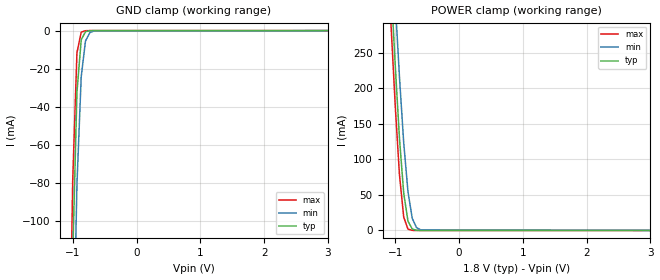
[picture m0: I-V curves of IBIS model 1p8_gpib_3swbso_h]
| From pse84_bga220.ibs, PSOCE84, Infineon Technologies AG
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[Model] 1p8_gpib_3swbso_h
Model_type Input
Vinl  =  0.54
Vinh  =  1.26
| Capacitance   typ   min   max
C_comp   6.99194e-13 6.84140e-13 7.17227e-13
| Variables   typ   min   max
[GND Clamp Reference]   0   0   0
[POWER Clamp Reference] 1.8   1.66   1.89
[Pulldown Reference]   0   0   0
[Pullup Reference]   1.8   1.66   1.89
[Temperature Range]   25   125   -40
[Voltage Range]   1.8   1.66   1.89
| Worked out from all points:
|   GND clamp passes 1 mA (typ) near -0.81 V on its own axis
|   POWER clamp passes 1 mA (typ) near -0.70 V on its own axis
[GND Clamp]
| Voltage   I(typ)   I(min)   I(max)
-1.271V   -777.1mA   -829.3mA   -749.6mA
-1.07V    -257.1mA   -325.7mA   -215.4mA
-1.003V   -118.8mA   -185.7mA   -78.49mA
-936.6mV  -32.29mA   -80.6mA    -11.59mA
-869.7mV  -4.869mA   -24.21mA   -835.1uA
-802.8mV  -582uA     -5.497mA   -52.94uA
-735.9mV  -66.76uA   -1.124mA   -3.324uA
-669mV    -7.618uA   -222.9uA   -208.7nA
3.6V      0A         0A         0A
[POWER Clamp]
| Voltage   I(typ)   I(min)   I(max)
-1.338V   832.1mA    908.1mA    786.4mA
-1.07V    347.5mA    436.2mA    291.6mA
-1.003V   233mA      322.8mA    176.2mA
-936.6mV  130.1mA    216.4mA    78.6mA
-869.7mV  52.48mA    123.5mA    18.89mA
-802.8mV  13.16mA    54.42mA    1.861mA
-735.9mV  2.014mA    17.13mA    126.6uA
-669mV    240.8uA    4.031mA    8.263uA
-602.1mV  27.35uA    812uA      536.8nA
3.6V      0A         0A         0A
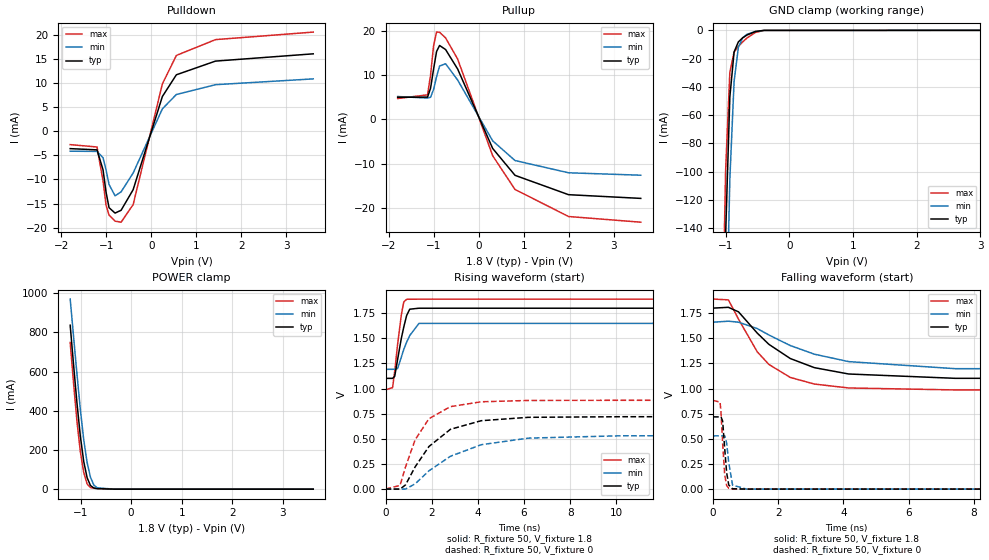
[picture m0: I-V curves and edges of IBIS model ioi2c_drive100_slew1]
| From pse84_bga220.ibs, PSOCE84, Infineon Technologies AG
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[Model] ioi2c_drive100_slew1
Model_type I/O
Enable   Active-High
Vinl  =  0.54
Vinh  =  1.26
Vmeas =  0.9
Cref  =  15e-12
| Capacitance   typ   min   max
C_comp   8.55364e-13 8.30808e-13 8.84570e-13
| Variables   typ   min   max
[GND Clamp Reference]   0   0   0
[POWER Clamp Reference]   1.8   1.66   1.89
[Pulldown Reference]   0   0   0
[Pullup Reference]   1.8   1.66   1.89
[Temperature Range]   25   125   -40
[Voltage Range]   1.8   1.66   1.89
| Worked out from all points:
|   slope of the pulldown table from 0 to 0.27 V, typ, clamps not added: 35.3 ohm
|   slope of the pullup table from 0 to 0.27 V, typ, clamps not added: 46.3 ohm
|   GND clamp passes 1 mA (typ) near -0.55 V on its own axis
|   POWER clamp passes 1 mA (typ) near -0.55 V on its own axis
|   falling waveform, R_fixture 50, V_fixture 1.8: 20-80 % time 1.72ns typ, 2.32ns min, 1.27ns max; typ from 1.8 V to 1.1 V
|   falling waveform, R_fixture 50, V_fixture 0: 20-80 % time 102ps typ, 118ps min, 94.2ps max; typ from 0.719 V to 0 V
|   rising waveform, R_fixture 50, V_fixture 1.8: 20-80 % time 348ps typ, 487ps min, 274ps max; typ from 1.1 V to 1.8 V
|   rising waveform, R_fixture 50, V_fixture 0: 20-80 % time 1.56ns typ, 2.35ns min, 1.1ns max; typ from 0 V to 0.719 V
[GND Clamp]
| Voltage   I(typ)   I(min)   I(max)
-1.204V   -750.5mA   -844.3mA   -692.2mA
-1.07V    -311.8mA   -416.8mA   -250.3mA
-1.003V   -144.6mA   -236.7mA   -99.35mA
-936.6mV  -47.15mA   -105.3mA   -29.57mA
-869.7mV  -15.32mA   -36.11mA   -15.4mA
-802.8mV  -8.178mA   -12.13mA   -11.32mA
-735.9mV  -5.345mA   -5.294mA   -8.218mA
-669mV    -3.361mA   -2.852mA   -5.471mA
-535.2mV  -838.5uA   -772.4uA   -1.486mA
-401.4mV  -47.36uA   -84.85uA   -76.78uA
3.6V      0A         0A         0A
[POWER Clamp]
| Voltage   I(typ)   I(min)   I(max)
-1.204V   837.3mA    970.7mA    749.2mA
-1.137V   634.9mA    778.2mA    540.5mA
-1.07V    440.1mA    587.4mA    346.5mA
-1.003V   270mA      407mA      190.9mA
-936.6mV  141.8mA    252.7mA    85.92mA
-869.7mV  58.74mA    136.5mA    26.66mA
-802.8mV  18.35mA    60.36mA    8.197mA
-735.9mV  5.885mA    21mA       4.755mA
-669mV    2.866mA    6.628mA    3.138mA
-334.5mV  12.31uA    45.7uA     5.857uA
3.6V      0A         0A         0A
[Pulldown]
| Voltage   I(typ)   I(min)   I(max)
-1.8V     -3.608mA   -4.143mA   -2.775mA
-1.204V   -3.867mA   -4.18mA    -3.269mA
-1.07V    -8mA       -5.505mA   -10.32mA
-1.003V   -12.65mA   -8.02mA    -15.35mA
-936.6mV  -15.86mA   -11.04mA   -17.4mA
-802.8mV  -16.98mA   -13.4mA    -18.65mA
-669mV    -16.4mA    -12.58mA   -18.87mA
-401.4mV  -12.13mA   -8.671mA   -15.23mA
248.3mV   7.209mA    4.643mA    9.816mA
558.6mV   11.71mA    7.622mA    15.72mA
1.428V    14.55mA    9.657mA    19.01mA
3.6V      16.06mA    10.86mA    20.57mA
[Pullup]
| Voltage   I(typ)   I(min)   I(max)
-1.8V     5.02mA     5.203mA    4.747mA
-1.137V   5.069mA    4.844mA    5.585mA
-1.07V    7.067mA    5.033mA    10.06mA
-1.003V   11.43mA    6.798mA    16.72mA
-936.6mV  15.41mA    9.704mA    19.82mA
-869.7mV  16.78mA    12.12mA    19.79mA
-735.9mV  15.86mA    12.64mA    18.49mA
-468.3mV  11.44mA    8.947mA    13.7mA
310.3mV   -6.586mA   -4.859mA   -8.233mA
806.9mV   -12.68mA   -9.32mA    -15.89mA
1.996V    -17.07mA   -12.1mA    -22.02mA
3.6V      -17.91mA   -12.65mA   -23.31mA
[Ramp]
dV/dt_r   0.431323/1.56487n  0.318021/2.34952n  0.529265/1.09605n
dV/dt_f   0.41961/1.72396n  0.28143/2.32368n  0.541744/1.26921n
R_load = 50
[Falling Waveform]
R_fixture = 50
V_fixture = 1.8
V_fixture_min = 1.66
V_fixture_max = 1.89
| Time   V(typ)   V(min)   V(max)
0s        1.8V       1.66V      1.89V
470.7ps   1.808V     1.67V      1.882V
781.4ps   1.763V     1.66V      1.69V
1.355ns   1.552V     1.597V     1.366V
1.713ns   1.44V      1.533V     1.24V
2.369ns   1.299V     1.428V     1.111V
3.11ns    1.208V     1.342V     1.045V
4.164ns   1.145V     1.268V     1.006V
7.432ns   1.102V     1.198V     986.6mV
800ns     1.101V     1.191V     987.1mV
[Falling Waveform]
R_fixture = 50
V_fixture = 0
V_fixture_min = 0
V_fixture_max = 0
| Time   V(typ)   V(min)   V(max)
0s        718.9mV    530mV      882.1mV
215.6ps   718.6mV    530mV      865.3mV
242.6ps   719mV      530mV      766.8mV
294.4ps   676.9mV    529.9mV    453.4mV
358.3ps   399.6mV    530.6mV    138.3mV
417.5ps   162.5mV    456.8mV    36.18mV
481.2ps   41.68mV    264.5mV    9.263mV
598.4ps   4.024mV    40.29mV    1.708mV
1.026ns   845.9uV    753.4uV    624.7uV
800ns     8.443nV    562.7nV    3.204nV
[Rising Waveform]
R_fixture = 50
V_fixture = 1.8
V_fixture_min = 1.66
V_fixture_max = 1.89
| Time   V(typ)   V(min)   V(max)
0s        1.101V     1.191V     987.1mV
305.5ps   1.101V     1.191V     1.009V
397.1ps   1.122V     1.191V     1.171V
521.6ps   1.288V     1.199V     1.438V
684.6ps   1.5V       1.313V     1.734V
789.3ps   1.611V     1.389V     1.862V
915.4ps   1.728V     1.462V     1.888V
1.048ns   1.789V     1.527V     1.888V
1.448ns   1.799V     1.648V     1.889V
800ns     1.8V       1.66V      1.89V
[Rising Waveform]
R_fixture = 50
V_fixture = 0
V_fixture_min = 0
V_fixture_max = 0
| Time   V(typ)   V(min)   V(max)
0s        8.444nV    562.4nV    3.204nV
628.8ps   -895.6uV   -1.322mV   35.62mV
865.3ps   41.36mV    -35.9uV    219.7mV
1.282ns   220.5mV    51.63mV    490.5mV
1.881ns   423.3mV    181.2mV    699.7mV
2.809ns   594.1mV    325.9mV    819.8mV
4.145ns   679.8mV    440.9mV    868.1mV
6.181ns   713.4mV    506.5mV    881.2mV
10.21ns   719.5mV    529.9mV    882.9mV
50ns      718.9mV    530mV      882.1mV
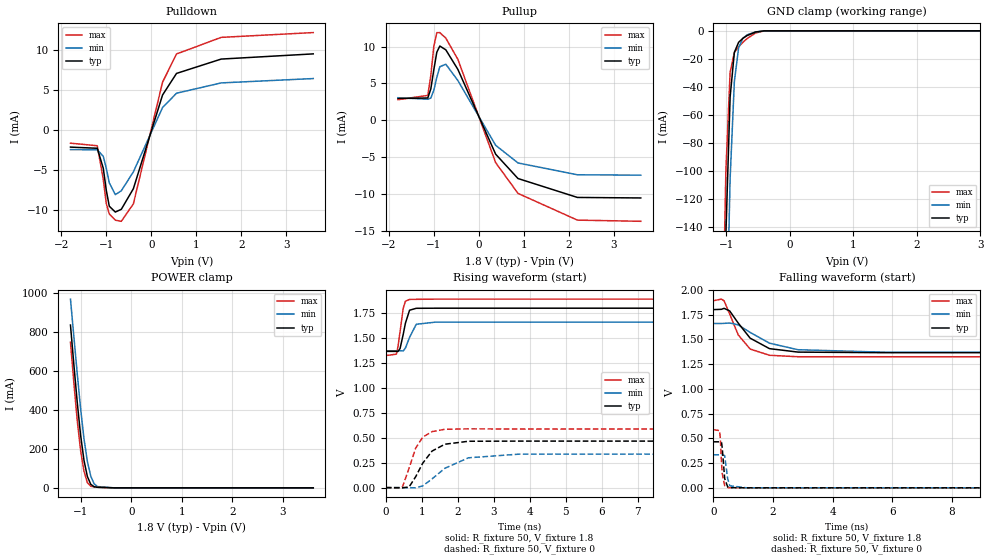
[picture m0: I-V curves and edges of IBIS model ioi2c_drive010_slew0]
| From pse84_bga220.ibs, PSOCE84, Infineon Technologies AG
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[Model] ioi2c_drive010_slew0
Model_type I/O
Enable   Active-High
Vinl  =  0.54
Vinh  =  1.26
Vmeas =  0.9
Cref  =  15e-12
| Capacitance   typ   min   max
C_comp   8.55364e-13 8.30808e-13 8.84570e-13
| Variables   typ   min   max
[GND Clamp Reference]   0   0   0
[POWER Clamp Reference]   1.8   1.66   1.89
[Pulldown Reference]   0   0   0
[Pullup Reference]   1.8   1.66   1.89
[Temperature Range]   25   125   -40
[Voltage Range]   1.8   1.66   1.89
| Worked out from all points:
|   slope of the pulldown table from 0 to 0.27 V, typ, clamps not added: 58.4 ohm
|   slope of the pullup table from 0 to 0.27 V, typ, clamps not added: 76.8 ohm
|   GND clamp passes 1 mA (typ) near -0.55 V on its own axis
|   POWER clamp passes 1 mA (typ) near -0.55 V on its own axis
|   falling waveform, R_fixture 50, V_fixture 1.8: 20-80 % time 778ps typ, 1.12ns min, 569ps max; typ from 1.8 V to 1.37 V
|   falling waveform, R_fixture 50, V_fixture 0: 20-80 % time 73.3ps typ, 82.5ps min, 68.5ps max; typ from 0.465 V to 0 V
|   rising waveform, R_fixture 50, V_fixture 1.8: 20-80 % time 150ps typ, 196ps min, 125ps max; typ from 1.37 V to 1.8 V
|   rising waveform, R_fixture 50, V_fixture 0: 20-80 % time 501ps typ, 796ps min, 356ps max; typ from 0 V to 0.465 V
[GND Clamp]
| Voltage   I(typ)   I(min)   I(max)
-1.204V   -750.5mA   -844.3mA   -692.2mA
-1.07V    -311.8mA   -416.8mA   -250.3mA
-1.003V   -144.6mA   -236.7mA   -99.35mA
-936.6mV  -47.15mA   -105.3mA   -29.57mA
-869.7mV  -15.32mA   -36.11mA   -15.4mA
-802.8mV  -8.178mA   -12.13mA   -11.32mA
-735.9mV  -5.345mA   -5.294mA   -8.218mA
-669mV    -3.361mA   -2.852mA   -5.471mA
-535.2mV  -838.5uA   -772.4uA   -1.486mA
-401.4mV  -47.36uA   -84.85uA   -76.78uA
3.6V      0A         0A         0A
[POWER Clamp]
| Voltage   I(typ)   I(min)   I(max)
-1.204V   837.3mA    970.7mA    749.2mA
-1.137V   634.9mA    778.2mA    540.5mA
-1.07V    440.1mA    587.4mA    346.5mA
-1.003V   270mA      407mA      190.9mA
-936.6mV  141.8mA    252.7mA    85.92mA
-869.7mV  58.74mA    136.5mA    26.66mA
-802.8mV  18.35mA    60.36mA    8.197mA
-735.9mV  5.885mA    21mA       4.755mA
-669mV    2.866mA    6.628mA    3.138mA
-334.5mV  12.31uA    45.7uA     5.857uA
3.6V      0A         0A         0A
[Pulldown]
| Voltage   I(typ)   I(min)   I(max)
-1.8V     -2.132mA   -2.444mA   -1.643mA
-1.204V   -2.279mA   -2.463mA   -1.96mA
-1.07V    -4.767mA   -3.283mA   -6.143mA
-1.003V   -7.525mA   -4.772mA   -9.15mA
-936.6mV  -9.492mA   -6.579mA   -10.45mA
-802.8mV  -10.22mA   -8.048mA   -11.23mA
-669mV    -9.874mA   -7.568mA   -11.37mA
-401.4mV  -7.319mA   -5.22mA    -9.208mA
248.3mV   4.356mA    2.795mA    5.95mA
558.6mV   7.043mA    4.577mA    9.465mA
1.552V    8.83mA     5.862mA    11.53mA
3.6V      9.476mA    6.404mA    12.13mA
[Pullup]
| Voltage   I(typ)   I(min)   I(max)
-1.8V     2.946mA    3.054mA    2.787mA
-1.137V   3.017mA    2.847mA    3.365mA
-1.07V    4.244mA    3.002mA    6.052mA
-1.003V   6.848mA    4.069mA    10.02mA
-936.6mV  9.232mA    5.804mA    11.89mA
-869.7mV  10.07mA    7.26mA     11.9mA
-735.9mV  9.553mA    7.601mA    11.14mA
-468.3mV  6.898mA    5.392mA    8.266mA
372.4mV   -4.617mA   -3.408mA   -5.769mA
869mV     -7.921mA   -5.806mA   -9.94mA
2.191V    -10.49mA   -7.414mA   -13.57mA
3.6V      -10.56mA   -7.462mA   -13.73mA
[Ramp]
dV/dt_r   0.279116/0.500541n  0.200595/0.796195n  0.352378/0.356306n
dV/dt_f   0.260514/0.777934n  0.172747/1.12479n  0.339364/0.569284n
R_load = 50
[Falling Waveform]
R_fixture = 50
V_fixture = 1.8
V_fixture_min = 1.66
V_fixture_max = 1.89
| Time   V(typ)   V(min)   V(max)
0s        1.8V       1.66V      1.89V
267.3ps   1.803V     1.66V      1.906V
359.2ps   1.813V     1.661V     1.889V
546ps     1.787V     1.665V     1.756V
833.4ps   1.664V     1.646V     1.545V
1.232ns   1.512V     1.57V      1.402V
1.881ns   1.406V     1.461V     1.339V
2.84ns    1.371V     1.395V     1.324V
5.742ns   1.365V     1.37V      1.324V
800ns     1.366V     1.372V     1.324V
[Falling Waveform]
R_fixture = 50
V_fixture = 0
V_fixture_min = 0
V_fixture_max = 0
| Time   V(typ)   V(min)   V(max)
0s        465.2mV    334.3mV    587.3mV
208.4ps   465.1mV    334.3mV    578.4mV
232.5ps   465mV      334.3mV    500.9mV
272.7ps   459mV      334.3mV    257mV
297.6ps   404mV      334.1mV    145.2mV
379.1ps   93.52mV    325.4mV    21.53mV
479.7ps   10.05mV    91.96mV    2.381mV
550.2ps   2.539mV    20.98mV    1.314mV
1.119ns   534.5uV    706.6uV    369.3uV
800ns     11.23nV    709.4nV    4.431nV
[Rising Waveform]
R_fixture = 50
V_fixture = 1.8
V_fixture_min = 1.66
V_fixture_max = 1.89
| Time   V(typ)   V(min)   V(max)
0s        1.366V     1.372V     1.324V
291.5ps   1.366V     1.372V     1.338V
337ps     1.365V     1.372V     1.413V
394.7ps   1.394V     1.372V     1.563V
482.5ps   1.537V     1.371V     1.798V
544ps     1.649V     1.4V       1.869V
659.2ps   1.779V     1.507V     1.887V
844.9ps   1.798V     1.638V     1.888V
1.372ns   1.799V     1.659V     1.89V
800ns     1.8V       1.66V      1.89V
[Rising Waveform]
R_fixture = 50
V_fixture = 0
V_fixture_min = 0
V_fixture_max = 0
| Time   V(typ)   V(min)   V(max)
0s        11.24nV    709.2nV    4.431nV
454.1ps   -2.613mV   220.8uV    -70.75uV
644.6ps   5.899mV    -2.007mV   194.2mV
828.9ps   109.3mV    -1.994mV   395.6mV
1.025ns   245.3mV    17.4mV     506.8mV
1.284ns   366.3mV    87.33mV    561.1mV
1.64ns    435.1mV    193.9mV    584.9mV
2.296ns   464.7mV    298.8mV    589.2mV
3.709ns   466.2mV    335.7mV    587.2mV
50ns      465.2mV    334.3mV    587.3mV
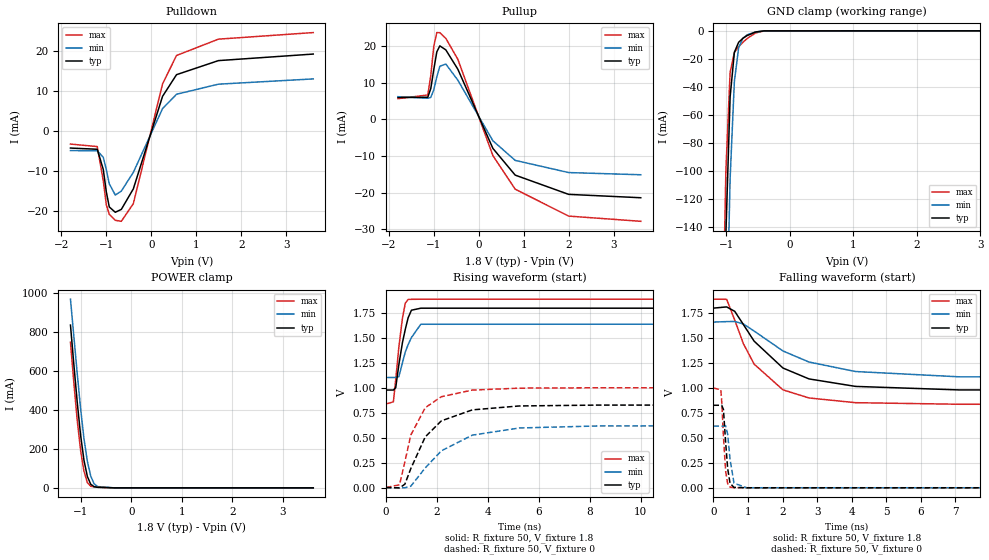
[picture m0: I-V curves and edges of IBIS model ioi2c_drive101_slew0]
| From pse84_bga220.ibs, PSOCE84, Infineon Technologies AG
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[Model] ioi2c_drive101_slew0
Model_type I/O
Enable   Active-High
Vinl  =  0.54
Vinh  =  1.26
Vmeas =  0.9
Cref  =  15e-12
| Capacitance   typ   min   max
C_comp   8.55364e-13 8.30808e-13 8.84570e-13
| Variables   typ   min   max
[GND Clamp Reference]   0   0   0
[POWER Clamp Reference]   1.8   1.66   1.89
[Pulldown Reference]   0   0   0
[Pullup Reference]   1.8   1.66   1.89
[Temperature Range]   25   125   -40
[Voltage Range]   1.8   1.66   1.89
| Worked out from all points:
|   slope of the pulldown table from 0 to 0.27 V, typ, clamps not added: 29.4 ohm
|   slope of the pullup table from 0 to 0.27 V, typ, clamps not added: 38.6 ohm
|   GND clamp passes 1 mA (typ) near -0.55 V on its own axis
|   POWER clamp passes 1 mA (typ) near -0.55 V on its own axis
|   falling waveform, R_fixture 50, V_fixture 1.8: 20-80 % time 1.48ns typ, 1.99ns min, 1.08ns max; typ from 1.8 V to 0.978 V
|   falling waveform, R_fixture 50, V_fixture 0: 20-80 % time 104ps typ, 119ps min, 95.7ps max; typ from 0.827 V to 0 V
|   rising waveform, R_fixture 50, V_fixture 1.8: 20-80 % time 340ps typ, 475ps min, 266ps max; typ from 0.978 V to 1.8 V
|   rising waveform, R_fixture 50, V_fixture 0: 20-80 % time 1.19ns typ, 1.69ns min, 833ps max; typ from 0 V to 0.827 V
[GND Clamp]
| Voltage   I(typ)   I(min)   I(max)
-1.204V   -750.5mA   -844.3mA   -692.2mA
-1.07V    -311.8mA   -416.8mA   -250.3mA
-1.003V   -144.6mA   -236.7mA   -99.35mA
-936.6mV  -47.15mA   -105.3mA   -29.57mA
-869.7mV  -15.32mA   -36.11mA   -15.4mA
-802.8mV  -8.178mA   -12.13mA   -11.32mA
-735.9mV  -5.345mA   -5.294mA   -8.218mA
-669mV    -3.361mA   -2.852mA   -5.471mA
-535.2mV  -838.5uA   -772.4uA   -1.486mA
-401.4mV  -47.36uA   -84.85uA   -76.78uA
3.6V      0A         0A         0A
[POWER Clamp]
| Voltage   I(typ)   I(min)   I(max)
-1.204V   837.3mA    970.7mA    749.2mA
-1.137V   634.9mA    778.2mA    540.5mA
-1.07V    440.1mA    587.4mA    346.5mA
-1.003V   270mA      407mA      190.9mA
-936.6mV  141.8mA    252.7mA    85.92mA
-869.7mV  58.74mA    136.5mA    26.66mA
-802.8mV  18.35mA    60.36mA    8.197mA
-735.9mV  5.885mA    21mA       4.755mA
-669mV    2.866mA    6.628mA    3.138mA
-334.5mV  12.31uA    45.7uA     5.857uA
3.6V      0A         0A         0A
[Pulldown]
| Voltage   I(typ)   I(min)   I(max)
-1.8V     -4.313mA   -4.952mA   -3.319mA
-1.204V   -4.62mA    -4.994mA   -3.945mA
-1.07V    -9.684mA   -6.635mA   -12.52mA
-1.003V   -15.27mA   -9.668mA   -18.47mA
-936.6mV  -19.06mA   -13.28mA   -20.91mA
-802.8mV  -20.39mA   -16.08mA   -22.4mA
-669mV    -19.67mA   -15.09mA   -22.65mA
-401.4mV  -14.52mA   -10.39mA   -18.23mA
248.3mV   8.629mA    5.565mA    11.75mA
558.6mV   14.05mA    9.146mA    18.85mA
1.49V     17.57mA    11.67mA    22.94mA
3.6V      19.21mA    12.99mA    24.59mA
[Pullup]
| Voltage   I(typ)   I(min)   I(max)
-1.8V     6.006mA    6.225mA    5.68mA
-1.137V   6.075mA    5.796mA    6.701mA
-1.07V    8.479mA    6.033mA    12.08mA
-1.003V   13.71mA    8.152mA    20.05mA
-936.6mV  18.47mA    11.64mA    23.75mA
-869.7mV  20.11mA    14.53mA    23.72mA
-735.9mV  19.02mA    15.15mA    22.17mA
-468.3mV  13.72mA    10.73mA    16.43mA
310.3mV   -7.896mA   -5.827mA   -9.87mA
806.9mV   -15.21mA   -11.18mA   -19.05mA
1.996V    -20.47mA   -14.51mA   -26.41mA
3.6V      -21.39mA   -15.11mA   -27.83mA
[Ramp]
dV/dt_r   0.496329/1.18642n  0.371382/1.69196n  0.599967/0.83335n
dV/dt_f   0.493097/1.48078n  0.333342/1.98689n  0.631402/1.07999n
R_load = 50
[Falling Waveform]
R_fixture = 50
V_fixture = 1.8
V_fixture_min = 1.66
V_fixture_max = 1.89
| Time   V(typ)   V(min)   V(max)
0s        1.8V       1.66V      1.89V
383.8ps   1.812V     1.665V     1.888V
617.5ps   1.768V     1.666V     1.681V
869.2ps   1.635V     1.641V     1.443V
1.179ns   1.469V     1.57V      1.239V
2.012ns   1.2V       1.371V     981.6mV
2.765ns   1.091V     1.26V      900.2mV
4.111ns   1.016V     1.165V     853mV
7.11ns    980.7mV    1.112V     837.2mV
800ns     978.2mV    1.104V     837.7mV
[Falling Waveform]
R_fixture = 50
V_fixture = 0
V_fixture_min = 0
V_fixture_max = 0
| Time   V(typ)   V(min)   V(max)
0s        827.2mV    619mV      999.9mV
215ps     827mV      619mV      982.6mV
240.1ps   827.3mV    619mV      874.8mV
291.2ps   786mV      618.9mV    514.9mV
355ps     455.1mV    620.3mV    166.3mV
413.3ps   194.8mV    537.9mV    42.4mV
482.1ps   46.06mV    286.9mV    8.046mV
596.6ps   4.798mV    46.85mV    1.729mV
965.3ps   1.013mV    1.148mV    678.8uV
800ns     7.509nV    510nV      2.81nV
[Rising Waveform]
R_fixture = 50
V_fixture = 1.8
V_fixture_min = 1.66
V_fixture_max = 1.89
| Time   V(typ)   V(min)   V(max)
0s        978.2mV    1.104V     837.7mV
297.1ps   978.4mV    1.104V     860.1mV
387.6ps   1.002V     1.105V     1.084V
510.2ps   1.232V     1.112V     1.407V
652.4ps   1.455V     1.253V     1.7V
764.3ps   1.588V     1.361V     1.85V
875ps     1.703V     1.434V     1.887V
1.005ns   1.779V     1.505V     1.888V
1.373ns   1.799V     1.638V     1.889V
800ns     1.8V       1.66V      1.89V
[Rising Waveform]
R_fixture = 50
V_fixture = 0
V_fixture_min = 0
V_fixture_max = 0
| Time   V(typ)   V(min)   V(max)
0s        7.51nV     509.8nV    2.812nV
538.1ps   -2.813mV   -1.349mV   28.66mV
746.5ps   33.87mV    -2.094mV   257.5mV
981.5ps   191.1mV    13.99mV    527.8mV
1.547ns   508.5mV    197.3mV    801.1mV
2.179ns   669.3mV    368.6mV    911.5mV
3.393ns   779.2mV    525.9mV    977.7mV
5.242ns   818.6mV    597.7mV    997.3mV
8.334ns   827.3mV    618mV      1.001V
50ns      827.2mV    619mV      999.9mV
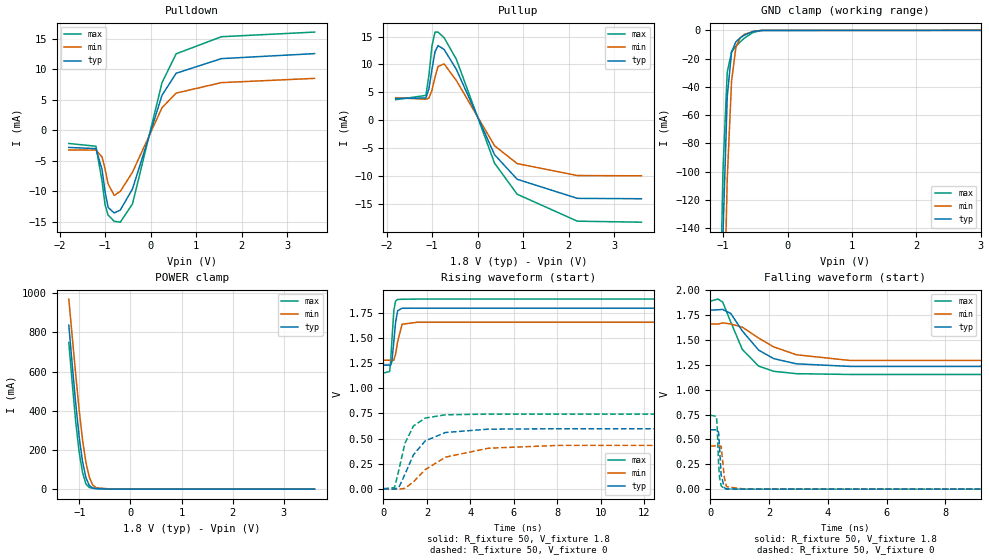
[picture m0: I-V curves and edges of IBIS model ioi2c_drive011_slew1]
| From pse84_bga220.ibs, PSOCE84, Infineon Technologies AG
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[Model] ioi2c_drive011_slew1
Model_type I/O
Enable   Active-High
Vinl  =  0.54
Vinh  =  1.26
Vmeas =  0.9
Cref  =  15e-12
| Capacitance   typ   min   max
C_comp   8.55364e-13 8.30808e-13 8.84570e-13
| Variables   typ   min   max
[GND Clamp Reference]   0   0   0
[POWER Clamp Reference]   1.8   1.66   1.89
[Pulldown Reference]   0   0   0
[Pullup Reference]   1.8   1.66   1.89
[Temperature Range]   25   125   -40
[Voltage Range]   1.8   1.66   1.89
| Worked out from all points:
|   slope of the pulldown table from 0 to 0.27 V, typ, clamps not added: 44.3 ohm
|   slope of the pullup table from 0 to 0.27 V, typ, clamps not added: 57.9 ohm
|   GND clamp passes 1 mA (typ) near -0.55 V on its own axis
|   POWER clamp passes 1 mA (typ) near -0.55 V on its own axis
|   falling waveform, R_fixture 50, V_fixture 1.8: 20-80 % time 1.03ns typ, 1.52ns min, 736ps max; typ from 1.8 V to 1.23 V
|   falling waveform, R_fixture 50, V_fixture 0: 20-80 % time 72.6ps typ, 81.5ps min, 67.9ps max; typ from 0.597 V to 0 V
|   rising waveform, R_fixture 50, V_fixture 1.8: 20-80 % time 146ps typ, 190ps min, 125ps max; typ from 1.23 V to 1.8 V
|   rising waveform, R_fixture 50, V_fixture 0: 20-80 % time 980ps typ, 1.85ns min, 600ps max; typ from 0 V to 0.597 V
[GND Clamp]
| Voltage   I(typ)   I(min)   I(max)
-1.204V   -750.5mA   -844.3mA   -692.2mA
-1.07V    -311.8mA   -416.8mA   -250.3mA
-1.003V   -144.6mA   -236.7mA   -99.35mA
-936.6mV  -47.15mA   -105.3mA   -29.57mA
-869.7mV  -15.32mA   -36.11mA   -15.4mA
-802.8mV  -8.178mA   -12.13mA   -11.32mA
-735.9mV  -5.345mA   -5.294mA   -8.218mA
-669mV    -3.361mA   -2.852mA   -5.471mA
-535.2mV  -838.5uA   -772.4uA   -1.486mA
-401.4mV  -47.36uA   -84.85uA   -76.78uA
3.6V      0A         0A         0A
[POWER Clamp]
| Voltage   I(typ)   I(min)   I(max)
-1.204V   837.3mA    970.7mA    749.2mA
-1.137V   634.9mA    778.2mA    540.5mA
-1.07V    440.1mA    587.4mA    346.5mA
-1.003V   270mA      407mA      190.9mA
-936.6mV  141.8mA    252.7mA    85.92mA
-869.7mV  58.74mA    136.5mA    26.66mA
-802.8mV  18.35mA    60.36mA    8.197mA
-735.9mV  5.885mA    21mA       4.755mA
-669mV    2.866mA    6.628mA    3.138mA
-334.5mV  12.31uA    45.7uA     5.857uA
3.6V      0A         0A         0A
[Pulldown]
| Voltage   I(typ)   I(min)   I(max)
-1.8V     -2.834mA   -3.249mA   -2.184mA
-1.204V   -3.027mA   -3.272mA   -2.632mA
-1.07V    -6.438mA   -4.404mA   -8.33mA
-1.003V   -10.12mA   -6.406mA   -12.25mA
-936.6mV  -12.66mA   -8.803mA   -13.93mA
-802.8mV  -13.58mA   -10.7mA    -14.94mA
-669mV    -13.1mA    -10.04mA   -15.09mA
-401.4mV  -9.649mA   -6.904mA   -12.11mA
248.3mV   5.731mA    3.696mA    7.795mA
558.6mV   9.329mA    6.074mA    12.52mA
1.552V    11.73mA    7.791mA    15.32mA
3.6V      12.55mA    8.493mA    16.08mA
[Pullup]
| Voltage   I(typ)   I(min)   I(max)
-1.8V     3.924mA    4.071mA    3.712mA
-1.137V   4.014mA    3.792mA    4.472mA
-1.07V    5.645mA    3.994mA    8.049mA
-1.003V   9.11mA     5.415mA    13.32mA
-936.6mV  12.27mA    7.722mA    15.78mA
-869.7mV  13.38mA    9.652mA    15.79mA
-735.9mV  12.68mA    10.1mA     14.78mA
-468.3mV  9.148mA    7.158mA    10.95mA
372.4mV   -6.121mA   -4.523mA   -7.639mA
869mV     -10.51mA   -7.709mA   -13.18mA
2.191V    -13.92mA   -9.84mA    -18mA
3.6V      -13.99mA   -9.896mA   -18.18mA
[Ramp]
dV/dt_r   0.35829/0.980001n  0.260722/1.85153n  0.446045/0.6003n
dV/dt_f   0.340724/1.02582n  0.227119/1.52121n  0.442328/0.735539n
R_load = 50
[Falling Waveform]
R_fixture = 50
V_fixture = 1.8
V_fixture_min = 1.66
V_fixture_max = 1.89
| Time   V(typ)   V(min)   V(max)
0s        1.8V       1.66V      1.89V
264ps     1.803V     1.66V      1.911V
421.8ps   1.807V     1.672V     1.881V
697.6ps   1.766V     1.66V      1.68V
1.089ns   1.591V     1.629V     1.405V
1.645ns   1.398V     1.519V     1.237V
2.158ns   1.312V     1.43V      1.185V
2.932ns   1.26V      1.351V     1.161V
4.749ns   1.234V     1.294V     1.153V
800ns     1.232V     1.281V     1.153V
[Falling Waveform]
R_fixture = 50
V_fixture = 0
V_fixture_min = 0
V_fixture_max = 0
| Time   V(typ)   V(min)   V(max)
0s        597.2mV    434.5mV    743.4mV
209.6ps   597mV      434.5mV    731.7mV
231.4ps   596.9mV    434.5mV    642.3mV
283.6ps   569.1mV    434.5mV    251.3mV
317.8ps   406.9mV    434.3mV    113.7mV
370.2ps   143.3mV    431.2mV    33.6mV
481.5ps   12.69mV    111.1mV    3.122mV
551.2ps   2.875mV    25.53mV    1.813mV
1.15ns    733.9uV    853.8uV    516.7uV
800ns     9.706nV    629.8nV    3.759nV
[Rising Waveform]
R_fixture = 50
V_fixture = 1.8
V_fixture_min = 1.66
V_fixture_max = 1.89
| Time   V(typ)   V(min)   V(max)
0s        1.232V     1.281V     1.153V
287.7ps   1.232V     1.281V     1.168V
332.9ps   1.231V     1.281V     1.27V
391.5ps   1.269V     1.282V     1.482V
479.6ps   1.469V     1.281V     1.773V
561.1ps   1.659V     1.343V     1.871V
655.6ps   1.774V     1.468V     1.886V
856.3ps   1.798V     1.639V     1.888V
1.554ns   1.799V     1.659V     1.89V
800ns     1.8V       1.66V      1.89V
[Rising Waveform]
R_fixture = 50
V_fixture = 0
V_fixture_min = 0
V_fixture_max = 0
| Time   V(typ)   V(min)   V(max)
0s        9.708nV    629.6nV    3.759nV
514.9ps   -3.974mV   -1.482mV   12.66mV
716.3ps   15.28mV    -2.904mV   193.4mV
990ps     144.4mV    4.38mV     452.1mV
1.384ns   338.8mV    70.12mV    626.6mV
1.925ns   477.7mV    191mV      704.7mV
2.859ns   560.8mV    315.1mV    737.1mV
4.814ns   593.7mV    403.7mV    743.7mV
8.021ns   597.9mV    431.9mV    743.6mV
50ns      597.2mV    434.5mV    743.4mV
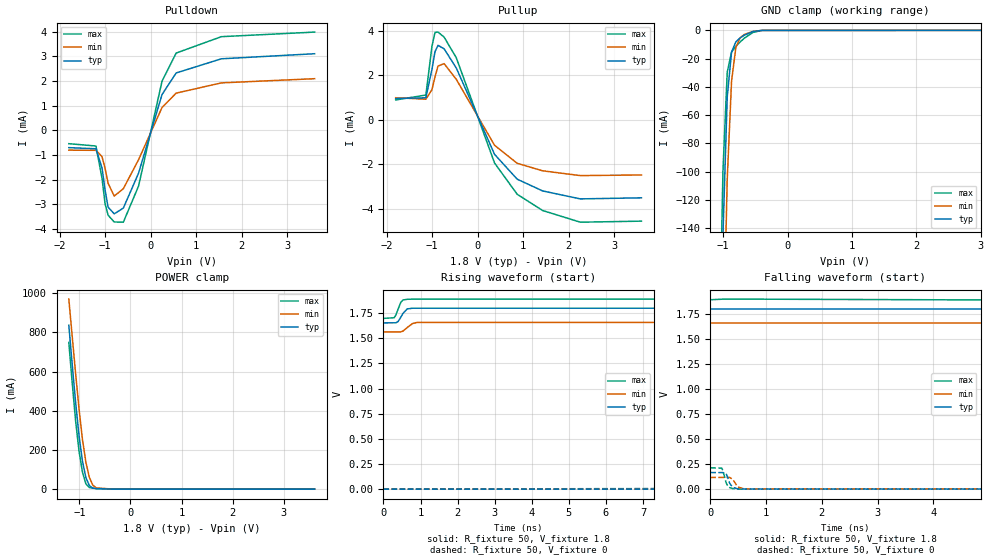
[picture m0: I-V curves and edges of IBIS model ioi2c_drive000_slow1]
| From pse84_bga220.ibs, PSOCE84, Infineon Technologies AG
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[Model] ioi2c_drive000_slow1
Model_type I/O
Enable   Active-High
Vinl  =  0.54
Vinh  =  1.26
Vmeas =  0.9
Cref  =  15e-12
| Capacitance   typ   min   max
C_comp   8.55364e-13 8.30808e-13 8.84570e-13
| Variables   typ   min   max
[GND Clamp Reference]   0   0   0
[POWER Clamp Reference]   1.8   1.66   1.89
[Pulldown Reference]   0   0   0
[Pullup Reference]   1.8   1.66   1.89
[Temperature Range]   25   125   -40
[Voltage Range]   1.8   1.66   1.89
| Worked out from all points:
|   slope of the pulldown table from 0 to 0.27 V, typ, clamps not added: 175 ohm
|   slope of the pullup table from 0 to 0.27 V, typ, clamps not added: 227 ohm
|   GND clamp passes 1 mA (typ) near -0.55 V on its own axis
|   POWER clamp passes 1 mA (typ) near -0.55 V on its own axis
|   falling waveform, R_fixture 50, V_fixture 1.8: 20-80 % time 55ns typ, 86.5ns min, 30.9ns max; typ from 1.8 V to 1.65 V
|   falling waveform, R_fixture 50, V_fixture 0: 20-80 % time 71.3ps typ, 79.5ps min, 67ps max; typ from 0.166 V to 0 V
|   rising waveform, R_fixture 50, V_fixture 1.8: 20-80 % time 142ps typ, 188ps min, 121ps max; typ from 1.65 V to 1.8 V
|   rising waveform, R_fixture 50, V_fixture 0: 20-80 % time 58.9ns typ, 89.7ns min, 35.5ns max; typ from 0 V to 0.166 V
[GND Clamp]
| Voltage   I(typ)   I(min)   I(max)
-1.204V   -750.5mA   -844.3mA   -692.2mA
-1.07V    -311.8mA   -416.8mA   -250.3mA
-1.003V   -144.6mA   -236.7mA   -99.35mA
-936.6mV  -47.15mA   -105.3mA   -29.57mA
-869.7mV  -15.32mA   -36.11mA   -15.4mA
-802.8mV  -8.178mA   -12.13mA   -11.32mA
-735.9mV  -5.345mA   -5.294mA   -8.218mA
-669mV    -3.361mA   -2.852mA   -5.471mA
-535.2mV  -838.5uA   -772.4uA   -1.486mA
-401.4mV  -47.36uA   -84.85uA   -76.78uA
3.6V      0A         0A         0A
[POWER Clamp]
| Voltage   I(typ)   I(min)   I(max)
-1.204V   837.3mA    970.7mA    749.2mA
-1.137V   634.9mA    778.2mA    540.5mA
-1.07V    440.1mA    587.4mA    346.5mA
-1.003V   270mA      407mA      190.9mA
-936.6mV  141.8mA    252.7mA    85.92mA
-869.7mV  58.74mA    136.5mA    26.66mA
-802.8mV  18.35mA    60.36mA    8.197mA
-735.9mV  5.885mA    21mA       4.755mA
-669mV    2.866mA    6.628mA    3.138mA
-334.5mV  12.31uA    45.7uA     5.857uA
3.6V      0A         0A         0A
[Pulldown]
| Voltage   I(typ)   I(min)   I(max)
-1.8V     -704uA     -806.1uA   -543.3uA
-1.204V   -749.6uA   -812.1uA   -637.7uA
-1.07V    -1.531mA   -1.07mA    -1.954mA
-1.003V   -2.433mA   -1.55mA    -2.984mA
-936.6mV  -3.123mA   -2.151mA   -3.449mA
-802.8mV  -3.392mA   -2.671mA   -3.723mA
-602.1mV  -3.16mA    -2.372mA   -3.732mA
-267.6mV  -1.741mA   -1.195mA   -2.265mA
248.3mV   1.454mA    928.1uA    1.997mA
558.6mV   2.33mA     1.51mA     3.138mA
1.552V    2.905mA    1.927mA    3.804mA
3.6V      3.111mA    2.097mA    3.99mA
[Pullup]
| Voltage   I(typ)   I(min)   I(max)
-1.8V     949.2uA    986.3uA    886.7uA
-1.137V   983.4uA    919.3uA    1.107mA
-1.003V   2.262mA    1.348mA    3.293mA
-936.6mV  3.054mA    1.921mA    3.916mA
-869.7mV  3.338mA    2.409mA    3.933mA
-735.9mV  3.183mA    2.516mA    3.707mA
-468.3mV  2.319mA    1.811mA    2.778mA
372.4mV   -1.557mA   -1.149mA   -1.944mA
869mV     -2.67mA    -1.957mA   -3.348mA
1.428V    -3.198mA   -2.295mA   -4.077mA
2.256V    -3.556mA   -2.51mA    -4.602mA
3.6V      -3.508mA   -2.482mA   -4.555mA
[Ramp]
dV/dt_r   99.4325m/58.9014n  70.0902m/89.7403n  0.128322/35.4739n
dV/dt_f   87.9619m/54.9725n  57.847m/86.4879n  0.115303/30.9007n
R_load = 50
[Falling Waveform]
R_fixture = 50
V_fixture = 1.8
V_fixture_min = 1.66
V_fixture_max = 1.89
| Time   V(typ)   V(min)   V(max)
0s        1.8V       1.66V      1.89V
264ps     1.8V       1.66V      1.897V
8.802ns   1.8V       1.66V      1.881V
26.26ns   1.77V      1.656V     1.787V
39.61ns   1.739V     1.645V     1.746V
56.42ns   1.709V     1.628V     1.721V
89.85ns   1.677V     1.601V     1.703V
150.2ns   1.658V     1.577V     1.698V
233.7ns   1.654V     1.567V     1.698V
800ns     1.653V     1.564V     1.698V
[Falling Waveform]
R_fixture = 50
V_fixture = 0
V_fixture_min = 0
V_fixture_max = 0
| Time   V(typ)   V(min)   V(max)
0s        165.7mV    116.8mV    213.9mV
206.8ps   165.6mV    116.8mV    209.4mV
229.2ps   165.4mV    116.8mV    182.2mV
282ps     156.5mV    116.8mV    66.58mV
310.9ps   119.3mV    116.6mV    34.88mV
347.7ps   58.65mV    116.7mV    15.87mV
402.6ps   17.98mV    98.52mV    5.52mV
490.5ps   3.536mV    22.21mV    1.559mV
605.7ps   989.4uV    2.593mV    730uV
800ns     17.02nV    964.2nV    7.332nV
[Rising Waveform]
R_fixture = 50
V_fixture = 1.8
V_fixture_min = 1.66
V_fixture_max = 1.89
| Time   V(typ)   V(min)   V(max)
0s        1.653V     1.564V     1.698V
288.1ps   1.654V     1.564V     1.704V
331.1ps   1.654V     1.564V     1.728V
389.5ps   1.664V     1.564V     1.783V
469.4ps   1.709V     1.564V     1.858V
524.9ps   1.746V     1.571V     1.88V
642.1ps   1.792V     1.607V     1.888V
787.6ps   1.799V     1.647V     1.889V
910.9ps   1.799V     1.658V     1.889V
800ns     1.8V       1.66V      1.89V
[Rising Waveform]
R_fixture = 50
V_fixture = 0
V_fixture_min = 0
V_fixture_max = 0
| Time   V(typ)   V(min)   V(max)
0s        17.02nV    963.9nV    7.332nV
8.887ns   -161.3uV   -290.7uV   6.892mV
15.02ns   5.021mV    296.4uV    40.19mV
28.5ns    37.63mV    8.853mV    109.4mV
42.82ns   72.35mV    24.68mV    155mV
62.31ns   106.9mV    46.7mV     187mV
95.74ns   139.8mV    75.14mV    206.9mV
156.1ns   159.8mV    101.2mV    213.3mV
248.1ns   165.1mV    113.4mV    213.9mV
800ns     165.7mV    116.8mV    213.9mV
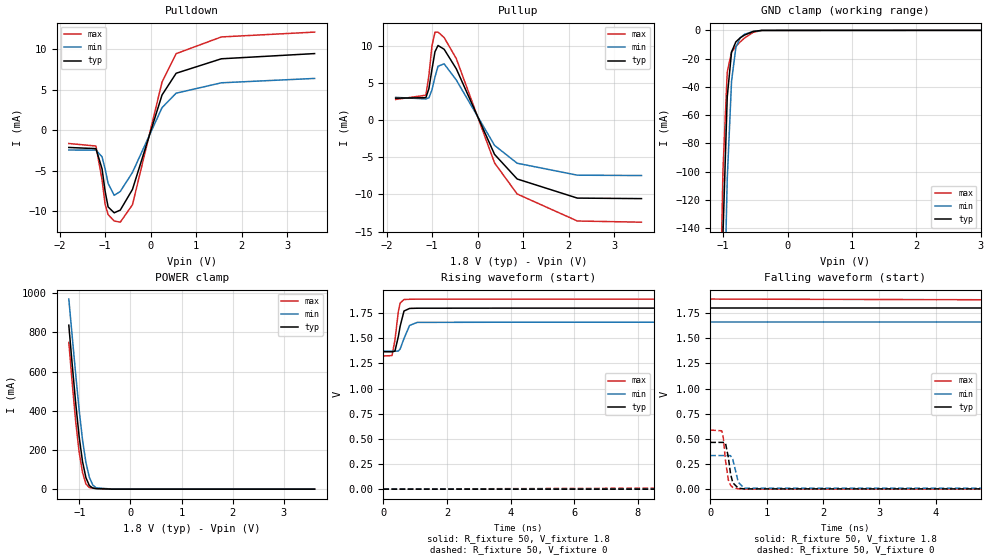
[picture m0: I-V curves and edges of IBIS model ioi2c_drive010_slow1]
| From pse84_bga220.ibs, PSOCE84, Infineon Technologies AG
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[Model] ioi2c_drive010_slow1
Model_type I/O
Enable   Active-High
Vinl  =  0.54
Vinh  =  1.26
Vmeas =  0.9
Cref  =  15e-12
| Capacitance   typ   min   max
C_comp   8.55364e-13 8.30808e-13 8.84570e-13
| Variables   typ   min   max
[GND Clamp Reference]   0   0   0
[POWER Clamp Reference]   1.8   1.66   1.89
[Pulldown Reference]   0   0   0
[Pullup Reference]   1.8   1.66   1.89
[Temperature Range]   25   125   -40
[Voltage Range]   1.8   1.66   1.89
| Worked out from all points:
|   slope of the pulldown table from 0 to 0.27 V, typ, clamps not added: 58.4 ohm
|   slope of the pullup table from 0 to 0.27 V, typ, clamps not added: 76.8 ohm
|   GND clamp passes 1 mA (typ) near -0.55 V on its own axis
|   POWER clamp passes 1 mA (typ) near -0.55 V on its own axis
|   falling waveform, R_fixture 50, V_fixture 1.8: 20-80 % time 71.7ns typ, 108ns min, 41.9ns max; typ from 1.8 V to 1.37 V
|   falling waveform, R_fixture 50, V_fixture 0: 20-80 % time 75.4ps typ, 85.3ps min, 70.3ps max; typ from 0.465 V to 0 V
|   rising waveform, R_fixture 50, V_fixture 1.8: 20-80 % time 155ps typ, 203ps min, 131ps max; typ from 1.37 V to 1.8 V
|   rising waveform, R_fixture 50, V_fixture 0: 20-80 % time 78.2ns typ, 116ns min, 48.2ns max; typ from 0 V to 0.465 V
[GND Clamp]
| Voltage   I(typ)   I(min)   I(max)
-1.204V   -750.5mA   -844.3mA   -692.2mA
-1.07V    -311.8mA   -416.8mA   -250.3mA
-1.003V   -144.6mA   -236.7mA   -99.35mA
-936.6mV  -47.15mA   -105.3mA   -29.57mA
-869.7mV  -15.32mA   -36.11mA   -15.4mA
-802.8mV  -8.178mA   -12.13mA   -11.32mA
-735.9mV  -5.345mA   -5.294mA   -8.218mA
-669mV    -3.361mA   -2.852mA   -5.471mA
-535.2mV  -838.5uA   -772.4uA   -1.486mA
-401.4mV  -47.36uA   -84.85uA   -76.78uA
3.6V      0A         0A         0A
[POWER Clamp]
| Voltage   I(typ)   I(min)   I(max)
-1.204V   837.3mA    970.7mA    749.2mA
-1.137V   634.9mA    778.2mA    540.5mA
-1.07V    440.1mA    587.4mA    346.5mA
-1.003V   270mA      407mA      190.9mA
-936.6mV  141.8mA    252.7mA    85.92mA
-869.7mV  58.74mA    136.5mA    26.66mA
-802.8mV  18.35mA    60.36mA    8.197mA
-735.9mV  5.885mA    21mA       4.755mA
-669mV    2.866mA    6.628mA    3.138mA
-334.5mV  12.31uA    45.7uA     5.857uA
3.6V      0A         0A         0A
[Pulldown]
| Voltage   I(typ)   I(min)   I(max)
-1.8V     -2.132mA   -2.446mA   -1.643mA
-1.204V   -2.278mA   -2.465mA   -1.955mA
-1.07V    -4.765mA   -3.284mA   -6.132mA
-1.003V   -7.521mA   -4.773mA   -9.136mA
-936.6mV  -9.486mA   -6.58mA    -10.43mA
-802.8mV  -10.21mA   -8.047mA   -11.22mA
-669mV    -9.873mA   -7.567mA   -11.37mA
-401.4mV  -7.319mA   -5.22mA    -9.208mA
248.3mV   4.356mA    2.795mA    5.95mA
558.6mV   7.043mA    4.577mA    9.465mA
1.552V    8.83mA     5.862mA    11.53mA
3.6V      9.473mA    6.401mA    12.13mA
[Pullup]
| Voltage   I(typ)   I(min)   I(max)
-1.8V     2.944mA    3.052mA    2.776mA
-1.137V   3.008mA    2.844mA    3.342mA
-1.07V    4.227mA    2.998mA    6.015mA
-1.003V   6.824mA    4.061mA    9.967mA
-936.6mV  9.198mA    5.79mA     11.82mA
-869.7mV  10.03mA    7.241mA    11.83mA
-735.9mV  9.523mA    7.561mA    11.1mA
-468.3mV  6.894mA    5.386mA    8.26mA
372.4mV   -4.616mA   -3.405mA   -5.764mA
869mV     -7.921mA   -5.802mA   -9.94mA
2.191V    -10.49mA   -7.408mA   -13.57mA
3.6V      -10.56mA   -7.456mA   -13.73mA
[Ramp]
dV/dt_r   0.279111/78.1782n  0.200422/0.115631u  0.352376/48.1605n
dV/dt_f   0.260511/71.6982n  0.172717/0.108059u  0.339362/41.8673n
R_load = 50
[Falling Waveform]
R_fixture = 50
V_fixture = 1.8
V_fixture_min = 1.66
V_fixture_max = 1.89
| Time   V(typ)   V(min)   V(max)
0s        1.8V       1.66V      1.89V
8.487ns   1.8V       1.66V      1.878V
16.66ns   1.787V     1.66V      1.777V
32.9ns    1.699V     1.64V      1.593V
51.36ns   1.603V     1.597V     1.468V
76.43ns   1.511V     1.539V     1.386V
109.9ns   1.44V      1.48V      1.345V
171.4ns   1.388V     1.42V      1.327V
280.1ns   1.369V     1.383V     1.324V
800ns     1.366V     1.372V     1.324V
[Falling Waveform]
R_fixture = 50
V_fixture = 0
V_fixture_min = 0
V_fixture_max = 0
| Time   V(typ)   V(min)   V(max)
0s        465.2mV    334.1mV    587.3mV
205.2ps   465.1mV    334.1mV    580.3mV
231.4ps   464.9mV    334.1mV    508.1mV
268.9ps   460.4mV    334.1mV    289.6mV
319.6ps   319.1mV    333.9mV    93.57mV
360.2ps   150.6mV    332.9mV    39.03mV
399.5ps   64.18mV    296mV      17.59mV
496.6ps   9.913mV    69.33mV    3.368mV
599.5ps   2.718mV    9.317mV    1.404mV
800ns     11.32nV    710nV      4.496nV
[Rising Waveform]
R_fixture = 50
V_fixture = 1.8
V_fixture_min = 1.66
V_fixture_max = 1.89
| Time   V(typ)   V(min)   V(max)
0s        1.366V     1.372V     1.324V
270.9ps   1.366V     1.372V     1.328V
362.5ps   1.372V     1.372V     1.481V
469.4ps   1.517V     1.373V     1.764V
526ps     1.619V     1.393V     1.85V
647.9ps   1.771V     1.498V     1.885V
824.6ps   1.797V     1.628V     1.888V
1.063ns   1.799V     1.658V     1.889V
4.144ns   1.8V       1.66V      1.889V
800ns     1.8V       1.66V      1.89V
[Rising Waveform]
R_fixture = 50
V_fixture = 0
V_fixture_min = 0
V_fixture_max = 0
| Time   V(typ)   V(min)   V(max)
0s        11.31nV    709.3nV    4.491nV
9.751ns   -156.1uV   -229.2uV   11.49mV
18.49ns   17.95mV    1.711mV    107.7mV
33.38ns   98.39mV    25.05mV    269.3mV
57.12ns   219.4mV    87.75mV    429.2mV
80.47ns   304.3mV    145.2mV    507.6mV
122.3ns   390mV      220.4mV    563.3mV
192.1ns   443.7mV    286.4mV    583.9mV
292.4ns   461.5mV    320.3mV    587.1mV
800ns     465.2mV    334mV      587.3mV
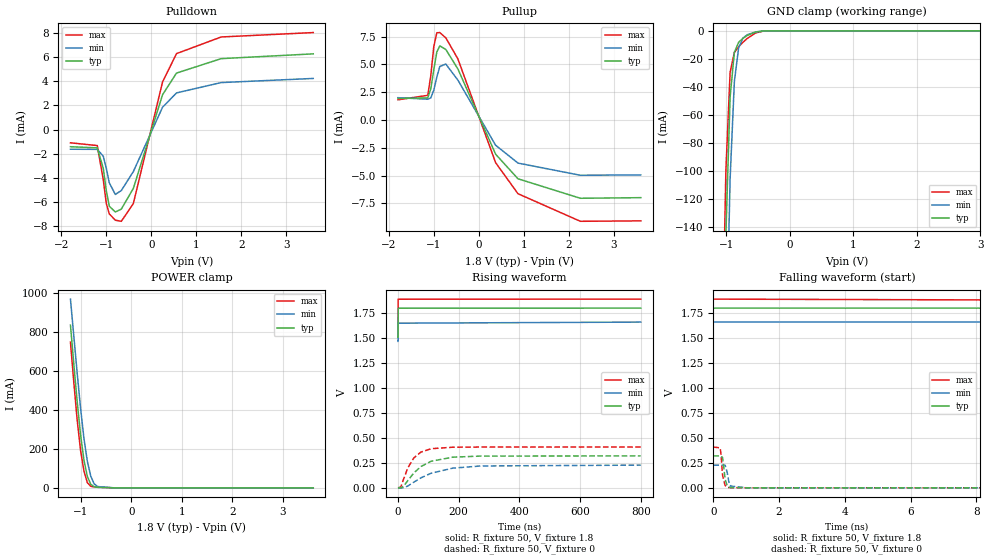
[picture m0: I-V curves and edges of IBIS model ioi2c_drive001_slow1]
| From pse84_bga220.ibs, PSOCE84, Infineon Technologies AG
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[Model] ioi2c_drive001_slow1
Model_type I/O
Enable   Active-High
Vinl  =  0.54
Vinh  =  1.26
Vmeas =  0.9
Cref  =  15e-12
| Capacitance   typ   min   max
C_comp   8.55364e-13 8.30808e-13 8.84570e-13
| Variables   typ   min   max
[GND Clamp Reference]   0   0   0
[POWER Clamp Reference]   1.8   1.66   1.89
[Pulldown Reference]   0   0   0
[Pullup Reference]   1.8   1.66   1.89
[Temperature Range]   25   125   -40
[Voltage Range]   1.8   1.66   1.89
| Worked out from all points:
|   slope of the pulldown table from 0 to 0.27 V, typ, clamps not added: 88 ohm
|   slope of the pullup table from 0 to 0.27 V, typ, clamps not added: 115 ohm
|   GND clamp passes 1 mA (typ) near -0.55 V on its own axis
|   POWER clamp passes 1 mA (typ) near -0.55 V on its own axis
|   falling waveform, R_fixture 50, V_fixture 1.8: 20-80 % time 64.9ns typ, 99.2ns min, 37.5ns max; typ from 1.8 V to 1.51 V
|   falling waveform, R_fixture 50, V_fixture 0: 20-80 % time 69.9ps typ, 77.6ps min, 65.9ps max; typ from 0.32 V to 0 V
|   rising waveform, R_fixture 50, V_fixture 1.8: 20-80 % time 131ps typ, 171ps min, 111ps max; typ from 1.51 V to 1.8 V
|   rising waveform, R_fixture 50, V_fixture 0: 20-80 % time 70.3ns typ, 105ns min, 43.2ns max; typ from 0 V to 0.32 V
[GND Clamp]
| Voltage   I(typ)   I(min)   I(max)
-1.204V   -750.5mA   -844.3mA   -692.2mA
-1.07V    -311.8mA   -416.8mA   -250.3mA
-1.003V   -144.6mA   -236.7mA   -99.35mA
-936.6mV  -47.15mA   -105.3mA   -29.57mA
-869.7mV  -15.32mA   -36.11mA   -15.4mA
-802.8mV  -8.178mA   -12.13mA   -11.32mA
-735.9mV  -5.345mA   -5.294mA   -8.218mA
-669mV    -3.361mA   -2.852mA   -5.471mA
-535.2mV  -838.5uA   -772.4uA   -1.486mA
-401.4mV  -47.36uA   -84.85uA   -76.78uA
3.6V      0A         0A         0A
[POWER Clamp]
| Voltage   I(typ)   I(min)   I(max)
-1.204V   837.3mA    970.7mA    749.2mA
-1.137V   634.9mA    778.2mA    540.5mA
-1.07V    440.1mA    587.4mA    346.5mA
-1.003V   270mA      407mA      190.9mA
-936.6mV  141.8mA    252.7mA    85.92mA
-869.7mV  58.74mA    136.5mA    26.66mA
-802.8mV  18.35mA    60.36mA    8.197mA
-735.9mV  5.885mA    21mA       4.755mA
-669mV    2.866mA    6.628mA    3.138mA
-334.5mV  12.31uA    45.7uA     5.857uA
3.6V      0A         0A         0A
[Pulldown]
| Voltage   I(typ)   I(min)   I(max)
-1.8V     -1.41mA    -1.616mA   -1.087mA
-1.204V   -1.504mA   -1.627mA   -1.313mA
-1.07V    -3.207mA   -2.198mA   -4.138mA
-1.003V   -5.036mA   -3.193mA   -6.097mA
-936.6mV  -6.321mA   -4.39mA    -6.957mA
-802.8mV  -6.8mA     -5.353mA   -7.481mA
-669mV    -6.566mA   -5.029mA   -7.572mA
-401.4mV  -4.854mA   -3.463mA   -6.107mA
248.3mV   2.887mA    1.855mA    3.943mA
558.6mV   4.677mA    3.038mA    6.285mA
1.552V    5.869mA    3.892mA    7.66mA
3.6V      6.265mA    4.233mA    8.024mA
[Pullup]
| Voltage   I(typ)   I(min)   I(max)
-1.8V     1.936mA    2.009mA    1.82mA
-1.137V   1.99mA     1.872mA    2.222mA
-1.07V    2.81mA     1.99mA     3.997mA
-1.003V   4.534mA    2.701mA    6.617mA
-936.6mV  6.113mA    3.849mA    7.85mA
-869.7mV  6.673mA    4.817mA    7.869mA
-735.9mV  6.345mA    5.034mA    7.391mA
-468.3mV  4.6mA      3.595mA    5.508mA
372.4mV   -3.082mA   -2.275mA   -3.846mA
869mV     -5.289mA   -3.876mA   -6.633mA
2.256V    -7.043mA   -4.972mA   -9.115mA
3.6V      -6.988mA   -4.941mA   -9.076mA
[Ramp]
dV/dt_r   0.191945/70.2717n  0.136483/0.104745u  0.245174/43.2262n
dV/dt_f   0.175407/64.9207n  0.115839/99.2178n  0.229171/37.5426n
R_load = 50
[Falling Waveform]
R_fixture = 50
V_fixture = 1.8
V_fixture_min = 1.66
V_fixture_max = 1.89
| Time   V(typ)   V(min)   V(max)
0s        1.8V       1.66V      1.89V
8.315ns   1.8V       1.66V      1.882V
17.24ns   1.788V     1.66V      1.799V
31.31ns   1.732V     1.648V     1.683V
49.76ns   1.661V     1.617V     1.595V
70.53ns   1.606V     1.582V     1.548V
104ns     1.555V     1.539V     1.52V
167.3ns   1.52V      1.495V     1.509V
259.3ns   1.509V     1.474V     1.508V
800ns     1.508V     1.467V     1.508V
[Falling Waveform]
R_fixture = 50
V_fixture = 0
V_fixture_min = 0
V_fixture_max = 0
| Time   V(typ)   V(min)   V(max)
0s        319.9mV    227.5mV    408.6mV
206.8ps   319.8mV    227.5mV    400.6mV
228.1ps   319.6mV    227.5mV    348.8mV
281.2ps   302.8mV    227.5mV    123.5mV
358.2ps   85.01mV    226.9mV    23.08mV
420.3ps   22.6mV     155mV      7.577mV
471.9ps   8.552mV    59.11mV    3.546mV
532.4ps   3.46mV     17.09mV    1.812mV
1.016ns   848.9uV    745.2uV    899.6uV
800ns     13.66nV    819.2nV    5.614nV
[Rising Waveform]
R_fixture = 50
V_fixture = 1.8
V_fixture_min = 1.66
V_fixture_max = 1.89
| Time   V(typ)   V(min)   V(max)
0s        1.508V     1.467V     1.508V
284.4ps   1.508V     1.467V     1.518V
325.7ps   1.508V     1.467V     1.569V
384.1ps   1.527V     1.467V     1.689V
450.3ps   1.606V     1.467V     1.821V
511.6ps   1.694V     1.477V     1.871V
616.1ps   1.783V     1.546V     1.887V
728.3ps   1.797V     1.619V     1.889V
821.9ps   1.799V     1.649V     1.889V
800ns     1.8V       1.66V      1.89V
[Rising Waveform]
R_fixture = 50
V_fixture = 0
V_fixture_min = 0
V_fixture_max = 0
| Time   V(typ)   V(min)   V(max)
0s        13.64nV    818.6nV    5.608nV
9.34ns    -184.7uV   -246.5uV   8.616mV
18.47ns   15.27mV    1.457mV    86.7mV
32.87ns   74.73mV    19.06mV    203.2mV
52.56ns   150.4mV    57.61mV    301mV
75.79ns   213.8mV    100.3mV    358.4mV
109.2ns   266.2mV    146.3mV    391.7mV
180.2ns   307.1mV    197.1mV    406.9mV
272.2ns   317.9mV    219mV      408.5mV
800ns     319.9mV    227.5mV    408.6mV
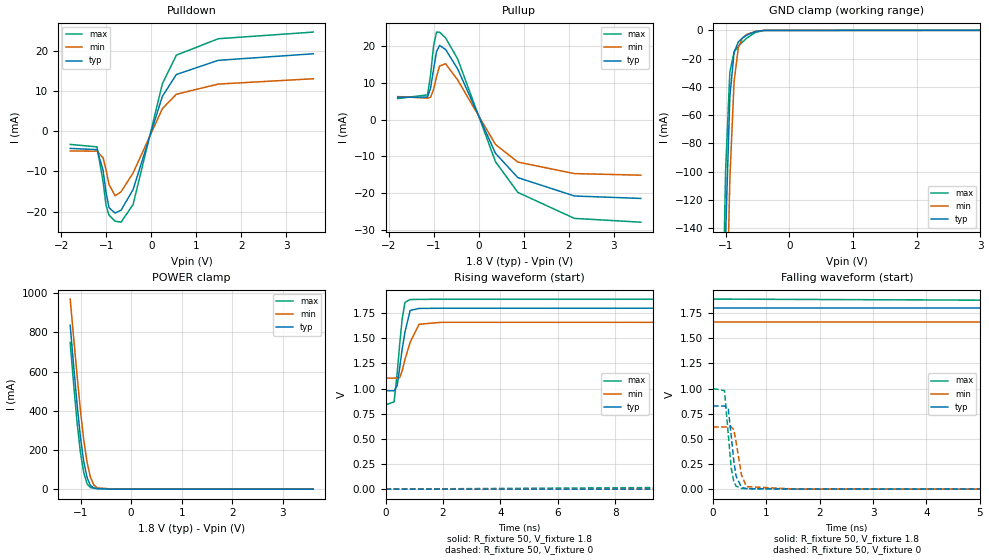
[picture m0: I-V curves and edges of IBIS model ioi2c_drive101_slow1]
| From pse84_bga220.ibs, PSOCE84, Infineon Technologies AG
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[Model] ioi2c_drive101_slow1
Model_type I/O
Enable   Active-High
Vinl  =  0.54
Vinh  =  1.26
Vmeas =  0.9
Cref  =  15e-12
| Capacitance   typ   min   max
C_comp   8.55364e-13 8.30808e-13 8.84570e-13
| Variables   typ   min   max
[GND Clamp Reference]   0   0   0
[POWER Clamp Reference]   1.8   1.66   1.89
[Pulldown Reference]   0   0   0
[Pullup Reference]   1.8   1.66   1.89
[Temperature Range]   25   125   -40
[Voltage Range]   1.8   1.66   1.89
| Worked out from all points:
|   slope of the pulldown table from 0 to 0.27 V, typ, clamps not added: 29.4 ohm
|   slope of the pullup table from 0 to 0.27 V, typ, clamps not added: 38.6 ohm
|   GND clamp passes 1 mA (typ) near -0.55 V on its own axis
|   POWER clamp passes 1 mA (typ) near -0.55 V on its own axis
|   falling waveform, R_fixture 50, V_fixture 1.8: 20-80 % time 90.7ns typ, 135ns min, 53.3ns max; typ from 1.8 V to 0.978 V
|   falling waveform, R_fixture 50, V_fixture 0: 20-80 % time 101ps typ, 118ps min, 92.7ps max; typ from 0.827 V to 0 V
|   rising waveform, R_fixture 50, V_fixture 1.8: 20-80 % time 259ps typ, 370ps min, 201ps max; typ from 0.978 V to 1.8 V
|   rising waveform, R_fixture 50, V_fixture 0: 20-80 % time 97.3ns typ, 145ns min, 58.5ns max; typ from 0 V to 0.827 V
[GND Clamp]
| Voltage   I(typ)   I(min)   I(max)
-1.204V   -750.5mA   -844.3mA   -692.2mA
-1.07V    -311.8mA   -416.8mA   -250.3mA
-1.003V   -144.6mA   -236.7mA   -99.35mA
-936.6mV  -47.15mA   -105.3mA   -29.57mA
-869.7mV  -15.32mA   -36.11mA   -15.4mA
-802.8mV  -8.178mA   -12.13mA   -11.32mA
-735.9mV  -5.345mA   -5.294mA   -8.218mA
-669mV    -3.361mA   -2.852mA   -5.471mA
-535.2mV  -838.5uA   -772.4uA   -1.486mA
-401.4mV  -47.36uA   -84.85uA   -76.78uA
3.6V      0A         0A         0A
[POWER Clamp]
| Voltage   I(typ)   I(min)   I(max)
-1.204V   837.3mA    970.7mA    749.2mA
-1.137V   634.9mA    778.2mA    540.5mA
-1.07V    440.1mA    587.4mA    346.5mA
-1.003V   270mA      407mA      190.9mA
-936.6mV  141.8mA    252.7mA    85.92mA
-869.7mV  58.74mA    136.5mA    26.66mA
-802.8mV  18.35mA    60.36mA    8.197mA
-735.9mV  5.885mA    21mA       4.755mA
-669mV    2.866mA    6.628mA    3.138mA
-334.5mV  12.31uA    45.7uA     5.857uA
3.6V      0A         0A         0A
[Pulldown]
| Voltage   I(typ)   I(min)   I(max)
-1.8V     -4.313mA   -4.953mA   -3.318mA
-1.204V   -4.619mA   -4.996mA   -3.94mA
-1.07V    -9.681mA   -6.636mA   -12.51mA
-1.003V   -15.26mA   -9.669mA   -18.45mA
-936.6mV  -19.06mA   -13.29mA   -20.9mA
-802.8mV  -20.38mA   -16.08mA   -22.4mA
-669mV    -19.67mA   -15.09mA   -22.65mA
-401.4mV  -14.52mA   -10.39mA   -18.23mA
248.3mV   8.629mA    5.565mA    11.75mA
558.6mV   14.05mA    9.146mA    18.85mA
1.49V     17.57mA    11.67mA    22.94mA
3.6V      19.2mA     12.99mA    24.59mA
[Pullup]
| Voltage   I(typ)   I(min)   I(max)
-1.8V     6.004mA    6.221mA    5.677mA
-1.137V   6.067mA    5.791mA    6.679mA
-1.07V    8.463mA    6.025mA    12.04mA
-1.003V   13.69mA    8.141mA    20mA
-936.6mV  18.44mA    11.62mA    23.69mA
-869.7mV  20.07mA    14.51mA    23.66mA
-735.9mV  18.99mA    15.11mA    22.13mA
-468.3mV  13.71mA    10.72mA    16.42mA
372.4mV   -9.175mA   -6.772mA   -11.45mA
869mV     -15.75mA   -11.54mA   -19.76mA
2.126V    -20.73mA   -14.66mA   -26.8mA
3.6V      -21.39mA   -15.09mA   -27.83mA
[Ramp]
dV/dt_r   0.496309/97.2678n  0.370803/0.145416u  0.599964/58.4998n
dV/dt_f   0.493089/90.6633n  0.333199/0.134538u  0.631398/53.2609n
R_load = 50
[Falling Waveform]
R_fixture = 50
V_fixture = 1.8
V_fixture_min = 1.66
V_fixture_max = 1.89
| Time   V(typ)   V(min)   V(max)
0s        1.8V       1.66V      1.89V
9.592ns   1.8V       1.66V      1.869V
19.26ns   1.771V     1.659V     1.693V
35.55ns   1.634V     1.625V     1.411V
58.15ns   1.453V     1.541V     1.153V
89.29ns   1.271V     1.427V     973.6mV
122.7ns   1.151V     1.333V     893.4mV
196.5ns   1.033V     1.209V     846.1mV
307.6ns   988.1mV    1.137V     838.2mV
800ns     978.2mV    1.105V     837.7mV
[Falling Waveform]
R_fixture = 50
V_fixture = 0
V_fixture_min = 0
V_fixture_max = 0
| Time   V(typ)   V(min)   V(max)
0s        827.2mV    618.4mV    999.9mV
214.6ps   827mV      618.4mV    979.7mV
285.4ps   797.7mV    618.4mV    541.9mV
340.7ps   529.2mV    618.8mV    209.6mV
389.2ps   281.7mV    592.2mV    73.52mV
431.5ps   129.2mV    468.2mV    30.61mV
534.3ps   16.91mV    139.9mV    6.997mV
626.9ps   5.432mV    25.26mV    4.662mV
1.541ns   1.42mV     1.233mV    1.505mV
800ns     7.591nV    511.5nV    2.856nV
[Rising Waveform]
R_fixture = 50
V_fixture = 1.8
V_fixture_min = 1.66
V_fixture_max = 1.89
| Time   V(typ)   V(min)   V(max)
0s        978.2mV    1.104V     837.7mV
298.4ps   978.3mV    1.104V     868mV
403ps     1.03V      1.105V     1.148V
497.1ps   1.219V     1.111V     1.457V
581.3ps   1.396V     1.181V     1.701V
675.9ps   1.562V     1.29V      1.857V
856.4ps   1.777V     1.46V      1.885V
1.163ns   1.797V     1.639V     1.887V
1.934ns   1.799V     1.659V     1.888V
800ns     1.8V       1.66V      1.89V
[Rising Waveform]
R_fixture = 50
V_fixture = 0
V_fixture_min = 0
V_fixture_max = 0
| Time   V(typ)   V(min)   V(max)
0s        7.56nV     509.9nV    2.85nV
11.74ns   63.02uV    -145.9uV   20.29mV
22.78ns   38.63mV    5.001mV    187.3mV
43.4ns    200.9mV    62.51mV    487.7mV
65.35ns   361.4mV    150.3mV    698.9mV
98.78ns   539.9mV    272.3mV    866.3mV
140.6ns   671.8mV    386.8mV    949mV
209.7ns   769.8mV    501mV      988.7mV
328.9ns   816.2mV    581.6mV    999mV
800ns     827.2mV    618mV      999.9mV
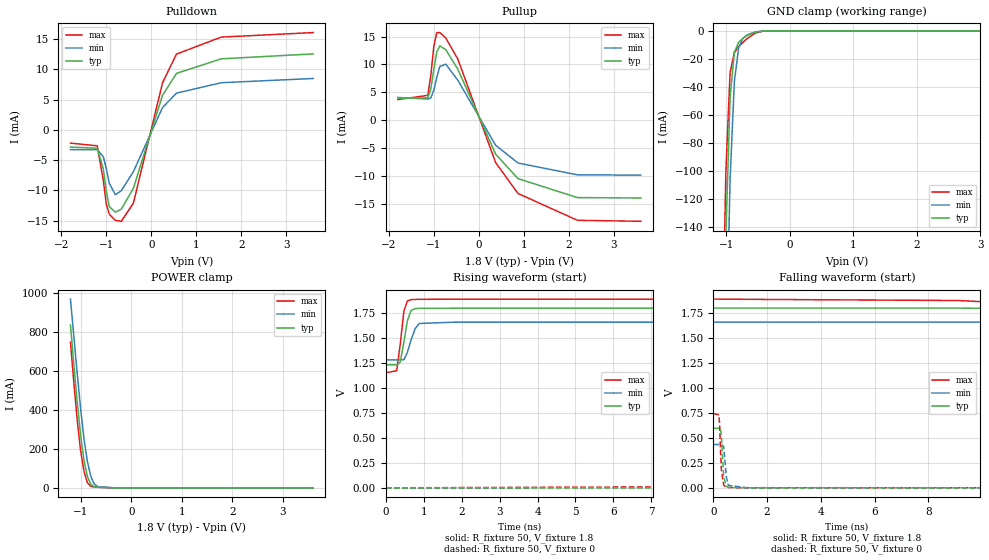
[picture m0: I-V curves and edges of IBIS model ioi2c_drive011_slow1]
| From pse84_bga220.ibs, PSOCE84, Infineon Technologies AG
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[Model] ioi2c_drive011_slow1
Model_type I/O
Enable   Active-High
Vinl  =  0.54
Vinh  =  1.26
Vmeas =  0.9
Cref  =  15e-12
| Capacitance   typ   min   max
C_comp   8.55364e-13 8.30808e-13 8.84570e-13
| Variables   typ   min   max
[GND Clamp Reference]   0   0   0
[POWER Clamp Reference]   1.8   1.66   1.89
[Pulldown Reference]   0   0   0
[Pullup Reference]   1.8   1.66   1.89
[Temperature Range]   25   125   -40
[Voltage Range]   1.8   1.66   1.89
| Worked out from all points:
|   slope of the pulldown table from 0 to 0.27 V, typ, clamps not added: 44.3 ohm
|   slope of the pullup table from 0 to 0.27 V, typ, clamps not added: 57.9 ohm
|   GND clamp passes 1 mA (typ) near -0.55 V on its own axis
|   POWER clamp passes 1 mA (typ) near -0.55 V on its own axis
|   falling waveform, R_fixture 50, V_fixture 1.8: 20-80 % time 80.8ns typ, 120ns min, 47.7ns max; typ from 1.8 V to 1.23 V
|   falling waveform, R_fixture 50, V_fixture 0: 20-80 % time 74.3ps typ, 83.7ps min, 69.4ps max; typ from 0.597 V to 0 V
|   rising waveform, R_fixture 50, V_fixture 1.8: 20-80 % time 148ps typ, 193ps min, 125ps max; typ from 1.23 V to 1.8 V
|   rising waveform, R_fixture 50, V_fixture 0: 20-80 % time 87.3ns typ, 129ns min, 53.7ns max; typ from 0 V to 0.597 V
[GND Clamp]
| Voltage   I(typ)   I(min)   I(max)
-1.204V   -750.5mA   -844.3mA   -692.2mA
-1.07V    -311.8mA   -416.8mA   -250.3mA
-1.003V   -144.6mA   -236.7mA   -99.35mA
-936.6mV  -47.15mA   -105.3mA   -29.57mA
-869.7mV  -15.32mA   -36.11mA   -15.4mA
-802.8mV  -8.178mA   -12.13mA   -11.32mA
-735.9mV  -5.345mA   -5.294mA   -8.218mA
-669mV    -3.361mA   -2.852mA   -5.471mA
-535.2mV  -838.5uA   -772.4uA   -1.486mA
-401.4mV  -47.36uA   -84.85uA   -76.78uA
3.6V      0A         0A         0A
[POWER Clamp]
| Voltage   I(typ)   I(min)   I(max)
-1.204V   837.3mA    970.7mA    749.2mA
-1.137V   634.9mA    778.2mA    540.5mA
-1.07V    440.1mA    587.4mA    346.5mA
-1.003V   270mA      407mA      190.9mA
-936.6mV  141.8mA    252.7mA    85.92mA
-869.7mV  58.74mA    136.5mA    26.66mA
-802.8mV  18.35mA    60.36mA    8.197mA
-735.9mV  5.885mA    21mA       4.755mA
-669mV    2.866mA    6.628mA    3.138mA
-334.5mV  12.31uA    45.7uA     5.857uA
3.6V      0A         0A         0A
[Pulldown]
| Voltage   I(typ)   I(min)   I(max)
-1.8V     -2.834mA   -3.25mA    -2.184mA
-1.204V   -3.026mA   -3.274mA   -2.627mA
-1.07V    -6.436mA   -4.405mA   -8.319mA
-1.003V   -10.11mA   -6.407mA   -12.23mA
-936.6mV  -12.66mA   -8.805mA   -13.91mA
-802.8mV  -13.58mA   -10.7mA    -14.93mA
-669mV    -13.09mA   -10.04mA   -15.09mA
-401.4mV  -9.649mA   -6.903mA   -12.11mA
248.3mV   5.729mA    3.696mA    7.795mA
558.6mV   9.329mA    6.073mA    12.52mA
1.552V    11.73mA    7.79mA     15.32mA
3.6V      12.55mA    8.49mA     16.07mA
[Pullup]
| Voltage   I(typ)   I(min)   I(max)
-1.8V     3.922mA    4.067mA    3.7mA
-1.137V   4.005mA    3.789mA    4.449mA
-1.07V    5.628mA    3.99mA     8.011mA
-1.003V   9.087mA    5.406mA    13.27mA
-936.6mV  12.24mA    7.707mA    15.71mA
-869.7mV  13.34mA    9.631mA    15.73mA
-735.9mV  12.65mA    10.05mA    14.74mA
-468.3mV  9.143mA    7.15mA     10.95mA
372.4mV   -6.121mA   -4.519mA   -7.634mA
869mV     -10.51mA   -7.701mA   -13.18mA
2.191V    -13.92mA   -9.829mA   -18mA
3.6V      -13.99mA   -9.886mA   -18.18mA
[Ramp]
dV/dt_r   0.358281/87.333n  0.260402/0.12879u  0.446042/53.7018n
dV/dt_f   0.34072/80.8174n  0.22707/0.120127u  0.442325/47.7068n
R_load = 50
[Falling Waveform]
R_fixture = 50
V_fixture = 1.8
V_fixture_min = 1.66
V_fixture_max = 1.89
| Time   V(typ)   V(min)   V(max)
0s        1.8V       1.66V      1.89V
9.144ns   1.8V       1.66V      1.876V
19.21ns   1.777V     1.659V     1.732V
33.76ns   1.683V     1.637V     1.539V
57.95ns   1.536V     1.57V      1.342V
83.03ns   1.428V     1.501V     1.242V
116.5ns   1.341V     1.43V      1.187V
178.6ns   1.269V     1.353V     1.159V
291ns     1.238V     1.3V       1.153V
800ns     1.232V     1.282V     1.153V
[Falling Waveform]
R_fixture = 50
V_fixture = 0
V_fixture_min = 0
V_fixture_max = 0
| Time   V(typ)   V(min)   V(max)
0s        597.1mV    434.1mV    743.4mV
208.1ps   597.1mV    434.1mV    730.7mV
232.1ps   596.9mV    434.1mV    634.6mV
268.3ps   591.9mV    434.1mV    357.8mV
299.4ps   508.1mV    434mV      178.8mV
384.2ps   108.6mV    412.8mV    28.43mV
482.6ps   15.27mV    111.7mV    4.705mV
554.2ps   5.184mV    26.02mV    3.309mV
1.243ns   1.144mV    1.092mV    1.143mV
800ns     9.803nV    630.9nV    3.819nV
[Rising Waveform]
R_fixture = 50
V_fixture = 1.8
V_fixture_min = 1.66
V_fixture_max = 1.89
| Time   V(typ)   V(min)   V(max)
0s        1.232V     1.282V     1.153V
286.1ps   1.232V     1.282V     1.172V
378.4ps   1.257V     1.282V     1.434V
475.2ps   1.46V      1.283V     1.769V
566.9ps   1.671V     1.355V     1.871V
665.2ps   1.778V     1.481V     1.885V
777.4ps   1.795V     1.597V     1.887V
880.5ps   1.798V     1.646V     1.888V
1.787ns   1.799V     1.659V     1.889V
800ns     1.8V       1.66V      1.89V
[Rising Waveform]
R_fixture = 50
V_fixture = 0
V_fixture_min = 0
V_fixture_max = 0
| Time   V(typ)   V(min)   V(max)
0s        9.771nV    629.7nV    3.81nV
10.63ns   -133uV     -186.9uV   13.89mV
20ns      22.72mV    2.417mV    129.5mV
39.02ns   142.1mV    41.15mV    359.3mV
61.79ns   275.3mV    112.7mV    533.1mV
86.87ns   382.4mV    185.4mV    634.8mV
128.7ns   488.5mV    276.3mV    706mV
196.1ns   560.3mV    359.6mV    736.4mV
312.6ns   591.2mV    413.6mV    743mV
800ns     597.1mV    434mV      743.4mV
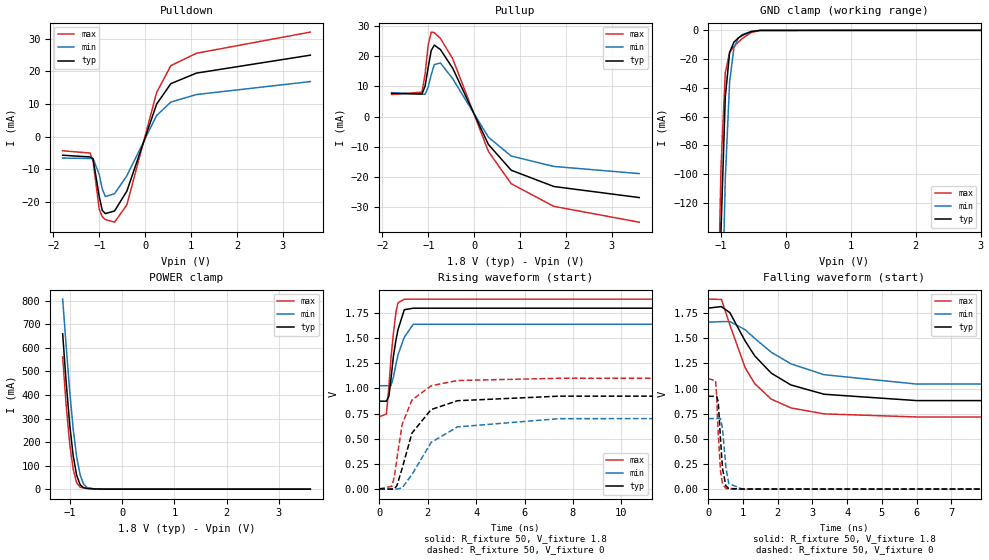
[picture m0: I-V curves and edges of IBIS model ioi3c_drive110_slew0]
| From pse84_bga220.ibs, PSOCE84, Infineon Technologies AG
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[Model] ioi3c_drive110_slew0
Model_type I/O
Enable   Active-High
Vinl  =  0.54
Vinh  =  1.26
Vmeas =  0.9
Cref  =  15e-12
| Capacitance   typ   min   max
C_comp   9.12545e-13 8.87504e-13 9.42456e-13
| Variables   typ   min   max
[GND Clamp Reference]   0   0   0
[POWER Clamp Reference]   1.8   1.66   1.89
[Pulldown Reference]   0   0   0
[Pullup Reference]   1.8   1.66   1.89
[Temperature Range]   25   125   -40
[Voltage Range]   1.8   1.66   1.89
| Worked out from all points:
|   slope of the pulldown table from 0 to 0.27 V, typ, clamps not added: 25.6 ohm
|   slope of the pullup table from 0 to 0.27 V, typ, clamps not added: 33.1 ohm
|   GND clamp passes 1 mA (typ) near -0.55 V on its own axis
|   POWER clamp passes 1 mA (typ) near -0.54 V on its own axis
|   falling waveform, R_fixture 50, V_fixture 1.8: 20-80 % time 1.41ns typ, 1.91ns min, 996ps max; typ from 1.8 V to 0.873 V
|   falling waveform, R_fixture 50, V_fixture 0: 20-80 % time 103ps typ, 117ps min, 95.1ps max; typ from 0.923 V to 0 V
|   rising waveform, R_fixture 50, V_fixture 1.8: 20-80 % time 331ps typ, 462ps min, 254ps max; typ from 0.873 V to 1.8 V
|   rising waveform, R_fixture 50, V_fixture 0: 20-80 % time 937ps typ, 1.32ns min, 651ps max; typ from 0 V to 0.923 V
[GND Clamp]
| Voltage   I(typ)   I(min)   I(max)
-1.204V   -737.9mA   -831.5mA   -678.7mA
-1.07V    -303.2mA   -410.8mA   -239.8mA
-1.003V   -139.9mA   -232.2mA   -95.74mA
-936.6mV  -46.51mA   -103.5mA   -29.5mA
-869.7mV  -15.31mA   -35.88mA   -15.36mA
-802.8mV  -8.166mA   -12.13mA   -11.29mA
-735.9mV  -5.335mA   -5.292mA   -8.195mA
-669mV    -3.356mA   -2.85mA    -5.457mA
-535.2mV  -837.9uA   -772uA     -1.483mA
-401.4mV  -47.36uA   -84.85uA   -76.77uA
3.6V      0A         0A         0A
[POWER Clamp]
| Voltage   I(typ)   I(min)   I(max)
-1.137V   660mA      807.5mA    561.8mA
-1.07V    454.5mA    608.2mA    356.2mA
-1.003V   275.7mA    418.4mA    193.6mA
-936.6mV  143.5mA    257.2mA    86.91mA
-869.7mV  59.43mA    137.9mA    27.31mA
-802.8mV  18.8mA     60.93mA    8.704mA
-735.9mV  6.231mA    21.35mA    5.155mA
-669mV    3.127mA    6.887mA    3.44mA
-535.2mV  940.9uA    1.232mA    1.058mA
-334.5mV  16.1uA     59.03uA    7.686uA
3.6V      0A         0A         0A
[Pulldown]
| Voltage   I(typ)   I(min)   I(max)
-1.8V     -5.733mA   -6.614mA   -4.376mA
-1.204V   -6.26mA    -6.73mA    -5.062mA
-1.137V   -6.869mA   -6.73mA    -7.434mA
-1.003V   -18.36mA   -11.66mA   -22.25mA
-936.6mV  -22.64mA   -16.01mA   -24.56mA
-869.7mV  -23.63mA   -18.41mA   -25.45mA
-669mV    -22.83mA   -17.54mA   -26.27mA
-401.4mV  -16.78mA   -12.04mA   -21.01mA
248.3mV   9.926mA    6.426mA    13.46mA
558.6mV   16.21mA    10.57mA    21.74mA
1.117V    19.44mA    12.87mA    25.53mA
3.6V      24.94mA    16.84mA    32.02mA
[Pullup]
| Voltage   I(typ)   I(min)   I(max)
-1.8V     7.687mA    7.955mA    7.314mA
-1.137V   7.536mA    7.383mA    8.126mA
-1.07V    10.11mA    7.436mA    14.18mA
-1.003V   16.28mA    9.774mA    23.7mA
-936.6mV  21.89mA    13.9mA     28.01mA
-869.7mV  23.68mA    17.26mA    27.82mA
-735.9mV  22.24mA    17.77mA    25.91mA
-468.3mV  16.03mA    12.55mA    19.19mA
310.3mV   -9.225mA   -6.811mA   -11.53mA
806.9mV   -17.76mA   -13.06mA   -22.23mA
1.738V    -23.16mA   -16.51mA   -29.74mA
3.6V      -26.82mA   -18.88mA   -34.98mA
[Ramp]
dV/dt_r   0.554053/0.937095n  0.421106/1.32493n  0.660024/0.651408n
dV/dt_f   0.556218/1.40774n  0.379913/1.91242n  0.704096/0.996247n
R_load = 50
[Falling Waveform]
R_fixture = 50
V_fixture = 1.8
V_fixture_min = 1.66
V_fixture_max = 1.89
| Time   V(typ)   V(min)   V(max)
0s        1.8V       1.66V      1.89V
380ps     1.815V     1.666V     1.886V
624.4ps   1.755V     1.666V     1.633V
1.066ns   1.472V     1.585V     1.206V
1.343ns   1.324V     1.498V     1.048V
1.818ns   1.153V     1.361V     894.4mV
2.383ns   1.036V     1.246V     807.7mV
3.338ns   943.6mV    1.138V     748.6mV
6.003ns   880.7mV    1.045V     717.7mV
800ns     873mV      1.027V     716.5mV
[Falling Waveform]
R_fixture = 50
V_fixture = 0
V_fixture_min = 0
V_fixture_max = 0
| Time   V(typ)   V(min)   V(max)
0s        923.4mV    701.8mV    1.1V
213.4ps   923.2mV    701.8mV    1.078V
241.3ps   923.9mV    701.8mV    943mV
290ps     870.1mV    701.7mV    555.6mV
353.2ps   502.4mV    702.6mV    185mV
413.3ps   205.4mV    599.2mV    50.87mV
510.2ps   31.36mV    217.8mV    6.292mV
592.4ps   7.025mV    56.24mV    2.201mV
980.8ps   1.118mV    1.352mV    721.3uV
800ns     9.104nV    625.7nV    3.374nV
[Rising Waveform]
R_fixture = 50
V_fixture = 1.8
V_fixture_min = 1.66
V_fixture_max = 1.89
| Time   V(typ)   V(min)   V(max)
0s        873mV      1.027V     716.5mV
297ps     873.2mV    1.027V     746.4mV
400.4ps   923.7mV    1.027V     1.022V
483.5ps   1.092V     1.027V     1.301V
585.4ps   1.322V     1.112V     1.549V
696ps     1.489V     1.248V     1.769V
774.5ps   1.585V     1.335V     1.853V
1.035ns   1.784V     1.51V      1.888V
1.406ns   1.799V     1.639V     1.889V
800ns     1.8V       1.66V      1.89V
[Rising Waveform]
R_fixture = 50
V_fixture = 0
V_fixture_min = 0
V_fixture_max = 0
| Time   V(typ)   V(min)   V(max)
0s        9.105nV    625.5nV    3.376nV
524.8ps   -3.121mV   -1.345mV   26.38mV
629.4ps   1.141mV    -2.153mV   126.7mV
730.6ps   32.84mV    -2.419mV   302.4mV
944.6ps   202.8mV    9.035mV    639.7mV
1.352ns   555.8mV    143.3mV    885mV
2.143ns   789.6mV    462.8mV    1.027V
3.232ns   877.8mV    617mV      1.079V
7.431ns   923.1mV    699.2mV    1.101V
50ns      923.4mV    701.8mV    1.1V
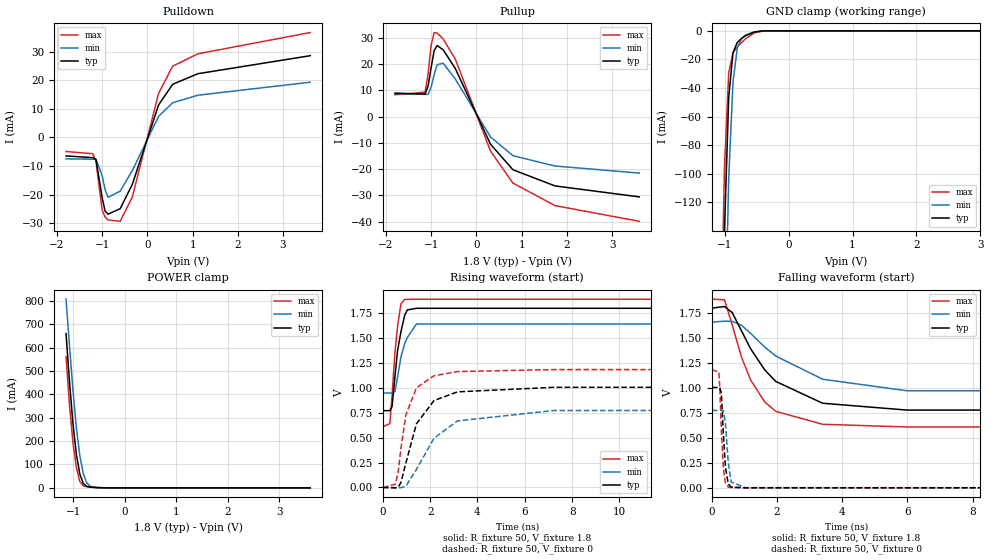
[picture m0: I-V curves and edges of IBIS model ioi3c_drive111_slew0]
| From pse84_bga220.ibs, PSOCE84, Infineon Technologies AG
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[Model] ioi3c_drive111_slew0
Model_type I/O
Enable   Active-High
Vinl  =  0.54
Vinh  =  1.26
Vmeas =  0.9
Cref  =  15e-12
| Capacitance   typ   min   max
C_comp   9.12545e-13 8.87504e-13 9.42456e-13
| Variables   typ   min   max
[GND Clamp Reference]   0   0   0
[POWER Clamp Reference]   1.8   1.66   1.89
[Pulldown Reference]   0   0   0
[Pullup Reference]   1.8   1.66   1.89
[Temperature Range]   25   125   -40
[Voltage Range]   1.8   1.66   1.89
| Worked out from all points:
|   slope of the pulldown table from 0 to 0.27 V, typ, clamps not added: 22.4 ohm
|   slope of the pullup table from 0 to 0.27 V, typ, clamps not added: 29 ohm
|   GND clamp passes 1 mA (typ) near -0.55 V on its own axis
|   POWER clamp passes 1 mA (typ) near -0.54 V on its own axis
|   falling waveform, R_fixture 50, V_fixture 1.8: 20-80 % time 1.45ns typ, 2.1ns min, 988ps max; typ from 1.8 V to 0.771 V
|   falling waveform, R_fixture 50, V_fixture 0: 20-80 % time 102ps typ, 115ps min, 94.5ps max; typ from 1 V to 0 V
|   rising waveform, R_fixture 50, V_fixture 1.8: 20-80 % time 328ps typ, 450ps min, 255ps max; typ from 0.771 V to 1.8 V
|   rising waveform, R_fixture 50, V_fixture 0: 20-80 % time 898ps typ, 1.41ns min, 590ps max; typ from 0 V to 1 V
[GND Clamp]
| Voltage   I(typ)   I(min)   I(max)
-1.204V   -737.9mA   -831.5mA   -678.7mA
-1.07V    -303.2mA   -410.8mA   -239.8mA
-1.003V   -139.9mA   -232.2mA   -95.74mA
-936.6mV  -46.51mA   -103.5mA   -29.5mA
-869.7mV  -15.31mA   -35.88mA   -15.36mA
-802.8mV  -8.166mA   -12.13mA   -11.29mA
-735.9mV  -5.335mA   -5.292mA   -8.195mA
-669mV    -3.356mA   -2.85mA    -5.457mA
-535.2mV  -837.9uA   -772uA     -1.483mA
-401.4mV  -47.36uA   -84.85uA   -76.77uA
3.6V      0A         0A         0A
[POWER Clamp]
| Voltage   I(typ)   I(min)   I(max)
-1.137V   660mA      807.5mA    561.8mA
-1.07V    454.5mA    608.2mA    356.2mA
-1.003V   275.7mA    418.4mA    193.6mA
-936.6mV  143.5mA    257.2mA    86.91mA
-869.7mV  59.43mA    137.9mA    27.31mA
-802.8mV  18.8mA     60.93mA    8.704mA
-735.9mV  6.231mA    21.35mA    5.155mA
-669mV    3.127mA    6.887mA    3.44mA
-535.2mV  940.9uA    1.232mA    1.058mA
-334.5mV  16.1uA     59.03uA    7.686uA
3.6V      0A         0A         0A
[Pulldown]
| Voltage   I(typ)   I(min)   I(max)
-1.8V     -6.515mA   -7.528mA   -4.968mA
-1.204V   -7.119mA   -7.665mA   -5.748mA
-1.137V   -7.831mA   -7.666mA   -8.475mA
-1.003V   -20.96mA   -13.32mA   -25.32mA
-936.6mV  -25.77mA   -18.28mA   -27.88mA
-869.7mV  -26.87mA   -20.98mA   -28.89mA
-602.1mV  -24.95mA   -18.82mA   -29.37mA
-334.5mV  -16.48mA   -11.64mA   -20.92mA
248.3mV   11.35mA    7.346mA    15.39mA
558.6mV   18.54mA    12.09mA    24.87mA
1.117V    22.24mA    14.72mA    29.2mA
3.6V      28.53mA    19.26mA    36.62mA
[Pullup]
| Voltage   I(typ)   I(min)   I(max)
-1.8V     8.736mA    9.043mA    8.308mA
-1.137V   8.564mA    8.393mA    9.23mA
-1.07V    11.51mA    8.453mA    16.16mA
-1.003V   18.56mA    11.13mA    27.01mA
-936.6mV  24.96mA    15.85mA    31.94mA
-869.7mV  27.01mA    19.69mA    31.73mA
-735.9mV  25.37mA    20.28mA    29.54mA
-468.3mV  18.28mA    14.31mA    21.88mA
310.3mV   -10.52mA   -7.768mA   -13.13mA
806.9mV   -20.25mA   -14.9mA    -25.34mA
1.738V    -26.41mA   -18.83mA   -33.9mA
3.6V      -30.58mA   -21.53mA   -39.87mA
[Ramp]
dV/dt_r   0.603129/0.898113n  0.465363/1.4071n  0.709188/0.589823n
dV/dt_f   0.617528/1.45239n  0.427334/2.09795n  0.768578/0.988394n
R_load = 50
[Falling Waveform]
R_fixture = 50
V_fixture = 1.8
V_fixture_min = 1.66
V_fixture_max = 1.89
| Time   V(typ)   V(min)   V(max)
0s        1.8V       1.66V      1.89V
386.4ps   1.816V     1.669V     1.883V
622.6ps   1.756V     1.667V     1.634V
911ps     1.571V     1.628V     1.307V
1.189ns   1.393V     1.547V     1.079V
1.622ns   1.181V     1.41V      860.8mV
1.96ns    1.066V     1.32V      766.3mV
3.398ns   847.4mV    1.088V     636.6mV
5.984ns   779mV      972.2mV    610mV
800ns     770.8mV    947.8mV    609mV
[Falling Waveform]
R_fixture = 50
V_fixture = 0
V_fixture_min = 0
V_fixture_max = 0
| Time   V(typ)   V(min)   V(max)
0s        1.005V     775.6mV    1.182V
213.6ps   1.005V     775.6mV    1.161V
239.9ps   1.006V     775.6mV    1.025V
289.9ps   949.8mV    775.5mV    587.4mV
351.2ps   549.1mV    776.9mV    204mV
414.9ps   210.9mV    652.9mV    52.47mV
503.8ps   37.31mV    251.2mV    8.01mV
592.5ps   7.598mV    59.24mV    2.337mV
1.03ns    1.137mV    1.452mV    735.6uV
800ns     8.274nV    576.3nV    3.037nV
[Rising Waveform]
R_fixture = 50
V_fixture = 1.8
V_fixture_min = 1.66
V_fixture_max = 1.89
| Time   V(typ)   V(min)   V(max)
0s        770.8mV    947.8mV    609mV
296.6ps   771mV      947.8mV    641.3mV
389.2ps   811.5mV    947.9mV    919.7mV
509.2ps   1.107V     961.9mV    1.351V
619ps     1.369V     1.103V     1.61V
765.4ps   1.564V     1.311V     1.843V
926ps     1.73V      1.445V     1.887V
1.038ns   1.782V     1.506V     1.888V
1.419ns   1.798V     1.64V      1.889V
800ns     1.8V       1.66V      1.89V
[Rising Waveform]
R_fixture = 50
V_fixture = 0
V_fixture_min = 0
V_fixture_max = 0
| Time   V(typ)   V(min)   V(max)
0s        8.275nV    576.2nV    3.04nV
535.9ps   -3.787mV   -1.808mV   33.35mV
658ps     6.5mV      -2.704mV   174.4mV
762.3ps   48.93mV    -2.835mV   390.3mV
975.1ps   246.1mV    13.66mV    730.6mV
1.419ns   638.3mV    180.7mV    1V
2.16ns    872mV      494.1mV    1.121V
3.156ns   959.7mV    668mV      1.163V
7.227ns   1.005V     772.5mV    1.183V
50ns      1.005V     775.6mV    1.182V
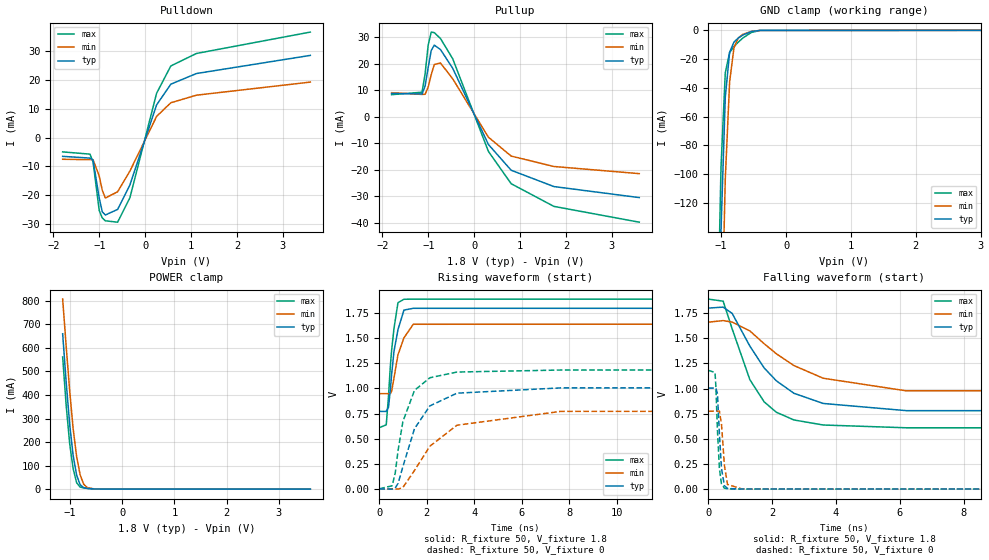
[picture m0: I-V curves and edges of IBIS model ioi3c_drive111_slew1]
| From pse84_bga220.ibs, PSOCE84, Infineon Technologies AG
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[Model] ioi3c_drive111_slew1
Model_type I/O
Enable   Active-High
Vinl  =  0.54
Vinh  =  1.26
Vmeas =  0.9
Cref  =  15e-12
| Capacitance   typ   min   max
C_comp   9.12545e-13 8.87504e-13 9.42456e-13
| Variables   typ   min   max
[GND Clamp Reference]   0   0   0
[POWER Clamp Reference]   1.8   1.66   1.89
[Pulldown Reference]   0   0   0
[Pullup Reference]   1.8   1.66   1.89
[Temperature Range]   25   125   -40
[Voltage Range]   1.8   1.66   1.89
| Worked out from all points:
|   slope of the pulldown table from 0 to 0.27 V, typ, clamps not added: 22.4 ohm
|   slope of the pullup table from 0 to 0.27 V, typ, clamps not added: 29 ohm
|   GND clamp passes 1 mA (typ) near -0.55 V on its own axis
|   POWER clamp passes 1 mA (typ) near -0.54 V on its own axis
|   falling waveform, R_fixture 50, V_fixture 1.8: 20-80 % time 1.54ns typ, 2.22ns min, 1.05ns max; typ from 1.8 V to 0.771 V
|   falling waveform, R_fixture 50, V_fixture 0: 20-80 % time 102ps typ, 115ps min, 94.6ps max; typ from 1 V to 0 V
|   rising waveform, R_fixture 50, V_fixture 1.8: 20-80 % time 333ps typ, 455ps min, 262ps max; typ from 0.771 V to 1.8 V
|   rising waveform, R_fixture 50, V_fixture 0: 20-80 % time 1.06ns typ, 1.73ns min, 678ps max; typ from 0 V to 1 V
[GND Clamp]
| Voltage   I(typ)   I(min)   I(max)
-1.204V   -737.9mA   -831.5mA   -678.7mA
-1.07V    -303.2mA   -410.8mA   -239.8mA
-1.003V   -139.9mA   -232.2mA   -95.74mA
-936.6mV  -46.51mA   -103.5mA   -29.5mA
-869.7mV  -15.31mA   -35.88mA   -15.36mA
-802.8mV  -8.166mA   -12.13mA   -11.29mA
-735.9mV  -5.335mA   -5.292mA   -8.195mA
-669mV    -3.356mA   -2.85mA    -5.457mA
-535.2mV  -837.9uA   -772uA     -1.483mA
-401.4mV  -47.36uA   -84.85uA   -76.77uA
3.6V      0A         0A         0A
[POWER Clamp]
| Voltage   I(typ)   I(min)   I(max)
-1.137V   660mA      807.5mA    561.8mA
-1.07V    454.5mA    608.2mA    356.2mA
-1.003V   275.7mA    418.4mA    193.6mA
-936.6mV  143.5mA    257.2mA    86.91mA
-869.7mV  59.43mA    137.9mA    27.31mA
-802.8mV  18.8mA     60.93mA    8.704mA
-735.9mV  6.231mA    21.35mA    5.155mA
-669mV    3.127mA    6.887mA    3.44mA
-535.2mV  940.9uA    1.232mA    1.058mA
-334.5mV  16.1uA     59.03uA    7.686uA
3.6V      0A         0A         0A
[Pulldown]
| Voltage   I(typ)   I(min)   I(max)
-1.8V     -6.515mA   -7.528mA   -4.968mA
-1.204V   -7.119mA   -7.665mA   -5.748mA
-1.137V   -7.831mA   -7.666mA   -8.475mA
-1.003V   -20.96mA   -13.32mA   -25.32mA
-936.6mV  -25.77mA   -18.28mA   -27.88mA
-869.7mV  -26.87mA   -20.98mA   -28.89mA
-602.1mV  -24.95mA   -18.82mA   -29.37mA
-334.5mV  -16.48mA   -11.64mA   -20.92mA
248.3mV   11.35mA    7.346mA    15.39mA
558.6mV   18.54mA    12.09mA    24.87mA
1.117V    22.24mA    14.72mA    29.2mA
3.6V      28.53mA    19.26mA    36.62mA
[Pullup]
| Voltage   I(typ)   I(min)   I(max)
-1.8V     8.736mA    9.043mA    8.308mA
-1.137V   8.564mA    8.393mA    9.23mA
-1.07V    11.51mA    8.453mA    16.16mA
-1.003V   18.56mA    11.13mA    27.01mA
-936.6mV  24.96mA    15.85mA    31.94mA
-869.7mV  27.01mA    19.69mA    31.73mA
-735.9mV  25.37mA    20.28mA    29.54mA
-468.3mV  18.28mA    14.31mA    21.88mA
310.3mV   -10.52mA   -7.768mA   -13.13mA
806.9mV   -20.25mA   -14.9mA    -25.34mA
1.738V    -26.41mA   -18.83mA   -33.9mA
3.6V      -30.58mA   -21.53mA   -39.87mA
[Ramp]
dV/dt_r   0.603129/1.06263n  0.465361/1.72974n  0.709188/0.678184n
dV/dt_f   0.617528/1.54398n  0.427333/2.22355n  0.768578/1.04663n
R_load = 50
[Falling Waveform]
R_fixture = 50
V_fixture = 1.8
V_fixture_min = 1.66
V_fixture_max = 1.89
| Time   V(typ)   V(min)   V(max)
0s        1.8V       1.66V      1.89V
469ps     1.81V      1.676V     1.869V
751.9ps   1.747V     1.661V     1.593V
1.306ns   1.422V     1.573V     1.088V
1.754ns   1.205V     1.446V     868mV
2.136ns   1.077V     1.346V     764.6mV
2.686ns   953.4mV    1.229V     688.2mV
3.603ns   852mV      1.103V     637.9mV
6.207ns   780.7mV    977.6mV    610.3mV
800ns     770.8mV    947.8mV    609mV
[Falling Waveform]
R_fixture = 50
V_fixture = 0
V_fixture_min = 0
V_fixture_max = 0
| Time   V(typ)   V(min)   V(max)
0s        1.005V     775.6mV    1.182V
213.8ps   1.005V     775.6mV    1.16V
239.9ps   1.006V     775.6mV    1.025V
290.7ps   946.6mV    775.5mV    581.2mV
350.6ps   552.9mV    777mV      206.3mV
415.9ps   207.1mV    648.6mV    53.56mV
508.9ps   33.88mV    234.5mV    9.591mV
605.1ps   6.47mV     46.73mV    2.965mV
1.067ns   1.237mV    1.31mV     795.1uV
800ns     8.274nV    576.3nV    3.037nV
[Rising Waveform]
R_fixture = 50
V_fixture = 1.8
V_fixture_min = 1.66
V_fixture_max = 1.89
| Time   V(typ)   V(min)   V(max)
0s        770.8mV    947.8mV    609mV
293.9ps   770.9mV    947.8mV    636.7mV
389.8ps   812.3mV    947.9mV    921.1mV
467.7ps   990.3mV    946.1mV    1.227V
520.9ps   1.139V     971.7mV    1.379V
618.2ps   1.367V     1.101V     1.594V
787.8ps   1.585V     1.335V     1.854V
1.039ns   1.78V      1.504V     1.888V
1.432ns   1.798V     1.639V     1.889V
800ns     1.8V       1.66V      1.89V
[Rising Waveform]
R_fixture = 50
V_fixture = 0
V_fixture_min = 0
V_fixture_max = 0
| Time   V(typ)   V(min)   V(max)
0s        8.275nV    576.2nV    3.04nV
544ps     -3.756mV   -1.845mV   30mV
672ps     7.566mV    -2.677mV   156.5mV
795ps     55.45mV    -2.741mV   386mV
993.7ps   219.9mV    13.01mV    668.8mV
1.482ns   598.2mV    182.3mV    980.2mV
2.127ns   825.4mV    423.7mV    1.106V
3.267ns   952.5mV    633.3mV    1.163V
7.627ns   1.005V     771.1mV    1.183V
50ns      1.005V     775.6mV    1.182V
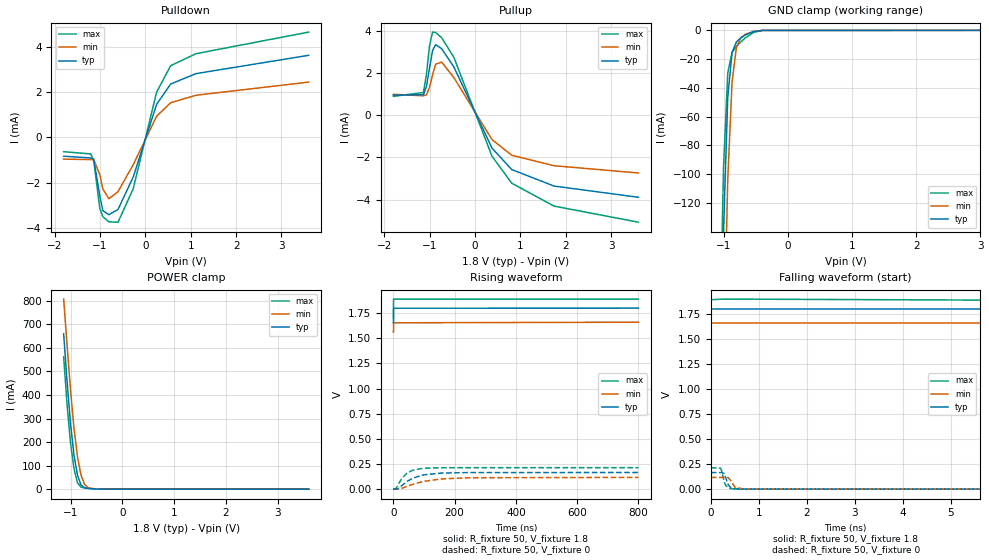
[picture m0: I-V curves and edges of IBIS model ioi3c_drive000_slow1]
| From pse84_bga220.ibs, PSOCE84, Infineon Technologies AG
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[Model] ioi3c_drive000_slow1
Model_type I/O
Enable   Active-High
Vinl  =  0.54
Vinh  =  1.26
Vmeas =  0.9
Cref  =  15e-12
| Capacitance   typ   min   max
C_comp   9.12545e-13 8.87504e-13 9.42456e-13
| Variables   typ   min   max
[GND Clamp Reference]   0   0   0
[POWER Clamp Reference]   1.8   1.66   1.89
[Pulldown Reference]   0   0   0
[Pullup Reference]   1.8   1.66   1.89
[Temperature Range]   25   125   -40
[Voltage Range]   1.8   1.66   1.89
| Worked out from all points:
|   slope of the pulldown table from 0 to 0.27 V, typ, clamps not added: 174 ohm
|   slope of the pullup table from 0 to 0.27 V, typ, clamps not added: 228 ohm
|   GND clamp passes 1 mA (typ) near -0.55 V on its own axis
|   POWER clamp passes 1 mA (typ) near -0.54 V on its own axis
|   falling waveform, R_fixture 50, V_fixture 1.8: 20-80 % time 54.6ns typ, 85.8ns min, 30.6ns max; typ from 1.8 V to 1.65 V
|   falling waveform, R_fixture 50, V_fixture 0: 20-80 % time 75.8ps typ, 84ps min, 71.4ps max; typ from 0.165 V to 0 V
|   rising waveform, R_fixture 50, V_fixture 1.8: 20-80 % time 147ps typ, 193ps min, 124ps max; typ from 1.65 V to 1.8 V
|   rising waveform, R_fixture 50, V_fixture 0: 20-80 % time 58.4ns typ, 89.1ns min, 35ns max; typ from 0 V to 0.165 V
[GND Clamp]
| Voltage   I(typ)   I(min)   I(max)
-1.204V   -737.9mA   -831.5mA   -678.7mA
-1.07V    -303.2mA   -410.8mA   -239.8mA
-1.003V   -139.9mA   -232.2mA   -95.74mA
-936.6mV  -46.51mA   -103.5mA   -29.5mA
-869.7mV  -15.31mA   -35.88mA   -15.36mA
-802.8mV  -8.166mA   -12.13mA   -11.29mA
-735.9mV  -5.335mA   -5.292mA   -8.195mA
-669mV    -3.356mA   -2.85mA    -5.457mA
-535.2mV  -837.9uA   -772uA     -1.483mA
-401.4mV  -47.36uA   -84.85uA   -76.77uA
3.6V      0A         0A         0A
[POWER Clamp]
| Voltage   I(typ)   I(min)   I(max)
-1.137V   660mA      807.5mA    561.8mA
-1.07V    454.5mA    608.2mA    356.2mA
-1.003V   275.7mA    418.4mA    193.6mA
-936.6mV  143.5mA    257.2mA    86.91mA
-869.7mV  59.43mA    137.9mA    27.31mA
-802.8mV  18.8mA     60.93mA    8.704mA
-735.9mV  6.231mA    21.35mA    5.155mA
-669mV    3.127mA    6.887mA    3.44mA
-535.2mV  940.9uA    1.232mA    1.058mA
-334.5mV  16.1uA     59.03uA    7.686uA
3.6V      0A         0A         0A
[Pulldown]
| Voltage   I(typ)   I(min)   I(max)
-1.8V     -827.2uA   -956.8uA   -629.4uA
-1.204V   -904.6uA   -975.8uA   -726.2uA
-1.137V   -964.8uA   -976uA     -1.026mA
-1.003V   -2.571mA   -1.647mA   -3.133mA
-936.6mV  -3.227mA   -2.276mA   -3.495mA
-802.8mV  -3.407mA   -2.705mA   -3.725mA
-602.1mV  -3.177mA   -2.39mA    -3.739mA
-267.6mV  -1.747mA   -1.204mA   -2.264mA
248.3mV   1.461mA    937.8uA    1.999mA
558.6mV   2.359mA    1.533mA    3.169mA
1.117V    2.817mA    1.863mA    3.696mA
3.6V      3.624mA    2.442mA    4.649mA
[Pullup]
| Voltage   I(typ)   I(min)   I(max)
-1.8V     966.4uA    1.005mA    909.8uA
-1.137V   986.4uA    935.3uA    1.092mA
-1.07V    1.395mA    989.3uA    1.982mA
-1.003V   2.274mA    1.347mA    3.331mA
-936.6mV  3.089mA    1.934mA    3.967mA
-869.7mV  3.365mA    2.435mA    3.951mA
-735.9mV  3.177mA    2.538mA    3.696mA
-468.3mV  2.312mA    1.807mA    2.768mA
372.4mV   -1.553mA   -1.147mA   -1.938mA
806.9mV   -2.573mA   -1.891mA   -3.221mA
1.738V    -3.359mA   -2.392mA   -4.312mA
3.6V      -3.894mA   -2.738mA   -5.079mA
[Ramp]
dV/dt_r   99.2892m/58.4149n  70.0053m/89.0698n  0.128112/35.0211n
dV/dt_f   89.3253m/54.5778n  58.9155m/85.8023n  0.116841/30.6408n
R_load = 50
[Falling Waveform]
R_fixture = 50
V_fixture = 1.8
V_fixture_min = 1.66
V_fixture_max = 1.89
| Time   V(typ)   V(min)   V(max)
0s        1.8V       1.66V      1.89V
260.2ps   1.8V       1.66V      1.897V
8.497ns   1.8V       1.66V      1.881V
25.16ns   1.771V     1.656V     1.789V
38.26ns   1.739V     1.645V     1.746V
62.39ns   1.699V     1.621V     1.712V
87.46ns   1.676V     1.601V     1.701V
148.2ns   1.656V     1.576V     1.696V
231.8ns   1.652V     1.565V     1.695V
800ns     1.651V     1.562V     1.695V
[Falling Waveform]
R_fixture = 50
V_fixture = 0
V_fixture_min = 0
V_fixture_max = 0
| Time   V(typ)   V(min)   V(max)
0s        165.5mV    116.7mV    213.5mV
203.2ps   165.4mV    116.7mV    209.5mV
225.8ps   165.2mV    116.7mV    182.7mV
278.8ps   155.9mV    116.7mV    70.62mV
311.3ps   112.8mV    116.4mV    36.24mV
358ps     46.34mV    115.9mV    14.58mV
415ps     15.36mV    84.12mV    5.08mV
504.4ps   3.506mV    17.61mV    1.44mV
701.9ps   707.6uV    1.052mV    545uV
800ns     22.57nV    1.283uV    9.657nV
[Rising Waveform]
R_fixture = 50
V_fixture = 1.8
V_fixture_min = 1.66
V_fixture_max = 1.89
| Time   V(typ)   V(min)   V(max)
0s        1.651V     1.562V     1.695V
283.3ps   1.651V     1.562V     1.701V
327.1ps   1.651V     1.562V     1.726V
383.9ps   1.661V     1.562V     1.779V
460.6ps   1.704V     1.562V     1.851V
523.4ps   1.745V     1.57V      1.878V
634.9ps   1.79V      1.604V     1.888V
738.1ps   1.798V     1.635V     1.889V
847.4ps   1.799V     1.654V     1.889V
800ns     1.8V       1.66V      1.89V
[Rising Waveform]
R_fixture = 50
V_fixture = 0
V_fixture_min = 0
V_fixture_max = 0
| Time   V(typ)   V(min)   V(max)
0s        22.57nV    1.283uV    9.657nV
9.081ns   82.17uV    -281.8uV   8.117mV
16.65ns   8.365mV    886.2uV    50.67mV
25.51ns   30.38mV    6.232mV    97.5mV
43.98ns   75.53mV    26.44mV    158.5mV
64.03ns   110.1mV    48.97mV    189.1mV
97.46ns   141.2mV    76.7mV     207.3mV
155.3ns   159.6mV    101.2mV    212.9mV
247.2ns   164.9mV    113.3mV    213.5mV
800ns     165.5mV    116.7mV    213.5mV
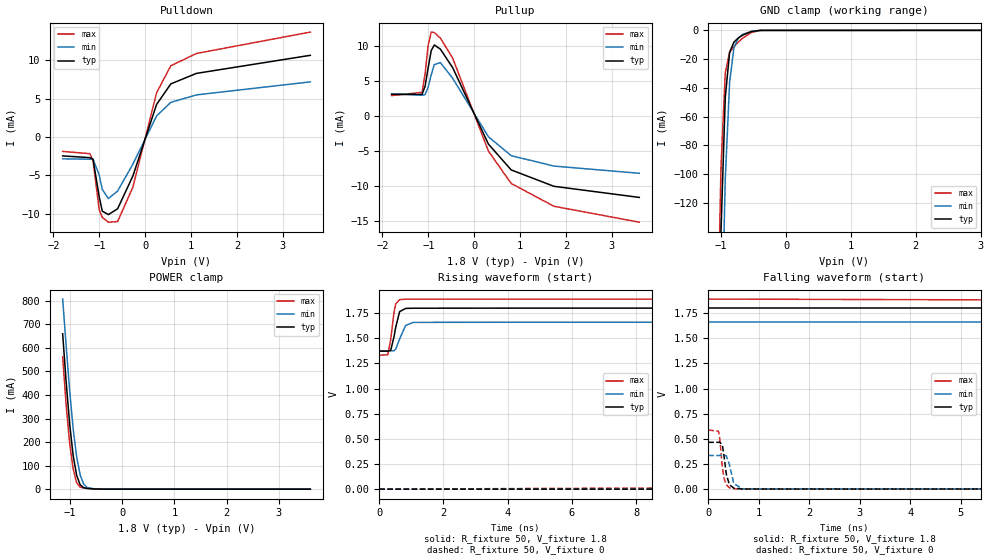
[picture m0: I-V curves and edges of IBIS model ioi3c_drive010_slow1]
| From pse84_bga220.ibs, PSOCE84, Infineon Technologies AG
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[Model] ioi3c_drive010_slow1
Model_type I/O
Enable   Active-High
Vinl  =  0.54
Vinh  =  1.26
Vmeas =  0.9
Cref  =  15e-12
| Capacitance   typ   min   max
C_comp   9.12545e-13 8.87504e-13 9.42456e-13
| Variables   typ   min   max
[GND Clamp Reference]   0   0   0
[POWER Clamp Reference]   1.8   1.66   1.89
[Pulldown Reference]   0   0   0
[Pullup Reference]   1.8   1.66   1.89
[Temperature Range]   25   125   -40
[Voltage Range]   1.8   1.66   1.89
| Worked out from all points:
|   slope of the pulldown table from 0 to 0.27 V, typ, clamps not added: 59.8 ohm
|   slope of the pullup table from 0 to 0.27 V, typ, clamps not added: 76.6 ohm
|   GND clamp passes 1 mA (typ) near -0.55 V on its own axis
|   POWER clamp passes 1 mA (typ) near -0.54 V on its own axis
|   falling waveform, R_fixture 50, V_fixture 1.8: 20-80 % time 70.9ns typ, 107ns min, 41.4ns max; typ from 1.8 V to 1.37 V
|   falling waveform, R_fixture 50, V_fixture 0: 20-80 % time 79ps typ, 88.4ps min, 74.1ps max; typ from 0.466 V to 0 V
|   rising waveform, R_fixture 50, V_fixture 1.8: 20-80 % time 156ps typ, 204ps min, 132ps max; typ from 1.37 V to 1.8 V
|   rising waveform, R_fixture 50, V_fixture 0: 20-80 % time 77.4ns typ, 115ns min, 47.6ns max; typ from 0 V to 0.466 V
[GND Clamp]
| Voltage   I(typ)   I(min)   I(max)
-1.204V   -737.9mA   -831.5mA   -678.7mA
-1.07V    -303.2mA   -410.8mA   -239.8mA
-1.003V   -139.9mA   -232.2mA   -95.74mA
-936.6mV  -46.51mA   -103.5mA   -29.5mA
-869.7mV  -15.31mA   -35.88mA   -15.36mA
-802.8mV  -8.166mA   -12.13mA   -11.29mA
-735.9mV  -5.335mA   -5.292mA   -8.195mA
-669mV    -3.356mA   -2.85mA    -5.457mA
-535.2mV  -837.9uA   -772uA     -1.483mA
-401.4mV  -47.36uA   -84.85uA   -76.77uA
3.6V      0A         0A         0A
[POWER Clamp]
| Voltage   I(typ)   I(min)   I(max)
-1.137V   660mA      807.5mA    561.8mA
-1.07V    454.5mA    608.2mA    356.2mA
-1.003V   275.7mA    418.4mA    193.6mA
-936.6mV  143.5mA    257.2mA    86.91mA
-869.7mV  59.43mA    137.9mA    27.31mA
-802.8mV  18.8mA     60.93mA    8.704mA
-735.9mV  6.231mA    21.35mA    5.155mA
-669mV    3.127mA    6.887mA    3.44mA
-535.2mV  940.9uA    1.232mA    1.058mA
-334.5mV  16.1uA     59.03uA    7.686uA
3.6V      0A         0A         0A
[Pulldown]
| Voltage   I(typ)   I(min)   I(max)
-1.8V     -2.473mA   -2.854mA   -1.887mA
-1.204V   -2.702mA   -2.905mA   -2.183mA
-1.137V   -2.922mA   -2.905mA   -3.146mA
-1.003V   -7.816mA   -4.974mA   -9.49mA
-936.6mV  -9.674mA   -6.839mA   -10.49mA
-802.8mV  -10.13mA   -8.036mA   -11.12mA
-602.1mV  -9.37mA    -7.06mA    -11.04mA
-267.6mV  -5.074mA   -3.525mA   -6.53mA
248.3mV   4.247mA    2.747mA    5.767mA
558.6mV   6.922mA    4.512mA    9.29mA
1.117V    8.293mA    5.487mA    10.89mA
3.6V      10.65mA    7.185mA    13.68mA
[Pullup]
| Voltage   I(typ)   I(min)   I(max)
-1.8V     3.096mA    3.209mA    2.933mA
-1.137V   3.099mA    2.984mA    3.392mA
-1.07V    4.265mA    3.079mA    6.029mA
-1.003V   6.909mA    4.116mA    10.1mA
-936.6mV  9.337mA    5.882mA    11.98mA
-869.7mV  10.14mA    7.354mA    11.92mA
-735.9mV  9.543mA    7.62mA     11.11mA
-468.3mV  6.903mA    5.396mA    8.267mA
310.3mV   -3.979mA   -2.934mA   -4.975mA
806.9mV   -7.659mA   -5.626mA   -9.59mA
1.738V    -9.995mA   -7.114mA   -12.84mA
3.6V      -11.58mA   -8.141mA   -15.11mA
[Ramp]
dV/dt_r   0.279476/77.3956n  0.200782/0.114611u  0.352675/47.6093n
dV/dt_f   0.256717/70.8994n  0.170413/0.106845u  0.334742/41.3698n
R_load = 50
[Falling Waveform]
R_fixture = 50
V_fixture = 1.8
V_fixture_min = 1.66
V_fixture_max = 1.89
| Time   V(typ)   V(min)   V(max)
0s        1.8V       1.66V      1.89V
8.44ns    1.8V       1.66V      1.878V
16.4ns    1.787V     1.66V      1.779V
31.9ns    1.703V     1.642V     1.603V
49.59ns   1.611V     1.601V     1.48V
72.52ns   1.524V     1.547V     1.4V
106ns     1.45V      1.486V     1.354V
169.6ns   1.394V     1.423V     1.335V
270.4ns   1.375V     1.388V     1.332V
800ns     1.372V     1.376V     1.332V
[Falling Waveform]
R_fixture = 50
V_fixture = 0
V_fixture_min = 0
V_fixture_max = 0
| Time   V(typ)   V(min)   V(max)
0s        465.8mV    334.7mV    587.8mV
205.2ps   465.7mV    334.7mV    576.3mV
229.9ps   465.6mV    334.7mV    499.2mV
280.4ps   439.8mV    334.6mV    216mV
315.5ps   319.7mV    334.5mV    104.3mV
357.8ps   150.5mV    333.1mV    44.88mV
417.3ps   46.66mV    247.3mV    14.61mV
507.7ps   9.828mV    55.13mV    3.37mV
673.7ps   1.519mV    3.884mV    755.2uV
800ns     15.26nV    953.5nV    6.067nV
[Rising Waveform]
R_fixture = 50
V_fixture = 1.8
V_fixture_min = 1.66
V_fixture_max = 1.89
| Time   V(typ)   V(min)   V(max)
0s        1.372V     1.376V     1.332V
265.5ps   1.372V     1.376V     1.336V
356.2ps   1.379V     1.376V     1.485V
459.8ps   1.514V     1.376V     1.755V
515.7ps   1.613V     1.393V     1.843V
635.1ps   1.765V     1.493V     1.884V
822.4ps   1.797V     1.628V     1.889V
1.061ns   1.799V     1.658V     1.889V
4.406ns   1.8V       1.66V      1.889V
800ns     1.8V       1.66V      1.89V
[Rising Waveform]
R_fixture = 50
V_fixture = 0
V_fixture_min = 0
V_fixture_max = 0
| Time   V(typ)   V(min)   V(max)
0s        15.25nV    952.8nV    6.062nV
9.772ns   30.07uV    -213.7uV   12.84mV
19.15ns   21.94mV    2.31mV     119.2mV
33.76ns   103.2mV    26.91mV    277.3mV
54.44ns   211mV      82.28mV    420.1mV
79.52ns   304.5mV    145.2mV    508.2mV
121.3ns   391mV      221.2mV    564.2mV
194.8ns   446.1mV    289.6mV    584.9mV
295.1ns   462.5mV    321.8mV    587.6mV
800ns     465.8mV    334.6mV    587.8mV
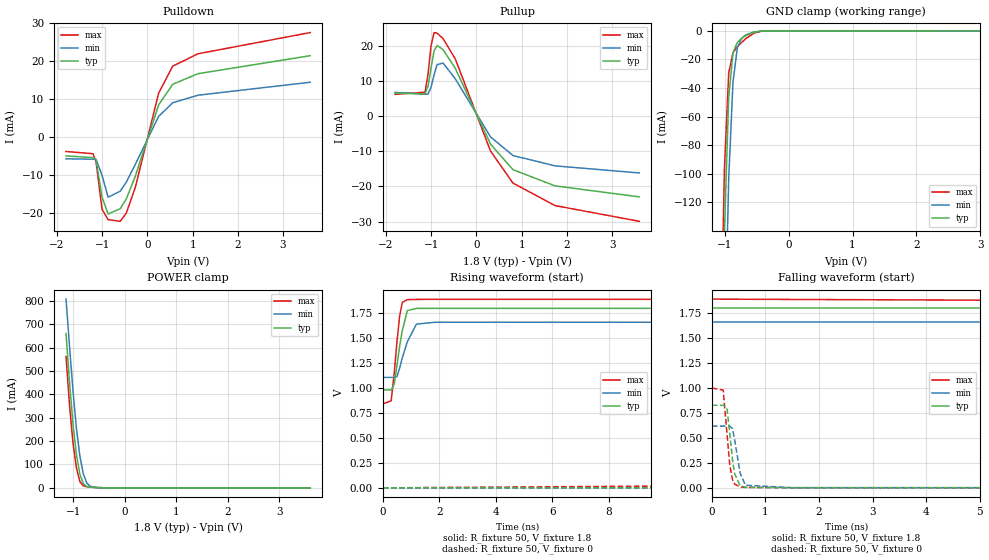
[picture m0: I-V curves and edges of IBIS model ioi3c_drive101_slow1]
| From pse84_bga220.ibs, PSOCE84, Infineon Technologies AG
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[Model] ioi3c_drive101_slow1
Model_type I/O
Enable   Active-High
Vinl  =  0.54
Vinh  =  1.26
Vmeas =  0.9
Cref  =  15e-12
| Capacitance   typ   min   max
C_comp   9.12545e-13 8.87504e-13 9.42456e-13
| Variables   typ   min   max
[GND Clamp Reference]   0   0   0
[POWER Clamp Reference]   1.8   1.66   1.89
[Pulldown Reference]   0   0   0
[Pullup Reference]   1.8   1.66   1.89
[Temperature Range]   25   125   -40
[Voltage Range]   1.8   1.66   1.89
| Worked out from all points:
|   slope of the pulldown table from 0 to 0.27 V, typ, clamps not added: 29.6 ohm
|   slope of the pullup table from 0 to 0.27 V, typ, clamps not added: 38.6 ohm
|   GND clamp passes 1 mA (typ) near -0.55 V on its own axis
|   POWER clamp passes 1 mA (typ) near -0.54 V on its own axis
|   falling waveform, R_fixture 50, V_fixture 1.8: 20-80 % time 90.9ns typ, 135ns min, 53.5ns max; typ from 1.8 V to 0.981 V
|   falling waveform, R_fixture 50, V_fixture 0: 20-80 % time 102ps typ, 118ps min, 93.6ps max; typ from 0.827 V to 0 V
|   rising waveform, R_fixture 50, V_fixture 1.8: 20-80 % time 268ps typ, 383ps min, 208ps max; typ from 0.981 V to 1.8 V
|   rising waveform, R_fixture 50, V_fixture 0: 20-80 % time 97.1ns typ, 145ns min, 58.4ns max; typ from 0 V to 0.827 V
[GND Clamp]
| Voltage   I(typ)   I(min)   I(max)
-1.204V   -737.9mA   -831.5mA   -678.7mA
-1.07V    -303.2mA   -410.8mA   -239.8mA
-1.003V   -139.9mA   -232.2mA   -95.74mA
-936.6mV  -46.51mA   -103.5mA   -29.5mA
-869.7mV  -15.31mA   -35.88mA   -15.36mA
-802.8mV  -8.166mA   -12.13mA   -11.29mA
-735.9mV  -5.335mA   -5.292mA   -8.195mA
-669mV    -3.356mA   -2.85mA    -5.457mA
-535.2mV  -837.9uA   -772uA     -1.483mA
-401.4mV  -47.36uA   -84.85uA   -76.77uA
3.6V      0A         0A         0A
[POWER Clamp]
| Voltage   I(typ)   I(min)   I(max)
-1.137V   660mA      807.5mA    561.8mA
-1.07V    454.5mA    608.2mA    356.2mA
-1.003V   275.7mA    418.4mA    193.6mA
-936.6mV  143.5mA    257.2mA    86.91mA
-869.7mV  59.43mA    137.9mA    27.31mA
-802.8mV  18.8mA     60.93mA    8.704mA
-735.9mV  6.231mA    21.35mA    5.155mA
-669mV    3.127mA    6.887mA    3.44mA
-535.2mV  940.9uA    1.232mA    1.058mA
-334.5mV  16.1uA     59.03uA    7.686uA
3.6V      0A         0A         0A
[Pulldown]
| Voltage   I(typ)   I(min)   I(max)
-1.8V     -4.87mA    -5.634mA   -3.709mA
-1.204V   -5.322mA   -5.739mA   -4.287mA
-1.137V   -5.874mA   -5.74mA    -6.349mA
-1.003V   -15.72mA   -10mA      -18.95mA
-869.7mV  -20.16mA   -15.75mA   -21.65mA
-602.1mV  -18.78mA   -14.16mA   -22.09mA
-468.3mV  -16.23mA   -11.81mA   -19.97mA
-267.6mV  -10.22mA   -7.094mA   -13.16mA
248.3mV   8.571mA    5.542mA    11.64mA
558.6mV   13.99mA    9.12mA     18.76mA
1.117V    16.78mA    11.11mA    22.02mA
3.6V      21.52mA    14.53mA    27.61mA
[Pullup]
| Voltage   I(typ)   I(min)   I(max)
-1.8V     6.616mA    6.844mA    6.292mA
-1.137V   6.451mA    6.346mA    6.921mA
-1.07V    8.638mA    6.363mA    12.1mA
-1.003V   13.93mA    8.365mA    20.24mA
-936.6mV  18.71mA    11.9mA     23.92mA
-869.7mV  20.24mA    14.77mA    23.76mA
-735.9mV  19.01mA    15.19mA    22.14mA
-468.3mV  13.72mA    10.73mA    16.42mA
310.3mV   -7.896mA   -5.828mA   -9.863mA
806.9mV   -15.2mA    -11.17mA   -19.03mA
1.738V    -19.83mA   -14.12mA   -25.45mA
3.6V      -22.96mA   -16.14mA   -29.94mA
[Ramp]
dV/dt_r   0.496138/97.0605n  0.370851/0.145088u  0.599587/58.3575n
dV/dt_f   0.491617/90.9259n  0.332419/0.135002u  0.629537/53.5132n
R_load = 50
[Falling Waveform]
R_fixture = 50
V_fixture = 1.8
V_fixture_min = 1.66
V_fixture_max = 1.89
| Time   V(typ)   V(min)   V(max)
0s        1.8V       1.66V      1.89V
9.562ns   1.8V       1.66V      1.87V
18.68ns   1.775V     1.659V     1.707V
35.03ns   1.641V     1.627V     1.423V
57.77ns   1.458V     1.544V     1.161V
82.84ns   1.306V     1.451V     1.004V
124.6ns   1.149V     1.33V      894.5mV
200.8ns   1.032V     1.206V     848.4mV
313.9ns   989.8mV    1.136V     841.2mV
800ns     980.6mV    1.106V     840.8mV
[Falling Waveform]
R_fixture = 50
V_fixture = 0
V_fixture_min = 0
V_fixture_max = 0
| Time   V(typ)   V(min)   V(max)
0s        826.9mV    618.5mV    999.3mV
211.5ps   826.7mV    618.5mV    978.7mV
280.9ps   798.9mV    618.5mV    552.4mV
334.6ps   543.9mV    618.8mV    227mV
384.3ps   287.6mV    594.1mV    83.82mV
424.8ps   140.7mV    480.7mV    38.25mV
527.8ps   21.47mV    147mV      7.803mV
626.4ps   5.97mV     26.8mV     4.643mV
1.499ns   1.466mV    1.261mV    1.547mV
800ns     10.15nV    683.7nV    3.814nV
[Rising Waveform]
R_fixture = 50
V_fixture = 1.8
V_fixture_min = 1.66
V_fixture_max = 1.89
| Time   V(typ)   V(min)   V(max)
0s        980.6mV    1.106V     840.8mV
294.7ps   980.7mV    1.106V     871.4mV
401ps     1.034V     1.106V     1.143V
500.8ps   1.227V     1.115V     1.461V
594.8ps   1.416V     1.197V     1.72V
689.9ps   1.576V     1.302V     1.857V
868.8ps   1.776V     1.463V     1.885V
1.19ns    1.797V     1.64V      1.887V
1.877ns   1.798V     1.659V     1.888V
800ns     1.8V       1.66V      1.89V
[Rising Waveform]
R_fixture = 50
V_fixture = 0
V_fixture_min = 0
V_fixture_max = 0
| Time   V(typ)   V(min)   V(max)
0s        10.12nV    682nV      3.808nV
11.8ns    140.5uV    -129.4uV   21.26mV
21.49ns   30.88mV    3.586mV    167.1mV
42.92ns   198mV      61.18mV    483.3mV
65.37ns   362.6mV    151.2mV    700.1mV
98.8ns    541mV      273.2mV    866.7mV
140.6ns   672.5mV    387.7mV    948.9mV
214ns     773.3mV    506.4mV    989.2mV
328.2ns   816mV      581.7mV    998.4mV
800ns     826.9mV    618.1mV    999.3mV
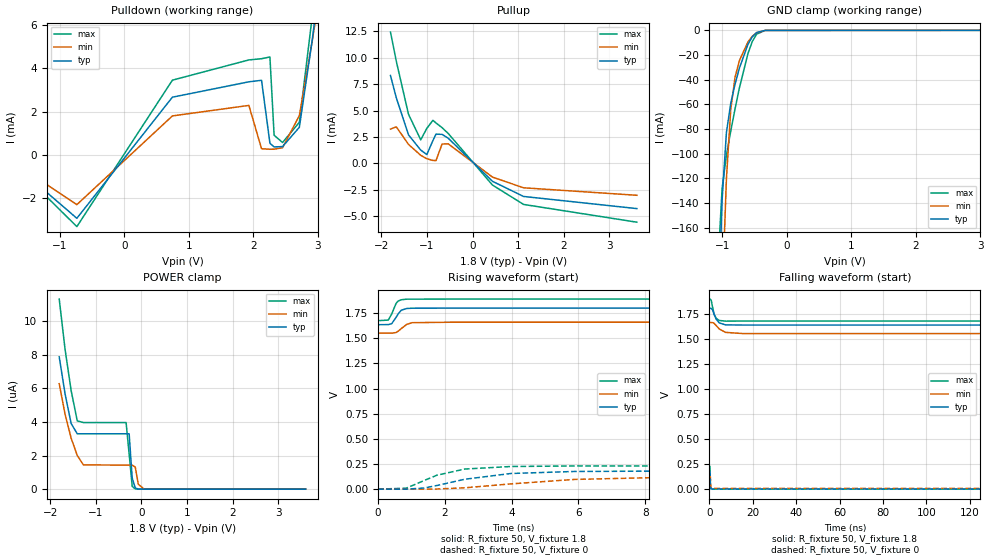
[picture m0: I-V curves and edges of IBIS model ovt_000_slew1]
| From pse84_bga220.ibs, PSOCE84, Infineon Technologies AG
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[Model] ovt_000_slew1
Model_type I/O
Enable   Active-High
Vinl  =  0.54
Vinh  =  1.26
Vmeas =  0.9
Cref  =  15e-12
| Capacitance   typ   min   max
C_comp   1.39974e-12   1.35992e-12   1.44753e-12
| Variables   typ   min   max
[GND Clamp Reference]   0   0   0
[POWER Clamp Reference]   1.8   1.66   1.89
[Pulldown Reference]   0   0   0
[Pullup Reference]   1.8   1.66   1.89
[Temperature Range]   25   125   -40
[Voltage Range]   1.8   1.66   1.89
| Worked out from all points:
|   slope of the pulldown table from 0 to 0.27 V, typ, clamps not added: 212 ohm
|   slope of the pullup table from 0 to 0.27 V, typ, clamps not added: 243 ohm
|   GND clamp passes 1 mA (typ) near -0.43 V on its own axis
|   falling waveform, R_fixture 50, V_fixture 1.8: 20-80 % time 2.16ns typ, 3.28ns min, 1.49ns max; typ from 1.8 V to 1.64 V
|   falling waveform, R_fixture 50, V_fixture 0: 20-80 % time 136ps typ, 155ps min, 126ps max; typ from 0.179 V to 0 V
|   rising waveform, R_fixture 50, V_fixture 1.8: 20-80 % time 193ps typ, 250ps min, 162ps max; typ from 1.64 V to 1.8 V
|   rising waveform, R_fixture 50, V_fixture 0: 20-80 % time 1.78ns typ, 3.17ns min, 1.15ns max; typ from 0 V to 0.179 V
[GND Clamp]
| Voltage   I(typ)   I(min)   I(max)
-1.271V   -717.5mA   -832.8mA   -643.6mA
-1.07V    -241.9mA   -348.3mA   -192.2mA
-1.003V   -137.2mA   -218.1mA   -128.1mA
-936.6mV  -83.06mA   -120.7mA   -101.3mA
-869.7mV  -59.26mA   -64.32mA   -81.77mA
-802.8mV  -43.7mA    -38.08mA   -63.69mA
-735.9mV  -30.76mA   -24.63mA   -46.83mA
-602.1mV  -11.27mA   -9.362mA   -18.72mA
-535.2mV  -5.241mA   -4.803mA   -9.042mA
-468.3mV  -1.746mA   -1.965mA   -3.086mA
-334.5mV  -35.9uA    -120.8uA   -33.39uA
3.6V      0A         0A         0A
[POWER Clamp]
| Voltage   I(typ)   I(min)   I(max)
-1.8V     7.872uA    6.273uA    11.31uA
-1.672V   5.671uA    4.461uA    8.32uA
-1.539V   3.91uA     3.037uA    5.87uA
-1.405V   3.295uA    2.008uA    4.063uA
-1.271V   3.295uA    1.447uA    3.964uA
-334.5mV  3.295uA    1.429uA    3.964uA
-267.6mV  3.295uA    1.429uA    2.099uA
-200.7mV  664.1nA    1.429uA    166.6nA
-133.8mV  69.92nA    1.319uA    14.86nA
-66.9mV   7.33nA     291.5nA    4.066nA
62.07mV   0A         0A         0A
3.6V      0A         0A         0A
[Pulldown]
| Voltage   I(typ)   I(min)   I(max)
-1.8V     -204uA     -190.9uA   -187.1uA
-735.9mV  -2.945mA   -2.313mA   -3.33mA
744.8mV   2.665mA    1.797mA    3.453mA
1.93V     3.376mA    2.283mA    4.39mA
2.126V    3.446mA    277.8uA    4.446mA
2.256V    530.7uA    252.6uA    4.526mA
2.321V    359.1uA    255.8uA    901uA
2.452V    376.3uA    323.9uA    565.3uA
2.712V    1.27mA     1.813mA    1.501mA
2.908V    5.234mA    5.199mA    6.315mA
2.973V    6.739mA    6.442mA    7.878mA
3.6V      20.58mA    5.273mA    23.65mA
[Pullup]
| Voltage   I(typ)   I(min)   I(max)
-1.8V     8.327mA    3.25mA     12.44mA
-1.672V   6.214mA    3.461mA    9.674mA
-1.405V   2.707mA    1.801mA    4.656mA
-1.137V   1.264mA    766.3uA    2.234mA
-1.003V   841.4uA    441.9uA    3.322mA
-869.7mV  2.166mA    282.3uA    4.082mA
-802.8mV  2.77mA     264.2uA    3.833mA
-669mV    2.752mA    1.835mA    3.384mA
-535.2mV  2.388mA    1.857mA    2.84mA
434.5mV   -1.694mA   -1.296mA   -2.048mA
1.117V    -3.13mA    -2.311mA   -3.886mA
3.6V      -4.282mA   -3.02mA    -5.569mA
[Ramp]
dV/dt_r   0.107423/1.78219n  76.4227m/3.16584n  0.137218/1.14779n
dV/dt_f   98.8496m/2.15781n  65.3414m/3.28267n  0.129087/1.49469n
R_load = 50
[Falling Waveform]
R_fixture = 50
V_fixture = 1.8
V_fixture_min = 1.66
V_fixture_max = 1.89
| Time   V(typ)   V(min)   V(max)
0s        1.8V       1.66V      1.89V
355.4ps   1.803V     1.66V      1.894V
845.6ps   1.8V       1.66V      1.882V
1.367ns   1.79V      1.66V      1.823V
2.124ns   1.744V     1.653V     1.749V
3.091ns   1.695V     1.631V     1.702V
4.545ns   1.656V     1.596V     1.681V
7.434ns   1.637V     1.562V     1.674V
15.61ns   1.635V     1.55V      1.675V
800ns     1.635V     1.551V     1.675V
[Falling Waveform]
R_fixture = 50
V_fixture = 0
V_fixture_min = 0
V_fixture_max = 0
| Time   V(typ)   V(min)   V(max)
0s        179mV      127.4mV    228.7mV
237.6ps   178.9mV    127.4mV    227.3mV
273ps     179mV      127.4mV    205.9mV
314.4ps   177mV      127.3mV    153.3mV
384.3ps   130.6mV    127.4mV    68.7mV
456.6ps   63.6mV     119.9mV    29.33mV
533.7ps   26.65mV    81.15mV    12.42mV
624.1ps   10.17mV    34.65mV    3.56mV
764.1ps   1.671mV    8.349mV    -217.7uV
800ns     41.07nV    1.897uV    20.44nV
[Rising Waveform]
R_fixture = 50
V_fixture = 1.8
V_fixture_min = 1.66
V_fixture_max = 1.89
| Time   V(typ)   V(min)   V(max)
0s        1.635V     1.551V     1.675V
303.6ps   1.636V     1.551V     1.681V
405.8ps   1.645V     1.551V     1.741V
537.1ps   1.708V     1.557V     1.847V
602.6ps   1.744V     1.571V     1.871V
691ps     1.779V     1.596V     1.883V
855.1ps   1.796V     1.638V     1.889V
1.015ns   1.799V     1.655V     1.889V
2.226ns   1.8V       1.66V      1.89V
800ns     1.8V       1.66V      1.89V
[Rising Waveform]
R_fixture = 50
V_fixture = 0
V_fixture_min = 0
V_fixture_max = 0
| Time   V(typ)   V(min)   V(max)
0s        41.07nV    1.896uV    20.45nV
837.7ps   -477.3uV   -630.1uV   8.776mV
1.368ns   10.52mV    -71.44uV   83.75mV
1.757ns   35.57mV    1.026mV    137.8mV
2.595ns   97.96mV    13mV       199.6mV
3.978ns   155.3mV    51.93mV    224.7mV
5.889ns   175.4mV    96.45mV    230.3mV
9.599ns   180.5mV    124mV      229.5mV
16.11ns   179.5mV    128.3mV    228.8mV
800ns     179mV      127.4mV    228.7mV
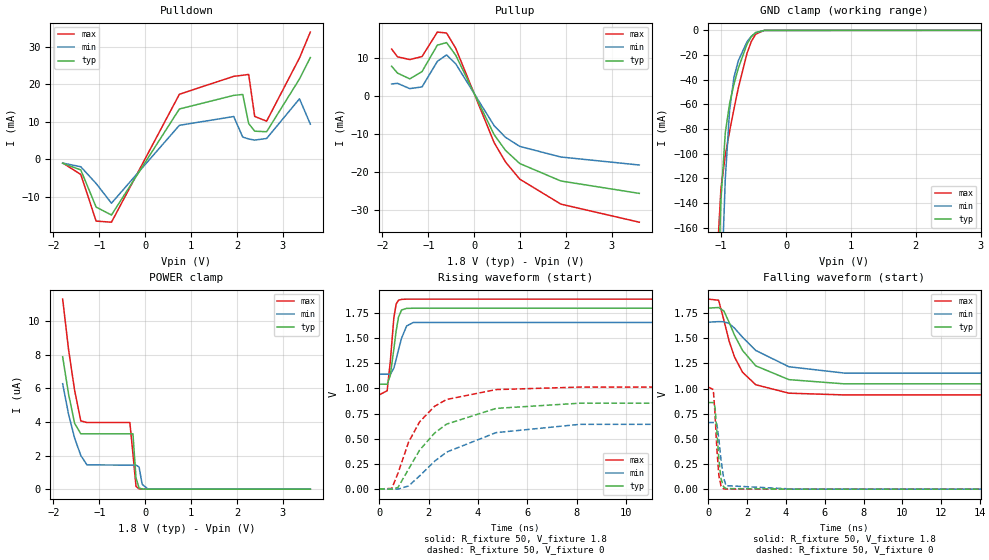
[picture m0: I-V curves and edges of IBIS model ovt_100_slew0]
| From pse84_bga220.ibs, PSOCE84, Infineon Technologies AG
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[Model] ovt_100_slew0
Model_type I/O
Enable   Active-High
Vinl  =  0.54
Vinh  =  1.26
Vmeas =  0.9
Cref  =  15e-12
| Capacitance   typ   min   max
C_comp   1.39974e-12   1.35992e-12   1.44753e-12
| Variables   typ   min   max
[GND Clamp Reference]   0   0   0
[POWER Clamp Reference]   1.8   1.66   1.89
[Pulldown Reference]   0   0   0
[Pullup Reference]   1.8   1.66   1.89
[Temperature Range]   25   125   -40
[Voltage Range]   1.8   1.66   1.89
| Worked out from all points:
|   slope of the pulldown table from 0 to 0.27 V, typ, clamps not added: 42.4 ohm
|   slope of the pullup table from 0 to 0.27 V, typ, clamps not added: 40.6 ohm
|   GND clamp passes 1 mA (typ) near -0.43 V on its own axis
|   falling waveform, R_fixture 50, V_fixture 1.8: 20-80 % time 1.58ns typ, 2.12ns min, 1.13ns max; typ from 1.8 V to 1.04 V
|   falling waveform, R_fixture 50, V_fixture 0: 20-80 % time 204ps typ, 242ps min, 184ps max; typ from 0.861 V to 0 V
|   rising waveform, R_fixture 50, V_fixture 1.8: 20-80 % time 244ps typ, 341ps min, 193ps max; typ from 1.04 V to 1.8 V
|   rising waveform, R_fixture 50, V_fixture 0: 20-80 % time 1.92ns typ, 2.58ns min, 1.38ns max; typ from 0 V to 0.861 V
[GND Clamp]
| Voltage   I(typ)   I(min)   I(max)
-1.271V   -717.5mA   -832.8mA   -643.6mA
-1.07V    -241.9mA   -348.3mA   -192.2mA
-1.003V   -137.2mA   -218.1mA   -128.1mA
-936.6mV  -83.06mA   -120.7mA   -101.3mA
-869.7mV  -59.26mA   -64.32mA   -81.77mA
-802.8mV  -43.7mA    -38.08mA   -63.69mA
-735.9mV  -30.76mA   -24.63mA   -46.83mA
-602.1mV  -11.27mA   -9.362mA   -18.72mA
-535.2mV  -5.241mA   -4.803mA   -9.042mA
-468.3mV  -1.746mA   -1.965mA   -3.086mA
-334.5mV  -35.9uA    -120.8uA   -33.39uA
3.6V      0A         0A         0A
[POWER Clamp]
| Voltage   I(typ)   I(min)   I(max)
-1.8V     7.872uA    6.273uA    11.31uA
-1.672V   5.671uA    4.461uA    8.32uA
-1.539V   3.91uA     3.037uA    5.87uA
-1.405V   3.295uA    2.008uA    4.063uA
-1.271V   3.295uA    1.447uA    3.964uA
-334.5mV  3.295uA    1.429uA    3.964uA
-267.6mV  3.295uA    1.429uA    2.099uA
-200.7mV  664.1nA    1.429uA    166.6nA
-133.8mV  69.92nA    1.319uA    14.86nA
-66.9mV   7.33nA     291.5nA    4.066nA
62.07mV   0A         0A         0A
3.6V      0A         0A         0A
[Pulldown]
| Voltage   I(typ)   I(min)   I(max)
-1.8V     -1.028mA   -963.9uA   -942uA
-1.405V   -2.792mA   -1.943mA   -3.987mA
-1.07V    -12.67mA   -6.4mA     -16.39mA
-735.9mV  -14.77mA   -11.63mA   -16.68mA
744.8mV   13.4mA     9.065mA    17.31mA
1.93V     17.02mA    11.4mA     22.09mA
2.126V    17.26mA    5.939mA    22.37mA
2.256V    9.55mA     5.438mA    22.59mA
2.387V    7.508mA    5.141mA    11.43mA
2.647V    7.356mA    5.567mA    10.17mA
3.364V    21.39mA    16.11mA    26.97mA
3.6V      27.07mA    9.377mA    33.84mA
[Pullup]
| Voltage   I(typ)   I(min)   I(max)
-1.8V     7.854mA    3.181mA    12.35mA
-1.672V   6.051mA    3.358mA    10.33mA
-1.405V   4.527mA    1.964mA    9.594mA
-1.137V   6.442mA    2.407mA    10.39mA
-802.8mV  13.39mA    9.12mA     16.82mA
-602.1mV  14.06mA    10.82mA    16.58mA
-401.4mV  10.72mA    8.468mA    12.54mA
434.5mV   -10.13mA   -7.771mA   -12.21mA
682.8mV   -14.26mA   -10.83mA   -17.31mA
993.1mV   -17.72mA   -13.22mA   -21.82mA
1.89V     -22.31mA   -16.01mA   -28.39mA
3.6V      -25.57mA   -18.11mA   -33.14mA
[Ramp]
dV/dt_r   0.516774/1.92301n  0.39749/2.5768n  0.609373/1.37882n
dV/dt_f   0.454125/1.57626n  0.310992/2.11585n  0.572099/1.1257n
R_load = 50
[Falling Waveform]
R_fixture = 50
V_fixture = 1.8
V_fixture_min = 1.66
V_fixture_max = 1.89
| Time   V(typ)   V(min)   V(max)
0s        1.8V       1.66V      1.89V
536.3ps   1.806V     1.666V     1.878V
808.5ps   1.771V     1.664V     1.68V
1.071ns   1.661V     1.648V     1.477V
1.355ns   1.531V     1.601V     1.314V
1.77ns    1.379V     1.51V      1.162V
2.449ns   1.226V     1.379V     1.038V
4.157ns   1.089V     1.217V     954.3mV
7.013ns   1.047V     1.154V     936.9mV
800ns     1.043V     1.142V     936.5mV
[Falling Waveform]
R_fixture = 50
V_fixture = 0
V_fixture_min = 0
V_fixture_max = 0
| Time   V(typ)   V(min)   V(max)
0s        861.3mV    662.5mV    1.016V
263.7ps   861.2mV    662.5mV    989.9mV
350.5ps   818.3mV    662.4mV    749.7mV
449.3ps   569.7mV    646.7mV    392.1mV
552.5ps   292.1mV    493.6mV    131.8mV
658.8ps   104.7mV    293.6mV    32.76mV
790.1ps   25.02mV    116mV      3.639mV
916.5ps   5.89mV     34.94mV    506.2uV
4.49ns    74.38uV    98.83uV    51.4uV
800ns     22.79nV    1.167uV    10.58nV
[Rising Waveform]
R_fixture = 50
V_fixture = 1.8
V_fixture_min = 1.66
V_fixture_max = 1.89
| Time   V(typ)   V(min)   V(max)
0s        1.043V     1.142V     936.5mV
321.1ps   1.042V     1.142V     977.3mV
449.9ps   1.132V     1.141V     1.272V
593ps     1.394V     1.203V     1.704V
687.5ps   1.576V     1.291V     1.842V
782.1ps   1.71V      1.386V     1.878V
904.2ps   1.781V     1.499V     1.887V
1.11ns    1.797V     1.622V     1.889V
1.381ns   1.799V     1.657V     1.889V
800ns     1.8V       1.66V      1.89V
[Rising Waveform]
R_fixture = 50
V_fixture = 0
V_fixture_min = 0
V_fixture_max = 0
| Time   V(typ)   V(min)   V(max)
0s        22.79nV    1.167uV    10.58nV
510.9ps   -2.131mV   -1.162mV   5.254mV
760.6ps   15.15mV    -1.433mV   156.4mV
1.191ns   197.8mV    29.81mV    466.6mV
1.636ns   386.1mV    129.5mV    667.7mV
2.242ns   555.6mV    275.1mV    822.2mV
2.73ns    645.2mV    366.8mV    890.6mV
4.736ns   801.8mV    560.5mV    988.8mV
8.144ns   853.6mV    643.2mV    1.014V
800ns     861.3mV    662.5mV    1.016V
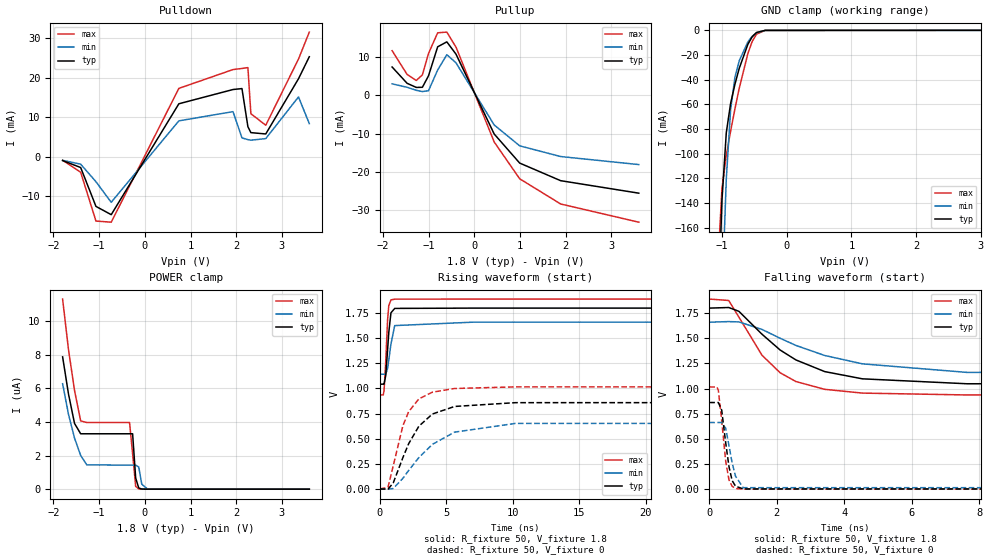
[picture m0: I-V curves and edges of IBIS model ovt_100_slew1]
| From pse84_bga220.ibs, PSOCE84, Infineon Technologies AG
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[Model] ovt_100_slew1
Model_type I/O
Enable   Active-High
Vinl  =  0.54
Vinh  =  1.26
Vmeas =  0.9
Cref  =  15e-12
| Capacitance   typ   min   max
C_comp   1.39974e-12   1.35992e-12   1.44753e-12
| Variables   typ   min   max
[GND Clamp Reference]   0   0   0
[POWER Clamp Reference]   1.8   1.66   1.89
[Pulldown Reference]   0   0   0
[Pullup Reference]   1.8   1.66   1.89
[Temperature Range]   25   125   -40
[Voltage Range]   1.8   1.66   1.89
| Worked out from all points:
|   slope of the pulldown table from 0 to 0.27 V, typ, clamps not added: 42.4 ohm
|   slope of the pullup table from 0 to 0.27 V, typ, clamps not added: 40.6 ohm
|   GND clamp passes 1 mA (typ) near -0.43 V on its own axis
|   falling waveform, R_fixture 50, V_fixture 1.8: 20-80 % time 1.95ns typ, 2.8ns min, 1.35ns max; typ from 1.8 V to 1.04 V
|   falling waveform, R_fixture 50, V_fixture 0: 20-80 % time 204ps typ, 241ps min, 184ps max; typ from 0.861 V to 0 V
|   rising waveform, R_fixture 50, V_fixture 1.8: 20-80 % time 245ps typ, 342ps min, 197ps max; typ from 1.04 V to 1.8 V
|   rising waveform, R_fixture 50, V_fixture 0: 20-80 % time 2.04ns typ, 3.11ns min, 1.4ns max; typ from 0 V to 0.861 V
[GND Clamp]
| Voltage   I(typ)   I(min)   I(max)
-1.271V   -717.5mA   -832.8mA   -643.6mA
-1.07V    -241.9mA   -348.3mA   -192.2mA
-1.003V   -137.2mA   -218.1mA   -128.1mA
-936.6mV  -83.06mA   -120.7mA   -101.3mA
-869.7mV  -59.26mA   -64.32mA   -81.77mA
-802.8mV  -43.7mA    -38.08mA   -63.69mA
-735.9mV  -30.76mA   -24.63mA   -46.83mA
-602.1mV  -11.27mA   -9.362mA   -18.72mA
-535.2mV  -5.241mA   -4.803mA   -9.042mA
-468.3mV  -1.746mA   -1.965mA   -3.086mA
-334.5mV  -35.9uA    -120.8uA   -33.39uA
3.6V      0A         0A         0A
[POWER Clamp]
| Voltage   I(typ)   I(min)   I(max)
-1.8V     7.872uA    6.273uA    11.31uA
-1.672V   5.671uA    4.461uA    8.32uA
-1.539V   3.91uA     3.037uA    5.87uA
-1.405V   3.295uA    2.008uA    4.063uA
-1.271V   3.295uA    1.447uA    3.964uA
-334.5mV  3.295uA    1.429uA    3.964uA
-267.6mV  3.295uA    1.429uA    2.099uA
-200.7mV  664.1nA    1.429uA    166.6nA
-133.8mV  69.92nA    1.319uA    14.86nA
-66.9mV   7.33nA     291.5nA    4.066nA
62.07mV   0A         0A         0A
3.6V      0A         0A         0A
[Pulldown]
| Voltage   I(typ)   I(min)   I(max)
-1.8V     -1.028mA   -963.9uA   -942uA
-1.405V   -2.792mA   -1.943mA   -3.987mA
-1.07V    -12.67mA   -6.4mA     -16.39mA
-735.9mV  -14.77mA   -11.63mA   -16.68mA
744.8mV   13.4mA     9.065mA    17.31mA
1.93V     17.02mA    11.4mA     22.09mA
2.126V    17.26mA    4.729mA    22.37mA
2.256V    7.572mA    4.289mA    22.59mA
2.321V    6.068mA    4.148mA    10.89mA
2.647V    5.734mA    4.556mA    7.947mA
3.364V    19.76mA    15.14mA    24.78mA
3.6V      25.35mA    8.354mA    31.61mA
[Pullup]
| Voltage   I(typ)   I(min)   I(max)
-1.8V     7.353mA    2.957mA    11.61mA
-1.472V   3.101mA    2.057mA    5.419mA
-1.271V   2.022mA    1.273mA    3.839mA
-1.137V   2.056mA    939.3uA    5.29mA
-1.003V   5.059mA    1.171mA    10.89mA
-802.8mV  12.62mA    6.565mA    16.27mA
-602.1mV  13.91mA    10.56mA    16.46mA
-401.4mV  10.7mA     8.441mA    12.53mA
434.5mV   -10.13mA   -7.771mA   -12.21mA
993.1mV   -17.72mA   -13.22mA   -21.82mA
1.89V     -22.31mA   -16.01mA   -28.39mA
3.6V      -25.57mA   -18.11mA   -33.14mA
[Ramp]
dV/dt_r   0.516774/2.04294n  0.397487/3.10756n  0.609373/1.40195n
dV/dt_f   0.454125/1.94843n  0.310991/2.79664n  0.572099/1.34861n
R_load = 50
[Falling Waveform]
R_fixture = 50
V_fixture = 1.8
V_fixture_min = 1.66
V_fixture_max = 1.89
| Time   V(typ)   V(min)   V(max)
0s        1.8V       1.66V      1.89V
576.8ps   1.806V     1.666V     1.876V
878.5ps   1.768V     1.663V     1.71V
1.564ns   1.54V      1.588V     1.331V
2.101ns   1.383V     1.5V       1.157V
2.567ns   1.285V     1.429V     1.07V
3.42ns    1.169V     1.329V     992.6mV
4.536ns   1.097V     1.246V     955.1mV
7.632ns   1.048V     1.161V     936.6mV
800ns     1.043V     1.142V     936.5mV
[Falling Waveform]
R_fixture = 50
V_fixture = 0
V_fixture_min = 0
V_fixture_max = 0
| Time   V(typ)   V(min)   V(max)
0s        861.3mV    662.5mV    1.016V
227.5ps   861.2mV    662.5mV    1.016V
270.3ps   861.3mV    662.5mV    980.2mV
368.8ps   784.9mV    662.5mV    681.6mV
488ps     457.6mV    605mV      274.8mV
583.7ps   224.5mV    432.7mV    93.09mV
676.6ps   86.12mV    264.1mV    29.37mV
777.3ps   29.89mV    129.1mV    6.68mV
1.005ns   2.462mV    14.86mV    434.4uV
800ns     22.79nV    1.167uV    10.58nV
[Rising Waveform]
R_fixture = 50
V_fixture = 1.8
V_fixture_min = 1.66
V_fixture_max = 1.89
| Time   V(typ)   V(min)   V(max)
0s        1.043V     1.142V     936.5mV
262.3ps   1.043V     1.142V     936.2mV
320.7ps   1.043V     1.142V     976.9mV
446.3ps   1.127V     1.141V     1.261V
589.4ps   1.387V     1.2V       1.686V
677.8ps   1.558V     1.282V     1.824V
840.7ps   1.753V     1.442V     1.882V
1.125ns   1.797V     1.626V     1.889V
7ns       1.8V       1.66V      1.89V
800ns     1.8V       1.66V      1.89V
[Rising Waveform]
R_fixture = 50
V_fixture = 0
V_fixture_min = 0
V_fixture_max = 0
| Time   V(typ)   V(min)   V(max)
0s        22.79nV    1.167uV    10.58nV
616.2ps   -1.979mV   -1.449mV   15.43mV
1.01ns    59.16mV    4.221mV    228.5mV
1.735ns   310.4mV    105.5mV    627.4mV
2.171ns   449.7mV    183.8mV    768.3mV
2.939ns   624.2mV    312.1mV    896.1mV
3.961ns   746mV      444mV      963.4mV
5.63ns    821.2mV    565.8mV    1V
10.21ns   859mV      652.4mV    1.016V
800ns     861.3mV    662.5mV    1.016V
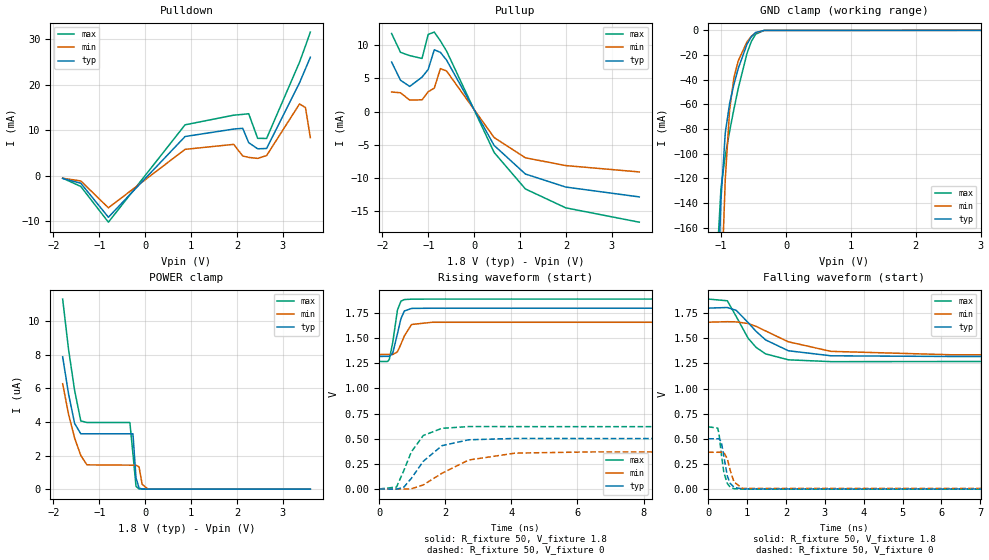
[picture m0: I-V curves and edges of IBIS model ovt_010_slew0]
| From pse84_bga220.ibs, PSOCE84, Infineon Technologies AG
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[Model] ovt_010_slew0
Model_type I/O
Enable   Active-High
Vinl  =  0.54
Vinh  =  1.26
Vmeas =  0.9
Cref  =  15e-12
| Capacitance   typ   min   max
C_comp   1.39974e-12   1.35992e-12   1.44753e-12
| Variables   typ   min   max
[GND Clamp Reference]   0   0   0
[POWER Clamp Reference]   1.8   1.66   1.89
[Pulldown Reference]   0   0   0
[Pullup Reference]   1.8   1.66   1.89
[Temperature Range]   25   125   -40
[Voltage Range]   1.8   1.66   1.89
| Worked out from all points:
|   slope of the pulldown table from 0 to 0.27 V, typ, clamps not added: 70.3 ohm
|   slope of the pullup table from 0 to 0.27 V, typ, clamps not added: 80.5 ohm
|   GND clamp passes 1 mA (typ) near -0.43 V on its own axis
|   falling waveform, R_fixture 50, V_fixture 1.8: 20-80 % time 858ps typ, 1.25ns min, 624ps max; typ from 1.8 V to 1.32 V
|   falling waveform, R_fixture 50, V_fixture 0: 20-80 % time 142ps typ, 164ps min, 131ps max; typ from 0.501 V to 0 V
|   rising waveform, R_fixture 50, V_fixture 1.8: 20-80 % time 201ps typ, 265ps min, 166ps max; typ from 1.32 V to 1.8 V
|   rising waveform, R_fixture 50, V_fixture 0: 20-80 % time 775ps typ, 1.26ns min, 542ps max; typ from 0 V to 0.501 V
[GND Clamp]
| Voltage   I(typ)   I(min)   I(max)
-1.271V   -717.5mA   -832.8mA   -643.6mA
-1.07V    -241.9mA   -348.3mA   -192.2mA
-1.003V   -137.2mA   -218.1mA   -128.1mA
-936.6mV  -83.06mA   -120.7mA   -101.3mA
-869.7mV  -59.26mA   -64.32mA   -81.77mA
-802.8mV  -43.7mA    -38.08mA   -63.69mA
-735.9mV  -30.76mA   -24.63mA   -46.83mA
-602.1mV  -11.27mA   -9.362mA   -18.72mA
-535.2mV  -5.241mA   -4.803mA   -9.042mA
-468.3mV  -1.746mA   -1.965mA   -3.086mA
-334.5mV  -35.9uA    -120.8uA   -33.39uA
3.6V      0A         0A         0A
[POWER Clamp]
| Voltage   I(typ)   I(min)   I(max)
-1.8V     7.872uA    6.273uA    11.31uA
-1.672V   5.671uA    4.461uA    8.32uA
-1.539V   3.91uA     3.037uA    5.87uA
-1.405V   3.295uA    2.008uA    4.063uA
-1.271V   3.295uA    1.447uA    3.964uA
-334.5mV  3.295uA    1.429uA    3.964uA
-267.6mV  3.295uA    1.429uA    2.099uA
-200.7mV  664.1nA    1.429uA    166.6nA
-133.8mV  69.92nA    1.319uA    14.86nA
-66.9mV   7.33nA     291.5nA    4.066nA
62.07mV   0A         0A         0A
3.6V      0A         0A         0A
[Pulldown]
| Voltage   I(typ)   I(min)   I(max)
-1.8V     -616.6uA   -578.4uA   -564.6uA
-1.405V   -1.672mA   -1.165mA   -2.377mA
-802.8mV  -9.141mA   -7.072mA   -10.23mA
869mV     8.589mA    5.772mA    11.16mA
1.93V     10.23mA    6.865mA    13.28mA
2.126V    10.39mA    4.31mA     13.45mA
2.256V    7.243mA    4.007mA    13.6mA
2.452V    5.895mA    3.781mA    8.189mA
2.647V    5.961mA    4.407mA    8.167mA
3.364V    20.38mA    15.74mA    24.9mA
3.494V    23.46mA    14.96mA    28.5mA
3.6V      26mA       8.362mA    31.53mA
[Pullup]
| Voltage   I(typ)   I(min)   I(max)
-1.8V     7.479mA    2.959mA    11.79mA
-1.606V   4.733mA    2.843mA    8.949mA
-1.405V   3.802mA    1.735mA    8.454mA
-1.137V   5.208mA    1.78mA     8.025mA
-1.003V   6.365mA    2.994mA    11.66mA
-869.7mV  9.334mA    3.547mA    12.01mA
-735.9mV  8.942mA    6.492mA    10.68mA
-602.1mV  7.78mA     6.132mA    9.143mA
434.5mV   -5.11mA    -3.918mA   -6.166mA
1.117V    -9.434mA   -6.982mA   -11.69mA
1.996V    -11.4mA    -8.156mA   -14.54mA
3.6V      -12.89mA   -9.118mA   -16.71mA
[Ramp]
dV/dt_r   0.300724/0.775237n  0.220144/1.25733n  0.37204/0.542178n
dV/dt_f   0.288397/0.85767n  0.193196/1.24815n  0.37244/0.624223n
R_load = 50
[Falling Waveform]
R_fixture = 50
V_fixture = 1.8
V_fixture_min = 1.66
V_fixture_max = 1.89
| Time   V(typ)   V(min)   V(max)
0s        1.8V       1.66V      1.89V
491.9ps   1.806V     1.665V     1.873V
720.2ps   1.778V     1.663V     1.717V
1.028ns   1.656V     1.647V     1.5V
1.234ns   1.568V     1.618V     1.409V
1.477ns   1.484V     1.573V     1.345V
2.063ns   1.376V     1.465V     1.286V
3.16ns    1.326V     1.37V      1.268V
6.26ns    1.319V     1.336V     1.269V
800ns     1.319V     1.338V     1.269V
[Falling Waveform]
R_fixture = 50
V_fixture = 0
V_fixture_min = 0
V_fixture_max = 0
| Time   V(typ)   V(min)   V(max)
0s        501.2mV    366.9mV    620.1mV
246.9ps   501mV      366.9mV    606.8mV
282.6ps   501.7mV    366.9mV    536.9mV
339ps     467.5mV    366.8mV    346mV
402.4ps   326.6mV    367mV      166.1mV
492.6ps   129.6mV    301.6mV    55.62mV
564.2ps   58.43mV    189.8mV    20.82mV
665ps     19.08mV    71.26mV    4.909mV
876.2ps   1.709mV    8.266mV    547.7uV
800ns     29.26nV    1.443uV    13.92nV
[Rising Waveform]
R_fixture = 50
V_fixture = 1.8
V_fixture_min = 1.66
V_fixture_max = 1.89
| Time   V(typ)   V(min)   V(max)
0s        1.319V     1.338V     1.269V
258.2ps   1.32V      1.338V     1.269V
306.2ps   1.319V     1.338V     1.291V
409.5ps   1.353V     1.338V     1.46V
550.9ps   1.545V     1.365V     1.78V
657.3ps   1.695V     1.442V     1.869V
759.8ps   1.771V     1.523V     1.885V
978.4ps   1.797V     1.637V     1.889V
1.6ns     1.799V     1.659V     1.89V
800ns     1.8V       1.66V      1.89V
[Rising Waveform]
R_fixture = 50
V_fixture = 0
V_fixture_min = 0
V_fixture_max = 0
| Time   V(typ)   V(min)   V(max)
0s        29.27nV    1.443uV    13.92nV
524.8ps   -1.975mV   -1.017mV   19.41mV
740ps     16.9mV     -1.439mV   180.4mV
971.7ps   105.4mV    1.674mV    368.9mV
1.334ns   275.8mV    40.31mV    532.5mV
1.899ns   431mV      156.3mV    603.7mV
2.71ns    489.5mV    288.3mV    621.1mV
4.123ns   503mV      357.1mV    620.7mV
6.476ns   501.9mV    368.9mV    620mV
800ns     501.2mV    366.9mV    620.1mV
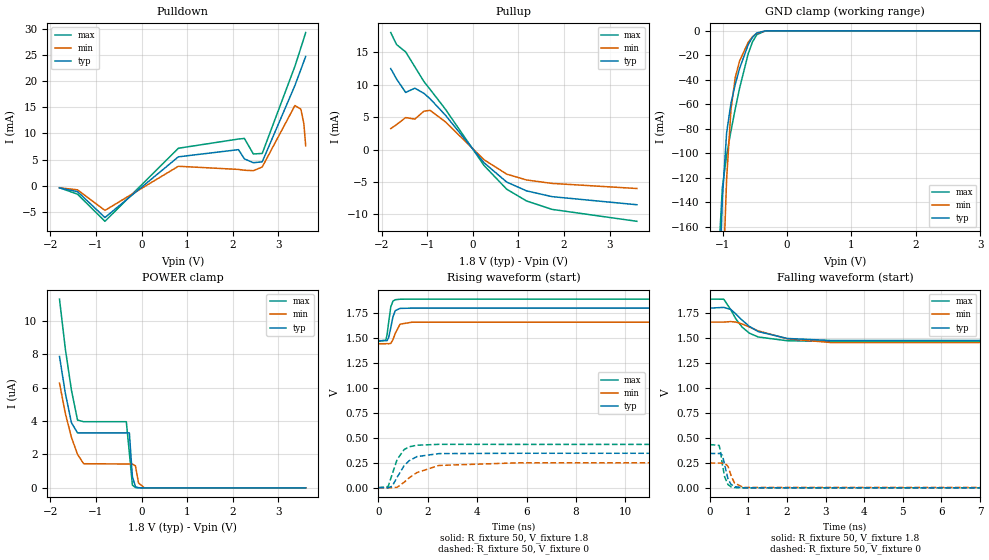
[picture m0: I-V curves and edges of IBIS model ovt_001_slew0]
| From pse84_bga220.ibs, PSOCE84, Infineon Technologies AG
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[Model] ovt_001_slew0
Model_type I/O
Enable   Active-High
Vinl  =  0.54
Vinh  =  1.26
Vmeas =  0.9
Cref  =  15e-12
| Capacitance   typ   min   max
C_comp   1.39974e-12   1.35992e-12   1.44753e-12
| Variables   typ   min   max
[GND Clamp Reference]   0   0   0
[POWER Clamp Reference]   1.8   1.66   1.89
[Pulldown Reference]   0   0   0
[Pullup Reference]   1.8   1.66   1.89
[Temperature Range]   25   125   -40
[Voltage Range]   1.8   1.66   1.89
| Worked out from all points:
|   slope of the pulldown table from 0 to 0.27 V, typ, clamps not added: 107 ohm
|   slope of the pullup table from 0 to 0.27 V, typ, clamps not added: 122 ohm
|   GND clamp passes 1 mA (typ) near -0.43 V on its own axis
|   falling waveform, R_fixture 50, V_fixture 1.8: 20-80 % time 735ps typ, 1.12ns min, 507ps max; typ from 1.8 V to 1.47 V
|   falling waveform, R_fixture 50, V_fixture 0: 20-80 % time 131ps typ, 150ps min, 118ps max; typ from 0.344 V to 0 V
|   rising waveform, R_fixture 50, V_fixture 1.8: 20-80 % time 163ps typ, 216ps min, 134ps max; typ from 1.47 V to 1.8 V
|   rising waveform, R_fixture 50, V_fixture 0: 20-80 % time 590ps typ, 991ps min, 401ps max; typ from 0 V to 0.344 V
[GND Clamp]
| Voltage   I(typ)   I(min)   I(max)
-1.271V   -717.5mA   -832.8mA   -643.6mA
-1.07V    -241.9mA   -348.3mA   -192.2mA
-1.003V   -137.2mA   -218.1mA   -128.1mA
-936.6mV  -83.06mA   -120.7mA   -101.3mA
-869.7mV  -59.26mA   -64.32mA   -81.77mA
-802.8mV  -43.7mA    -38.08mA   -63.69mA
-735.9mV  -30.76mA   -24.63mA   -46.83mA
-602.1mV  -11.27mA   -9.362mA   -18.72mA
-535.2mV  -5.241mA   -4.803mA   -9.042mA
-468.3mV  -1.746mA   -1.965mA   -3.086mA
-334.5mV  -35.9uA    -120.8uA   -33.39uA
3.6V      0A         0A         0A
[POWER Clamp]
| Voltage   I(typ)   I(min)   I(max)
-1.8V     7.872uA    6.273uA    11.31uA
-1.672V   5.671uA    4.461uA    8.32uA
-1.539V   3.91uA     3.037uA    5.87uA
-1.405V   3.295uA    2.008uA    4.063uA
-1.271V   3.295uA    1.447uA    3.964uA
-334.5mV  3.295uA    1.429uA    3.964uA
-267.6mV  3.295uA    1.429uA    2.099uA
-200.7mV  664.1nA    1.429uA    166.6nA
-133.8mV  69.92nA    1.319uA    14.86nA
-66.9mV   7.33nA     291.5nA    4.066nA
62.07mV   0A         0A         0A
3.6V      0A         0A         0A
[Pulldown]
| Voltage   I(typ)   I(min)   I(max)
-1.8V     -410.9uA   -384.6uA   -377uA
-1.405V   -1.119mA   -775.9uA   -1.606mA
-802.8mV  -6.059mA   -4.694mA   -6.784mA
806.9mV   5.531mA    3.728mA    7.17mA
2.126V    6.905mA    3.127mA    8.932mA
2.256V    5.139mA    2.97mA     9.046mA
2.452V    4.411mA    2.887mA    6.078mA
2.647V    4.572mA    3.591mA    6.177mA
3.364V    19.16mA    15.33mA    22.83mA
3.494V    22.2mA     14.64mA    26.34mA
3.56V     23.75mA    11.89mA    28.14mA
3.6V      24.7mA     7.654mA    29.27mA
[Pullup]
| Voltage   I(typ)   I(min)   I(max)
-1.8V     12.49mA    3.223mA    18.05mA
-1.672V   10.88mA    3.852mA    16.2mA
-1.472V   8.807mA    4.932mA    15.06mA
-1.271V   9.47mA     4.7mA      12.77mA
-1.07V    8.664mA    5.927mA    10.47mA
-936.6mV  7.834mA    6.048mA    9.288mA
-602.1mV  5.317mA    4.282mA    6.237mA
248.3mV   -2.049mA   -1.578mA   -2.472mA
744.8mV   -5.02mA    -3.793mA   -6.123mA
1.179V    -6.373mA   -4.692mA   -7.932mA
1.738V    -7.266mA   -5.224mA   -9.231mA
3.6V      -8.515mA   -6.011mA   -11.07mA
[Ramp]
dV/dt_r   0.206668/0.589567n  0.14889/0.990821n  0.260239/0.400886n
dV/dt_f   0.195417/0.735314n  0.130018/1.12381n  0.253909/0.506534n
R_load = 50
[Falling Waveform]
R_fixture = 50
V_fixture = 1.8
V_fixture_min = 1.66
V_fixture_max = 1.89
| Time   V(typ)   V(min)   V(max)
0s        1.8V       1.66V      1.89V
366ps     1.807V     1.66V      1.889V
545.4ps   1.787V     1.665V     1.784V
680ps     1.741V     1.66V      1.691V
841.7ps   1.679V     1.641V     1.609V
1.029ns   1.617V     1.61V      1.549V
1.256ns   1.565V     1.572V     1.511V
2.01ns    1.496V     1.493V     1.473V
3.148ns   1.476V     1.455V     1.466V
800ns     1.474V     1.443V     1.467V
[Falling Waveform]
R_fixture = 50
V_fixture = 0
V_fixture_min = 0
V_fixture_max = 0
| Time   V(typ)   V(min)   V(max)
0s        344.4mV    248.2mV    433.7mV
244.2ps   344.3mV    248.1mV    425.3mV
277.2ps   344.8mV    248.1mV    374.9mV
332.5ps   324.4mV    248mV      226.5mV
389.8ps   228.4mV    248.5mV    108mV
473.8ps   90.34mV    215.5mV    33.55mV
552.8ps   35.27mV    124.2mV    10.66mV
642.9ps   12mV       48.45mV    2.665mV
876.1ps   699.8uV    4.06mV     404.3uV
800ns     34.28nV    1.642uV    16.63nV
[Rising Waveform]
R_fixture = 50
V_fixture = 1.8
V_fixture_min = 1.66
V_fixture_max = 1.89
| Time   V(typ)   V(min)   V(max)
0s        1.474V     1.443V     1.467V
300.4ps   1.474V     1.443V     1.479V
351.4ps   1.474V     1.444V     1.537V
413.7ps   1.504V     1.443V     1.657V
500.1ps   1.603V     1.446V     1.812V
588.4ps   1.713V     1.485V     1.87V
683ps     1.775V     1.547V     1.884V
877.3ps   1.797V     1.639V     1.889V
1.371ns   1.8V       1.659V     1.89V
800ns     1.8V       1.66V      1.89V
[Rising Waveform]
R_fixture = 50
V_fixture = 0
V_fixture_min = 0
V_fixture_max = 0
| Time   V(typ)   V(min)   V(max)
0s        34.28nV    1.642uV    16.63nV
393.6ps   -1.724mV   140.3uV    11.47mV
560.4ps   15.63mV    -1.359mV   137.3mV
756.9ps   105mV      4.291mV    282.3mV
1.044ns   221.2mV    54.96mV    382.6mV
1.246ns   270.3mV    98.99mV    409.6mV
1.556ns   311.4mV    151.1mV    425.7mV
2.449ns   341.6mV    223mV      434.4mV
5.655ns   344.9mV    249.1mV    433.8mV
800ns     344.4mV    248.2mV    433.7mV
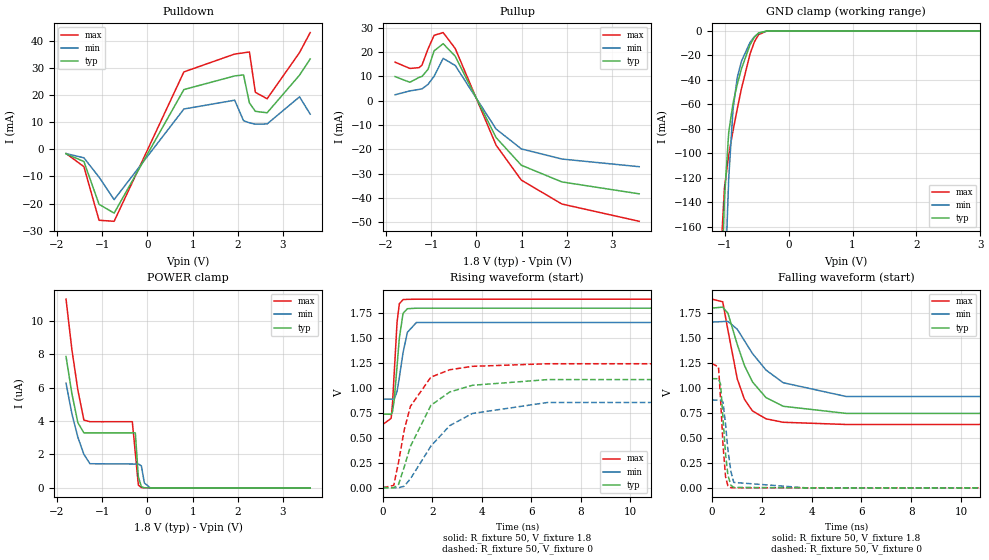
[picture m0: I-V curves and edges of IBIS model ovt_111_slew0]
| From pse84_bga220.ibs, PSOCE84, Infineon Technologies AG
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[Model] ovt_111_slew0
Model_type I/O
Enable   Active-High
Vinl  =  0.54
Vinh  =  1.26
Vmeas =  0.9
Cref  =  15e-12
| Capacitance   typ   min   max
C_comp   1.39974e-12   1.35992e-12   1.44753e-12
| Variables   typ   min   max
[GND Clamp Reference]   0   0   0
[POWER Clamp Reference]   1.8   1.66   1.89
[Pulldown Reference]   0   0   0
[Pullup Reference]   1.8   1.66   1.89
[Temperature Range]   25   125   -40
[Voltage Range]   1.8   1.66   1.89
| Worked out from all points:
|   slope of the pulldown table from 0 to 0.27 V, typ, clamps not added: 26.7 ohm
|   slope of the pullup table from 0 to 0.27 V, typ, clamps not added: 27.1 ohm
|   GND clamp passes 1 mA (typ) near -0.43 V on its own axis
|   falling waveform, R_fixture 50, V_fixture 1.8: 20-80 % time 1.13ns typ, 1.72ns min, 704ps max; typ from 1.8 V to 0.737 V
|   falling waveform, R_fixture 50, V_fixture 0: 20-80 % time 195ps typ, 231ps min, 169ps max; typ from 1.09 V to 0 V
|   rising waveform, R_fixture 50, V_fixture 1.8: 20-80 % time 216ps typ, 305ps min, 167ps max; typ from 0.737 V to 1.8 V
|   rising waveform, R_fixture 50, V_fixture 0: 20-80 % time 1.27ns typ, 1.91ns min, 842ps max; typ from 0 V to 1.09 V
[GND Clamp]
| Voltage   I(typ)   I(min)   I(max)
-1.271V   -717.5mA   -832.8mA   -643.6mA
-1.07V    -241.9mA   -348.3mA   -192.2mA
-1.003V   -137.2mA   -218.1mA   -128.1mA
-936.6mV  -83.06mA   -120.7mA   -101.3mA
-869.7mV  -59.26mA   -64.32mA   -81.77mA
-802.8mV  -43.7mA    -38.08mA   -63.69mA
-735.9mV  -30.76mA   -24.63mA   -46.83mA
-602.1mV  -11.27mA   -9.362mA   -18.72mA
-535.2mV  -5.241mA   -4.803mA   -9.042mA
-468.3mV  -1.746mA   -1.965mA   -3.086mA
-334.5mV  -35.9uA    -120.8uA   -33.39uA
3.6V      0A         0A         0A
[POWER Clamp]
| Voltage   I(typ)   I(min)   I(max)
-1.8V     7.872uA    6.273uA    11.31uA
-1.672V   5.671uA    4.461uA    8.32uA
-1.539V   3.91uA     3.037uA    5.87uA
-1.405V   3.295uA    2.008uA    4.063uA
-1.271V   3.295uA    1.447uA    3.964uA
-334.5mV  3.295uA    1.429uA    3.964uA
-267.6mV  3.295uA    1.429uA    2.099uA
-200.7mV  664.1nA    1.429uA    166.6nA
-133.8mV  69.92nA    1.319uA    14.86nA
-66.9mV   7.33nA     291.5nA    4.066nA
62.07mV   0A         0A         0A
3.6V      0A         0A         0A
[Pulldown]
| Voltage   I(typ)   I(min)   I(max)
-1.8V     -1.643mA   -1.541mA   -1.506mA
-1.405V   -4.463mA   -3.106mA   -6.378mA
-1.07V    -20.3mA    -10.25mA   -26.2mA
-735.9mV  -23.55mA   -18.56mA   -26.58mA
806.9mV   22.12mA    14.93mA    28.65mA
1.93V     27.16mA    18.19mA    35.25mA
2.126V    27.53mA    10.6mA     35.7mA
2.256V    17.2mA     9.825mA    36.02mA
2.387V    14.08mA    9.323mA    21.12mA
2.647V    13.53mA    9.406mA    18.71mA
3.364V    27.44mA    19.43mA    35.79mA
3.6V      33.43mA    13.05mA    43.19mA
[Pullup]
| Voltage   I(typ)   I(min)   I(max)
-1.8V     9.923mA    2.451mA    15.87mA
-1.472V   7.587mA    4.045mA    13.28mA
-1.271V   9.571mA    4.651mA    13.6mA
-1.204V   9.998mA    4.87mA     14.68mA
-1.07V    12.94mA    6.734mA    21.32mA
-936.6mV  20.5mA     10.06mA    26.9mA
-735.9mV  23.46mA    17.42mA    28.04mA
-468.3mV  18.29mA    14.49mA    21.46mA
434.5mV   -15.16mA   -11.64mA   -18.27mA
993.1mV   -26.54mA   -19.81mA   -32.66mA
1.89V     -33.4mA    -23.98mA   -42.49mA
3.6V      -38.3mA    -27.14mA   -49.6mA
[Ramp]
dV/dt_r   0.655633/1.27467n  0.527663/1.91175n  0.747054/0.842172n
dV/dt_f   0.637742/1.12661n  0.463302/1.72249n  0.754102/0.703993n
R_load = 50
[Falling Waveform]
R_fixture = 50
V_fixture = 1.8
V_fixture_min = 1.66
V_fixture_max = 1.89
| Time   V(typ)   V(min)   V(max)
0s        1.8V       1.66V      1.89V
436.9ps   1.81V      1.665V     1.863V
646.3ps   1.748V     1.667V     1.577V
1.021ns   1.435V     1.588V     1.09V
1.307ns   1.226V     1.474V     887.1mV
1.628ns   1.062V     1.346V     770.7mV
2.171ns   903.9mV    1.18V      691.7mV
2.863ns   817.2mV    1.053V     656.8mV
5.391ns   745.8mV    915.1mV    634.7mV
800ns     737.1mV    887.8mV    633.2mV
[Falling Waveform]
R_fixture = 50
V_fixture = 0
V_fixture_min = 0
V_fixture_max = 0
| Time   V(typ)   V(min)   V(max)
0s        1.093V     879.4mV    1.245V
266ps     1.093V     879.4mV    1.212V
350.4ps   1.037V     879.3mV    885.7mV
447.6ps   692.4mV    858.9mV    429.2mV
549.1ps   340.7mV    638mV      112.3mV
643.7ps   127.8mV    383.6mV    20.22mV
765.3ps   24.63mV    163.6mV    1.92mV
879.7ps   4.999mV    54.46mV    739.5uV
3.783ns   93.93uV    130.5uV    66.74uV
800ns     17.15nV    908.6nV    7.793nV
[Rising Waveform]
R_fixture = 50
V_fixture = 1.8
V_fixture_min = 1.66
V_fixture_max = 1.89
| Time   V(typ)   V(min)   V(max)
0s        737.1mV    887.8mV    633.2mV
335.5ps   735.4mV    888mV      694.1mV
389.2ps   760.9mV    888.1mV    836.9mV
459.2ps   878mV      886mV      1.148V
574.3ps   1.22V      963.7mV    1.659V
666.5ps   1.499V     1.103V     1.844V
815.7ps   1.747V     1.353V     1.885V
991.3ps   1.794V     1.557V     1.888V
1.356ns   1.799V     1.656V     1.889V
800ns     1.8V       1.66V      1.89V
[Rising Waveform]
R_fixture = 50
V_fixture = 0
V_fixture_min = 0
V_fixture_max = 0
| Time   V(typ)   V(min)   V(max)
0s        17.15nV    908.5nV    7.799nV
439ps     -2.613mV   -401.2uV   21.96mV
634.4ps   32.41mV    -2.068mV   255.2mV
865.9ps   208.9mV    14.59mV    581.2mV
1.115ns   415mV      88.42mV    815.5mV
1.942ns   825.3mV    416.6mV    1.108V
2.704ns   959.3mV    621.7mV    1.182V
3.617ns   1.026V     743.4mV    1.216V
6.655ns   1.083V     853.7mV    1.242V
800ns     1.093V     879.4mV    1.245V
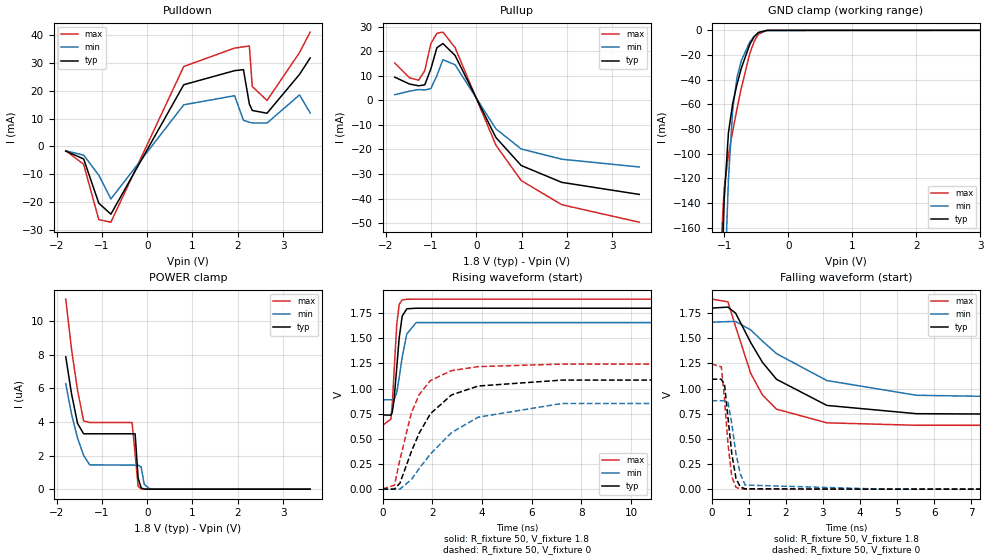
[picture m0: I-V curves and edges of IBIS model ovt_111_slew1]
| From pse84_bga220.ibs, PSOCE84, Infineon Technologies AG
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[Model] ovt_111_slew1
Model_type I/O
Enable   Active-High
Vinl  =  0.54
Vinh  =  1.26
Vmeas =  0.9
Cref  =  15e-12
| Capacitance   typ   min   max
C_comp   1.39974e-12   1.35992e-12   1.44753e-12
| Variables   typ   min   max
[GND Clamp Reference]   0   0   0
[POWER Clamp Reference]   1.8   1.66   1.89
[Pulldown Reference]   0   0   0
[Pullup Reference]   1.8   1.66   1.89
[Temperature Range]   25   125   -40
[Voltage Range]   1.8   1.66   1.89
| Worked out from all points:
|   slope of the pulldown table from 0 to 0.27 V, typ, clamps not added: 26.7 ohm
|   slope of the pullup table from 0 to 0.27 V, typ, clamps not added: 27.1 ohm
|   GND clamp passes 1 mA (typ) near -0.43 V on its own axis
|   falling waveform, R_fixture 50, V_fixture 1.8: 20-80 % time 1.38ns typ, 2.18ns min, 851ps max; typ from 1.8 V to 0.737 V
|   falling waveform, R_fixture 50, V_fixture 0: 20-80 % time 195ps typ, 231ps min, 170ps max; typ from 1.09 V to 0 V
|   rising waveform, R_fixture 50, V_fixture 1.8: 20-80 % time 217ps typ, 305ps min, 170ps max; typ from 0.737 V to 1.8 V
|   rising waveform, R_fixture 50, V_fixture 0: 20-80 % time 1.48ns typ, 2.35ns min, 954ps max; typ from 0 V to 1.09 V
[GND Clamp]
| Voltage   I(typ)   I(min)   I(max)
-1.271V   -717.5mA   -832.8mA   -643.6mA
-1.07V    -241.9mA   -348.3mA   -192.2mA
-1.003V   -137.2mA   -218.1mA   -128.1mA
-936.6mV  -83.06mA   -120.7mA   -101.3mA
-869.7mV  -59.26mA   -64.32mA   -81.77mA
-802.8mV  -43.7mA    -38.08mA   -63.69mA
-735.9mV  -30.76mA   -24.63mA   -46.83mA
-602.1mV  -11.27mA   -9.362mA   -18.72mA
-535.2mV  -5.241mA   -4.803mA   -9.042mA
-468.3mV  -1.746mA   -1.965mA   -3.086mA
-334.5mV  -35.9uA    -120.8uA   -33.39uA
3.6V      0A         0A         0A
[POWER Clamp]
| Voltage   I(typ)   I(min)   I(max)
-1.8V     7.872uA    6.273uA    11.31uA
-1.672V   5.671uA    4.461uA    8.32uA
-1.539V   3.91uA     3.037uA    5.87uA
-1.405V   3.295uA    2.008uA    4.063uA
-1.271V   3.295uA    1.447uA    3.964uA
-334.5mV  3.295uA    1.429uA    3.964uA
-267.6mV  3.295uA    1.429uA    2.099uA
-200.7mV  664.1nA    1.429uA    166.6nA
-133.8mV  69.92nA    1.319uA    14.86nA
-66.9mV   7.33nA     291.5nA    4.066nA
62.07mV   0A         0A         0A
3.6V      0A         0A         0A
[Pulldown]
| Voltage   I(typ)   I(min)   I(max)
-1.8V     -1.643mA   -1.541mA   -1.506mA
-1.405V   -4.463mA   -3.106mA   -6.378mA
-1.07V    -20.3mA    -10.25mA   -26.2mA
-802.8mV  -24.25mA   -18.81mA   -27.12mA
806.9mV   22.12mA    14.93mA    28.65mA
1.93V     27.16mA    18.19mA    35.25mA
2.126V    27.53mA    9.396mA    35.7mA
2.256V    15.23mA    8.678mA    36.02mA
2.321V    12.9mA     8.429mA    21.49mA
2.647V    11.91mA    8.396mA    16.49mA
3.364V    25.81mA    18.46mA    33.62mA
3.6V      31.72mA    12.02mA    40.98mA
[Pullup]
| Voltage   I(typ)   I(min)   I(max)
-1.8V     9.384mA    2.259mA    15.14mA
-1.472V   6.576mA    3.709mA    9.1mA
-1.271V   5.876mA    4.35mA     8.163mA
-1.137V   6.285mA    4.187mA    12.09mA
-1.003V   12.74mA    4.763mA    23.05mA
-869.7mV  21.37mA    9.994mA    27.25mA
-735.9mV  23.06mA    16.5mA     27.73mA
-468.3mV  18.25mA    14.44mA    21.43mA
434.5mV   -15.16mA   -11.64mA   -18.27mA
993.1mV   -26.54mA   -19.81mA   -32.66mA
1.89V     -33.4mA    -23.98mA   -42.49mA
3.6V      -38.3mA    -27.14mA   -49.6mA
[Ramp]
dV/dt_r   0.655633/1.4778n  0.527661/2.34667n  0.747054/0.953727n
dV/dt_f   0.637742/1.38427n  0.463302/2.18126n  0.754102/0.851259n
R_load = 50
[Falling Waveform]
R_fixture = 50
V_fixture = 1.8
V_fixture_min = 1.66
V_fixture_max = 1.89
| Time   V(typ)   V(min)   V(max)
0s        1.8V       1.66V      1.89V
441.1ps   1.81V      1.666V     1.862V
648.5ps   1.75V      1.667V     1.616V
1.055ns   1.458V     1.583V     1.152V
1.372ns   1.261V     1.472V     936.5mV
1.752ns   1.092V     1.347V     795.1mV
3.109ns   832.6mV    1.08V      659.6mV
5.527ns   750.3mV    933.4mV    635.2mV
13.52ns   736.6mV    886.9mV    632.9mV
800ns     737.1mV    887.8mV    633.2mV
[Falling Waveform]
R_fixture = 50
V_fixture = 0
V_fixture_min = 0
V_fixture_max = 0
| Time   V(typ)   V(min)   V(max)
0s        1.093V     879.4mV    1.245V
263.6ps   1.093V     879.4mV    1.216V
349ps     1.04V      879.3mV    892.8mV
444.7ps   704.1mV    861.7mV    442.6mV
546ps     350mV      646.9mV    122.1mV
658.2ps   106.9mV    350.9mV    17.87mV
773.5ps   23.13mV    153mV      2.527mV
906.2ps   3.466mV    40.95mV    738.1uV
4.606ns   71.36uV    102.7uV    44.87uV
800ns     17.15nV    908.6nV    7.793nV
[Rising Waveform]
R_fixture = 50
V_fixture = 1.8
V_fixture_min = 1.66
V_fixture_max = 1.89
| Time   V(typ)   V(min)   V(max)
0s        737.1mV    887.8mV    633.2mV
336.2ps   735.6mV    888mV      695.3mV
389.6ps   761.4mV    888.1mV    837.6mV
459.4ps   878.5mV    886.1mV    1.147V
569ps     1.201V     957.1mV    1.63V
667.7ps   1.501V     1.105V     1.836V
790.3ps   1.72V      1.313V     1.882V
974.7ps   1.793V     1.543V     1.888V
1.352ns   1.799V     1.656V     1.889V
800ns     1.8V       1.66V      1.89V
[Rising Waveform]
R_fixture = 50
V_fixture = 0
V_fixture_min = 0
V_fixture_max = 0
| Time   V(typ)   V(min)   V(max)
0s        17.15nV    908.5nV    7.799nV
479.7ps   -967.6uV   -1.142mV   38.95mV
700ps     59.42mV    -715.9uV   293.7mV
1.163ns   375.1mV    95.51mV    760.3mV
1.475ns   557mV      204.2mV    940.6mV
1.93ns    750.4mV    349.4mV    1.08V
2.772ns   936mV      561.3mV    1.178V
3.848ns   1.025V     715.2mV    1.218V
7.223ns   1.084V     851.4mV    1.243V
800ns     1.093V     879.4mV    1.245V
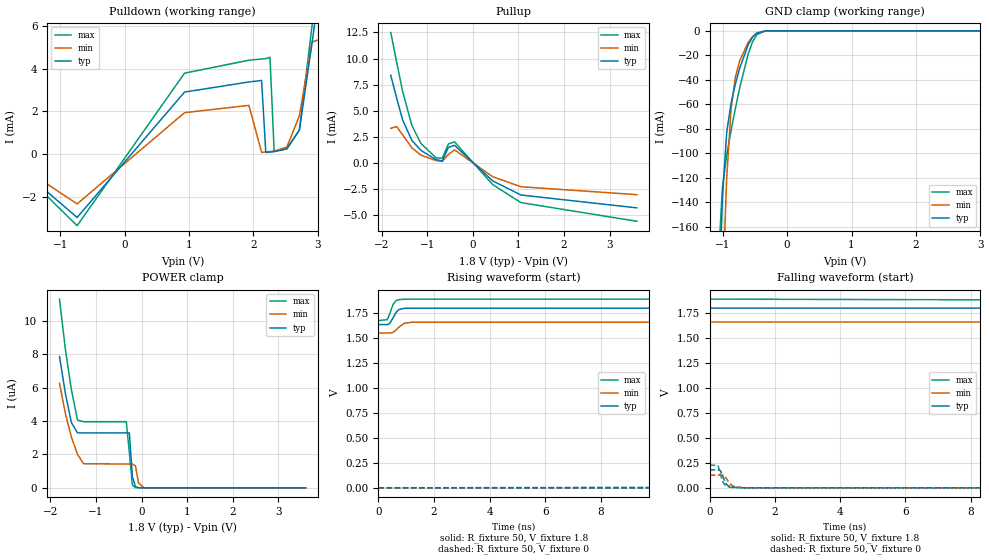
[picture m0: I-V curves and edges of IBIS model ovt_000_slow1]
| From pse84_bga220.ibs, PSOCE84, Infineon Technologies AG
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[Model] ovt_000_slow1
Model_type I/O
Enable   Active-High
Vinl  =  0.54
Vinh  =  1.26
Vmeas =  0.9
Cref  =  15e-12
| Capacitance   typ   min   max
C_comp   1.39974e-12   1.35992e-12   1.44753e-12
| Variables   typ   min   max
[GND Clamp Reference]   0   0   0
[POWER Clamp Reference]   1.8   1.66   1.89
[Pulldown Reference]   0   0   0
[Pullup Reference]   1.8   1.66   1.89
[Temperature Range]   25   125   -40
[Voltage Range]   1.8   1.66   1.89
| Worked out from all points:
|   slope of the pulldown table from 0 to 0.27 V, typ, clamps not added: 212 ohm
|   slope of the pullup table from 0 to 0.27 V, typ, clamps not added: 243 ohm
|   GND clamp passes 1 mA (typ) near -0.43 V on its own axis
|   falling waveform, R_fixture 50, V_fixture 1.8: 20-80 % time 56.7ns typ, 88.6ns min, 32.2ns max; typ from 1.8 V to 1.64 V
|   falling waveform, R_fixture 50, V_fixture 0: 20-80 % time 141ps typ, 161ps min, 130ps max; typ from 0.179 V to 0 V
|   rising waveform, R_fixture 50, V_fixture 1.8: 20-80 % time 203ps typ, 263ps min, 173ps max; typ from 1.64 V to 1.8 V
|   rising waveform, R_fixture 50, V_fixture 0: 20-80 % time 64.9ns typ, 97.9ns min, 39.7ns max; typ from 0 V to 0.179 V
[GND Clamp]
| Voltage   I(typ)   I(min)   I(max)
-1.271V   -717.5mA   -832.8mA   -643.6mA
-1.07V    -241.9mA   -348.3mA   -192.2mA
-1.003V   -137.2mA   -218.1mA   -128.1mA
-936.6mV  -83.06mA   -120.7mA   -101.3mA
-869.7mV  -59.26mA   -64.32mA   -81.77mA
-802.8mV  -43.7mA    -38.08mA   -63.69mA
-735.9mV  -30.76mA   -24.63mA   -46.83mA
-602.1mV  -11.27mA   -9.362mA   -18.72mA
-535.2mV  -5.241mA   -4.803mA   -9.042mA
-468.3mV  -1.746mA   -1.965mA   -3.086mA
-334.5mV  -35.9uA    -120.8uA   -33.39uA
3.6V      0A         0A         0A
[POWER Clamp]
| Voltage   I(typ)   I(min)   I(max)
-1.8V     7.872uA    6.273uA    11.31uA
-1.672V   5.671uA    4.461uA    8.32uA
-1.539V   3.91uA     3.037uA    5.87uA
-1.405V   3.295uA    2.008uA    4.063uA
-1.271V   3.295uA    1.447uA    3.964uA
-334.5mV  3.295uA    1.429uA    3.964uA
-267.6mV  3.295uA    1.429uA    2.099uA
-200.7mV  664.1nA    1.429uA    166.6nA
-133.8mV  69.92nA    1.319uA    14.86nA
-66.9mV   7.33nA     291.5nA    4.066nA
62.07mV   0A         0A         0A
3.6V      0A         0A         0A
[Pulldown]
| Voltage   I(typ)   I(min)   I(max)
-1.8V     -203.5uA   -191.2uA   -185.9uA
-735.9mV  -2.943mA   -2.311mA   -3.327mA
931mV     2.905mA    1.944mA    3.788mA
1.93V     3.376mA    2.283mA    4.39mA
2.126V    3.446mA    88.93uA    4.446mA
2.191V    90.57uA    112.8uA    4.464mA
2.256V    101.9uA    128.5uA    4.526mA
2.321V    128uA      152.6uA    138.5uA
2.517V    252.8uA    336.1uA    269.2uA
2.712V    1.127mA    1.8mA      1.136mA
2.908V    5.179mA    5.244mA    5.975mA
3.6V      20.36mA    5.874mA    22.86mA
[Pullup]
| Voltage   I(typ)   I(min)   I(max)
-1.8V     8.404mA    3.324mA    12.49mA
-1.672V   6.239mA    3.504mA    9.679mA
-1.539V   4.131mA    2.695mA    6.856mA
-1.338V   2.178mA    1.469mA    3.616mA
-1.137V   1.215mA    760.1uA    1.868mA
-802.8mV  323.2uA    235.3uA    495.4uA
-669mV    221.7uA    159.3uA    484.6uA
-535.2mV  1.506mA    831uA      1.83mA
-401.4mV  1.704mA    1.269mA    2.035mA
434.5mV   -1.694mA   -1.295mA   -2.048mA
1.055V    -3.05mA    -2.259mA   -3.777mA
3.6V      -4.282mA   -3.018mA   -5.567mA
[Ramp]
dV/dt_r   0.107422/64.9434n  76.3723m/97.9045n  0.137217/39.6765n
dV/dt_f   98.8488m/56.7039n  65.3301m/88.6372n  0.129087/32.2317n
R_load = 50
[Falling Waveform]
R_fixture = 50
V_fixture = 1.8
V_fixture_min = 1.66
V_fixture_max = 1.89
| Time   V(typ)   V(min)   V(max)
0s        1.8V       1.66V      1.89V
8.523ns   1.8V       1.66V      1.883V
17.04ns   1.792V     1.66V      1.83V
25.1ns    1.772V     1.656V     1.785V
43.69ns   1.725V     1.639V     1.723V
63.47ns   1.69V      1.618V     1.696V
88.54ns   1.664V     1.596V     1.682V
144.2ns   1.643V     1.569V     1.676V
236.1ns   1.636V     1.555V     1.675V
800ns     1.635V     1.551V     1.675V
[Falling Waveform]
R_fixture = 50
V_fixture = 0
V_fixture_min = 0
V_fixture_max = 0
| Time   V(typ)   V(min)   V(max)
0s        179mV      127.3mV    228.7mV
248.1ps   178.9mV    127.3mV    223.1mV
283.8ps   179mV      127.3mV    195.4mV
339.1ps   167.1mV    127.2mV    123mV
404.6ps   113.3mV    127.1mV    57.22mV
483.3ps   49.75mV    109.4mV    23.69mV
555.3ps   22.98mV    70.5mV     10.91mV
690.2ps   6.17mV     18.83mV    2.282mV
1.038ns   -4.309uV   722.8uV    -428.9uV
800ns     40.92nV    1.881uV    20.55nV
[Rising Waveform]
R_fixture = 50
V_fixture = 1.8
V_fixture_min = 1.66
V_fixture_max = 1.89
| Time   V(typ)   V(min)   V(max)
0s        1.635V     1.551V     1.675V
305.1ps   1.635V     1.551V     1.684V
359.3ps   1.637V     1.551V     1.71V
423.4ps   1.654V     1.551V     1.757V
530.4ps   1.705V     1.558V     1.839V
632.8ps   1.756V     1.581V     1.875V
736.3ps   1.786V     1.61V      1.885V
931.1ps   1.798V     1.648V     1.889V
1.217ns   1.799V     1.659V     1.89V
800ns     1.8V       1.66V      1.89V
[Rising Waveform]
R_fixture = 50
V_fixture = 0
V_fixture_min = 0
V_fixture_max = 0
| Time   V(typ)   V(min)   V(max)
0s        40.92nV    1.88uV     20.55nV
9.747ns   -253.1uV   -263uV     4.732mV
19.86ns   10.23mV    1.184mV    56.27mV
32.04ns   40.18mV    9.434mV    114.8mV
48.88ns   79.81mV    28.15mV    166.5mV
70.12ns   116.5mV    52mV       199.6mV
103.6ns   149.2mV    80.62mV    219.8mV
170.4ns   172.1mV    110mV      227.8mV
262.4ns   178.1mV    122.9mV    228.7mV
800ns     179mV      127.3mV    228.7mV
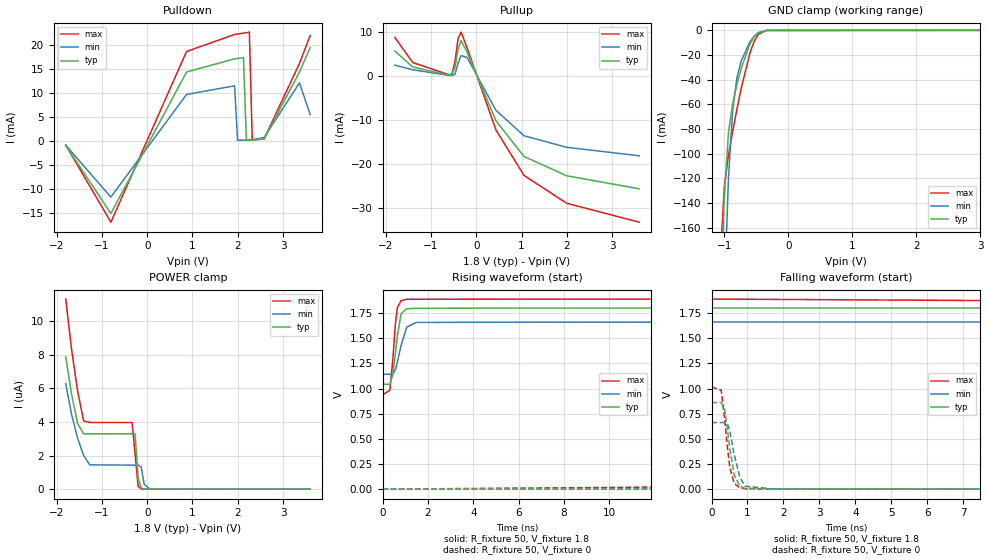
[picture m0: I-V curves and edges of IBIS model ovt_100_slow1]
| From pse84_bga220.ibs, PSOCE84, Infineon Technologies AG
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[Model] ovt_100_slow1
Model_type I/O
Enable   Active-High
Vinl  =  0.54
Vinh  =  1.26
Vmeas =  0.9
Cref  =  15e-12
| Capacitance   typ   min   max
C_comp   1.39974e-12   1.35992e-12   1.44753e-12
| Variables   typ   min   max
[GND Clamp Reference]   0   0   0
[POWER Clamp Reference]   1.8   1.66   1.89
[Pulldown Reference]   0   0   0
[Pullup Reference]   1.8   1.66   1.89
[Temperature Range]   25   125   -40
[Voltage Range]   1.8   1.66   1.89
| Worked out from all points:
|   slope of the pulldown table from 0 to 0.27 V, typ, clamps not added: 42.4 ohm
|   slope of the pullup table from 0 to 0.27 V, typ, clamps not added: 40.6 ohm
|   GND clamp passes 1 mA (typ) near -0.43 V on its own axis
|   falling waveform, R_fixture 50, V_fixture 1.8: 20-80 % time 85ns typ, 129ns min, 48.5ns max; typ from 1.8 V to 1.04 V
|   falling waveform, R_fixture 50, V_fixture 0: 20-80 % time 202ps typ, 240ps min, 181ps max; typ from 0.861 V to 0 V
|   rising waveform, R_fixture 50, V_fixture 1.8: 20-80 % time 241ps typ, 335ps min, 194ps max; typ from 1.04 V to 1.8 V
|   rising waveform, R_fixture 50, V_fixture 0: 20-80 % time 101ns typ, 155ns min, 60.4ns max; typ from 0 V to 0.861 V
[GND Clamp]
| Voltage   I(typ)   I(min)   I(max)
-1.271V   -717.5mA   -832.8mA   -643.6mA
-1.07V    -241.9mA   -348.3mA   -192.2mA
-1.003V   -137.2mA   -218.1mA   -128.1mA
-936.6mV  -83.06mA   -120.7mA   -101.3mA
-869.7mV  -59.26mA   -64.32mA   -81.77mA
-802.8mV  -43.7mA    -38.08mA   -63.69mA
-735.9mV  -30.76mA   -24.63mA   -46.83mA
-602.1mV  -11.27mA   -9.362mA   -18.72mA
-535.2mV  -5.241mA   -4.803mA   -9.042mA
-468.3mV  -1.746mA   -1.965mA   -3.086mA
-334.5mV  -35.9uA    -120.8uA   -33.39uA
3.6V      0A         0A         0A
[POWER Clamp]
| Voltage   I(typ)   I(min)   I(max)
-1.8V     7.872uA    6.273uA    11.31uA
-1.672V   5.671uA    4.461uA    8.32uA
-1.539V   3.91uA     3.037uA    5.87uA
-1.405V   3.295uA    2.008uA    4.063uA
-1.271V   3.295uA    1.447uA    3.964uA
-334.5mV  3.295uA    1.429uA    3.964uA
-267.6mV  3.295uA    1.429uA    2.099uA
-200.7mV  664.1nA    1.429uA    166.6nA
-133.8mV  69.92nA    1.319uA    14.86nA
-66.9mV   7.33nA     291.5nA    4.066nA
62.07mV   0A         0A         0A
3.6V      0A         0A         0A
[Pulldown]
| Voltage   I(typ)   I(min)   I(max)
-1.8V     -1.027mA   -964.1uA   -940.8uA
-802.8mV  -15.19mA   -11.77mA   -17mA
869mV     14.28mA    9.602mA    18.55mA
1.93V     17.02mA    11.4mA     22.09mA
1.996V    17.09mA    61.08uA    22.19mA
2.126V    17.26mA    87.92uA    22.37mA
2.191V    90.19uA    111.9uA    22.46mA
2.256V    101.7uA    127.8uA    22.59mA
2.321V    127.9uA    151.8uA    138.4uA
2.582V    324.9uA    635.6uA    346.1uA
3.364V    14.27mA    12.01mA    16.07mA
3.6V      19.34mA    5.4mA      21.87mA
[Pullup]
| Voltage   I(typ)   I(min)   I(max)
-1.8V     5.678mA    2.468mA    8.773mA
-1.405V   2.056mA    1.423mA    3.08mA
-602.1mV  182.3uA    135.1uA    274.8uA
-535.2mV  332.7uA    124.2uA    479.8uA
-468.3mV  2.029mA    395.7uA    3.361mA
-401.4mV  6.147mA    2.916mA    8.464mA
-334.5mV  8.037mA    4.633mA    9.959mA
-200.7mV  5.35mA     4.19mA     6.338mA
434.5mV   -10.13mA   -7.765mA   -12.21mA
1.055V    -18.24mA   -13.54mA   -22.53mA
1.996V    -22.61mA   -16.16mA   -28.84mA
3.6V      -25.57mA   -18.08mA   -33.14mA
[Ramp]
dV/dt_r   0.516739/0.101413u  0.396612/0.154745u  0.60937/60.3996n
dV/dt_f   0.45412/85.0176n  0.310872/0.129407u  0.572096/48.5374n
R_load = 50
[Falling Waveform]
R_fixture = 50
V_fixture = 1.8
V_fixture_min = 1.66
V_fixture_max = 1.89
| Time   V(typ)   V(min)   V(max)
0s        1.8V       1.66V      1.89V
9.752ns   1.8V       1.66V      1.871V
18.69ns   1.778V     1.659V     1.716V
38.09ns   1.622V     1.62V      1.399V
60.91ns   1.451V     1.538V     1.173V
85.99ns   1.312V     1.45V      1.047V
119.4ns   1.196V     1.356V     977.7mV
191.3ns   1.089V     1.239V     942.1mV
300.2ns   1.051V     1.171V     936.8mV
800ns     1.043V     1.142V     936.5mV
[Falling Waveform]
R_fixture = 50
V_fixture = 0
V_fixture_min = 0
V_fixture_max = 0
| Time   V(typ)   V(min)   V(max)
0s        861.3mV    661.8mV    1.016V
268.4ps   861.3mV    661.8mV    983.2mV
365.8ps   792mV      661.8mV    692.1mV
444.3ps   586.1mV    649.1mV    403mV
509.2ps   398.9mV    572.5mV    214.6mV
631ps     141.4mV    342.2mV    57.1mV
787.5ps   29.22mV    117.4mV    13.11mV
935.5ps   7.916mV    29.72mV    5.429mV
1.749ns   1.604mV    1.148mV    1.624mV
800ns     22.74nV    1.159uV    10.64nV
[Rising Waveform]
R_fixture = 50
V_fixture = 1.8
V_fixture_min = 1.66
V_fixture_max = 1.89
| Time   V(typ)   V(min)   V(max)
0s        1.043V     1.142V     936.5mV
322.5ps   1.043V     1.142V     983.3mV
447.7ps   1.134V     1.142V     1.271V
569.2ps   1.354V     1.189V     1.648V
653ps     1.522V     1.263V     1.804V
817.1ps   1.745V     1.429V     1.875V
1.068ns   1.794V     1.611V     1.888V
1.482ns   1.798V     1.658V     1.888V
6.149ns   1.8V       1.66V      1.889V
800ns     1.8V       1.66V      1.89V
[Rising Waveform]
R_fixture = 50
V_fixture = 0
V_fixture_min = 0
V_fixture_max = 0
| Time   V(typ)   V(min)   V(max)
0s        22.7nV     1.157uV    10.63nV
14.41ns   241.1uV    -84.26uV   24.6mV
24.32ns   28.14mV    3.147mV    164.5mV
45.18ns   181.5mV    51.77mV    464.5mV
72.31ns   378.3mV    156.6mV    725.4mV
97.38ns   519.5mV    250.5mV    856.8mV
139.2ns   673.2mV    378mV      953.4mV
214.5ns   795.3mV    520.7mV    1.002V
333.6ns   847.2mV    614.5mV    1.014V
800ns     861.2mV    661mV      1.016V
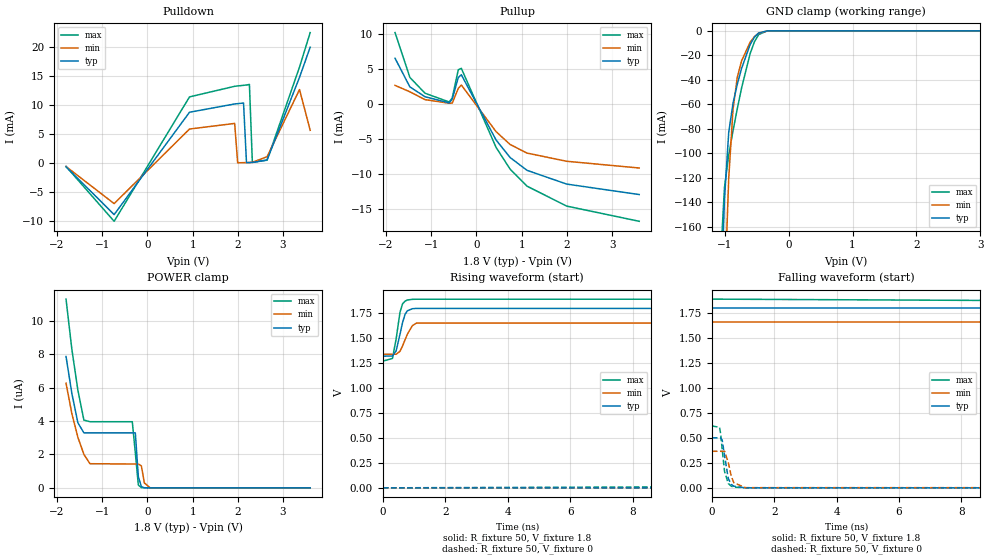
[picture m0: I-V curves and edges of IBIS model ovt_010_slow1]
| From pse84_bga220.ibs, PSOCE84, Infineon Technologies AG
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[Model] ovt_010_slow1
Model_type I/O
Enable   Active-High
Vinl  =  0.54
Vinh  =  1.26
Vmeas =  0.9
Cref  =  15e-12
| Capacitance   typ   min   max
C_comp   1.39974e-12   1.35992e-12   1.44753e-12
| Variables   typ   min   max
[GND Clamp Reference]   0   0   0
[POWER Clamp Reference]   1.8   1.66   1.89
[Pulldown Reference]   0   0   0
[Pullup Reference]   1.8   1.66   1.89
[Temperature Range]   25   125   -40
[Voltage Range]   1.8   1.66   1.89
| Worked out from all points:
|   slope of the pulldown table from 0 to 0.27 V, typ, clamps not added: 70.3 ohm
|   slope of the pullup table from 0 to 0.27 V, typ, clamps not added: 80.5 ohm
|   GND clamp passes 1 mA (typ) near -0.43 V on its own axis
|   falling waveform, R_fixture 50, V_fixture 1.8: 20-80 % time 74.8ns typ, 113ns min, 43.8ns max; typ from 1.8 V to 1.32 V
|   falling waveform, R_fixture 50, V_fixture 0: 20-80 % time 146ps typ, 168ps min, 134ps max; typ from 0.501 V to 0 V
|   rising waveform, R_fixture 50, V_fixture 1.8: 20-80 % time 209ps typ, 273ps min, 177ps max; typ from 1.32 V to 1.8 V
|   rising waveform, R_fixture 50, V_fixture 0: 20-80 % time 87.4ns typ, 129ns min, 53.8ns max; typ from 0 V to 0.501 V
[GND Clamp]
| Voltage   I(typ)   I(min)   I(max)
-1.271V   -717.5mA   -832.8mA   -643.6mA
-1.07V    -241.9mA   -348.3mA   -192.2mA
-1.003V   -137.2mA   -218.1mA   -128.1mA
-936.6mV  -83.06mA   -120.7mA   -101.3mA
-869.7mV  -59.26mA   -64.32mA   -81.77mA
-802.8mV  -43.7mA    -38.08mA   -63.69mA
-735.9mV  -30.76mA   -24.63mA   -46.83mA
-602.1mV  -11.27mA   -9.362mA   -18.72mA
-535.2mV  -5.241mA   -4.803mA   -9.042mA
-468.3mV  -1.746mA   -1.965mA   -3.086mA
-334.5mV  -35.9uA    -120.8uA   -33.39uA
3.6V      0A         0A         0A
[POWER Clamp]
| Voltage   I(typ)   I(min)   I(max)
-1.8V     7.872uA    6.273uA    11.31uA
-1.672V   5.671uA    4.461uA    8.32uA
-1.539V   3.91uA     3.037uA    5.87uA
-1.405V   3.295uA    2.008uA    4.063uA
-1.271V   3.295uA    1.447uA    3.964uA
-334.5mV  3.295uA    1.429uA    3.964uA
-267.6mV  3.295uA    1.429uA    2.099uA
-200.7mV  664.1nA    1.429uA    166.6nA
-133.8mV  69.92nA    1.319uA    14.86nA
-66.9mV   7.33nA     291.5nA    4.066nA
62.07mV   0A         0A         0A
3.6V      0A         0A         0A
[Pulldown]
| Voltage   I(typ)   I(min)   I(max)
-1.8V     -616.1uA   -578.6uA   -563.4uA
-735.9mV  -8.883mA   -6.987mA   -10.04mA
931mV     8.796mA    5.899mA    11.45mA
1.93V     10.23mA    6.864mA    13.28mA
1.996V    10.28mA    60.9uA     13.34mA
2.126V    10.39mA    87.84uA    13.45mA
2.191V    90.19uA    111.9uA    13.5mA
2.256V    101.7uA    127.7uA    13.6mA
2.321V    127.9uA    151.8uA    138.4uA
2.647V    561.6uA    1.118mA    513.4uA
3.364V    14.83mA    12.72mA    16.6mA
3.6V      20.04mA    5.681mA    22.56mA
[Pullup]
| Voltage   I(typ)   I(min)   I(max)
-1.8V     6.555mA    2.685mA    10.22mA
-1.472V   2.463mA    1.769mA    3.817mA
-1.137V   1.064mA    650.1uA    1.563mA
-602.1mV  183.6uA    135.5uA    311.9uA
-535.2mV  735.6uA    155.5uA    907.2uA
-401.4mV  3.808mA    2.255mA    4.91mA
-334.5mV  4.204mA    2.736mA    5.118mA
434.5mV   -5.11mA    -3.915mA   -6.166mA
744.8mV   -7.607mA   -5.75mA    -9.264mA
1.117V    -9.434mA   -6.974mA   -11.69mA
1.996V    -11.4mA    -8.145mA   -14.54mA
3.6V      -12.89mA   -9.106mA   -16.71mA
[Ramp]
dV/dt_r   0.300715/87.3582n  0.219826/0.129413u  0.372037/53.7769n
dV/dt_f   0.288394/74.8148n  0.193154/0.113044u  0.372437/43.815n
R_load = 50
[Falling Waveform]
R_fixture = 50
V_fixture = 1.8
V_fixture_min = 1.66
V_fixture_max = 1.89
| Time   V(typ)   V(min)   V(max)
0s        1.8V       1.66V      1.89V
9.302ns   1.8V       1.66V      1.876V
19.32ns   1.779V     1.659V     1.745V
33.46ns   1.696V     1.64V      1.577V
55.97ns   1.573V     1.585V     1.417V
81.05ns   1.477V     1.523V     1.335V
114.5ns   1.403V     1.46V      1.292V
178.9ns   1.344V     1.392V     1.273V
284ns     1.323V     1.352V     1.269V
800ns     1.319V     1.338V     1.269V
[Falling Waveform]
R_fixture = 50
V_fixture = 0
V_fixture_min = 0
V_fixture_max = 0
| Time   V(typ)   V(min)   V(max)
0s        501.2mV    366.5mV    620.1mV
248ps     501mV      366.5mV    605.8mV
283.6ps   501.4mV    366.5mV    538.5mV
330.9ps   479.3mV    366.4mV    384.8mV
408.5ps   319mV      365.7mV    162.7mV
526.6ps   94.18mV    254.4mV    43.96mV
619.4ps   36.12mV    120.5mV    16.82mV
703.1ps   16.24mV    51.49mV    7.427mV
1.077ns   213.3uV    1.927mV    466.9uV
800ns     29.18nV    1.432uV    13.99nV
[Rising Waveform]
R_fixture = 50
V_fixture = 1.8
V_fixture_min = 1.66
V_fixture_max = 1.89
| Time   V(typ)   V(min)   V(max)
0s        1.319V     1.338V     1.269V
307.6ps   1.32V      1.338V     1.296V
425.8ps   1.372V     1.338V     1.492V
549.5ps   1.539V     1.367V     1.759V
630.4ps   1.654V     1.421V     1.842V
710.3ps   1.738V     1.483V     1.87V
785.9ps   1.773V     1.539V     1.881V
944.4ps   1.794V     1.624V     1.888V
1.075ns   1.797V     1.65V      1.889V
800ns     1.8V       1.66V      1.89V
[Rising Waveform]
R_fixture = 50
V_fixture = 0
V_fixture_min = 0
V_fixture_max = 0
| Time   V(typ)   V(min)   V(max)
0s        29.16nV    1.431uV    13.99nV
12.23ns   -6.629uV   -171.8uV   12.76mV
21.96ns   18.31mV    1.833mV    110.3mV
43.28ns   127.7mV    36.98mV    318.2mV
66.63ns   239.1mV    97.48mV    457.7mV
91.7ns    326.7mV    157.7mV    536mV
133.5ns   413.1mV    233.9mV    590.7mV
207.6ns   474.3mV    308.4mV    615.2mV
316.3ns   496.2mV    349mV      619.7mV
800ns     501.2mV    366.4mV    620.1mV
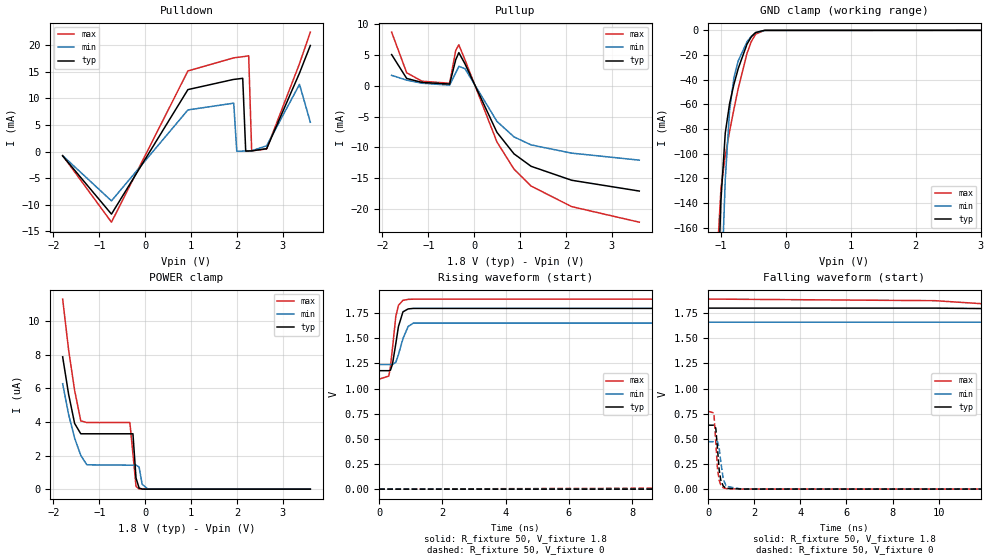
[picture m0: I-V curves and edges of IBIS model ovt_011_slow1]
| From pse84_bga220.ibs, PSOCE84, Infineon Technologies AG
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[Model] ovt_011_slow1
Model_type I/O
Enable   Active-High
Vinl  =  0.54
Vinh  =  1.26
Vmeas =  0.9
Cref  =  15e-12
| Capacitance   typ   min   max
C_comp   1.39974e-12   1.35992e-12   1.44753e-12
| Variables   typ   min   max
[GND Clamp Reference]   0   0   0
[POWER Clamp Reference]   1.8   1.66   1.89
[Pulldown Reference]   0   0   0
[Pullup Reference]   1.8   1.66   1.89
[Temperature Range]   25   125   -40
[Voltage Range]   1.8   1.66   1.89
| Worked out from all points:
|   slope of the pulldown table from 0 to 0.27 V, typ, clamps not added: 53.3 ohm
|   slope of the pullup table from 0 to 0.27 V, typ, clamps not added: 60.8 ohm
|   GND clamp passes 1 mA (typ) near -0.43 V on its own axis
|   falling waveform, R_fixture 50, V_fixture 1.8: 20-80 % time 82.7ns typ, 125ns min, 48.4ns max; typ from 1.8 V to 1.18 V
|   falling waveform, R_fixture 50, V_fixture 0: 20-80 % time 143ps typ, 164ps min, 132ps max; typ from 0.636 V to 0 V
|   rising waveform, R_fixture 50, V_fixture 1.8: 20-80 % time 190ps typ, 247ps min, 162ps max; typ from 1.18 V to 1.8 V
|   rising waveform, R_fixture 50, V_fixture 0: 20-80 % time 98.5ns typ, 146ns min, 60.4ns max; typ from 0 V to 0.636 V
[GND Clamp]
| Voltage   I(typ)   I(min)   I(max)
-1.271V   -717.5mA   -832.8mA   -643.6mA
-1.07V    -241.9mA   -348.3mA   -192.2mA
-1.003V   -137.2mA   -218.1mA   -128.1mA
-936.6mV  -83.06mA   -120.7mA   -101.3mA
-869.7mV  -59.26mA   -64.32mA   -81.77mA
-802.8mV  -43.7mA    -38.08mA   -63.69mA
-735.9mV  -30.76mA   -24.63mA   -46.83mA
-602.1mV  -11.27mA   -9.362mA   -18.72mA
-535.2mV  -5.241mA   -4.803mA   -9.042mA
-468.3mV  -1.746mA   -1.965mA   -3.086mA
-334.5mV  -35.9uA    -120.8uA   -33.39uA
3.6V      0A         0A         0A
[POWER Clamp]
| Voltage   I(typ)   I(min)   I(max)
-1.8V     7.872uA    6.273uA    11.31uA
-1.672V   5.671uA    4.461uA    8.32uA
-1.539V   3.91uA     3.037uA    5.87uA
-1.405V   3.295uA    2.008uA    4.063uA
-1.271V   3.295uA    1.447uA    3.964uA
-334.5mV  3.295uA    1.429uA    3.964uA
-267.6mV  3.295uA    1.429uA    2.099uA
-200.7mV  664.1nA    1.429uA    166.6nA
-133.8mV  69.92nA    1.319uA    14.86nA
-66.9mV   7.33nA     291.5nA    4.066nA
62.07mV   0A         0A         0A
3.6V      0A         0A         0A
[Pulldown]
| Voltage   I(typ)   I(min)   I(max)
-1.8V     -820.6uA   -770.3uA   -751.5uA
-735.9mV  -11.77mA   -9.278mA   -13.29mA
931mV     11.66mA    7.833mA    15.17mA
1.93V     13.58mA    9.106mA    17.63mA
1.996V    13.64mA    60.7uA     17.71mA
2.126V    13.78mA    87.77uA    17.85mA
2.191V    90.18uA    111.8uA    17.92mA
2.256V    101.7uA    127.6uA    18.03mA
2.321V    127.9uA    151.7uA    138.4uA
2.647V    537.3uA    1.083mA    499.9uA
3.364V    14.77mA    12.64mA    16.54mA
3.6V      19.96mA    5.522mA    22.48mA
[Pullup]
| Voltage   I(typ)   I(min)   I(max)
-1.8V     5.087mA    1.714mA    8.742mA
-1.472V   1.216mA    935.8uA    2.136mA
-1.137V   565.2uA    434.1uA    759.5uA
-535.2mV  298.5uA    119.9uA    431.7uA
-401.4mV  4.259mA    2.128mA    5.781mA
-334.5mV  5.403mA    3.177mA    6.682mA
-200.7mV  3.58mA     2.804mA    4.244mA
496.6mV   -7.546mA   -5.77mA    -9.114mA
869mV     -11.04mA   -8.285mA   -13.53mA
1.241V    -13.06mA   -9.584mA   -16.27mA
2.126V    -15.33mA   -10.92mA   -19.61mA
3.6V      -17.08mA   -12.06mA   -22.14mA
[Ramp]
dV/dt_r   0.381692/98.5312n  0.283153/0.146088u  0.464617/60.3869n
dV/dt_f   0.373481/82.6812n  0.252601/0.124589u  0.477707/48.3936n
R_load = 50
[Falling Waveform]
R_fixture = 50
V_fixture = 1.8
V_fixture_min = 1.66
V_fixture_max = 1.89
| Time   V(typ)   V(min)   V(max)
0s        1.8V       1.66V      1.89V
9.832ns   1.8V       1.66V      1.874V
19.1ns    1.78V      1.659V     1.737V
35.19ns   1.672V     1.635V     1.509V
57.45ns   1.525V     1.569V     1.31V
82.52ns   1.405V     1.494V     1.197V
116ns     1.305V     1.415V     1.133V
182.6ns   1.218V     1.321V     1.1V
294.1ns   1.184V     1.262V     1.094V
800ns     1.178V     1.239V     1.094V
[Falling Waveform]
R_fixture = 50
V_fixture = 0
V_fixture_min = 0
V_fixture_max = 0
| Time   V(typ)   V(min)   V(max)
0s        636.2mV    472.3mV    774.4mV
246.6ps   636mV      472.3mV    757.7mV
330ps     607.3mV    472.2mV    466mV
403.6ps   404mV      471.8mV    202.8mV
475.1ps   196.1mV    413.5mV    90.57mV
543.6ps   92.33mV    278.2mV    43.47mV
652.9ps   31.09mV    100.5mV    13.98mV
780.7ps   7.776mV    28.28mV    5.274mV
1.478ns   1.108mV    238.6uV    1.269mV
800ns     25.7nV     1.285uV    12.17nV
[Rising Waveform]
R_fixture = 50
V_fixture = 1.8
V_fixture_min = 1.66
V_fixture_max = 1.89
| Time   V(typ)   V(min)   V(max)
0s        1.178V     1.239V     1.094V
303.1ps   1.178V     1.239V     1.125V
355.1ps   1.183V     1.239V     1.22V
418ps     1.242V     1.239V     1.398V
524.1ps   1.446V     1.262V     1.717V
607.7ps   1.617V     1.338V     1.828V
750.1ps   1.763V     1.497V     1.877V
913.7ps   1.792V     1.617V     1.887V
1.077ns   1.797V     1.651V     1.889V
800ns     1.8V       1.66V      1.89V
[Rising Waveform]
R_fixture = 50
V_fixture = 0
V_fixture_min = 0
V_fixture_max = 0
| Time   V(typ)   V(min)   V(max)
0s        25.64nV    1.283uV    12.15nV
13.87ns   405.5uV    -137.3uV   15.48mV
25.05ns   24.95mV    2.875mV    137.4mV
51.67ns   178.5mV    57.59mV    417.9mV
76.75ns   310.2mV    131.7mV    578.2mV
101.8ns   409.1mV    200.1mV    665.4mV
143.6ns   512.7mV    289.8mV    731.5mV
219.2ns   594mV      385.6mV    765.7mV
329.4ns   626.8mV    442.7mV    773.5mV
800ns     636.2mV    471.9mV    774.4mV
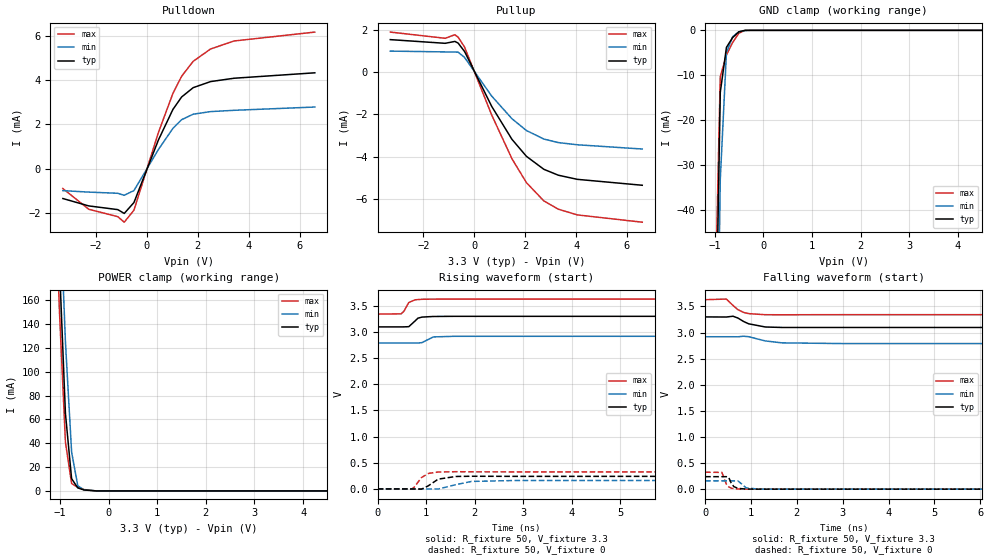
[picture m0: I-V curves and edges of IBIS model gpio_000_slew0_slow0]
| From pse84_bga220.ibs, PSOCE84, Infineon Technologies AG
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[Model] gpio_000_slew0_slow0
Model_type I/O
Enable   Active-High
Vinl  =  0.99
Vinh  =  2.31
Vmeas =  1.65
Cref  =  15e-12
| Capacitance   typ   min   max
C_comp   1.09946e-12   1.086232e-12   1.114407e-12
| Variables   typ   min   max
[GND Clamp Reference]   0   0   0
[POWER Clamp Reference]   3.3   2.92   3.63
[Pulldown Reference]   0   0   0
[Pullup Reference]   3.3   2.92   3.63
[Temperature Range]   25   125   -40
[Voltage Range]   3.3   2.92   3.63
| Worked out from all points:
|   slope of the pulldown table from 0 to 0.495 V, typ, clamps not added: 352 ohm
|   slope of the pullup table from 0 to 0.495 V, typ, clamps not added: 415 ohm
|   GND clamp passes 1 mA (typ) near -0.57 V on its own axis
|   POWER clamp passes 1 mA (typ) near -0.52 V on its own axis
|   falling waveform, R_fixture 50, V_fixture 3.3: 20-80 % time 317ps typ, 426ps min, 249ps max; typ from 3.3 V to 3.1 V
|   falling waveform, R_fixture 50, V_fixture 0: 20-80 % time 92.7ps typ, 99.3ps min, 88.8ps max; typ from 0.239 V to 0 V
|   rising waveform, R_fixture 50, V_fixture 3.3: 20-80 % time 118ps typ, 140ps min, 108ps max; typ from 3.1 V to 3.3 V
|   rising waveform, R_fixture 50, V_fixture 0: 20-80 % time 235ps typ, 345ps min, 183ps max; typ from 0 V to 0.239 V
[GND Clamp]
| Voltage   I(typ)   I(min)   I(max)
-1.65V    -892.5mA   -911.9mA   -883.9mA
-1.015V   -92.32mA   -129.7mA   -71.28mA
-888.3mV  -13.83mA   -33.21mA   -10.31mA
-761.4mV  -3.792mA   -4.944mA   -5.509mA
-634.5mV  -1.622mA   -1.436mA   -2.707mA
-507.6mV  -326.2uA   -352.3uA   -651.6uA
-380.7mV  -13.48uA   -32.14uA   -19.55uA
-253.8mV  -189.4nA   -1.276uA   -466.7nA
6.6V      0A         0A         0A
[POWER Clamp]
| Voltage   I(typ)   I(min)   I(max)
-1.523V   838.1mA    872.9mA    823.9mA
-1.142V   346.5mA    405.1mA    310.5mA
-1.015V   193mA      257.4mA    153.9mA
-888.3mV  64.97mA    124.9mA    40.96mA
-761.4mV  10.28mA    32.7mA     6.184mA
-634.5mV  2.553mA    4.346mA    3.067mA
-507.6mV  805.9uA    960.7uA    1.159mA
-253.8mV  1.454uA    10.02uA    1.678uA
6.6V      0A         0A         0A
[Pulldown]
| Voltage   I(typ)   I(min)   I(max)
-3.3V     -1.344mA   -988.2uA   -894.2uA
-2.284V   -1.677mA   -1.054mA   -1.827mA
-1.142V   -1.844mA   -1.108mA   -2.163mA
-888.3mV  -2.016mA   -1.199mA   -2.411mA
-507.6mV  -1.525mA   -984.7uA   -1.869mA
455.2mV   1.299mA    868.4uA    1.635mA
1.024V    2.673mA    1.819mA    3.396mA
1.366V    3.234mA    2.212mA    4.169mA
1.821V    3.655mA    2.458mA    4.843mA
2.503V    3.928mA    2.575mA    5.397mA
3.425V    4.079mA    2.633mA    5.759mA
6.6V      4.324mA    2.781mA    6.16mA
[Pullup]
| Voltage   I(typ)   I(min)   I(max)
-3.3V     1.542mA    997.6uA    1.899mA
-1.142V   1.367mA    959.3uA    1.605mA
-761.4mV  1.457mA    951.8uA    1.773mA
-634.5mV  1.377mA    947.3uA    1.655mA
-380.7mV  976.2uA    696.2uA    1.185mA
682.8mV   -1.619mA   -1.133mA   -2.028mA
1.479V    -3.183mA   -2.206mA   -4.102mA
2.048V    -3.99mA    -2.766mA   -5.236mA
2.731V    -4.604mA   -3.17mA    -6.102mA
3.3V      -4.885mA   -3.339mA   -6.496mA
4.051V    -5.082mA   -3.443mA   -6.768mA
6.6V      -5.362mA   -3.644mA   -7.113mA
[Ramp]
dV/dt_r   0.143584/0.23544n  95.4609m/0.345313n  0.194972/0.182713n
dV/dt_f   0.121179/0.316634n  77.961m/0.426293n  0.172121/0.248788n
R_load = 50
[Falling Waveform]
R_fixture = 50
V_fixture = 3.3
V_fixture_min = 2.92
V_fixture_max = 3.63
| Time   V(typ)   V(min)   V(max)
0s        3.3V       2.92V      3.63V
463.7ps   3.298V     2.92V      3.642V
608.5ps   3.313V     2.92V      3.519V
711.2ps   3.28V      2.919V     3.441V
839.7ps   3.212V     2.93V      3.386V
949.4ps   3.168V     2.921V     3.363V
1.313ns   3.107V     2.84V      3.342V
1.674ns   3.098V     2.803V     3.341V
3.022ns   3.098V     2.789V     3.343V
800ns     3.098V     2.79V      3.343V
[Falling Waveform]
R_fixture = 50
V_fixture = 0
V_fixture_min = 0
V_fixture_max = 0
| Time   V(typ)   V(min)   V(max)
0s        239.3mV    159.1mV    325mV
366.5ps   239.2mV    159mV      321.2mV
463.8ps   239.1mV    159mV      94.3mV
515ps     224.2mV    159.1mV    43.46mV
569.8ps   115.8mV    159.1mV    19.49mV
625.3ps   49.58mV    159.2mV    9.452mV
715.1ps   15.05mV    159.1mV    3.169mV
891.9ps   2.165mV    26.75mV    602.9uV
1.143ns   395uV      1.758mV    270.1uV
800ns     26.22nV    728.5nV    16.41nV
[Rising Waveform]
R_fixture = 50
V_fixture = 3.3
V_fixture_min = 2.92
V_fixture_max = 3.63
| Time   V(typ)   V(min)   V(max)
0s        3.098V     2.79V      3.343V
482.8ps   3.098V     2.79V      3.347V
540.1ps   3.098V     2.79V      3.396V
641.7ps   3.102V     2.79V      3.564V
765ps     3.206V     2.79V      3.614V
831.5ps   3.265V     2.789V     3.621V
913.2ps   3.285V     2.797V     3.626V
1.146ns   3.297V     2.906V     3.629V
1.578ns   3.3V       2.918V     3.63V
800ns     3.3V       2.92V      3.63V
[Rising Waveform]
R_fixture = 50
V_fixture = 0
V_fixture_min = 0
V_fixture_max = 0
| Time   V(typ)   V(min)   V(max)
0s        26.29nV    727.8nV    16.58nV
698ps     -1.265mV   18.64uV    -5.26mV
745.8ps   -1.8mV     89.36uV    24.62mV
905ps     -4.898mV   -257uV     218.5mV
1.046ns   59.84mV    -1.19mV    295.8mV
1.248ns   186.3mV    -2.779mV   323mV
1.613ns   237.7mV    81.02mV    328.5mV
1.937ns   241.8mV    143mV      326.5mV
2.86ns    239.6mV    160.7mV    324.7mV
800ns     239.3mV    159.1mV    325mV
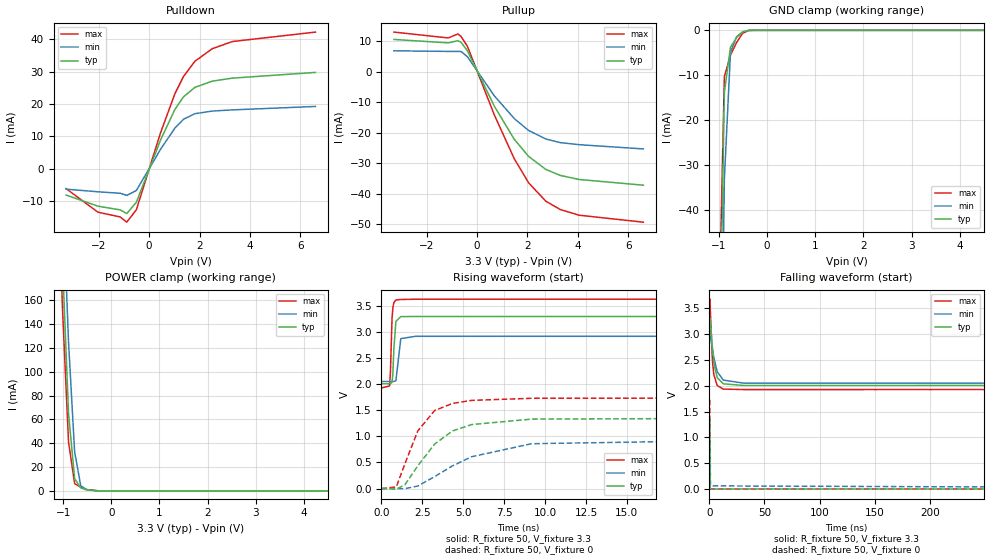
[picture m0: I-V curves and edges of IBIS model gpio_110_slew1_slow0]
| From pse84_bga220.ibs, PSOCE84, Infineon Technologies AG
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[Model] gpio_110_slew1_slow0
Model_type I/O
Enable   Active-High
Vinl  =  0.99
Vinh  =  2.31
Vmeas =  1.65
Cref  =  15e-12
| Capacitance   typ   min   max
C_comp   1.09946e-12   1.086232e-12   1.114407e-12
| Variables   typ   min   max
[GND Clamp Reference]   0   0   0
[POWER Clamp Reference]   3.3   2.92   3.63
[Pulldown Reference]   0   0   0
[Pullup Reference]   3.3   2.92   3.63
[Temperature Range]   25   125   -40
[Voltage Range]   3.3   2.92   3.63
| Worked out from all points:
|   slope of the pulldown table from 0 to 0.495 V, typ, clamps not added: 51.4 ohm
|   slope of the pullup table from 0 to 0.495 V, typ, clamps not added: 59.6 ohm
|   GND clamp passes 1 mA (typ) near -0.57 V on its own axis
|   POWER clamp passes 1 mA (typ) near -0.52 V on its own axis
|   falling waveform, R_fixture 50, V_fixture 3.3: 20-80 % time 3.76ns typ, 5.45ns min, 2.55ns max; typ from 3.3 V to 2.01 V
|   falling waveform, R_fixture 50, V_fixture 0: 20-80 % time 96.7ps typ, 105ps min, 92.1ps max; typ from 1.35 V to 0 V
|   rising waveform, R_fixture 50, V_fixture 3.3: 20-80 % time 112ps typ, 131ps min, 100ps max; typ from 2.01 V to 3.3 V
|   rising waveform, R_fixture 50, V_fixture 0: 20-80 % time 2.33ns typ, 3.95ns min, 1.54ns max; typ from 0 V to 1.35 V
[GND Clamp]
| Voltage   I(typ)   I(min)   I(max)
-1.65V    -892.5mA   -911.9mA   -883.9mA
-1.015V   -92.32mA   -129.7mA   -71.28mA
-888.3mV  -13.83mA   -33.21mA   -10.31mA
-761.4mV  -3.792mA   -4.944mA   -5.509mA
-634.5mV  -1.622mA   -1.436mA   -2.707mA
-507.6mV  -326.2uA   -352.3uA   -651.6uA
-380.7mV  -13.48uA   -32.14uA   -19.55uA
-253.8mV  -189.4nA   -1.276uA   -466.7nA
6.6V      0A         0A         0A
[POWER Clamp]
| Voltage   I(typ)   I(min)   I(max)
-1.523V   838.1mA    872.9mA    823.9mA
-1.142V   346.5mA    405.1mA    310.5mA
-1.015V   193mA      257.4mA    153.9mA
-888.3mV  64.97mA    124.9mA    40.96mA
-761.4mV  10.28mA    32.7mA     6.184mA
-634.5mV  2.553mA    4.346mA    3.067mA
-507.6mV  805.9uA    960.7uA    1.159mA
-253.8mV  1.454uA    10.02uA    1.678uA
6.6V      0A         0A         0A
[Pulldown]
| Voltage   I(typ)   I(min)   I(max)
-3.3V     -8.212mA   -6.391mA   -6.208mA
-2.03V    -11.66mA   -7.202mA   -13.53mA
-1.142V   -12.83mA   -7.672mA   -15.01mA
-888.3mV  -13.95mA   -8.321mA   -16.62mA
-507.6mV  -10.46mA   -6.8mA     -12.77mA
455.2mV   8.891mA    5.99mA     11.13mA
1.024V    18.33mA    12.55mA    23.2mA
1.366V    22.23mA    15.28mA    28.56mA
1.821V    25.16mA    16.99mA    33.26mA
2.503V    27.06mA    17.8mA     37.1mA
3.3V      28mA       18.16mA    39.33mA
6.6V      29.77mA    19.23mA    42.26mA
[Pullup]
| Voltage   I(typ)   I(min)   I(max)
-3.3V     10.56mA    6.84mA     12.97mA
-1.142V   9.434mA    6.628mA    11.05mA
-761.4mV  10.16mA    6.628mA    12.36mA
-634.5mV  9.61mA     6.615mA    11.54mA
-380.7mV  6.812mA    4.862mA    8.263mA
682.8mV   -11.29mA   -7.908mA   -14.14mA
1.479V    -22.2mA    -15.4mA    -28.59mA
2.048V    -27.81mA   -19.3mA    -36.47mA
2.731V    -32.06mA   -22.09mA   -42.48mA
3.3V      -34.01mA   -23.26mA   -45.19mA
4.051V    -35.35mA   -23.94mA   -47.06mA
6.6V      -37.22mA   -25.33mA   -49.35mA
[Ramp]
dV/dt_r   0.809557/2.32656n  0.566596/3.94709n  1.03932/1.53512n
dV/dt_f   0.776057/3.76495n  0.521386/5.44769n  1.02156/2.5486n
R_load = 50
[Falling Waveform]
R_fixture = 50
V_fixture = 3.3
V_fixture_min = 2.92
V_fixture_max = 3.63
| Time   V(typ)   V(min)   V(max)
0s        3.3V       2.92V      3.63V
517.7ps   3.318V     2.92V      3.676V
923.3ps   3.256V     2.958V     3.438V
2.305ns   2.86V      2.781V     2.683V
2.991ns   2.668V     2.69V      2.438V
4.046ns   2.445V     2.547V     2.216V
7.14ns    2.154V     2.269V     2.004V
12.65ns   2.037V     2.109V     1.935V
31.13ns   2.005V     2.05V      1.926V
800ns     2.007V     2.051V     1.927V
[Falling Waveform]
R_fixture = 50
V_fixture = 0
V_fixture_min = 0
V_fixture_max = 0
| Time   V(typ)   V(min)   V(max)
0s        1.349V     944.3mV    1.732V
386.1ps   1.349V     944.2mV    1.713V
420.9ps   1.349V     944.2mV    1.505V
512.3ps   1.341V     944.3mV    412.3mV
634.2ps   411.7mV    944.3mV    71.61mV
688.6ps   180.6mV    945.5mV    32.79mV
777.4ps   54.19mV    893.8mV    10.51mV
896.9ps   12.08mV    247.4mV    4.553mV
994.8ps   4.966mV    63.28mV    3.717mV
800ns     14.69nV    476.2nV    8.317nV
[Rising Waveform]
R_fixture = 50
V_fixture = 3.3
V_fixture_min = 2.92
V_fixture_max = 3.63
| Time   V(typ)   V(min)   V(max)
0s        2.007V     2.051V     1.927V
496.4ps   2.007V     2.051V     1.965V
547.2ps   2.007V     2.051V     2.217V
647.1ps   2.036V     2.051V     3.257V
699ps     2.208V     2.051V     3.464V
762.3ps   2.696V     2.051V     3.563V
883.9ps   3.201V     2.066V     3.613V
1.182ns   3.294V     2.872V     3.622V
2.096ns   3.296V     2.917V     3.627V
800ns     3.3V       2.92V      3.63V
[Rising Waveform]
R_fixture = 50
V_fixture = 0
V_fixture_min = 0
V_fixture_max = 0
| Time   V(typ)   V(min)   V(max)
0s        14.93nV    475.9nV    8.654nV
905.4ps   -12.15mV   -3.11mV    30.07mV
1.437ns   72.87mV    -1.731mV   477.1mV
2.219ns   434.3mV    47.95mV    1.103V
3.253ns   852.7mV    228.9mV    1.495V
4.337ns   1.103V     433.1mV    1.63V
5.514ns   1.226V     609.8mV    1.689V
9.181ns   1.33V      858.8mV    1.729V
26.71ns   1.35V      944.9mV    1.732V
800ns     1.349V     944.3mV    1.732V
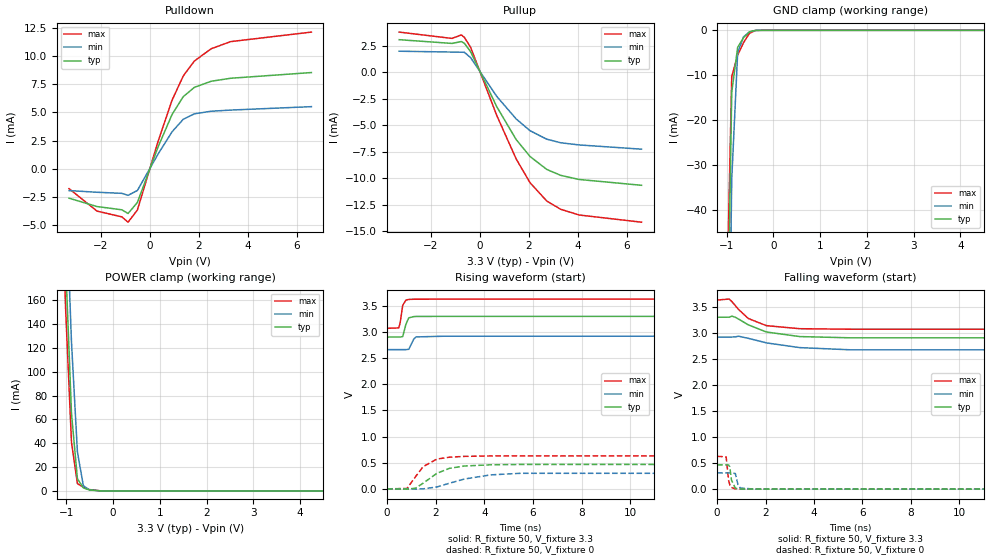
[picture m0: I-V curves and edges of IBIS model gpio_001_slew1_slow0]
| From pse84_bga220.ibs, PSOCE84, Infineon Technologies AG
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[Model] gpio_001_slew1_slow0
Model_type I/O
Enable   Active-High
Vinl  =  0.99
Vinh  =  2.31
Vmeas =  1.65
Cref  =  15e-12
| Capacitance   typ   min   max
C_comp   1.09946e-12   1.086232e-12   1.114407e-12
| Variables   typ   min   max
[GND Clamp Reference]   0   0   0
[POWER Clamp Reference]   3.3   2.92   3.63
[Pulldown Reference]   0   0   0
[Pullup Reference]   3.3   2.92   3.63
[Temperature Range]   25   125   -40
[Voltage Range]   3.3   2.92   3.63
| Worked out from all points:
|   slope of the pulldown table from 0 to 0.495 V, typ, clamps not added: 178 ohm
|   slope of the pullup table from 0 to 0.495 V, typ, clamps not added: 208 ohm
|   GND clamp passes 1 mA (typ) near -0.57 V on its own axis
|   POWER clamp passes 1 mA (typ) near -0.52 V on its own axis
|   falling waveform, R_fixture 50, V_fixture 3.3: 20-80 % time 1.34ns typ, 2.01ns min, 945ps max; typ from 3.3 V to 2.9 V
|   falling waveform, R_fixture 50, V_fixture 0: 20-80 % time 91.9ps typ, 99.2ps min, 88.6ps max; typ from 0.465 V to 0 V
|   rising waveform, R_fixture 50, V_fixture 3.3: 20-80 % time 117ps typ, 141ps min, 106ps max; typ from 2.9 V to 3.3 V
|   rising waveform, R_fixture 50, V_fixture 0: 20-80 % time 974ps typ, 1.66ns min, 672ps max; typ from 0 V to 0.465 V
[GND Clamp]
| Voltage   I(typ)   I(min)   I(max)
-1.65V    -892.5mA   -911.9mA   -883.9mA
-1.015V   -92.32mA   -129.7mA   -71.28mA
-888.3mV  -13.83mA   -33.21mA   -10.31mA
-761.4mV  -3.792mA   -4.944mA   -5.509mA
-634.5mV  -1.622mA   -1.436mA   -2.707mA
-507.6mV  -326.2uA   -352.3uA   -651.6uA
-380.7mV  -13.48uA   -32.14uA   -19.55uA
-253.8mV  -189.4nA   -1.276uA   -466.7nA
6.6V      0A         0A         0A
[POWER Clamp]
| Voltage   I(typ)   I(min)   I(max)
-1.523V   838.1mA    872.9mA    823.9mA
-1.142V   346.5mA    405.1mA    310.5mA
-1.015V   193mA      257.4mA    153.9mA
-888.3mV  64.97mA    124.9mA    40.96mA
-761.4mV  10.28mA    32.7mA     6.184mA
-634.5mV  2.553mA    4.346mA    3.067mA
-507.6mV  805.9uA    960.7uA    1.159mA
-253.8mV  1.454uA    10.02uA    1.678uA
6.6V      0A         0A         0A
[Pulldown]
| Voltage   I(typ)   I(min)   I(max)
-3.3V     -2.643mA   -1.966mA   -1.791mA
-2.157V   -3.39mA    -2.115mA   -3.795mA
-1.142V   -3.679mA   -2.212mA   -4.311mA
-888.3mV  -4.009mA   -2.389mA   -4.785mA
-507.6mV  -3.025mA   -1.958mA   -3.699mA
341.4mV   1.951mA    1.307mA    2.447mA
910.3mV   4.825mA    3.28mA     6.103mA
1.366V    6.41mA     4.394mA    8.255mA
1.821V    7.242mA    4.88mA     9.591mA
2.503V    7.783mA    5.111mA    10.68mA
3.3V      8.051mA    5.214mA    11.32mA
6.6V      8.562mA    5.52mA     12.17mA
[Pullup]
| Voltage   I(typ)   I(min)   I(max)
-3.3V     3.087mA    1.997mA    3.806mA
-1.142V   2.734mA    1.918mA    3.207mA
-761.4mV  2.909mA    1.902mA    3.539mA
-634.5mV  2.75mA     1.893mA    3.303mA
-380.7mV  1.949mA    1.391mA    2.365mA
682.8mV   -3.231mA   -2.262mA   -4.048mA
1.479V    -6.353mA   -4.405mA   -8.186mA
2.048V    -7.961mA   -5.522mA   -10.44mA
2.731V    -9.182mA   -6.324mA   -12.17mA
3.3V      -9.741mA   -6.66mA    -12.95mA
4.051V    -10.13mA   -6.865mA   -13.49mA
6.6V      -10.68mA   -7.265mA   -14.17mA
[Ramp]
dV/dt_r   0.279256/0.974309n  0.186635/1.66451n  0.377848/0.67211n
dV/dt_f   0.238266/1.34295n  0.15416/2.0139n  0.33546/0.945426n
R_load = 50
[Falling Waveform]
R_fixture = 50
V_fixture = 3.3
V_fixture_min = 2.92
V_fixture_max = 3.63
| Time   V(typ)   V(min)   V(max)
0s        3.3V       2.92V      3.63V
494.8ps   3.301V     2.92V      3.649V
604.8ps   3.321V     2.92V      3.603V
746.1ps   3.301V     2.923V     3.525V
883.6ps   3.265V     2.936V     3.45V
1.284ns   3.155V     2.895V     3.277V
2.033ns   3.017V     2.808V     3.139V
3.413ns   2.929V     2.717V     3.08V
5.507ns   2.905V     2.675V     3.07V
800ns     2.903V     2.663V     3.071V
[Falling Waveform]
R_fixture = 50
V_fixture = 0
V_fixture_min = 0
V_fixture_max = 0
| Time   V(typ)   V(min)   V(max)
0s        465.4mV    311.1mV    629.7mV
372.1ps   465.4mV    310.9mV    621.3mV
471.3ps   465.9mV    311mV      175.6mV
521.8ps   429.5mV    311.1mV    83.35mV
590.4ps   175.6mV    311.1mV    32.65mV
750.8ps   19.51mV    299.7mV    4.46mV
858.4ps   6.122mV    91.02mV    1.942mV
958ps     2.4mV      22.94mV    1.504mV
1.551ns   777uV      630.7uV    683.1uV
800ns     23.16nV    669.1nV    14.09nV
[Rising Waveform]
R_fixture = 50
V_fixture = 3.3
V_fixture_min = 2.92
V_fixture_max = 3.63
| Time   V(typ)   V(min)   V(max)
0s        2.903V     2.663V     3.071V
482.4ps   2.903V     2.663V     3.078V
540ps     2.903V     2.663V     3.175V
645.3ps   2.913V     2.663V     3.512V
779.9ps   3.152V     2.663V     3.61V
894.1ps   3.271V     2.67V      3.623V
1.107ns   3.295V     2.871V     3.627V
1.197ns   3.297V     2.906V     3.627V
2.317ns   3.299V     2.919V     3.629V
800ns     3.3V       2.92V      3.63V
[Rising Waveform]
R_fixture = 50
V_fixture = 0
V_fixture_min = 0
V_fixture_max = 0
| Time   V(typ)   V(min)   V(max)
0s        23.31nV    668.5nV    14.36nV
821.7ps   -6.228mV   286.4uV    7.24mV
1.17ns    12.19mV    -4.17mV    231.7mV
1.482ns   106.8mV    -530.7uV   423.9mV
2.053ns   297.8mV    36.12mV    570.1mV
2.57ns    392.4mV    107.8mV    605.3mV
3.184ns   436.9mV    187.8mV    621mV
4.262ns   459.9mV    267.1mV    629mV
5.482ns   466.3mV    297.1mV    630.4mV
800ns     465.4mV    311.1mV    629.7mV
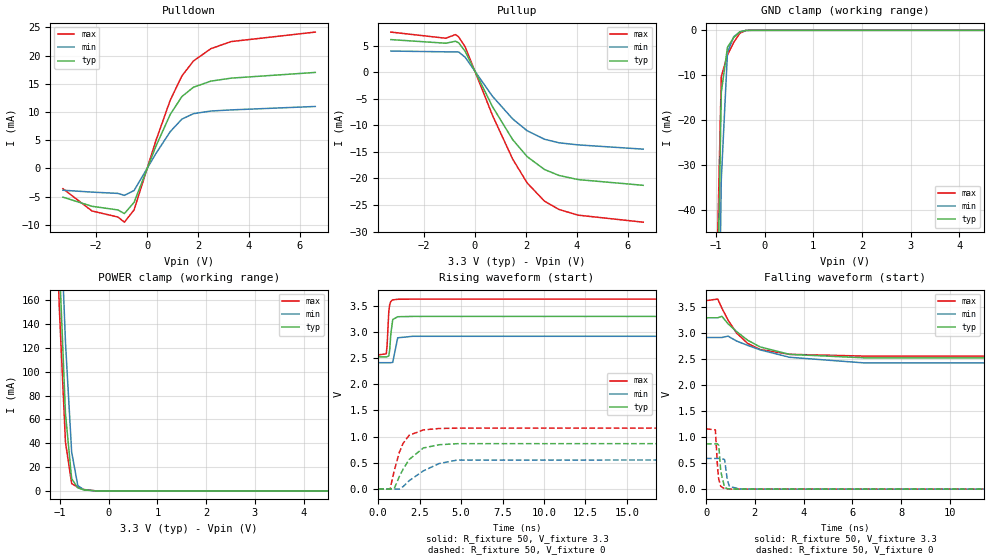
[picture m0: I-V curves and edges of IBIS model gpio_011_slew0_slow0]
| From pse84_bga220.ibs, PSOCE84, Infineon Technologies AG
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[Model] gpio_011_slew0_slow0
Model_type I/O
Enable   Active-High
Vinl  =  0.99
Vinh  =  2.31
Vmeas =  1.65
Cref  =  15e-12
| Capacitance   typ   min   max
C_comp   1.09946e-12   1.086232e-12   1.114407e-12
| Variables   typ   min   max
[GND Clamp Reference]   0   0   0
[POWER Clamp Reference]   3.3   2.92   3.63
[Pulldown Reference]   0   0   0
[Pullup Reference]   3.3   2.92   3.63
[Temperature Range]   25   125   -40
[Voltage Range]   3.3   2.92   3.63
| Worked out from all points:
|   slope of the pulldown table from 0 to 0.495 V, typ, clamps not added: 89.5 ohm
|   slope of the pullup table from 0 to 0.495 V, typ, clamps not added: 104 ohm
|   GND clamp passes 1 mA (typ) near -0.57 V on its own axis
|   POWER clamp passes 1 mA (typ) near -0.52 V on its own axis
|   falling waveform, R_fixture 50, V_fixture 3.3: 20-80 % time 1.57ns typ, 2.32ns min, 1.1ns max; typ from 3.3 V to 2.52 V
|   falling waveform, R_fixture 50, V_fixture 0: 20-80 % time 94.9ps typ, 103ps min, 90.8ps max; typ from 0.871 V to 0 V
|   rising waveform, R_fixture 50, V_fixture 3.3: 20-80 % time 114ps typ, 136ps min, 103ps max; typ from 2.52 V to 3.3 V
|   rising waveform, R_fixture 50, V_fixture 0: 20-80 % time 1.07ns typ, 1.84ns min, 723ps max; typ from 0 V to 0.871 V
[GND Clamp]
| Voltage   I(typ)   I(min)   I(max)
-1.65V    -892.5mA   -911.9mA   -883.9mA
-1.015V   -92.32mA   -129.7mA   -71.28mA
-888.3mV  -13.83mA   -33.21mA   -10.31mA
-761.4mV  -3.792mA   -4.944mA   -5.509mA
-634.5mV  -1.622mA   -1.436mA   -2.707mA
-507.6mV  -326.2uA   -352.3uA   -651.6uA
-380.7mV  -13.48uA   -32.14uA   -19.55uA
-253.8mV  -189.4nA   -1.276uA   -466.7nA
6.6V      0A         0A         0A
[POWER Clamp]
| Voltage   I(typ)   I(min)   I(max)
-1.523V   838.1mA    872.9mA    823.9mA
-1.142V   346.5mA    405.1mA    310.5mA
-1.015V   193mA      257.4mA    153.9mA
-888.3mV  64.97mA    124.9mA    40.96mA
-761.4mV  10.28mA    32.7mA     6.184mA
-634.5mV  2.553mA    4.346mA    3.067mA
-507.6mV  805.9uA    960.7uA    1.159mA
-253.8mV  1.454uA    10.02uA    1.678uA
6.6V      0A         0A         0A
[Pulldown]
| Voltage   I(typ)   I(min)   I(max)
-3.3V     -5.082mA   -3.85mA    -3.58mA
-2.157V   -6.699mA   -4.187mA   -7.533mA
-1.142V   -7.349mA   -4.413mA   -8.601mA
-888.3mV  -7.985mA   -4.765mA   -9.517mA
-507.6mV  -6.006mA   -3.898mA   -7.337mA
341.4mV   3.871mA    2.6mA      4.846mA
910.3mV   9.58mA     6.527mA    12.1mA
1.366V    12.74mA    8.745mA    16.39mA
1.821V    14.4mA     9.716mA    19.05mA
2.503V    15.48mA    10.18mA    21.23mA
3.3V      16.01mA    10.38mA    22.49mA
6.6V      17.02mA    10.99mA    24.17mA
[Pullup]
| Voltage   I(typ)   I(min)   I(max)
-3.3V     6.119mA    3.963mA    7.53mA
-1.142V   5.434mA    3.816mA    6.371mA
-761.4mV  5.81mA     3.796mA    7.069mA
-634.5mV  5.494mA    3.782mA    6.598mA
-380.7mV  3.894mA    2.779mA    4.724mA
682.8mV   -6.455mA   -4.52mA    -8.084mA
1.479V    -12.69mA   -8.8mA     -16.35mA
2.048V    -15.9mA    -11.03mA   -20.85mA
2.731V    -18.33mA   -12.63mA   -24.29mA
3.3V      -19.44mA   -13.3mA    -25.84mA
4.051V    -20.22mA   -13.69mA   -26.91mA
6.6V      -21.29mA   -14.49mA   -28.23mA
[Ramp]
dV/dt_r   0.522854/1.07028n  0.354814/1.84402n  0.69646/0.723339n
dV/dt_f   0.464902/1.57369n  0.304206/2.3249n  0.640672/1.09783n
R_load = 50
[Falling Waveform]
R_fixture = 50
V_fixture = 3.3
V_fixture_min = 2.92
V_fixture_max = 3.63
| Time   V(typ)   V(min)   V(max)
0s        3.3V       2.92V      3.63V
478.6ps   3.3V       2.92V      3.66V
648.3ps   3.328V     2.92V      3.484V
901.3ps   3.184V     2.946V     3.255V
1.248ns   3.035V     2.852V     3.006V
1.709ns   2.866V     2.768V     2.804V
2.215ns   2.739V     2.682V     2.69V
3.424ns   2.595V     2.539V     2.596V
6.513ns   2.528V     2.43V      2.562V
800ns     2.525V     2.413V     2.562V
[Falling Waveform]
R_fixture = 50
V_fixture = 0
V_fixture_min = 0
V_fixture_max = 0
| Time   V(typ)   V(min)   V(max)
0s        871.4mV    591.4mV    1.161V
379.4ps   871.4mV    591.2mV    1.142V
470.6ps   872.3mV    591.3mV    408.8mV
519.4ps   840.5mV    591.4mV    188.3mV
601.2ps   341.5mV    591.4mV    54.33mV
757.5ps   36.87mV    570.6mV    8.206mV
869.9ps   9.819mV    177.7mV    3.525mV
958.9ps   4.43mV     50.61mV    2.723mV
1.424ns   1.549mV    1.329mV    1.283mV
800ns     18.81nV    575.6nV    11nV
[Rising Waveform]
R_fixture = 50
V_fixture = 3.3
V_fixture_min = 2.92
V_fixture_max = 3.63
| Time   V(typ)   V(min)   V(max)
0s        2.525V     2.413V     2.562V
488.6ps   2.525V     2.413V     2.583V
535.2ps   2.525V     2.413V     2.736V
642.1ps   2.543V     2.413V     3.404V
693.6ps   2.658V     2.413V     3.524V
761.7ps   2.963V     2.413V     3.585V
877.5ps   3.238V     2.42V      3.615V
1.176ns   3.292V     2.889V     3.626V
2.093ns   3.298V     2.918V     3.629V
800ns     3.3V       2.92V      3.63V
[Rising Waveform]
R_fixture = 50
V_fixture = 0
V_fixture_min = 0
V_fixture_max = 0
| Time   V(typ)   V(min)   V(max)
0s        19.02nV    575.2nV    11.35nV
716.8ps   -6.585mV   48.73uV    -5.566mV
966.8ps   4.277mV    -3.507mV   345.4mV
1.273ns   233.4mV    -4.571mV   696mV
1.499ns   373.7mV    41.05mV    868.5mV
1.862ns   559.4mV    153.9mV    1.023V
2.724ns   781.8mV    343.6mV    1.127V
3.67ns    843.3mV    483.5mV    1.154V
4.771ns   863.6mV    550.6mV    1.161V
800ns     871.4mV    591.4mV    1.161V
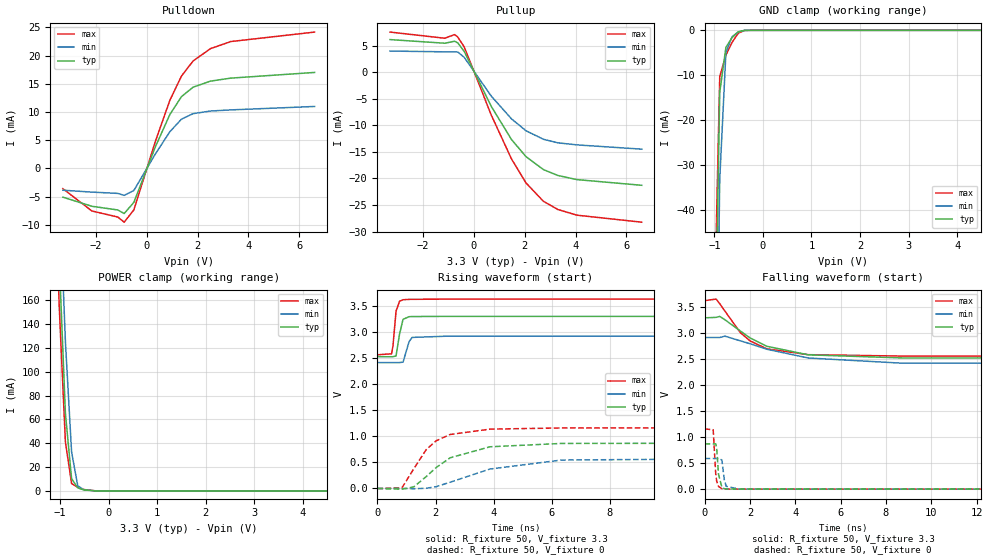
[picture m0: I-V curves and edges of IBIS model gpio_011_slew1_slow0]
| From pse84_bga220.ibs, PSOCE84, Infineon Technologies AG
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[Model] gpio_011_slew1_slow0
Model_type I/O
Enable   Active-High
Vinl  =  0.99
Vinh  =  2.31
Vmeas =  1.65
Cref  =  15e-12
| Capacitance   typ   min   max
C_comp   1.09946e-12   1.086232e-12   1.114407e-12
| Variables   typ   min   max
[GND Clamp Reference]   0   0   0
[POWER Clamp Reference]   3.3   2.92   3.63
[Pulldown Reference]   0   0   0
[Pullup Reference]   3.3   2.92   3.63
[Temperature Range]   25   125   -40
[Voltage Range]   3.3   2.92   3.63
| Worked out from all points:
|   slope of the pulldown table from 0 to 0.495 V, typ, clamps not added: 89.5 ohm
|   slope of the pullup table from 0 to 0.495 V, typ, clamps not added: 104 ohm
|   GND clamp passes 1 mA (typ) near -0.57 V on its own axis
|   POWER clamp passes 1 mA (typ) near -0.52 V on its own axis
|   falling waveform, R_fixture 50, V_fixture 3.3: 20-80 % time 2ns typ, 2.92ns min, 1.41ns max; typ from 3.3 V to 2.52 V
|   falling waveform, R_fixture 50, V_fixture 0: 20-80 % time 94.4ps typ, 103ps min, 91.2ps max; typ from 0.871 V to 0 V
|   rising waveform, R_fixture 50, V_fixture 3.3: 20-80 % time 115ps typ, 136ps min, 103ps max; typ from 2.52 V to 3.3 V
|   rising waveform, R_fixture 50, V_fixture 0: 20-80 % time 1.38ns typ, 2.32ns min, 956ps max; typ from 0 V to 0.871 V
[GND Clamp]
| Voltage   I(typ)   I(min)   I(max)
-1.65V    -892.5mA   -911.9mA   -883.9mA
-1.015V   -92.32mA   -129.7mA   -71.28mA
-888.3mV  -13.83mA   -33.21mA   -10.31mA
-761.4mV  -3.792mA   -4.944mA   -5.509mA
-634.5mV  -1.622mA   -1.436mA   -2.707mA
-507.6mV  -326.2uA   -352.3uA   -651.6uA
-380.7mV  -13.48uA   -32.14uA   -19.55uA
-253.8mV  -189.4nA   -1.276uA   -466.7nA
6.6V      0A         0A         0A
[POWER Clamp]
| Voltage   I(typ)   I(min)   I(max)
-1.523V   838.1mA    872.9mA    823.9mA
-1.142V   346.5mA    405.1mA    310.5mA
-1.015V   193mA      257.4mA    153.9mA
-888.3mV  64.97mA    124.9mA    40.96mA
-761.4mV  10.28mA    32.7mA     6.184mA
-634.5mV  2.553mA    4.346mA    3.067mA
-507.6mV  805.9uA    960.7uA    1.159mA
-253.8mV  1.454uA    10.02uA    1.678uA
6.6V      0A         0A         0A
[Pulldown]
| Voltage   I(typ)   I(min)   I(max)
-3.3V     -5.082mA   -3.85mA    -3.58mA
-2.157V   -6.699mA   -4.187mA   -7.533mA
-1.142V   -7.349mA   -4.413mA   -8.601mA
-888.3mV  -7.985mA   -4.765mA   -9.517mA
-507.6mV  -6.006mA   -3.898mA   -7.337mA
341.4mV   3.871mA    2.6mA      4.846mA
910.3mV   9.58mA     6.527mA    12.1mA
1.366V    12.74mA    8.745mA    16.39mA
1.821V    14.4mA     9.716mA    19.05mA
2.503V    15.48mA    10.18mA    21.23mA
3.3V      16.01mA    10.38mA    22.49mA
6.6V      17.02mA    10.99mA    24.17mA
[Pullup]
| Voltage   I(typ)   I(min)   I(max)
-3.3V     6.119mA    3.963mA    7.53mA
-1.142V   5.434mA    3.816mA    6.371mA
-761.4mV  5.81mA     3.796mA    7.069mA
-634.5mV  5.494mA    3.782mA    6.598mA
-380.7mV  3.894mA    2.779mA    4.724mA
682.8mV   -6.455mA   -4.52mA    -8.084mA
1.479V    -12.69mA   -8.8mA     -16.35mA
2.048V    -15.9mA    -11.03mA   -20.85mA
2.731V    -18.33mA   -12.63mA   -24.29mA
3.3V      -19.44mA   -13.3mA    -25.84mA
4.051V    -20.22mA   -13.69mA   -26.91mA
6.6V      -21.29mA   -14.49mA   -28.23mA
[Ramp]
dV/dt_r   0.522854/1.38331n  0.354811/2.32374n  0.69646/0.955914n
dV/dt_f   0.464902/1.99687n  0.304204/2.92114n  0.640672/1.40687n
R_load = 50
[Falling Waveform]
R_fixture = 50
V_fixture = 3.3
V_fixture_min = 2.92
V_fixture_max = 3.63
| Time   V(typ)   V(min)   V(max)
0s        3.3V       2.92V      3.63V
506.4ps   3.308V     2.92V      3.661V
665ps     3.327V     2.92V      3.573V
894.8ps   3.263V     2.947V     3.43V
1.58ns    3.045V     2.856V     3.013V
2.008ns   2.912V     2.8V       2.855V
2.742ns   2.752V     2.695V     2.703V
4.575ns   2.587V     2.526V     2.59V
8.72ns    2.527V     2.426V     2.563V
800ns     2.525V     2.413V     2.562V
[Falling Waveform]
R_fixture = 50
V_fixture = 0
V_fixture_min = 0
V_fixture_max = 0
| Time   V(typ)   V(min)   V(max)
0s        871.4mV    591.4mV    1.161V
378.5ps   871.4mV    591.2mV    1.144V
490.1ps   872.3mV    591.3mV    298.5mV
533.1ps   792.6mV    591.4mV    156.8mV
611.8ps   287.5mV    591.4mV    52.91mV
763ps     35.79mV    562.2mV    7.998mV
869.2ps   10.51mV    179.5mV    3.757mV
951.9ps   4.401mV    55.06mV    3.015mV
1.527ns   1.653mV    879.3uV    1.389mV
800ns     18.81nV    575.6nV    11.01nV
[Rising Waveform]
R_fixture = 50
V_fixture = 3.3
V_fixture_min = 2.92
V_fixture_max = 3.63
| Time   V(typ)   V(min)   V(max)
0s        2.525V     2.413V     2.562V
488ps     2.525V     2.413V     2.581V
535.7ps   2.525V     2.413V     2.736V
640.5ps   2.54V      2.413V     3.397V
760.2ps   2.955V     2.413V     3.587V
881.5ps   3.242V     2.421V     3.617V
1.089ns   3.292V     2.812V     3.624V
1.192ns   3.295V     2.895V     3.625V
2.361ns   3.298V     2.918V     3.629V
800ns     3.3V       2.92V      3.63V
[Rising Waveform]
R_fixture = 50
V_fixture = 0
V_fixture_min = 0
V_fixture_max = 0
| Time   V(typ)   V(min)   V(max)
0s        19.02nV    575.2nV    11.35nV
844ps     -13.17mV   -81.54uV   12.4mV
1.247ns   28.94mV    -4.468mV   372.9mV
1.68ns    227.8mV    3.71mV     745.5mV
2.023ns   401.1mV    34.47mV    914.2mV
2.505ns   588.3mV    120.6mV    1.035V
3.875ns   799.1mV    372.6mV    1.137V
6.337ns   863.2mV    545mV      1.16V
18.25ns   871.6mV    591.6mV    1.161V
800ns     871.4mV    591.4mV    1.161V
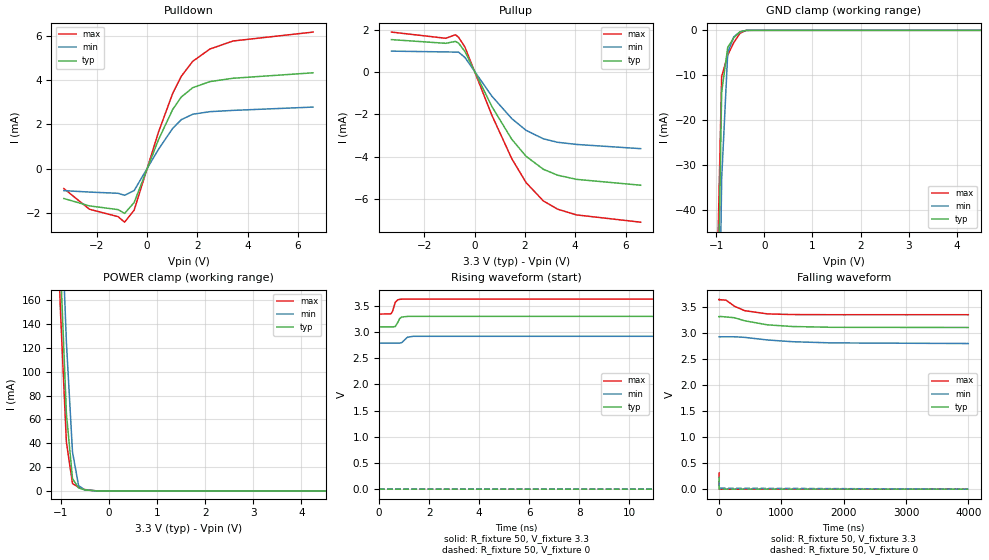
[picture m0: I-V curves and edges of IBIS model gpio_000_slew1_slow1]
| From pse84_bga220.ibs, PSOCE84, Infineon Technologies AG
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[Model] gpio_000_slew1_slow1
Model_type I/O
Enable   Active-High
Vinl  =  0.99
Vinh  =  2.31
Vmeas =  1.65
Cref  =  15e-12
| Capacitance   typ   min   max
C_comp   1.09946e-12   1.08623e-12   1.11440e-12
| Variables   typ   min   max
[GND Clamp Reference]   0   0   0
[POWER Clamp Reference]   3.3   2.92   3.63
[Pulldown Reference]   0   0   0
[Pullup Reference]   3.3   2.92   3.63
[Temperature Range]   25   125   -40
[Voltage Range]   3.3   2.92   3.63
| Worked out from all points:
|   slope of the pulldown table from 0 to 0.495 V, typ, clamps not added: 352 ohm
|   slope of the pullup table from 0 to 0.495 V, typ, clamps not added: 415 ohm
|   GND clamp passes 1 mA (typ) near -0.57 V on its own axis
|   POWER clamp passes 1 mA (typ) near -0.52 V on its own axis
|   falling waveform, R_fixture 50, V_fixture 3.3: 20-80 % time 553ns typ, 850ns min, 312ns max; typ from 3.3 V to 3.1 V
|   falling waveform, R_fixture 50, V_fixture 0: 20-80 % time 91.5ps typ, 98.5ps min, 88.1ps max; typ from 0.239 V to 0 V
|   rising waveform, R_fixture 50, V_fixture 3.3: 20-80 % time 124ps typ, 149ps min, 111ps max; typ from 3.1 V to 3.3 V
|   rising waveform, R_fixture 50, V_fixture 0: 20-80 % time 564ns typ, 856ns min, 336ns max; typ from 0 V to 0.239 V
[GND Clamp]
| Voltage   I(typ)   I(min)   I(max)
-1.65V    -892.5mA   -911.9mA   -883.9mA
-1.015V   -92.32mA   -129.7mA   -71.28mA
-888.3mV  -13.83mA   -33.21mA   -10.31mA
-761.4mV  -3.792mA   -4.944mA   -5.509mA
-634.5mV  -1.622mA   -1.436mA   -2.707mA
-507.6mV  -326.2uA   -352.3uA   -651.6uA
-380.7mV  -13.48uA   -32.14uA   -19.55uA
-253.8mV  -189.4nA   -1.276uA   -466.7nA
6.6V      0A         0A         0A
[POWER Clamp]
| Voltage   I(typ)   I(min)   I(max)
-1.523V   838.1mA    872.9mA    823.9mA
-1.142V   346.5mA    405.1mA    310.5mA
-1.015V   193mA      257.4mA    153.9mA
-888.3mV  64.97mA    124.9mA    40.96mA
-761.4mV  10.28mA    32.7mA     6.184mA
-634.5mV  2.553mA    4.346mA    3.067mA
-507.6mV  805.9uA    960.7uA    1.159mA
-253.8mV  1.454uA    10.02uA    1.678uA
6.6V      0A         0A         0A
[Pulldown]
| Voltage   I(typ)   I(min)   I(max)
-3.3V     -1.343mA   -987.7uA   -894.2uA
-2.284V   -1.677mA   -1.053mA   -1.827mA
-1.142V   -1.844mA   -1.108mA   -2.163mA
-888.3mV  -2.016mA   -1.198mA   -2.411mA
-507.6mV  -1.525mA   -984.6uA   -1.869mA
455.2mV   1.299mA    868.3uA    1.635mA
1.024V    2.673mA    1.819mA    3.396mA
1.366V    3.234mA    2.211mA    4.169mA
1.821V    3.654mA    2.456mA    4.843mA
2.503V    3.928mA    2.572mA    5.397mA
3.425V    4.079mA    2.63mA     5.759mA
6.6V      4.324mA    2.779mA    6.16mA
[Pullup]
| Voltage   I(typ)   I(min)   I(max)
-3.3V     1.542mA    996.2uA    1.899mA
-1.142V   1.367mA    958.5uA    1.605mA
-761.4mV  1.457mA    951uA      1.773mA
-634.5mV  1.377mA    946.6uA    1.655mA
-380.7mV  976.2uA    695.7uA    1.185mA
682.8mV   -1.619mA   -1.131mA   -2.028mA
1.479V    -3.183mA   -2.202mA   -4.102mA
2.048V    -3.99mA    -2.759mA   -5.236mA
2.731V    -4.603mA   -3.158mA   -6.102mA
3.3V      -4.885mA   -3.325mA   -6.496mA
4.051V    -5.082mA   -3.427mA   -6.768mA
6.6V      -5.361mA   -3.627mA   -7.113mA
[Ramp]
dV/dt_r   0.143555/0.563882u  94.83m/0.855799u  0.19497/0.33596u
dV/dt_f   0.121162/0.55287u  77.6659m/0.850086u  0.172115/0.312462u
R_load = 50
[Falling Waveform]
R_fixture = 50
V_fixture = 3.3
V_fixture_min = 2.92
V_fixture_max = 3.63
| Time   V(typ)   V(min)   V(max)
0s        3.3V       2.92V      3.63V
460.8ps   3.299V     2.92V      3.643V
599.8ps   3.311V     2.92V      3.632V
111.6ns   3.3V       2.92V      3.622V
246.5ns   3.285V     2.92V      3.505V
409.4ns   3.227V     2.909V     3.421V
775.9ns   3.149V     2.859V     3.359V
1.173us   3.117V     2.826V     3.346V
1.8us     3.102V     2.803V     3.343V
4us       3.098V     2.791V     3.343V
[Falling Waveform]
R_fixture = 50
V_fixture = 0
V_fixture_min = 0
V_fixture_max = 0
| Time   V(typ)   V(min)   V(max)
0s        239.3mV    158.5mV    325mV
367.3ps   239.2mV    158.4mV    321.5mV
393.1ps   239.2mV    158.3mV    284.4mV
447.4ps   239.2mV    158.3mV    127.6mV
493.4ps   238.1mV    158.5mV    61.88mV
593ps     84.12mV    158.6mV    15.54mV
643.9ps   38.69mV    158.6mV    7.991mV
751.4ps   9.143mV    151.8mV    1.7mV
917.8ps   1.138mV    19.12mV    77.57uV
4us       26.31nV    729.6nV    16.41nV
[Rising Waveform]
R_fixture = 50
V_fixture = 3.3
V_fixture_min = 2.92
V_fixture_max = 3.63
| Time   V(typ)   V(min)   V(max)
0s        3.098V     2.79V      3.343V
480.5ps   3.098V     2.79V      3.348V
539ps     3.098V     2.79V      3.396V
649ps     3.106V     2.79V      3.568V
749.7ps   3.184V     2.79V      3.615V
823ps     3.257V     2.79V      3.624V
901.1ps   3.286V     2.796V     3.628V
1.136ns   3.299V     2.902V     3.63V
1.368ns   3.3V       2.919V     3.63V
4us       3.3V       2.92V      3.63V
[Rising Waveform]
R_fixture = 50
V_fixture = 0
V_fixture_min = 0
V_fixture_max = 0
| Time   V(typ)   V(min)   V(max)
0s        26.29nV    727.8nV    16.58nV
107.1ns   37.14uV    6.268uV    9.082mV
190.4ns   6.552mV    236.4uV    75.46mV
283.4ns   35.31mV    3.537mV    152.1mV
446.3ns   95.61mV    23.4mV     238.6mV
609.2ns   143.4mV    49.31mV    281mV
812.8ns   182.3mV    78.73mV    305.2mV
1.208us   218mV      117.3mV    320.4mV
1.802us   234mV      143.3mV    324.4mV
4us       239.3mV    158.1mV    325mV
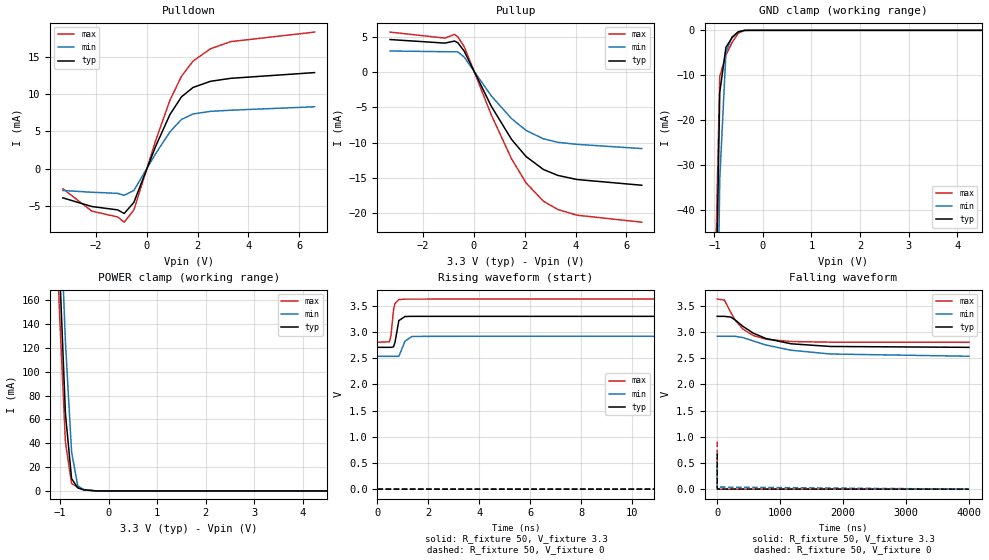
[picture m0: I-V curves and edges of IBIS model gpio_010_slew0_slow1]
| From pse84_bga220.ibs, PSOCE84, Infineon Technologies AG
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[Model] gpio_010_slew0_slow1
Model_type I/O
Enable   Active-High
Vinl  =  0.99
Vinh  =  2.31
Vmeas =  1.65
Cref  =  15e-12
| Capacitance   typ   min   max
C_comp   1.09946e-12   1.08623e-12   1.11440e-12
| Variables   typ   min   max
[GND Clamp Reference]   0   0   0
[POWER Clamp Reference]   3.3   2.92   3.63
[Pulldown Reference]   0   0   0
[Pullup Reference]   3.3   2.92   3.63
[Temperature Range]   25   125   -40
[Voltage Range]   3.3   2.92   3.63
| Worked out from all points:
|   slope of the pulldown table from 0 to 0.495 V, typ, clamps not added: 118 ohm
|   slope of the pullup table from 0 to 0.495 V, typ, clamps not added: 139 ohm
|   GND clamp passes 1 mA (typ) near -0.57 V on its own axis
|   POWER clamp passes 1 mA (typ) near -0.52 V on its own axis
|   falling waveform, R_fixture 50, V_fixture 3.3: 20-80 % time 590ns typ, 896ns min, 333ns max; typ from 3.3 V to 2.71 V
|   falling waveform, R_fixture 50, V_fixture 0: 20-80 % time 95.5ps typ, 104ps min, 91.9ps max; typ from 0.678 V to 0 V
|   rising waveform, R_fixture 50, V_fixture 3.3: 20-80 % time 118ps typ, 141ps min, 107ps max; typ from 2.71 V to 3.3 V
|   rising waveform, R_fixture 50, V_fixture 0: 20-80 % time 600ns typ, 893ns min, 369ns max; typ from 0 V to 0.677 V
[GND Clamp]
| Voltage   I(typ)   I(min)   I(max)
-1.65V    -892.5mA   -911.9mA   -883.9mA
-1.015V   -92.32mA   -129.7mA   -71.28mA
-888.3mV  -13.83mA   -33.21mA   -10.31mA
-761.4mV  -3.792mA   -4.944mA   -5.509mA
-634.5mV  -1.622mA   -1.436mA   -2.707mA
-507.6mV  -326.2uA   -352.3uA   -651.6uA
-380.7mV  -13.48uA   -32.14uA   -19.55uA
-253.8mV  -189.4nA   -1.276uA   -466.7nA
6.6V      0A         0A         0A
[POWER Clamp]
| Voltage   I(typ)   I(min)   I(max)
-1.523V   838.1mA    872.9mA    823.9mA
-1.142V   346.5mA    405.1mA    310.5mA
-1.015V   193mA      257.4mA    153.9mA
-888.3mV  64.97mA    124.9mA    40.96mA
-761.4mV  10.28mA    32.7mA     6.184mA
-634.5mV  2.553mA    4.346mA    3.067mA
-507.6mV  805.9uA    960.7uA    1.159mA
-253.8mV  1.454uA    10.02uA    1.678uA
6.6V      0A         0A         0A
[Pulldown]
| Voltage   I(typ)   I(min)   I(max)
-3.3V     -3.927mA   -2.935mA   -2.706mA
-2.157V   -5.088mA   -3.173mA   -5.708mA
-1.142V   -5.539mA   -3.326mA   -6.49mA
-888.3mV  -6.021mA   -3.588mA   -7.187mA
-507.6mV  -4.537mA   -2.937mA   -5.552mA
341.4mV   2.926mA    1.959mA    3.67mA
910.3mV   7.24mA     4.92mA     9.156mA
1.366V    9.625mA    6.592mA    12.39mA
1.821V    10.88mA    7.324mA    14.41mA
2.503V    11.7mA     7.671mA    16.06mA
3.3V      12.1mA     7.826mA    17.02mA
6.6V      12.87mA    8.285mA    18.3mA
[Pullup]
| Voltage   I(typ)   I(min)   I(max)
-3.3V     4.576mA    2.959mA    5.629mA
-1.142V   4.072mA    2.856mA    4.775mA
-761.4mV  4.362mA    2.845mA    5.31mA
-634.5mV  4.125mA    2.836mA    4.956mA
-380.7mV  2.925mA    2.085mA    3.549mA
682.8mV   -4.848mA   -3.389mA   -6.074mA
1.479V    -9.532mA   -6.595mA   -12.28mA
2.048V    -11.95mA   -8.262mA   -15.67mA
2.731V    -13.78mA   -9.452mA   -18.26mA
3.3V      -14.62mA   -9.947mA   -19.44mA
4.051V    -15.2mA    -10.23mA   -20.24mA
6.6V      -16.01mA   -10.83mA   -21.23mA
[Ramp]
dV/dt_r   0.406407/0.600119u  0.271123/0.892646u  0.54687/0.368846u
dV/dt_f   0.354899/0.590024u  0.229324/0.896322u  0.495106/0.333253u
R_load = 50
[Falling Waveform]
R_fixture = 50
V_fixture = 3.3
V_fixture_min = 2.92
V_fixture_max = 3.63
| Time   V(typ)   V(min)   V(max)
0s        3.3V       2.92V      3.63V
113.9ns   3.3V       2.92V      3.612V
217.3ns   3.285V     2.92V      3.371V
287.7ns   3.229V     2.918V     3.224V
409.9ns   3.108V     2.894V     3.055V
572.8ns   2.979V     2.83V      2.934V
776.4ns   2.876V     2.752V     2.864V
1.173us   2.776V     2.653V     2.819V
1.799us   2.725V     2.581V     2.807V
4us       2.708V     2.538V     2.805V
[Falling Waveform]
R_fixture = 50
V_fixture = 0
V_fixture_min = 0
V_fixture_max = 0
| Time   V(typ)   V(min)   V(max)
0s        677.8mV    454.4mV    911.5mV
375ps     677.7mV    454.3mV    901.5mV
501.5ps   673.8mV    454.4mV    196.9mV
536.1ps   602mV      454.4mV    117.4mV
612.7ps   223.8mV    454.5mV    40.47mV
667.7ps   96.96mV    454.6mV    19.88mV
762ps     26.93mV    431.6mV    5.492mV
874.8ps   6.74mV     130.3mV    698.6uV
957.9ps   2.263mV    39.96mV    249uV
4us       21.21nV    622.4nV    12.33nV
[Rising Waveform]
R_fixture = 50
V_fixture = 3.3
V_fixture_min = 2.92
V_fixture_max = 3.63
| Time   V(typ)   V(min)   V(max)
0s        2.708V     2.536V     2.805V
476.3ps   2.708V     2.536V     2.815V
530.7ps   2.708V     2.536V     2.934V
631.2ps   2.718V     2.536V     3.419V
688.3ps   2.802V     2.536V     3.545V
841.3ps   3.219V     2.537V     3.62V
1.082ns   3.297V     2.826V     3.629V
1.36ns    3.3V       2.917V     3.629V
4.661ns   3.3V       2.92V      3.63V
4us       3.3V       2.92V      3.63V
[Rising Waveform]
R_fixture = 50
V_fixture = 0
V_fixture_min = 0
V_fixture_max = 0
| Time   V(typ)   V(min)   V(max)
0s        20.92nV    617.9nV    12.65nV
120.2ns   178.1uV    26.82uV    31.19mV
208.5ns   21.35mV    880.4uV    213.1mV
313.1ns   108.8mV    12.74mV    433.2mV
459.2ns   253.3mV    61mV       641.5mV
622.1ns   387.1mV    131.1mV    763.8mV
825.7ns   499.8mV    213.5mV    834.8mV
1.198us   601.3mV    321.2mV    885.2mV
1.825us   655.6mV    404.8mV    906.6mV
4us       677.3mV    451.9mV    911.4mV
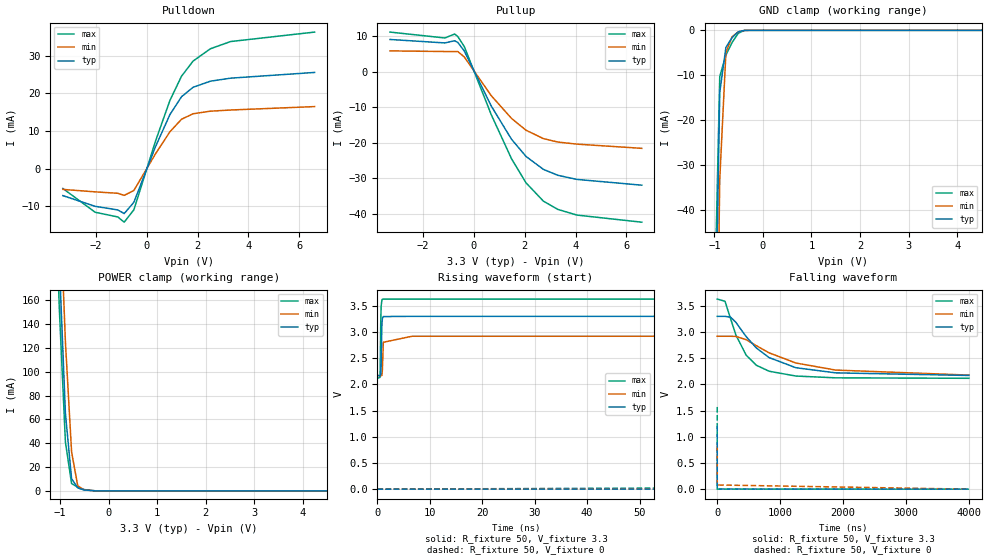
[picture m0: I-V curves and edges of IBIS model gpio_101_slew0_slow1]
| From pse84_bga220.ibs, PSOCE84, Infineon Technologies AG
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[Model] gpio_101_slew0_slow1
Model_type I/O
Enable   Active-High
Vinl  =  0.99
Vinh  =  2.31
Vmeas =  1.65
Cref  =  15e-12
| Capacitance   typ   min   max
C_comp   1.09946e-12   1.08623e-12   1.11440e-12
| Variables   typ   min   max
[GND Clamp Reference]   0   0   0
[POWER Clamp Reference]   3.3   2.92   3.63
[Pulldown Reference]   0   0   0
[Pullup Reference]   3.3   2.92   3.63
[Temperature Range]   25   125   -40
[Voltage Range]   3.3   2.92   3.63
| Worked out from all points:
|   slope of the pulldown table from 0 to 0.495 V, typ, clamps not added: 59.8 ohm
|   slope of the pullup table from 0 to 0.495 V, typ, clamps not added: 69.5 ohm
|   GND clamp passes 1 mA (typ) near -0.57 V on its own axis
|   POWER clamp passes 1 mA (typ) near -0.52 V on its own axis
|   falling waveform, R_fixture 50, V_fixture 3.3: 20-80 % time 666ns typ, 987ns min, 370ns max; typ from 3.3 V to 2.17 V
|   falling waveform, R_fixture 50, V_fixture 0: 20-80 % time 96.7ps typ, 105ps min, 93ps max; typ from 1.21 V to 0 V
|   rising waveform, R_fixture 50, V_fixture 3.3: 20-80 % time 118ps typ, 140ps min, 106ps max; typ from 2.17 V to 3.3 V
|   rising waveform, R_fixture 50, V_fixture 0: 20-80 % time 691ns typ, 992ns min, 433ns max; typ from 0 V to 1.2 V
[GND Clamp]
| Voltage   I(typ)   I(min)   I(max)
-1.65V    -892.5mA   -911.9mA   -883.9mA
-1.015V   -92.32mA   -129.7mA   -71.28mA
-888.3mV  -13.83mA   -33.21mA   -10.31mA
-761.4mV  -3.792mA   -4.944mA   -5.509mA
-634.5mV  -1.622mA   -1.436mA   -2.707mA
-507.6mV  -326.2uA   -352.3uA   -651.6uA
-380.7mV  -13.48uA   -32.14uA   -19.55uA
-253.8mV  -189.4nA   -1.276uA   -466.7nA
6.6V      0A         0A         0A
[POWER Clamp]
| Voltage   I(typ)   I(min)   I(max)
-1.523V   838.1mA    872.9mA    823.9mA
-1.142V   346.5mA    405.1mA    310.5mA
-1.015V   193mA      257.4mA    153.9mA
-888.3mV  64.97mA    124.9mA    40.96mA
-761.4mV  10.28mA    32.7mA     6.184mA
-634.5mV  2.553mA    4.346mA    3.067mA
-507.6mV  805.9uA    960.7uA    1.159mA
-253.8mV  1.454uA    10.02uA    1.678uA
6.6V      0A         0A         0A
[Pulldown]
| Voltage   I(typ)   I(min)   I(max)
-3.3V     -7.203mA   -5.552mA   -5.309mA
-2.03V    -10.05mA   -6.205mA   -11.63mA
-1.142V   -11mA      -6.582mA   -12.87mA
-888.3mV  -11.97mA   -7.136mA   -14.27mA
-507.6mV  -8.987mA   -5.837mA   -10.98mA
341.4mV   5.791mA    3.891mA    7.243mA
910.3mV   14.34mA    9.772mA    18.1mA
1.366V    19.09mA    13.1mA     24.54mA
1.821V    21.6mA     14.56mA    28.57mA
2.503V    23.23mA    15.25mA    31.85mA
3.3V      24.03mA    15.56mA    33.77mA
6.6V      25.55mA    16.47mA    36.28mA
[Pullup]
| Voltage   I(typ)   I(min)   I(max)
-3.3V     9.072mA    5.861mA    11.15mA
-1.142V   8.1mA      5.68mA     9.493mA
-761.4mV  8.711mA    5.677mA    10.6mA
-634.5mV  8.24mA     5.665mA    9.896mA
-380.7mV  5.841mA    4.164mA    7.086mA
682.8mV   -9.682mA   -6.766mA   -12.13mA
1.479V    -19.03mA   -13.16mA   -24.52mA
2.048V    -23.85mA   -16.47mA   -31.28mA
2.731V    -27.49mA   -18.83mA   -36.43mA
3.3V      -29.16mA   -19.8mA    -38.76mA
4.051V    -30.32mA   -20.39mA   -40.36mA
6.6V      -31.94mA   -21.57mA   -42.36mA
[Ramp]
dV/dt_r   0.721608/0.690718u  0.492038/0.992116u  0.941609/0.433455u
dV/dt_f   0.67736/0.665577u  0.445257/0.987149u  0.908092/0.370249u
R_load = 50
[Falling Waveform]
R_fixture = 50
V_fixture = 3.3
V_fixture_min = 2.92
V_fixture_max = 3.63
| Time   V(typ)   V(min)   V(max)
0s        3.3V       2.92V      3.63V
124.1ns   3.3V       2.92V      3.588V
214.1ns   3.283V     2.92V      3.25V
295.9ns   3.187V     2.917V     2.948V
458.8ns   2.915V     2.855V     2.561V
621.7ns   2.696V     2.74V      2.366V
825.3ns   2.512V     2.603V     2.252V
1.25us    2.319V     2.409V     2.16V
1.882us   2.221V     2.274V     2.126V
4us       2.171V     2.178V     2.117V
[Falling Waveform]
R_fixture = 50
V_fixture = 0
V_fixture_min = 0
V_fixture_max = 0
| Time   V(typ)   V(min)   V(max)
0s        1.207V     833mV      1.57V
385ps     1.207V     832.8mV    1.552V
415.8ps   1.207V     832.8mV    1.39V
512.5ps   1.199V     833mV      361.2mV
579.4ps   813.1mV    833mV      132.7mV
678.8ps   181.5mV    833.7mV    34.96mV
776.6ps   46.67mV    785.8mV    8.706mV
885.2ps   10.59mV    251mV      1.288mV
964.2ps   2.857mV    80.05mV    504.5uV
4us       18.45nV    516.7nV    9.133nV
[Rising Waveform]
R_fixture = 50
V_fixture = 3.3
V_fixture_min = 2.92
V_fixture_max = 3.63
| Time   V(typ)   V(min)   V(max)
0s        2.169V     2.169V     2.116V
481.2ps   2.169V     2.169V     2.134V
533.2ps   2.169V     2.169V     2.309V
626.9ps   2.18V      2.169V     3.161V
700.7ps   2.376V     2.169V     3.485V
851.3ps   3.156V     2.172V     3.615V
940.9ps   3.262V     2.275V     3.626V
1.117ns   3.296V     2.805V     3.629V
6.602ns   3.3V       2.92V      3.63V
4us       3.3V       2.92V      3.63V
[Rising Waveform]
R_fixture = 50
V_fixture = 0
V_fixture_min = 0
V_fixture_max = 0
| Time   V(typ)   V(min)   V(max)
0s        16.07nV    504.8nV    9.389nV
128.1ns   310.6uV    70.83uV    50.45mV
233.5ns   45.79mV    2.397mV    364.4mV
360.4ns   213.8mV    31.84mV    757.3mV
523.3ns   463.2mV    123.8mV    1.099V
686.2ns   672.3mV    237.7mV    1.286V
889.8ns   857.6mV    373.2mV    1.402V
1.285us   1.041V     568.4mV    1.5V
1.898us   1.141V     717.1mV    1.548V
4us       1.203V     820.1mV    1.569V
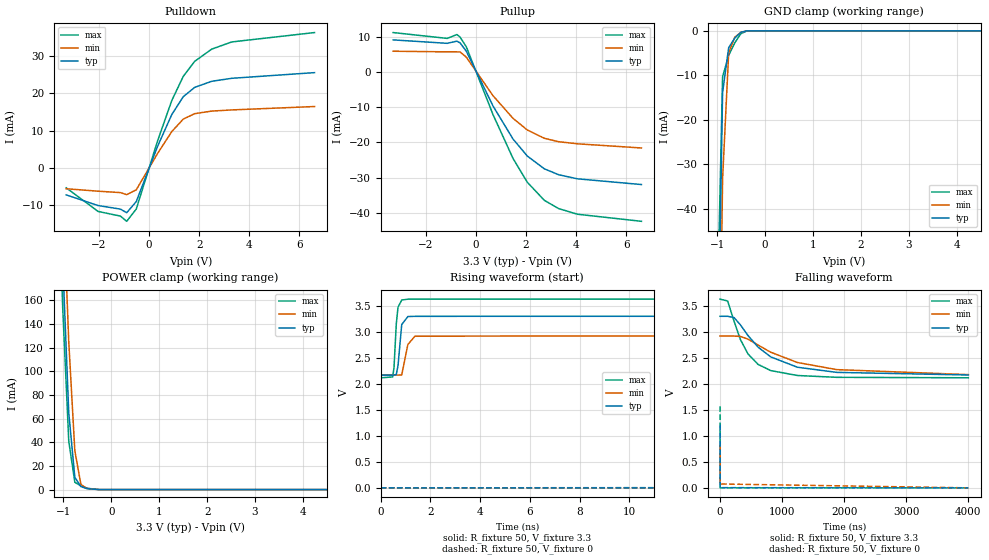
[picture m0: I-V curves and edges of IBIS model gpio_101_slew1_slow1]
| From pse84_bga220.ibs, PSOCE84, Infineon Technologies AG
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[Model] gpio_101_slew1_slow1
Model_type I/O
Enable   Active-High
Vinl  =  0.99
Vinh  =  2.31
Vmeas =  1.65
Cref  =  15e-12
| Capacitance   typ   min   max
C_comp   1.09946e-12   1.08623e-12   1.11440e-12
| Variables   typ   min   max
[GND Clamp Reference]   0   0   0
[POWER Clamp Reference]   3.3   2.92   3.63
[Pulldown Reference]   0   0   0
[Pullup Reference]   3.3   2.92   3.63
[Temperature Range]   25   125   -40
[Voltage Range]   3.3   2.92   3.63
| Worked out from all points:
|   slope of the pulldown table from 0 to 0.495 V, typ, clamps not added: 59.8 ohm
|   slope of the pullup table from 0 to 0.495 V, typ, clamps not added: 69.5 ohm
|   GND clamp passes 1 mA (typ) near -0.57 V on its own axis
|   POWER clamp passes 1 mA (typ) near -0.52 V on its own axis
|   falling waveform, R_fixture 50, V_fixture 3.3: 20-80 % time 666ns typ, 987ns min, 370ns max; typ from 3.3 V to 2.17 V
|   falling waveform, R_fixture 50, V_fixture 0: 20-80 % time 96.7ps typ, 105ps min, 93.1ps max; typ from 1.21 V to 0 V
|   rising waveform, R_fixture 50, V_fixture 3.3: 20-80 % time 118ps typ, 140ps min, 106ps max; typ from 2.17 V to 3.3 V
|   rising waveform, R_fixture 50, V_fixture 0: 20-80 % time 691ns typ, 992ns min, 434ns max; typ from 0 V to 1.2 V
[GND Clamp]
| Voltage   I(typ)   I(min)   I(max)
-1.65V    -892.5mA   -911.9mA   -883.9mA
-1.015V   -92.32mA   -129.7mA   -71.28mA
-888.3mV  -13.83mA   -33.21mA   -10.31mA
-761.4mV  -3.792mA   -4.944mA   -5.509mA
-634.5mV  -1.622mA   -1.436mA   -2.707mA
-507.6mV  -326.2uA   -352.3uA   -651.6uA
-380.7mV  -13.48uA   -32.14uA   -19.55uA
-253.8mV  -189.4nA   -1.276uA   -466.7nA
6.6V      0A         0A         0A
[POWER Clamp]
| Voltage   I(typ)   I(min)   I(max)
-1.523V   838.1mA    872.9mA    823.9mA
-1.142V   346.5mA    405.1mA    310.5mA
-1.015V   193mA      257.4mA    153.9mA
-888.3mV  64.97mA    124.9mA    40.96mA
-761.4mV  10.28mA    32.7mA     6.184mA
-634.5mV  2.553mA    4.346mA    3.067mA
-507.6mV  805.9uA    960.7uA    1.159mA
-253.8mV  1.454uA    10.02uA    1.678uA
6.6V      0A         0A         0A
[Pulldown]
| Voltage   I(typ)   I(min)   I(max)
-3.3V     -7.203mA   -5.552mA   -5.309mA
-2.03V    -10.05mA   -6.205mA   -11.63mA
-1.142V   -11mA      -6.582mA   -12.87mA
-888.3mV  -11.97mA   -7.136mA   -14.27mA
-507.6mV  -8.987mA   -5.837mA   -10.98mA
341.4mV   5.791mA    3.891mA    7.243mA
910.3mV   14.34mA    9.772mA    18.1mA
1.366V    19.09mA    13.1mA     24.54mA
1.821V    21.6mA     14.56mA    28.57mA
2.503V    23.23mA    15.25mA    31.85mA
3.3V      24.03mA    15.56mA    33.77mA
6.6V      25.55mA    16.47mA    36.28mA
[Pullup]
| Voltage   I(typ)   I(min)   I(max)
-3.3V     9.072mA    5.861mA    11.15mA
-1.142V   8.1mA      5.68mA     9.493mA
-761.4mV  8.711mA    5.677mA    10.6mA
-634.5mV  8.24mA     5.665mA    9.896mA
-380.7mV  5.841mA    4.164mA    7.086mA
682.8mV   -9.682mA   -6.766mA   -12.13mA
1.479V    -19.03mA   -13.16mA   -24.52mA
2.048V    -23.85mA   -16.47mA   -31.28mA
2.731V    -27.49mA   -18.83mA   -36.43mA
3.3V      -29.16mA   -19.8mA    -38.76mA
4.051V    -30.32mA   -20.39mA   -40.36mA
6.6V      -31.94mA   -21.57mA   -42.36mA
[Ramp]
dV/dt_r   0.721612/0.690643u  0.492042/0.992168u  0.941611/0.433592u
dV/dt_f   0.67736/0.66554u  0.445256/0.987162u  0.908092/0.369863u
R_load = 50
[Falling Waveform]
R_fixture = 50
V_fixture = 3.3
V_fixture_min = 2.92
V_fixture_max = 3.63
| Time   V(typ)   V(min)   V(max)
0s        3.3V       2.92V      3.63V
121.6ns   3.3V       2.92V      3.594V
225.6ns   3.275V     2.92V      3.205V
326.9ns   3.136V     2.912V     2.854V
449ns     2.931V     2.861V     2.577V
611.9ns   2.707V     2.747V     2.375V
815.5ns   2.519V     2.609V     2.256V
1.246us   2.32V      2.411V     2.161V
1.881us   2.221V     2.274V     2.126V
4us       2.171V     2.178V     2.117V
[Falling Waveform]
R_fixture = 50
V_fixture = 0
V_fixture_min = 0
V_fixture_max = 0
| Time   V(typ)   V(min)   V(max)
0s        1.207V     833mV      1.57V
384.9ps   1.207V     832.8mV    1.552V
419.6ps   1.207V     832.8mV    1.355V
512.5ps   1.199V     833mV      361.6mV
630.8ps   378.4mV    833mV      65.28mV
679.6ps   179.2mV    833.7mV    34.68mV
778ps     46.66mV    782.4mV    8.872mV
888.4ps   11.48mV    239.1mV    1.379mV
969.4ps   3.677mV    74.68mV    532.2uV
4us       18.45nV    516.7nV    9.133nV
[Rising Waveform]
R_fixture = 50
V_fixture = 3.3
V_fixture_min = 2.92
V_fixture_max = 3.63
| Time   V(typ)   V(min)   V(max)
0s        2.169V     2.169V     2.116V
480.7ps   2.169V     2.169V     2.134V
533.1ps   2.169V     2.169V     2.31V
626.6ps   2.18V      2.169V     3.16V
695.5ps   2.352V     2.169V     3.474V
844.8ps   3.141V     2.171V     3.613V
1.092ns   3.295V     2.757V     3.629V
1.374ns   3.299V     2.916V     3.629V
5.006ns   3.3V       2.92V      3.63V
4us       3.3V       2.92V      3.63V
[Rising Waveform]
R_fixture = 50
V_fixture = 0
V_fixture_min = 0
V_fixture_max = 0
| Time   V(typ)   V(min)   V(max)
0s        16.07nV    504.8nV    9.389nV
124.2ns   344.2uV    67.12uV    42.93mV
238.4ns   50.71mV    2.702mV    380.9mV
374.9ns   236.4mV    38.02mV    795.4mV
537.7ns   484.1mV    133.6mV    1.121V
700.6ns   688.4mV    247.9mV    1.297V
904.3ns   867.9mV    382mV      1.407V
1.298us   1.045V     573.3mV    1.502V
1.904us   1.142V     718mV      1.549V
4us       1.203V     820.1mV    1.569V
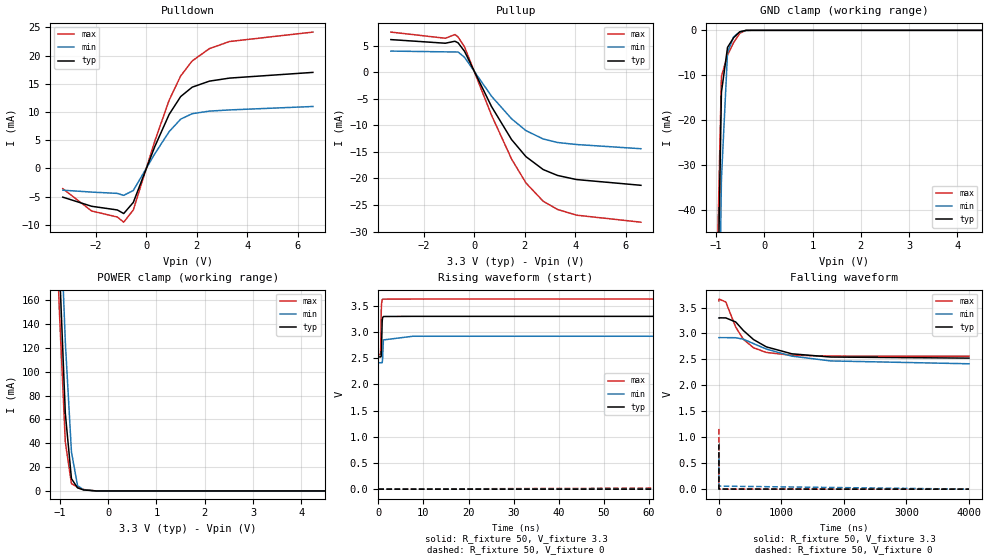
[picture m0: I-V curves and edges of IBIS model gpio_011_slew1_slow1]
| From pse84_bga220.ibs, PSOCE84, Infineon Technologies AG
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[Model] gpio_011_slew1_slow1
Model_type I/O
Enable   Active-High
Vinl  =  0.99
Vinh  =  2.31
Vmeas =  1.65
Cref  =  15e-12
| Capacitance   typ   min   max
C_comp   1.09946e-12   1.08623e-12   1.11440e-12
| Variables   typ   min   max
[GND Clamp Reference]   0   0   0
[POWER Clamp Reference]   3.3   2.92   3.63
[Pulldown Reference]   0   0   0
[Pullup Reference]   3.3   2.92   3.63
[Temperature Range]   25   125   -40
[Voltage Range]   3.3   2.92   3.63
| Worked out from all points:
|   slope of the pulldown table from 0 to 0.495 V, typ, clamps not added: 89.5 ohm
|   slope of the pullup table from 0 to 0.495 V, typ, clamps not added: 104 ohm
|   GND clamp passes 1 mA (typ) near -0.57 V on its own axis
|   POWER clamp passes 1 mA (typ) near -0.52 V on its own axis
|   falling waveform, R_fixture 50, V_fixture 3.3: 20-80 % time 572ns typ, 878ns min, 316ns max; typ from 3.3 V to 2.52 V
|   falling waveform, R_fixture 50, V_fixture 0: 20-80 % time 95.2ps typ, 104ps min, 91.6ps max; typ from 0.871 V to 0 V
|   rising waveform, R_fixture 50, V_fixture 3.3: 20-80 % time 119ps typ, 143ps min, 107ps max; typ from 2.52 V to 3.3 V
|   rising waveform, R_fixture 50, V_fixture 0: 20-80 % time 563ns typ, 850ns min, 340ns max; typ from 0 V to 0.871 V
[GND Clamp]
| Voltage   I(typ)   I(min)   I(max)
-1.65V    -892.5mA   -911.9mA   -883.9mA
-1.015V   -92.32mA   -129.7mA   -71.28mA
-888.3mV  -13.83mA   -33.21mA   -10.31mA
-761.4mV  -3.792mA   -4.944mA   -5.509mA
-634.5mV  -1.622mA   -1.436mA   -2.707mA
-507.6mV  -326.2uA   -352.3uA   -651.6uA
-380.7mV  -13.48uA   -32.14uA   -19.55uA
-253.8mV  -189.4nA   -1.276uA   -466.7nA
6.6V      0A         0A         0A
[POWER Clamp]
| Voltage   I(typ)   I(min)   I(max)
-1.523V   838.1mA    872.9mA    823.9mA
-1.142V   346.5mA    405.1mA    310.5mA
-1.015V   193mA      257.4mA    153.9mA
-888.3mV  64.97mA    124.9mA    40.96mA
-761.4mV  10.28mA    32.7mA     6.184mA
-634.5mV  2.553mA    4.346mA    3.067mA
-507.6mV  805.9uA    960.7uA    1.159mA
-253.8mV  1.454uA    10.02uA    1.678uA
6.6V      0A         0A         0A
[Pulldown]
| Voltage   I(typ)   I(min)   I(max)
-3.3V     -5.082mA   -3.847mA   -3.58mA
-2.157V   -6.699mA   -4.185mA   -7.533mA
-1.142V   -7.349mA   -4.412mA   -8.601mA
-888.3mV  -7.984mA   -4.764mA   -9.517mA
-507.6mV  -6.006mA   -3.898mA   -7.337mA
341.4mV   3.871mA    2.599mA    4.846mA
910.3mV   9.579mA    6.524mA    12.1mA
1.366V    12.74mA    8.739mA    16.39mA
1.821V    14.4mA     9.707mA    19.05mA
2.503V    15.47mA    10.16mA    21.23mA
3.3V      16.01mA    10.37mA    22.49mA
6.6V      17.02mA    10.98mA    24.16mA
[Pullup]
| Voltage   I(typ)   I(min)   I(max)
-3.3V     6.119mA    3.957mA    7.53mA
-1.142V   5.434mA    3.812mA    6.371mA
-761.4mV  5.81mA     3.793mA    7.069mA
-634.5mV  5.494mA    3.779mA    6.598mA
-380.7mV  3.894mA    2.777mA    4.724mA
682.8mV   -6.455mA   -4.515mA   -8.084mA
1.479V    -12.69mA   -8.783mA   -16.35mA
2.048V    -15.9mA    -11mA      -20.85mA
2.731V    -18.33mA   -12.58mA   -24.29mA
3.3V      -19.44mA   -13.24mA   -25.84mA
4.051V    -20.21mA   -13.62mA   -26.91mA
6.6V      -21.29mA   -14.41mA   -28.23mA
[Ramp]
dV/dt_r   0.522556/0.562675u  0.352069/0.850293u  0.696445/0.3403u
dV/dt_f   0.464761/0.572113u  0.302569/0.878332u  0.64065/0.316309u
R_load = 50
[Falling Waveform]
R_fixture = 50
V_fixture = 3.3
V_fixture_min = 2.92
V_fixture_max = 3.63
| Time   V(typ)   V(min)   V(max)
0s        3.3V       2.92V      3.63V
484.5ps   3.301V     2.92V      3.663V
110.7ns   3.3V       2.92V      3.607V
269.6ns   3.221V     2.918V     3.122V
391.8ns   3.057V     2.89V      2.887V
554.7ns   2.882V     2.804V     2.724V
758.3ns   2.742V     2.7V       2.635V
1.167us   2.608V     2.563V     2.579V
1.788us   2.546V     2.471V     2.564V
4us       2.525V     2.416V     2.562V
[Falling Waveform]
R_fixture = 50
V_fixture = 0
V_fixture_min = 0
V_fixture_max = 0
| Time   V(typ)   V(min)   V(max)
0s        871.4mV    589.6mV    1.161V
379.4ps   871.3mV    589.5mV    1.144V
507.5ps   863mV      589.6mV    240.8mV
540.2ps   770.2mV    589.6mV    147.3mV
618ps     278mV      589.7mV    49.41mV
665.9ps   133.6mV    589.8mV    25.33mV
770.1ps   32.37mV    550.7mV    5.861mV
875.2ps   7.928mV    174.7mV    982.7uV
950.6ps   2.741mV    58.83mV    397uV
4us       19.29nV    580.1nV    11.01nV
[Rising Waveform]
R_fixture = 50
V_fixture = 3.3
V_fixture_min = 2.92
V_fixture_max = 3.63
| Time   V(typ)   V(min)   V(max)
0s        2.525V     2.414V     2.562V
479.2ps   2.525V     2.414V     2.575V
531.4ps   2.525V     2.413V     2.71V
630.8ps   2.536V     2.414V     3.331V
695.1ps   2.658V     2.414V     3.523V
854.1ps   3.207V     2.416V     3.619V
940ps     3.273V     2.483V     3.626V
1.127ns   3.297V     2.85V      3.629V
7.622ns   3.3V       2.92V      3.63V
4us       3.3V       2.92V      3.63V
[Rising Waveform]
R_fixture = 50
V_fixture = 0
V_fixture_min = 0
V_fixture_max = 0
| Time   V(typ)   V(min)   V(max)
0s        19.02nV    575.2nV    11.35nV
116.2ns   170.3uV    97.83uV    39.09mV
198ns     23.73mV    812.9uV    264.8mV
302.3ns   138.5mV    15.21mV    562.7mV
448.3ns   333.5mV    79.67mV    840.1mV
611.2ns   512.8mV    174.2mV    991.1mV
814.8ns   659.6mV    285mV      1.076V
1.174us   780.7mV    423.5mV    1.132V
1.787us   845.2mV    528.8mV    1.156V
4us       870.9mV    586.8mV    1.161V
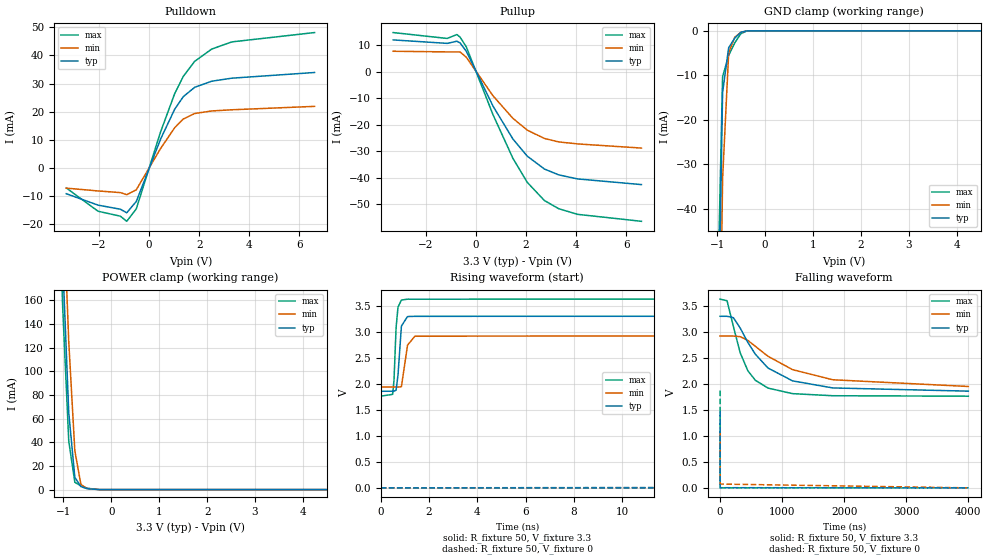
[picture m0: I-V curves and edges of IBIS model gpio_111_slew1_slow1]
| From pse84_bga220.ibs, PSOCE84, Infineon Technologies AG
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[Model] gpio_111_slew1_slow1
Model_type I/O
Enable   Active-High
Vinl  =  0.99
Vinh  =  2.31
Vmeas =  1.65
Cref  =  15e-12
| Capacitance   typ   min   max
C_comp   1.09946e-12   1.08623e-12   1.11440e-12
| Variables   typ   min   max
[GND Clamp Reference]   0   0   0
[POWER Clamp Reference]   3.3   2.92   3.63
[Pulldown Reference]   0   0   0
[Pullup Reference]   3.3   2.92   3.63
[Temperature Range]   25   125   -40
[Voltage Range]   3.3   2.92   3.63
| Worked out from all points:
|   slope of the pulldown table from 0 to 0.495 V, typ, clamps not added: 45.2 ohm
|   slope of the pullup table from 0 to 0.495 V, typ, clamps not added: 52.1 ohm
|   GND clamp passes 1 mA (typ) near -0.57 V on its own axis
|   POWER clamp passes 1 mA (typ) near -0.52 V on its own axis
|   falling waveform, R_fixture 50, V_fixture 3.3: 20-80 % time 625ns typ, 958ns min, 329ns max; typ from 3.3 V to 1.86 V
|   falling waveform, R_fixture 50, V_fixture 0: 20-80 % time 96.4ps typ, 106ps min, 91.5ps max; typ from 1.48 V to 0 V
|   rising waveform, R_fixture 50, V_fixture 3.3: 20-80 % time 117ps typ, 138ps min, 103ps max; typ from 1.86 V to 3.3 V
|   rising waveform, R_fixture 50, V_fixture 0: 20-80 % time 609ns typ, 904ns min, 367ns max; typ from 0 V to 1.47 V
[GND Clamp]
| Voltage   I(typ)   I(min)   I(max)
-1.65V    -892.5mA   -911.9mA   -883.9mA
-1.015V   -92.32mA   -129.7mA   -71.28mA
-888.3mV  -13.83mA   -33.21mA   -10.31mA
-761.4mV  -3.792mA   -4.944mA   -5.509mA
-634.5mV  -1.622mA   -1.436mA   -2.707mA
-507.6mV  -326.2uA   -352.3uA   -651.6uA
-380.7mV  -13.48uA   -32.14uA   -19.55uA
-253.8mV  -189.4nA   -1.276uA   -466.7nA
6.6V      0A         0A         0A
[POWER Clamp]
| Voltage   I(typ)   I(min)   I(max)
-1.523V   838.1mA    872.9mA    823.9mA
-1.142V   346.5mA    405.1mA    310.5mA
-1.015V   193mA      257.4mA    153.9mA
-888.3mV  64.97mA    124.9mA    40.96mA
-761.4mV  10.28mA    32.7mA     6.184mA
-634.5mV  2.553mA    4.346mA    3.067mA
-507.6mV  805.9uA    960.7uA    1.159mA
-253.8mV  1.454uA    10.02uA    1.678uA
6.6V      0A         0A         0A
[Pulldown]
| Voltage   I(typ)   I(min)   I(max)
-3.3V     -9.135mA   -7.157mA   -7.087mA
-2.03V    -13.19mA   -8.152mA   -15.36mA
-1.142V   -14.64mA   -8.738mA   -17.11mA
-888.3mV  -15.9mA    -9.489mA   -18.93mA
-507.6mV  -11.91mA   -7.751mA   -14.53mA
455.2mV   10.12mA    6.824mA    12.65mA
1.024V    20.87mA    14.3mA     26.39mA
1.366V    25.31mA    17.39mA    32.51mA
1.821V    28.65mA    19.34mA    37.87mA
2.503V    30.82mA    20.26mA    42.24mA
3.3V      31.89mA    20.67mA    44.77mA
6.6V      33.91mA    21.88mA    48.09mA
[Pullup]
| Voltage   I(typ)   I(min)   I(max)
-3.3V     12.1mA     7.82mA     14.87mA
-1.142V   10.79mA    7.573mA    12.65mA
-761.4mV  11.61mA    7.566mA    14.12mA
-634.5mV  10.98mA    7.55mA     13.18mA
-380.7mV  7.78mA     5.549mA    9.437mA
682.8mV   -12.9mA    -9.017mA   -16.15mA
1.479V    -25.35mA   -17.53mA   -32.65mA
2.048V    -31.76mA   -21.95mA   -41.65mA
2.731V    -36.61mA   -25.08mA   -48.5mA
3.3V      -38.82mA   -26.38mA   -51.59mA
4.051V    -40.35mA   -27.14mA   -53.71mA
6.6V      -42.49mA   -28.71mA   -56.34mA
[Ramp]
dV/dt_r   0.882958/0.609161u  0.61739/0.904374u  1.12273/0.3666u
dV/dt_f   0.863955/0.625209u  0.581989/0.958362u  1.12003/0.328801u
R_load = 50
[Falling Waveform]
R_fixture = 50
V_fixture = 3.3
V_fixture_min = 2.92
V_fixture_max = 3.63
| Time   V(typ)   V(min)   V(max)
0s        3.3V       2.92V      3.63V
112.6ns   3.3V       2.92V      3.599V
214.8ns   3.273V     2.92V      3.102V
324.2ns   3.074V     2.908V     2.598V
446.4ns   2.799V     2.837V     2.254V
568.6ns   2.57V      2.722V     2.069V
772.2ns   2.305V     2.531V     1.919V
1.167us   2.058V     2.274V     1.812V
1.815us   1.922V     2.079V     1.772V
4us       1.86V      1.95V      1.763V
[Falling Waveform]
R_fixture = 50
V_fixture = 0
V_fixture_min = 0
V_fixture_max = 0
| Time   V(typ)   V(min)   V(max)
0s        1.475V     1.041V     1.872V
390.2ps   1.475V     1.041V     1.848V
426.6ps   1.475V     1.041V     1.608V
516.1ps   1.464V     1.041V     443.9mV
639.2ps   444mV      1.041V     74.25mV
692.4ps   197.5mV    1.042V     36.11mV
785ps     55.97mV    970.2mV    10.59mV
898ps     12.98mV    285.1mV    1.34mV
994.4ps   3.052mV    72.84mV    814.2uV
4us       16.2nV     462.9nV    7.795nV
[Rising Waveform]
R_fixture = 50
V_fixture = 3.3
V_fixture_min = 2.92
V_fixture_max = 3.63
| Time   V(typ)   V(min)   V(max)
0s        1.858V     1.94V      1.763V
492.4ps   1.858V     1.94V      1.799V
548.2ps   1.858V     1.94V      2.065V
635.3ps   1.879V     1.94V      3.083V
714.7ps   2.171V     1.94V      3.477V
855.4ps   3.112V     1.945V     3.612V
1.109ns   3.295V     2.745V     3.629V
1.413ns   3.299V     2.917V     3.628V
6.459ns   3.3V       2.92V      3.63V
4us       3.3V       2.92V      3.63V
[Rising Waveform]
R_fixture = 50
V_fixture = 0
V_fixture_min = 0
V_fixture_max = 0
| Time   V(typ)   V(min)   V(max)
0s        13.96nV    450.5nV    8.038nV
128.4ns   410.1uV    137.5uV    71.37mV
253.4ns   93.62mV    5.657mV    586.9mV
342.3ns   259mV      35.9mV     949.9mV
464.5ns   513.3mV    121mV      1.308V
627.4ns   811.5mV    271.1mV    1.563V
831ns     1.068V     458.1mV    1.707V
1.192us   1.286V     709mV      1.807V
1.799us   1.407V     906mV      1.854V
4us       1.472V     1.029V     1.871V
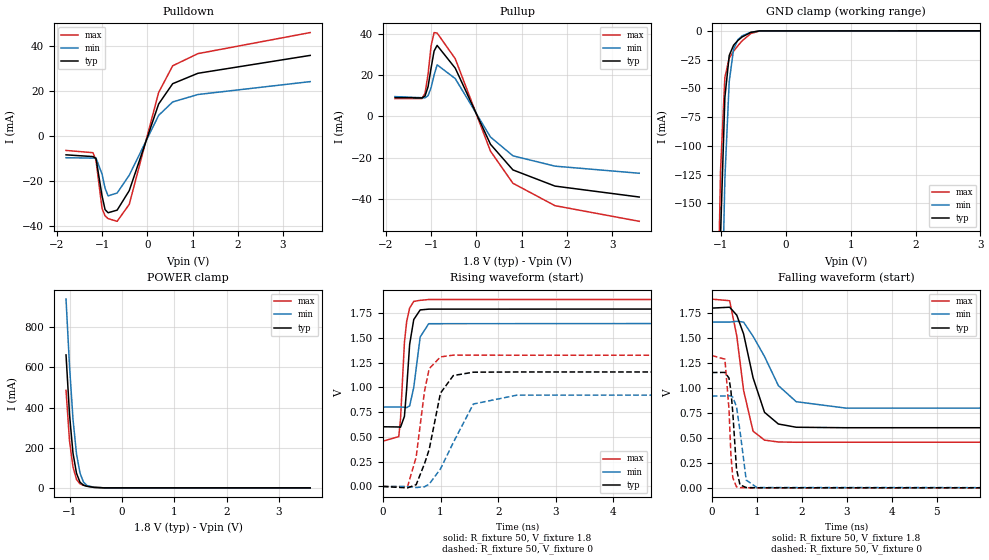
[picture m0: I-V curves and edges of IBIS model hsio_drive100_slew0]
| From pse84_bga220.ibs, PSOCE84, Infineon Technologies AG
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[Model] hsio_drive100_slew0
Model_type I/O
Enable   Active-High
Vinl  =  0.54
Vinh  =  1.26
Vmeas =  0.9
Cref  =  15pF
| Capacitance   typ   min   max
C_comp   1.183861e-12   1.145095e-12   1.230403e-12
| Variables   typ   min   max
[GND Clamp Reference]   0   0   0
[POWER Clamp Reference]   1.8   1.66   1.89
[Pulldown Reference]   0   0   0
[Pullup Reference]   1.8   1.66   1.89
[Temperature Range]   25   125   -40
[Voltage Range]   1.8   1.66   1.89
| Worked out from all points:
|   slope of the pulldown table from 0 to 0.27 V, typ, clamps not added: 17.8 ohm
|   slope of the pullup table from 0 to 0.27 V, typ, clamps not added: 22.5 ohm
|   GND clamp passes 1 mA (typ) near -0.51 V on its own axis
|   POWER clamp passes 1 mA (typ) near -0.47 V on its own axis
|   falling waveform, R_fixture 50, V_fixture 1.8: 20-80 % time 391ps typ, 583ps min, 270ps max; typ from 1.8 V to 0.602 V
|   falling waveform, R_fixture 50, V_fixture 0: 20-80 % time 104ps typ, 141ps min, 82.3ps max; typ from 1.16 V to 0 V
|   rising waveform, R_fixture 50, V_fixture 1.8: 20-80 % time 94.4ps typ, 109ps min, 86.5ps max; typ from 0.602 V to 1.8 V
|   rising waveform, R_fixture 50, V_fixture 0: 20-80 % time 266ps typ, 418ps min, 189ps max; typ from 0 V to 1.16 V
[GND Clamp]
| Voltage   I(typ)   I(min)   I(max)
-1.137V   -688mA     -831.1mA   -596.4mA
-1.07V    -398.5mA   -545.5mA   -312.5mA
-1.003V   -176.8mA   -300mA     -120.9mA
-936.6mV  -57.93mA   -128.6mA   -40.51mA
-869.7mV  -21.44mA   -44.12mA   -23.78mA
-802.8mV  -12.54mA   -16.03mA   -17.79mA
-735.9mV  -8.37mA    -7.69mA    -12.93mA
-669mV    -5.28mA    -4.356mA   -8.606mA
-535.2mV  -1.316mA   -1.208mA   -2.332mA
-401.4mV  -73.56uA   -132.2uA   -119.3uA
3.6V      0A         0A         0A
[POWER Clamp]
| Voltage   I(typ)   I(min)   I(max)
-1.07V    662.2mA    940mA      485.7mA
-1.003V   363.7mA    605.6mA    233mA
-936.6mV  172.7mA    341mA      103.9mA
-869.7mV  72.74mA    168.6mA    41.65mA
-802.8mV  28.31mA    73.56mA    19.99mA
-735.9mV  13.11mA    28.55mA    13.36mA
-669mV    7.76mA     11.5mA     8.963mA
-535.2mV  2.357mA    2.863mA    2.668mA
-334.5mV  34.33uA    127.4uA    15.59uA
3.6V      0A         0A         0A
[Pulldown]
| Voltage   I(typ)   I(min)   I(max)
-1.8V     -8.273mA   -9.546mA   -6.313mA
-1.204V   -9.042mA   -9.718mA   -7.313mA
-1.137V   -9.896mA   -9.717mA   -10.71mA
-1.003V   -26.52mA   -16.83mA   -32.08mA
-936.6mV  -32.58mA   -23.08mA   -35.3mA
-869.7mV  -33.95mA   -26.47mA   -36.57mA
-669mV    -32.79mA   -25.19mA   -37.75mA
-401.4mV  -24.12mA   -17.29mA   -30.21mA
248.3mV   14.29mA    9.245mA    19.39mA
558.6mV   23.29mA    15.2mA     31.23mA
1.117V    27.91mA    18.49mA    36.62mA
3.6V      35.84mA    24.21mA    45.97mA
[Pullup]
| Voltage   I(typ)   I(min)   I(max)
-1.8V     9.249mA    9.655mA    8.684mA
-1.204V   8.988mA    9.128mA    8.718mA
-1.137V   9.935mA    9.053mA    11.31mA
-1.07V    14.47mA    10.11mA    20.5mA
-1.003V   23.56mA    14.04mA    34.37mA
-936.6mV  31.85mA    20.11mA    40.84mA
-869.7mV  34.6mA     25.14mA    40.62mA
-468.3mV  23.5mA     18.41mA    28.09mA
310.3mV   -13.54mA   -10.01mA   -16.89mA
806.9mV   -26.03mA   -19.17mA   -32.53mA
1.738V    -33.91mA   -24.2mA    -43.44mA
3.6V      -39.23mA   -27.66mA   -51.05mA
[Ramp]
dV/dt_r   0.692748/0.265981n  0.551908/0.418051n  0.794721/0.189118n
dV/dt_f   0.718532/0.390685n  0.515084/0.582745n  0.859882/0.270045n
R_load = 50
[Falling Waveform]
R_fixture = 50
V_fixture = 1.8
V_fixture_min = 1.66
V_fixture_max = 1.89
| Time   V(typ)   V(min)   V(max)
0s        1.8V       1.66V      1.89V
395.4ps   1.809V     1.66V      1.874V
554.4ps   1.729V     1.668V     1.52V
705.5ps   1.542V     1.66V      976.7mV
916.2ps   1.103V     1.518V     568mV
1.171ns   756.5mV    1.316V     478mV
1.479ns   639.5mV    1.024V     459.5mV
1.877ns   607mV      862.6mV    456.7mV
2.987ns   602.1mV    798.4mV    457mV
50ns      602.4mV    801.5mV    456.9mV
[Falling Waveform]
R_fixture = 50
V_fixture = 0
V_fixture_min = 0
V_fixture_max = 0
| Time   V(typ)   V(min)   V(max)
0s        1.155V     919.8mV    1.325V
289.5ps   1.156V     919.8mV    1.289V
380.5ps   1.1V       921.8mV    792.1mV
424.2ps   971.1mV    920.1mV    325.5mV
465.9ps   750.3mV    908.1mV    103.4mV
547.9ps   189mV      812.7mV    10.19mV
625.4ps   30.08mV    570.4mV    2.311mV
764.4ps   3.151mV    77.91mV    1.143mV
1.003ns   988.4uV    3.053mV    430.5uV
50ns      14.72nV    1.082uV    5.349nV
[Rising Waveform]
R_fixture = 50
V_fixture = 1.8
V_fixture_min = 1.66
V_fixture_max = 1.89
| Time   V(typ)   V(min)   V(max)
0s        602.4mV    801.5mV    456.9mV
276.3ps   600.1mV    801.5mV    503mV
306.8ps   598.1mV    801.6mV    681.5mV
374.3ps   707.1mV    799.1mV    1.454V
413ps     986.1mV    795.6mV    1.663V
465.1ps   1.435V     813.1mV    1.8V
536.1ps   1.684V     998.6mV    1.867V
647.5ps   1.781V     1.508V     1.878V
795.1ps   1.789V     1.642V     1.886V
50ns      1.8V       1.66V      1.89V
[Rising Waveform]
R_fixture = 50
V_fixture = 0
V_fixture_min = 0
V_fixture_max = 0
| Time   V(typ)   V(min)   V(max)
0s        14.74nV    1.033uV    5.346nV
427.5ps   -14.15mV   -283uV     -2.851mV
578ps     17.95mV    -11.03mV   297.3mV
722.3ps   229.3mV    -3.088mV   960mV
803.6ps   372.6mV    23.32mV    1.188V
998.8ps   941.1mV    176.5mV    1.307V
1.222ns   1.119V     443.3mV    1.325V
1.57ns    1.153V     832mV      1.325V
2.329ns   1.155V     921.5mV    1.324V
50ns      1.155V     919.8mV    1.325V
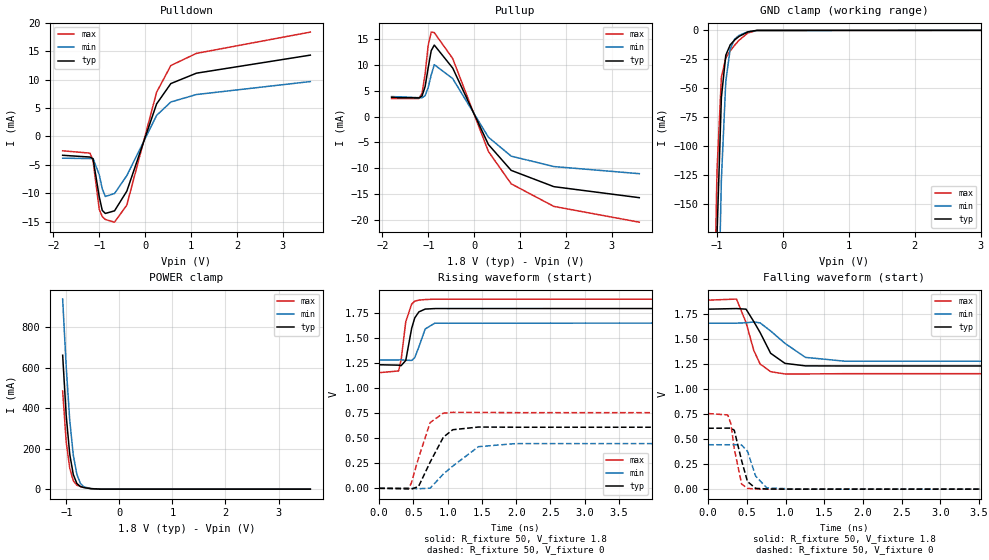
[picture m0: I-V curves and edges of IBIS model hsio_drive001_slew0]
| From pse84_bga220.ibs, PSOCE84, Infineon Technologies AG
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[Model] hsio_drive001_slew0
Model_type I/O
Enable   Active-High
Vinl  =  0.54
Vinh  =  1.26
Vmeas =  0.9
Cref  =  15pF
| Capacitance   typ   min   max
C_comp   1.183861e-12   1.145095e-12   1.230403e-12
| Variables   typ   min   max
[GND Clamp Reference]   0   0   0
[POWER Clamp Reference]   1.8   1.66   1.89
[Pulldown Reference]   0   0   0
[Pullup Reference]   1.8   1.66   1.89
[Temperature Range]   25   125   -40
[Voltage Range]   1.8   1.66   1.89
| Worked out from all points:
|   slope of the pulldown table from 0 to 0.27 V, typ, clamps not added: 44.4 ohm
|   slope of the pullup table from 0 to 0.27 V, typ, clamps not added: 56.4 ohm
|   GND clamp passes 1 mA (typ) near -0.51 V on its own axis
|   POWER clamp passes 1 mA (typ) near -0.47 V on its own axis
|   falling waveform, R_fixture 50, V_fixture 1.8: 20-80 % time 238ps typ, 338ps min, 181ps max; typ from 1.8 V to 1.23 V
|   falling waveform, R_fixture 50, V_fixture 0: 20-80 % time 97.5ps typ, 117ps min, 85.2ps max; typ from 0.609 V to 0 V
|   rising waveform, R_fixture 50, V_fixture 1.8: 20-80 % time 97ps typ, 111ps min, 89.9ps max; typ from 1.23 V to 1.8 V
|   rising waveform, R_fixture 50, V_fixture 0: 20-80 % time 269ps typ, 406ps min, 201ps max; typ from 0 V to 0.609 V
[GND Clamp]
| Voltage   I(typ)   I(min)   I(max)
-1.137V   -688mA     -831.1mA   -596.4mA
-1.07V    -398.5mA   -545.5mA   -312.5mA
-1.003V   -176.8mA   -300mA     -120.9mA
-936.6mV  -57.93mA   -128.6mA   -40.51mA
-869.7mV  -21.44mA   -44.12mA   -23.78mA
-802.8mV  -12.54mA   -16.03mA   -17.79mA
-735.9mV  -8.37mA    -7.69mA    -12.93mA
-669mV    -5.28mA    -4.356mA   -8.606mA
-535.2mV  -1.316mA   -1.208mA   -2.332mA
-401.4mV  -73.56uA   -132.2uA   -119.3uA
3.6V      0A         0A         0A
[POWER Clamp]
| Voltage   I(typ)   I(min)   I(max)
-1.07V    662.2mA    940mA      485.7mA
-1.003V   363.7mA    605.6mA    233mA
-936.6mV  172.7mA    341mA      103.9mA
-869.7mV  72.74mA    168.6mA    41.65mA
-802.8mV  28.31mA    73.56mA    19.99mA
-735.9mV  13.11mA    28.55mA    13.36mA
-669mV    7.76mA     11.5mA     8.963mA
-535.2mV  2.357mA    2.863mA    2.668mA
-334.5mV  34.33uA    127.4uA    15.59uA
3.6V      0A         0A         0A
[Pulldown]
| Voltage   I(typ)   I(min)   I(max)
-1.8V     -3.33mA    -3.841mA   -2.542mA
-1.204V   -3.642mA   -3.911mA   -2.949mA
-1.137V   -3.958mA   -3.911mA   -4.281mA
-1.003V   -10.61mA   -6.735mA   -12.84mA
-936.6mV  -13.04mA   -9.234mA   -14.13mA
-869.7mV  -13.58mA   -10.59mA   -14.64mA
-669mV    -13.12mA   -10.07mA   -15.12mA
-401.4mV  -9.655mA   -6.915mA   -12.11mA
248.3mV   5.722mA    3.696mA    7.78mA
558.6mV   9.308mA    6.066mA    12.49mA
1.117V    11.14mA    7.376mA    14.63mA
3.6V      14.32mA    9.663mA    18.38mA
[Pullup]
| Voltage   I(typ)   I(min)   I(max)
-1.8V     3.714mA    3.873mA    3.489mA
-1.204V   3.608mA    3.661mA    3.501mA
-1.137V   3.98mA     3.631mA    4.529mA
-1.07V    5.792mA    4.046mA    8.21mA
-1.003V   9.427mA    5.614mA    13.76mA
-936.6mV  12.74mA    8.042mA    16.34mA
-869.7mV  13.83mA    10.04mA    16.24mA
-468.3mV  9.384mA    7.347mA    11.22mA
310.3mV   -5.403mA   -3.991mA   -6.746mA
806.9mV   -10.4mA    -7.649mA   -13mA
1.738V    -13.55mA   -9.662mA   -17.37mA
3.6V      -15.68mA   -11.04mA   -20.42mA
[Ramp]
dV/dt_r   0.365478/0.26923n  0.266518/0.405675n  0.453856/0.200984n
dV/dt_f   0.339634/0.238269n  0.226566/0.338036n  0.440881/0.181353n
R_load = 50
[Falling Waveform]
R_fixture = 50
V_fixture = 1.8
V_fixture_min = 1.66
V_fixture_max = 1.89
| Time   V(typ)   V(min)   V(max)
0s        1.8V       1.66V      1.89V
365.9ps   1.806V     1.66V      1.901V
489.2ps   1.8V       1.664V     1.666V
588.8ps   1.676V     1.672V     1.388V
670.3ps   1.567V     1.663V     1.252V
806.6ps   1.359V     1.582V     1.175V
992ps     1.258V     1.458V     1.152V
1.256ns   1.233V     1.318V     1.152V
1.76ns    1.232V     1.28V      1.155V
50ns      1.234V     1.282V     1.155V
[Falling Waveform]
R_fixture = 50
V_fixture = 0
V_fixture_min = 0
V_fixture_max = 0
| Time   V(typ)   V(min)   V(max)
0s        609.1mV    444.2mV    756.4mV
252.7ps   610.3mV    444.2mV    742.2mV
293.4ps   610.7mV    444.2mV    653.5mV
336.9ps   588.9mV    445mV      402.9mV
432.6ps   283.2mV    440.9mV    50.46mV
507.5ps   76.44mV    378.8mV    8.161mV
613.3ps   8.192mV    129.9mV    1.184mV
759.1ps   1.414mV    11.5mV     332.1uV
1.174ns   127.2uV    520.1uV    122.7uV
50ns      27.17nV    1.829uV    10.41nV
[Rising Waveform]
R_fixture = 50
V_fixture = 1.8
V_fixture_min = 1.66
V_fixture_max = 1.89
| Time   V(typ)   V(min)   V(max)
0s        1.234V     1.282V     1.155V
282.4ps   1.23V      1.282V     1.172V
320.1ps   1.225V     1.283V     1.283V
387.6ps   1.277V     1.279V     1.664V
474ps     1.599V     1.277V     1.84V
518.9ps   1.702V     1.305V     1.869V
579.3ps   1.762V     1.413V     1.88V
671.2ps   1.79V      1.591V     1.885V
810.4ps   1.795V     1.649V     1.889V
50ns      1.8V       1.66V      1.89V
[Rising Waveform]
R_fixture = 50
V_fixture = 0
V_fixture_min = 0
V_fixture_max = 0
| Time   V(typ)   V(min)   V(max)
0s        27.23nV    1.749uV    10.42nV
431.9ps   -6.488mV   98.18uV    2.422mV
466.4ps   -8.515mV   -409.1uV   48.04mV
574.1ps   17.96mV    -4.351mV   302.3mV
743.9ps   261.7mV    1.463mV    657.3mV
937.1ps   511.2mV    143.2mV    750.7mV
1.074ns   585.2mV    221.8mV    758.7mV
1.451ns   612mV      416.1mV    757.4mV
1.99ns    610mV      446.4mV    756.1mV
50ns      609.1mV    444.2mV    756.4mV
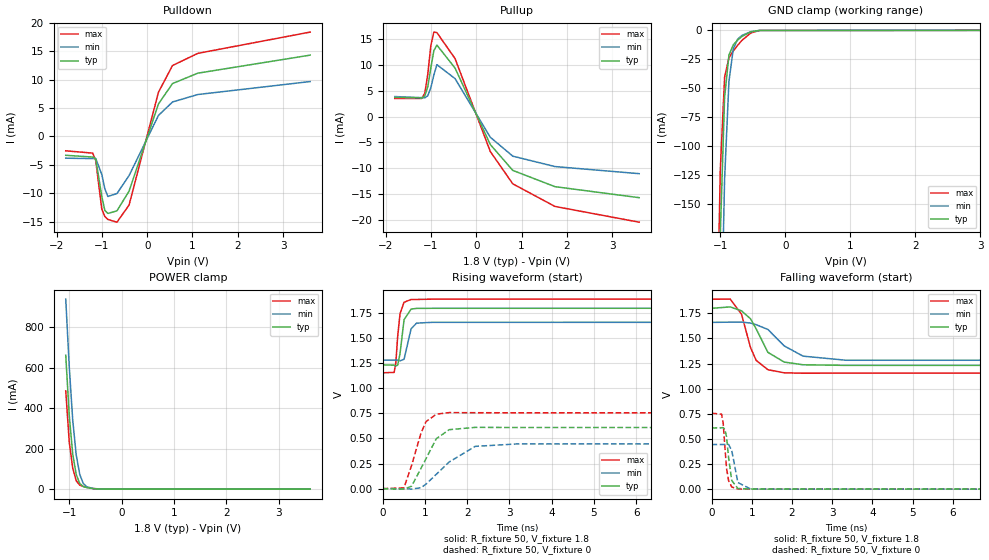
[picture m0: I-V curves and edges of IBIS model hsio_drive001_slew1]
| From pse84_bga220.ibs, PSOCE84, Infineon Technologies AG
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[Model] hsio_drive001_slew1
Model_type I/O
Enable   Active-High
Vinl  =  0.54
Vinh  =  1.26
Vmeas =  0.9
Cref  =  15pF
| Capacitance   typ   min   max
C_comp   1.183861e-12   1.145095e-12   1.230403e-12
| Variables   typ   min   max
[GND Clamp Reference]   0   0   0
[POWER Clamp Reference]   1.8   1.66   1.89
[Pulldown Reference]   0   0   0
[Pullup Reference]   1.8   1.66   1.89
[Temperature Range]   25   125   -40
[Voltage Range]   1.8   1.66   1.89
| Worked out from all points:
|   slope of the pulldown table from 0 to 0.27 V, typ, clamps not added: 44.4 ohm
|   slope of the pullup table from 0 to 0.27 V, typ, clamps not added: 56.4 ohm
|   GND clamp passes 1 mA (typ) near -0.51 V on its own axis
|   POWER clamp passes 1 mA (typ) near -0.47 V on its own axis
|   falling waveform, R_fixture 50, V_fixture 1.8: 20-80 % time 438ps typ, 618ps min, 336ps max; typ from 1.8 V to 1.23 V
|   falling waveform, R_fixture 50, V_fixture 0: 20-80 % time 97.9ps typ, 116ps min, 89.3ps max; typ from 0.609 V to 0 V
|   rising waveform, R_fixture 50, V_fixture 1.8: 20-80 % time 96.5ps typ, 109ps min, 89.6ps max; typ from 1.23 V to 1.8 V
|   rising waveform, R_fixture 50, V_fixture 0: 20-80 % time 445ps typ, 688ps min, 325ps max; typ from 0 V to 0.609 V
[GND Clamp]
| Voltage   I(typ)   I(min)   I(max)
-1.137V   -688mA     -831.1mA   -596.4mA
-1.07V    -398.5mA   -545.5mA   -312.5mA
-1.003V   -176.8mA   -300mA     -120.9mA
-936.6mV  -57.93mA   -128.6mA   -40.51mA
-869.7mV  -21.44mA   -44.12mA   -23.78mA
-802.8mV  -12.54mA   -16.03mA   -17.79mA
-735.9mV  -8.37mA    -7.69mA    -12.93mA
-669mV    -5.28mA    -4.356mA   -8.606mA
-535.2mV  -1.316mA   -1.208mA   -2.332mA
-401.4mV  -73.56uA   -132.2uA   -119.3uA
3.6V      0A         0A         0A
[POWER Clamp]
| Voltage   I(typ)   I(min)   I(max)
-1.07V    662.2mA    940mA      485.7mA
-1.003V   363.7mA    605.6mA    233mA
-936.6mV  172.7mA    341mA      103.9mA
-869.7mV  72.74mA    168.6mA    41.65mA
-802.8mV  28.31mA    73.56mA    19.99mA
-735.9mV  13.11mA    28.55mA    13.36mA
-669mV    7.76mA     11.5mA     8.963mA
-535.2mV  2.357mA    2.863mA    2.668mA
-334.5mV  34.33uA    127.4uA    15.59uA
3.6V      0A         0A         0A
[Pulldown]
| Voltage   I(typ)   I(min)   I(max)
-1.8V     -3.33mA    -3.841mA   -2.542mA
-1.204V   -3.642mA   -3.911mA   -2.949mA
-1.137V   -3.958mA   -3.911mA   -4.281mA
-1.003V   -10.61mA   -6.735mA   -12.84mA
-936.6mV  -13.04mA   -9.234mA   -14.13mA
-869.7mV  -13.58mA   -10.59mA   -14.64mA
-669mV    -13.12mA   -10.07mA   -15.12mA
-401.4mV  -9.655mA   -6.915mA   -12.11mA
248.3mV   5.722mA    3.696mA    7.78mA
558.6mV   9.308mA    6.066mA    12.49mA
1.117V    11.14mA    7.376mA    14.63mA
3.6V      14.32mA    9.663mA    18.38mA
[Pullup]
| Voltage   I(typ)   I(min)   I(max)
-1.8V     3.714mA    3.873mA    3.489mA
-1.204V   3.608mA    3.661mA    3.501mA
-1.137V   3.98mA     3.631mA    4.529mA
-1.07V    5.792mA    4.046mA    8.21mA
-1.003V   9.427mA    5.614mA    13.76mA
-936.6mV  12.74mA    8.042mA    16.34mA
-869.7mV  13.83mA    10.04mA    16.24mA
-468.3mV  9.384mA    7.347mA    11.22mA
310.3mV   -5.403mA   -3.991mA   -6.746mA
806.9mV   -10.4mA    -7.649mA   -13mA
1.738V    -13.55mA   -9.662mA   -17.37mA
3.6V      -15.68mA   -11.04mA   -20.42mA
[Ramp]
dV/dt_r   0.365478/0.444754n  0.266515/0.6877n  0.453856/0.324984n
dV/dt_f   0.339634/0.438009n  0.226565/0.618394n  0.440881/0.33584n
R_load = 50
[Falling Waveform]
R_fixture = 50
V_fixture = 1.8
V_fixture_min = 1.66
V_fixture_max = 1.89
| Time   V(typ)   V(min)   V(max)
0s        1.8V       1.66V      1.89V
463.4ps   1.814V     1.662V     1.892V
744.6ps   1.775V     1.663V     1.742V
968.5ps   1.696V     1.653V     1.41V
1.109ns   1.596V     1.637V     1.282V
1.4ns     1.362V     1.59V      1.189V
1.806ns   1.265V     1.426V     1.158V
2.275ns   1.238V     1.324V     1.154V
3.344ns   1.232V     1.283V     1.155V
50ns      1.234V     1.282V     1.155V
[Falling Waveform]
R_fixture = 50
V_fixture = 0
V_fixture_min = 0
V_fixture_max = 0
| Time   V(typ)   V(min)   V(max)
0s        609.1mV    444.2mV    756.4mV
249.3ps   610.6mV    444.2mV    746mV
289.6ps   612.7mV    444.1mV    657.2mV
329.5ps   596.8mV    445mV      428.3mV
372.3ps   522.2mV    447.2mV    206.8mV
423.3ps   313.9mV    445.1mV    85.4mV
502ps     86.45mV    385.3mV    21.23mV
654.3ps   6.636mV    65.92mV    1.653mV
977.5ps   900.8uV    599.1uV    951.5uV
50ns      27.19nV    1.752uV    10.44nV
[Rising Waveform]
R_fixture = 50
V_fixture = 1.8
V_fixture_min = 1.66
V_fixture_max = 1.89
| Time   V(typ)   V(min)   V(max)
0s        1.234V     1.282V     1.155V
275.1ps   1.231V     1.282V     1.159V
315ps     1.222V     1.282V     1.26V
358.1ps   1.232V     1.281V     1.519V
413.8ps   1.347V     1.274V     1.744V
508.8ps   1.684V     1.29V      1.858V
675.5ps   1.79V      1.594V     1.886V
805ps     1.797V     1.65V      1.886V
1.167ns   1.798V     1.658V     1.889V
50ns      1.8V       1.66V      1.89V
[Rising Waveform]
R_fixture = 50
V_fixture = 0
V_fixture_min = 0
V_fixture_max = 0
| Time   V(typ)   V(min)   V(max)
0s        27.23nV    1.749uV    10.42nV
505.4ps   -5.117mV   -1.415mV   7.645mV
686.3ps   24.27mV    -3.682mV   230.9mV
908.5ps   201.8mV    9.055mV    552.4mV
1.028ns   298.6mV    45.1mV     668mV
1.27ns    497.3mV    142.4mV    742.3mV
1.576ns   588mV      265.6mV    758.2mV
2.191ns   610.9mV    421.5mV    757mV
3.18ns    609.5mV    445.8mV    756.2mV
50ns      609.1mV    444.2mV    756.4mV
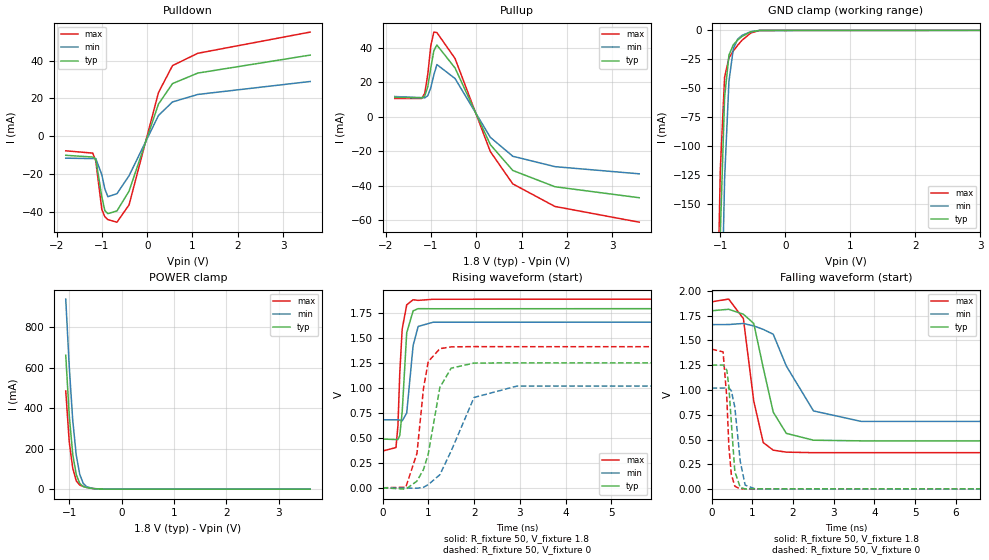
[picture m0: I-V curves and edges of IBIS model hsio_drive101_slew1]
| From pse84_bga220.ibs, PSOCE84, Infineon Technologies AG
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[Model] hsio_drive101_slew1
Model_type I/O
Enable   Active-High
Vinl  =  0.54
Vinh  =  1.26
Vmeas =  0.9
Cref  =  15pF
| Capacitance   typ   min   max
C_comp   1.183861e-12   1.145095e-12   1.230403e-12
| Variables   typ   min   max
[GND Clamp Reference]   0   0   0
[POWER Clamp Reference]   1.8   1.66   1.89
[Pulldown Reference]   0   0   0
[Pullup Reference]   1.8   1.66   1.89
[Temperature Range]   25   125   -40
[Voltage Range]   1.8   1.66   1.89
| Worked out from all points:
|   slope of the pulldown table from 0 to 0.27 V, typ, clamps not added: 14.9 ohm
|   slope of the pullup table from 0 to 0.27 V, typ, clamps not added: 18.8 ohm
|   GND clamp passes 1 mA (typ) near -0.51 V on its own axis
|   POWER clamp passes 1 mA (typ) near -0.47 V on its own axis
|   falling waveform, R_fixture 50, V_fixture 1.8: 20-80 % time 407ps typ, 637ps min, 273ps max; typ from 1.8 V to 0.488 V
|   falling waveform, R_fixture 50, V_fixture 0: 20-80 % time 119ps typ, 151ps min, 103ps max; typ from 1.25 V to 0 V
|   rising waveform, R_fixture 50, V_fixture 1.8: 20-80 % time 96.8ps typ, 114ps min, 87.6ps max; typ from 0.488 V to 1.8 V
|   rising waveform, R_fixture 50, V_fixture 0: 20-80 % time 293ps typ, 483ps min, 205ps max; typ from 0 V to 1.25 V
[GND Clamp]
| Voltage   I(typ)   I(min)   I(max)
-1.137V   -688mA     -831.1mA   -596.4mA
-1.07V    -398.5mA   -545.5mA   -312.5mA
-1.003V   -176.8mA   -300mA     -120.9mA
-936.6mV  -57.93mA   -128.6mA   -40.51mA
-869.7mV  -21.44mA   -44.12mA   -23.78mA
-802.8mV  -12.54mA   -16.03mA   -17.79mA
-735.9mV  -8.37mA    -7.69mA    -12.93mA
-669mV    -5.28mA    -4.356mA   -8.606mA
-535.2mV  -1.316mA   -1.208mA   -2.332mA
-401.4mV  -73.56uA   -132.2uA   -119.3uA
3.6V      0A         0A         0A
[POWER Clamp]
| Voltage   I(typ)   I(min)   I(max)
-1.07V    662.2mA    940mA      485.7mA
-1.003V   363.7mA    605.6mA    233mA
-936.6mV  172.7mA    341mA      103.9mA
-869.7mV  72.74mA    168.6mA    41.65mA
-802.8mV  28.31mA    73.56mA    19.99mA
-735.9mV  13.11mA    28.55mA    13.36mA
-669mV    7.76mA     11.5mA     8.963mA
-535.2mV  2.357mA    2.863mA    2.668mA
-334.5mV  34.33uA    127.4uA    15.59uA
3.6V      0A         0A         0A
[Pulldown]
| Voltage   I(typ)   I(min)   I(max)
-1.8V     -9.926mA   -11.45mA   -7.576mA
-1.204V   -10.85mA   -11.66mA   -8.775mA
-1.137V   -11.86mA   -11.66mA   -12.84mA
-1.003V   -31.78mA   -20.17mA   -38.45mA
-936.6mV  -39.04mA   -27.66mA   -42.31mA
-869.7mV  -40.68mA   -31.72mA   -43.81mA
-669mV    -39.25mA   -30.17mA   -45.18mA
-401.4mV  -28.82mA   -20.69mA   -36.06mA
248.3mV   17.05mA    11.05mA    23.1mA
558.6mV   27.85mA    18.19mA    37.33mA
1.117V    33.39mA    22.13mA    43.82mA
3.6V      42.87mA    28.96mA    54.99mA
[Pullup]
| Voltage   I(typ)   I(min)   I(max)
-1.8V     11.14mA    11.62mA    10.46mA
-1.204V   10.82mA    10.99mA    10.49mA
-1.137V   11.94mA    10.9mA     13.58mA
-1.07V    17.38mA    12.15mA    24.62mA
-1.003V   28.28mA    16.86mA    41.25mA
-936.6mV  38.22mA    24.15mA    48.98mA
-869.7mV  41.5mA     30.16mA    48.7mA
-468.3mV  28.17mA    22.07mA    33.67mA
310.3mV   -16.22mA   -11.99mA   -20.24mA
806.9mV   -31.21mA   -22.98mA   -38.99mA
1.738V    -40.65mA   -29.01mA   -52.08mA
3.6V      -47.02mA   -33.16mA   -61.2mA
[Ramp]
dV/dt_r   0.750667/0.292676n  0.611812/0.483201n  0.848063/0.204931n
dV/dt_f   0.787305/0.407465n  0.587327/0.637122n  0.913048/0.272979n
R_load = 50
[Falling Waveform]
R_fixture = 50
V_fixture = 1.8
V_fixture_min = 1.66
V_fixture_max = 1.89
| Time   V(typ)   V(min)   V(max)
0s        1.8V       1.66V      1.89V
420.7ps   1.815V     1.661V     1.918V
780.9ps   1.765V     1.672V     1.721V
1.036ns   1.672V     1.647V     888.5mV
1.269ns   1.224V     1.612V     469.9mV
1.514ns   777.4mV    1.563V     393.5mV
1.835ns   563.1mV    1.243V     373.5mV
2.502ns   493.9mV    789.6mV    368.1mV
3.672ns   487.4mV    683.7mV    368.3mV
50ns      487.8mV    681.1mV    368.3mV
[Falling Waveform]
R_fixture = 50
V_fixture = 0
V_fixture_min = 0
V_fixture_max = 0
| Time   V(typ)   V(min)   V(max)
0s        1.251V     1.02V      1.413V
282.2ps   1.253V     1.02V      1.385V
374.7ps   1.201V     1.022V     917mV
424.8ps   1.034V     1.021V     429.4mV
484.9ps   674.5mV    994.4mV    150.7mV
570.8ps   178.1mV    827.5mV    30.12mV
704.2ps   17.24mV    280mV      2.395mV
825.2ps   2.347mV    40.31mV    4.196mV
1.087ns   3.733mV    234.5uV    1.33mV
50ns      12.83nV    924.6nV    4.679nV
[Rising Waveform]
R_fixture = 50
V_fixture = 1.8
V_fixture_min = 1.66
V_fixture_max = 1.89
| Time   V(typ)   V(min)   V(max)
0s        487.8mV    681.1mV    368.3mV
293.4ps   483.1mV    681.1mV    402.8mV
336.4ps   483.5mV    681.1mV    624.7mV
376ps     523mV      677.8mV    1.145V
429.2ps   759.9mV    670.5mV    1.59V
527.9ps   1.552V     748.7mV    1.832V
668ps     1.772V     1.425V     1.883V
778.4ps   1.794V     1.616V     1.877V
1.105ns   1.793V     1.658V     1.888V
50ns      1.8V       1.66V      1.89V
[Rising Waveform]
R_fixture = 50
V_fixture = 0
V_fixture_min = 0
V_fixture_max = 0
| Time   V(typ)   V(min)   V(max)
0s        12.85nV    911.9nV    4.632nV
507ps     -13.89mV   -2.385mV   5.014mV
751.9ps   66.9mV     -4.578mV   343.8mV
894.6ps   183.1mV    5.199mV    995.4mV
998.2ps   337.3mV    31.92mV    1.264V
1.252ns   1.005V     130.5mV    1.393V
1.499ns   1.198V     368.8mV    1.411V
1.999ns   1.249V     904.3mV    1.414V
2.937ns   1.251V     1.019V     1.413V
50ns      1.251V     1.02V      1.413V
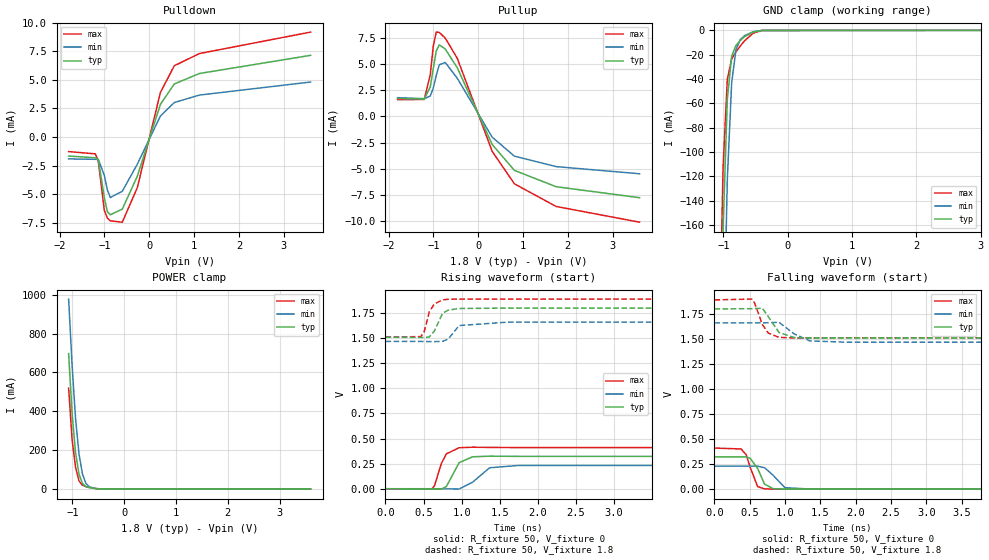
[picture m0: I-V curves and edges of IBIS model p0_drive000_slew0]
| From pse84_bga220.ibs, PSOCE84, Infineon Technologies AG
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| pad_0
[Model] p0_drive000_slew0
Model_type I/O
Polarity  Inverting
Enable   Active-High
Vinl  =  0.54
Vinh  =  1.26
Vmeas =  0.9
Cref  =  15pF
| Capacitance   typ   min   max
C_comp   1.253838e-12   1.215159e-12   1.300411e-12
| Variables   typ   min   max
[GND Clamp Reference]   0   0   0
[POWER Clamp Reference]   1.8   1.66   1.89
[Pulldown Reference]   0   0   0
[Pullup Reference]   1.8   1.66   1.89
[Temperature Range]   25   125   -40
[Voltage Range]   1.8   1.66   1.89
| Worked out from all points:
|   slope of the pulldown table from 0 to 0.27 V, typ, clamps not added: 88.8 ohm
|   slope of the pullup table from 0 to 0.27 V, typ, clamps not added: 114 ohm
|   GND clamp passes 1 mA (typ) near -0.51 V on its own axis
|   POWER clamp passes 1 mA (typ) near -0.47 V on its own axis
|   rising waveform, R_fixture 50, V_fixture 0: 20-80 % time 134ps typ, 172ps min, 115ps max; typ from 0 V to 0.322 V
|   rising waveform, R_fixture 50, V_fixture 1.8: 20-80 % time 102ps typ, 116ps min, 95ps max; typ from 1.51 V to 1.8 V
|   falling waveform, R_fixture 50, V_fixture 0: 20-80 % time 119ps typ, 147ps min, 103ps max; typ from 0.322 V to 0 V
|   falling waveform, R_fixture 50, V_fixture 1.8: 20-80 % time 160ps typ, 204ps min, 135ps max; typ from 1.8 V to 1.51 V
[GND Clamp]
| Voltage   I(typ)   I(min)   I(max)
-1.137V   -619.5mA   -754.2mA   -533mA
-1.07V    -361.2mA   -498.1mA   -281.3mA
-1.003V   -163.8mA   -277.7mA   -113mA
-936.6mV  -56.22mA   -122.3mA   -40.06mA
-869.7mV  -21.33mA   -43.3mA    -23.67mA
-802.8mV  -12.5mA    -15.96mA   -17.71mA
-735.9mV  -8.346mA   -7.675mA   -12.88mA
-669mV    -5.267mA   -4.349mA   -8.575mA
-535.2mV  -1.314mA   -1.207mA   -2.328mA
-401.4mV  -73.55uA   -132.2uA   -119.3uA
3.6V      0A         0A         0A
[POWER Clamp]
| Voltage   I(typ)   I(min)   I(max)
-1.07V    696.7mA    977.2mA    518.8mA
-1.003V   390.1mA    637.2mA    255.1mA
-936.6mV  187.1mA    363.9mA    112.4mA
-869.7mV  77.2mA     180.7mA    42.71mA
-802.8mV  28.89mA    77.43mA    19.98mA
-735.9mV  13.12mA    29.18mA    13.35mA
-669mV    7.754mA    11.55mA    8.954mA
-535.2mV  2.356mA    2.862mA    2.667mA
-334.5mV  34.33uA    127.4uA    15.58uA
3.6V      0A         0A         0A
[Pullup]
| Voltage   I(typ)   I(min)   I(max)
-1.8V     1.703mA    1.783mA    1.591mA
-1.204V   1.657mA    1.69mA     1.617mA
-1.07V    2.812mA    1.941mA    3.991mA
-1.003V   4.582mA    2.72mA     6.714mA
-936.6mV  6.243mA    3.907mA    8.04mA
-869.7mV  6.82mA     4.924mA    8.008mA
-735.9mV  6.428mA    5.143mA    7.465mA
-468.3mV  4.64mA     3.64mA     5.541mA
310.3mV   -2.672mA   -1.978mA   -3.329mA
806.9mV   -5.149mA   -3.794mA   -6.429mA
1.738V    -6.707mA   -4.79mA    -8.59mA
3.6V      -7.755mA   -5.471mA   -10.09mA
[Pulldown]
| Voltage   I(typ)   I(min)   I(max)
-1.8V     -1.651mA   -1.903mA   -1.262mA
-1.204V   -1.804mA   -1.937mA   -1.461mA
-1.137V   -1.972mA   -1.937mA   -2.136mA
-1.003V   -5.288mA   -3.351mA   -6.408mA
-936.6mV  -6.503mA   -4.599mA   -7.056mA
-869.7mV  -6.779mA   -5.277mA   -7.31mA
-602.1mV  -6.285mA   -4.725mA   -7.428mA
-267.6mV  -3.417mA   -2.364mA   -4.414mA
248.3mV   2.862mA    1.843mA    3.901mA
558.6mV   4.643mA    3.021mA    6.237mA
1.117V    5.554mA    3.671mA    7.296mA
3.6V      7.143mA    4.812mA    9.172mA
[Ramp]
dV/dt_r   0.193213/0.133714n  0.13784/0.172287n  0.246193/0.115122n
dV/dt_f   0.174157/0.160174n  0.115108/0.203658n  0.22763/0.134852n
R_load = 50
[Rising Waveform]
R_fixture = 50
V_fixture = 0
V_fixture_min = 0
V_fixture_max = 0
| Time   V(typ)   V(min)   V(max)
0s        37.95nV    2.274uV    15.24nV
610ps     -1.938mV   -7.529uV   -2.813mV
643.3ps   -3.965mV   -20.53uV   31.08mV
732.5ps   -4.29mV    -225.9uV   250.8mV
798.8ps   21.73mV    -1.016mV   347.6mV
966.9ps   260.3mV    -2.974mV   408.7mV
1.144ns   318.5mV    65.99mV    413.8mV
1.366ns   324.3mV    209mV      411.6mV
1.746ns   322.5mV    231.9mV    410.2mV
50ns      322mV      229.7mV    410.3mV
[Rising Waveform]
R_fixture = 50
V_fixture = 1.8
V_fixture_min = 1.66
V_fixture_max = 1.89
| Time   V(typ)   V(min)   V(max)
0s        1.51V      1.468V     1.511V
464.3ps   1.508V     1.468V     1.516V
507.4ps   1.507V     1.467V     1.564V
574.4ps   1.512V     1.466V     1.761V
640.2ps   1.57V      1.466V     1.841V
749ps     1.748V     1.469V     1.882V
823ps     1.78V      1.492V     1.888V
966.5ps   1.796V     1.626V     1.89V
1.602ns   1.8V       1.66V      1.89V
50ns      1.8V       1.66V      1.89V
[Falling Waveform]
R_fixture = 50
V_fixture = 0
V_fixture_min = 0
V_fixture_max = 0
| Time   V(typ)   V(min)   V(max)
0s        322mV      229.7mV    410.3mV
376.4ps   323mV      229.7mV    401.4mV
449.6ps   321.4mV    229.9mV    343.4mV
505.3ps   308.8mV    230.6mV    220mV
611.9ps   205.9mV    229.4mV    24.67mV
709.1ps   50.64mV    213.9mV    3.37mV
829.4ps   5.314mV    139.6mV    629.6uV
997ps     674.7uV    14.92mV    113.4uV
1.383ns   52.5uV     287.7uV    67.35uV
50ns      37.86nV    2.303uV    15.21nV
[Falling Waveform]
R_fixture = 50
V_fixture = 1.8
V_fixture_min = 1.66
V_fixture_max = 1.89
| Time   V(typ)   V(min)   V(max)
0s        1.8V       1.66V      1.89V
529.7ps   1.802V     1.66V      1.898V
569.1ps   1.803V     1.66V      1.857V
679.2ps   1.806V     1.661V     1.643V
762.7ps   1.722V     1.662V     1.558V
914.1ps   1.564V     1.666V     1.516V
1.129ns   1.514V     1.55V      1.509V
1.352ns   1.509V     1.48V      1.51V
1.884ns   1.51V      1.467V     1.511V
50ns      1.51V      1.468V     1.511V
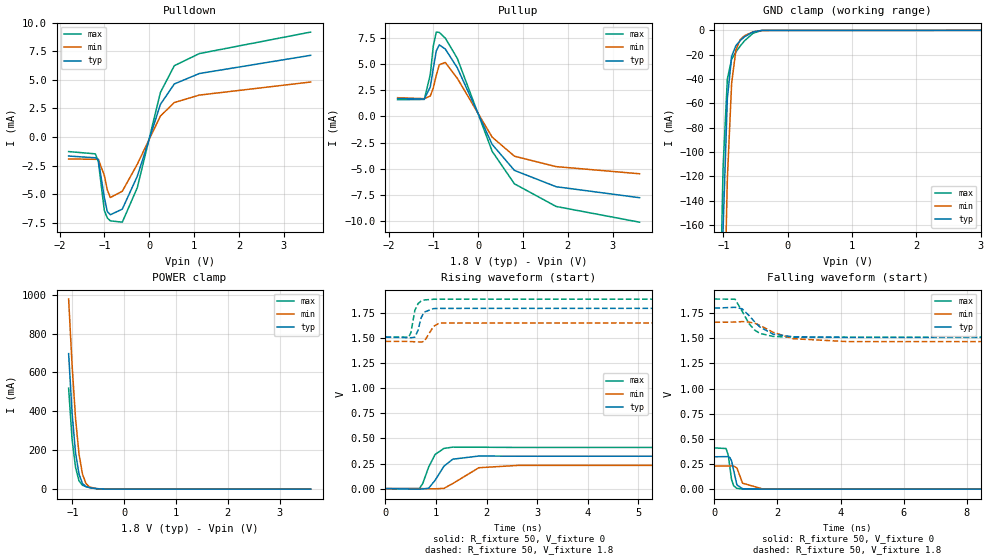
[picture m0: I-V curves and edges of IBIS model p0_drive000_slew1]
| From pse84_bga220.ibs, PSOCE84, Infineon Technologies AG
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[Model] p0_drive000_slew1
Model_type I/O
Polarity  Inverting
Enable   Active-High
Vinl  =  0.54
Vinh  =  1.26
Vmeas =  0.9
Cref  =  15pF
| Capacitance   typ   min   max
C_comp   1.253838e-12   1.215159e-12   1.300411e-12
| Variables   typ   min   max
[GND Clamp Reference]   0   0   0
[POWER Clamp Reference]   1.8   1.66   1.89
[Pulldown Reference]   0   0   0
[Pullup Reference]   1.8   1.66   1.89
[Temperature Range]   25   125   -40
[Voltage Range]   1.8   1.66   1.89
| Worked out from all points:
|   slope of the pulldown table from 0 to 0.27 V, typ, clamps not added: 88.8 ohm
|   slope of the pullup table from 0 to 0.27 V, typ, clamps not added: 114 ohm
|   GND clamp passes 1 mA (typ) near -0.51 V on its own axis
|   POWER clamp passes 1 mA (typ) near -0.47 V on its own axis
|   rising waveform, R_fixture 50, V_fixture 0: 20-80 % time 263ps typ, 383ps min, 204ps max; typ from 0 V to 0.322 V
|   rising waveform, R_fixture 50, V_fixture 1.8: 20-80 % time 99.1ps typ, 113ps min, 93ps max; typ from 1.51 V to 1.8 V
|   falling waveform, R_fixture 50, V_fixture 0: 20-80 % time 121ps typ, 147ps min, 109ps max; typ from 0.322 V to 0 V
|   falling waveform, R_fixture 50, V_fixture 1.8: 20-80 % time 596ps typ, 841ps min, 452ps max; typ from 1.8 V to 1.51 V
[GND Clamp]
| Voltage   I(typ)   I(min)   I(max)
-1.137V   -619.5mA   -754.2mA   -533mA
-1.07V    -361.2mA   -498.1mA   -281.3mA
-1.003V   -163.8mA   -277.7mA   -113mA
-936.6mV  -56.22mA   -122.3mA   -40.06mA
-869.7mV  -21.33mA   -43.3mA    -23.67mA
-802.8mV  -12.5mA    -15.96mA   -17.71mA
-735.9mV  -8.346mA   -7.675mA   -12.88mA
-669mV    -5.267mA   -4.349mA   -8.575mA
-535.2mV  -1.314mA   -1.207mA   -2.328mA
-401.4mV  -73.55uA   -132.2uA   -119.3uA
3.6V      0A         0A         0A
[POWER Clamp]
| Voltage   I(typ)   I(min)   I(max)
-1.07V    696.7mA    977.2mA    518.8mA
-1.003V   390.1mA    637.2mA    255.1mA
-936.6mV  187.1mA    363.9mA    112.4mA
-869.7mV  77.2mA     180.7mA    42.71mA
-802.8mV  28.89mA    77.43mA    19.98mA
-735.9mV  13.12mA    29.18mA    13.35mA
-669mV    7.754mA    11.55mA    8.954mA
-535.2mV  2.356mA    2.862mA    2.667mA
-334.5mV  34.33uA    127.4uA    15.58uA
3.6V      0A         0A         0A
[Pullup]
| Voltage   I(typ)   I(min)   I(max)
-1.8V     1.703mA    1.783mA    1.591mA
-1.204V   1.657mA    1.69mA     1.617mA
-1.07V    2.812mA    1.941mA    3.991mA
-1.003V   4.582mA    2.72mA     6.714mA
-936.6mV  6.243mA    3.907mA    8.04mA
-869.7mV  6.82mA     4.924mA    8.008mA
-735.9mV  6.428mA    5.143mA    7.465mA
-468.3mV  4.64mA     3.64mA     5.541mA
310.3mV   -2.672mA   -1.978mA   -3.329mA
806.9mV   -5.149mA   -3.794mA   -6.429mA
1.738V    -6.707mA   -4.79mA    -8.59mA
3.6V      -7.755mA   -5.471mA   -10.09mA
[Pulldown]
| Voltage   I(typ)   I(min)   I(max)
-1.8V     -1.651mA   -1.903mA   -1.262mA
-1.204V   -1.804mA   -1.937mA   -1.461mA
-1.137V   -1.972mA   -1.937mA   -2.136mA
-1.003V   -5.288mA   -3.351mA   -6.408mA
-936.6mV  -6.503mA   -4.599mA   -7.056mA
-869.7mV  -6.779mA   -5.277mA   -7.31mA
-602.1mV  -6.285mA   -4.725mA   -7.428mA
-267.6mV  -3.417mA   -2.364mA   -4.414mA
248.3mV   2.862mA    1.843mA    3.901mA
558.6mV   4.643mA    3.021mA    6.237mA
1.117V    5.554mA    3.671mA    7.296mA
3.6V      7.143mA    4.812mA    9.172mA
[Ramp]
dV/dt_r   0.193213/0.262792n  0.137839/0.382699n  0.246193/0.203755n
dV/dt_f   0.174157/0.596512n  0.115108/0.841503n  0.22763/0.451675n
R_load = 50
[Rising Waveform]
R_fixture = 50
V_fixture = 0
V_fixture_min = 0
V_fixture_max = 0
| Time   V(typ)   V(min)   V(max)
0s        37.95nV    2.274uV    15.24nV
670.2ps   -5.725mV   -16.31uV   564uV
737.5ps   -3.254mV   -249.1uV   51.76mV
853.3ps   3.498mV    -2.59mV    214.1mV
982ps     83.28mV    -2.149mV   341mV
1.156ns   223.2mV    2.231mV    400.4mV
1.331ns   293.2mV    50.66mV    413.7mV
1.846ns   324.9mV    208mV      412.6mV
2.632ns   322.7mV    231.7mV    410.2mV
50ns      322mV      229.7mV    410.3mV
[Rising Waveform]
R_fixture = 50
V_fixture = 1.8
V_fixture_min = 1.66
V_fixture_max = 1.89
| Time   V(typ)   V(min)   V(max)
0s        1.51V      1.468V     1.511V
458.2ps   1.505V     1.468V     1.51V
502.6ps   1.504V     1.466V     1.555V
581.6ps   1.51V      1.464V     1.778V
646ps     1.581V     1.463V     1.846V
701.7ps   1.7V       1.462V     1.869V
765ps     1.76V      1.467V     1.881V
950.5ps   1.795V     1.618V     1.888V
1.068ns   1.797V     1.651V     1.889V
50ns      1.8V       1.66V      1.89V
[Falling Waveform]
R_fixture = 50
V_fixture = 0
V_fixture_min = 0
V_fixture_max = 0
| Time   V(typ)   V(min)   V(max)
0s        322mV      229.7mV    410.3mV
368.6ps   323.4mV    229.7mV    403.9mV
438.5ps   323.9mV    229.8mV    338.3mV
490.2ps   313.5mV    230.7mV    217.2mV
542.3ps   281.5mV    231.8mV    97.15mV
609.6ps   186.4mV    230.9mV    33.79mV
712.9ps   42.11mV    210.4mV    7.882mV
893ps     4.284mV    59.46mV    1.058mV
1.55ns    275.3uV    463.9uV    211.2uV
50ns      37.88nV    2.277uV    15.3nV
[Falling Waveform]
R_fixture = 50
V_fixture = 1.8
V_fixture_min = 1.66
V_fixture_max = 1.89
| Time   V(typ)   V(min)   V(max)
0s        1.8V       1.66V      1.89V
653.7ps   1.808V     1.661V     1.889V
879.5ps   1.793V     1.666V     1.769V
1.098ns   1.726V     1.661V     1.645V
1.275ns   1.664V     1.65V      1.582V
1.44ns    1.613V     1.629V     1.549V
1.853ns   1.542V     1.561V     1.519V
2.486ns   1.515V     1.496V     1.51V
4.223ns   1.509V     1.467V     1.51V
50ns      1.51V      1.468V     1.511V
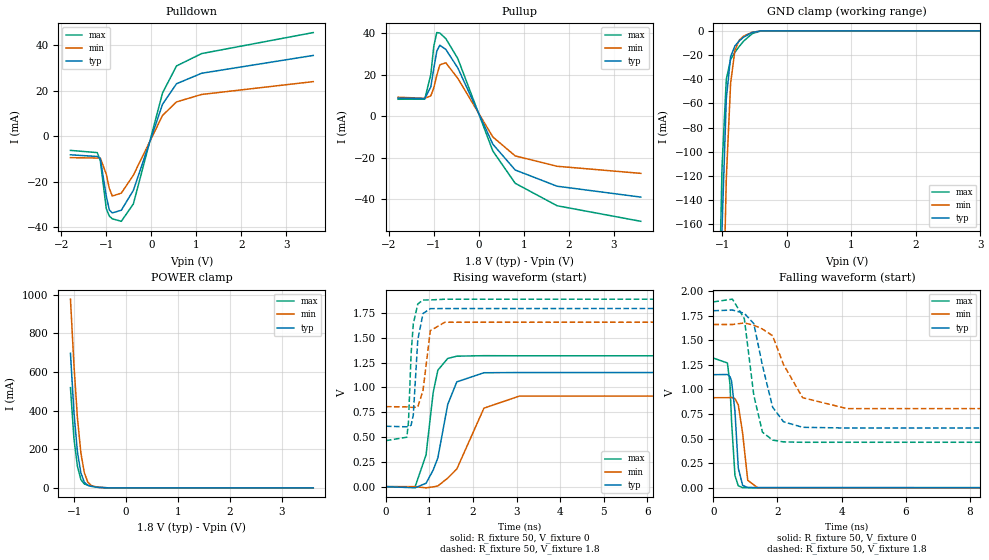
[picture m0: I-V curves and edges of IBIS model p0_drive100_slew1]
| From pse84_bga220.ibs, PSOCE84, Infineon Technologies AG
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[Model] p0_drive100_slew1
Model_type I/O
Polarity  Inverting
Enable   Active-High
Vinl  =  0.54
Vinh  =  1.26
Vmeas =  0.9
Cref  =  15pF
| Capacitance   typ   min   max
C_comp   1.253838e-12   1.215159e-12   1.300411e-12
| Variables   typ   min   max
[GND Clamp Reference]   0   0   0
[POWER Clamp Reference]   1.8   1.66   1.89
[Pulldown Reference]   0   0   0
[Pullup Reference]   1.8   1.66   1.89
[Temperature Range]   25   125   -40
[Voltage Range]   1.8   1.66   1.89
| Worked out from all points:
|   slope of the pulldown table from 0 to 0.27 V, typ, clamps not added: 18 ohm
|   slope of the pullup table from 0 to 0.27 V, typ, clamps not added: 22.7 ohm
|   GND clamp passes 1 mA (typ) near -0.51 V on its own axis
|   POWER clamp passes 1 mA (typ) near -0.47 V on its own axis
|   rising waveform, R_fixture 50, V_fixture 0: 20-80 % time 320ps typ, 513ps min, 228ps max; typ from 0 V to 1.15 V
|   rising waveform, R_fixture 50, V_fixture 1.8: 20-80 % time 100ps typ, 119ps min, 91.8ps max; typ from 0.609 V to 1.8 V
|   falling waveform, R_fixture 50, V_fixture 0: 20-80 % time 130ps typ, 167ps min, 109ps max; typ from 1.15 V to 0 V
|   falling waveform, R_fixture 50, V_fixture 1.8: 20-80 % time 457ps typ, 675ps min, 321ps max; typ from 1.8 V to 0.609 V
[GND Clamp]
| Voltage   I(typ)   I(min)   I(max)
-1.137V   -619.5mA   -754.2mA   -533mA
-1.07V    -361.2mA   -498.1mA   -281.3mA
-1.003V   -163.8mA   -277.7mA   -113mA
-936.6mV  -56.22mA   -122.3mA   -40.06mA
-869.7mV  -21.33mA   -43.3mA    -23.67mA
-802.8mV  -12.5mA    -15.96mA   -17.71mA
-735.9mV  -8.346mA   -7.675mA   -12.88mA
-669mV    -5.267mA   -4.349mA   -8.575mA
-535.2mV  -1.314mA   -1.207mA   -2.328mA
-401.4mV  -73.55uA   -132.2uA   -119.3uA
3.6V      0A         0A         0A
[POWER Clamp]
| Voltage   I(typ)   I(min)   I(max)
-1.07V    696.7mA    977.2mA    518.8mA
-1.003V   390.1mA    637.2mA    255.1mA
-936.6mV  187.1mA    363.9mA    112.4mA
-869.7mV  77.2mA     180.7mA    42.71mA
-802.8mV  28.89mA    77.43mA    19.98mA
-735.9mV  13.12mA    29.18mA    13.35mA
-669mV    7.754mA    11.55mA    8.954mA
-535.2mV  2.356mA    2.862mA    2.667mA
-334.5mV  34.33uA    127.4uA    15.58uA
3.6V      0A         0A         0A
[Pullup]
| Voltage   I(typ)   I(min)   I(max)
-1.8V     8.805mA    9.212mA    8.239mA
-1.204V   8.562mA    8.724mA    8.33mA
-1.07V    14.23mA    9.871mA    20.18mA
-1.003V   23.18mA    13.78mA    33.88mA
-936.6mV  31.45mA    19.77mA    40.37mA
-869.7mV  34.25mA    24.82mA    40.17mA
-735.9mV  32.25mA    25.82mA    37.44mA
-468.3mV  23.28mA    18.27mA    27.79mA
310.3mV   -13.41mA   -9.932mA   -16.7mA
806.9mV   -25.83mA   -19.04mA   -32.23mA
1.738V    -33.64mA   -24.04mA   -43.05mA
3.6V      -38.89mA   -27.45mA   -50.55mA
[Pulldown]
| Voltage   I(typ)   I(min)   I(max)
-1.8V     -8.173mA   -9.432mA   -6.24mA
-1.204V   -8.92mA    -9.594mA   -7.213mA
-1.137V   -9.832mA   -9.593mA   -10.66mA
-1.003V   -26.34mA   -16.71mA   -31.9mA
-936.6mV  -32.38mA   -22.93mA   -35.09mA
-869.7mV  -33.74mA   -26.31mA   -36.33mA
-669mV    -32.54mA   -25.03mA   -37.42mA
-401.4mV  -23.84mA   -17.15mA   -29.79mA
248.3mV   14.08mA    9.152mA    19.04mA
558.6mV   23.07mA    15.08mA    30.91mA
1.117V    27.69mA    18.36mA    36.34mA
3.6V      35.52mA    24.01mA    45.58mA
[Ramp]
dV/dt_r   0.689987/0.319995n  0.549651/0.513004n  0.791643/0.228298n
dV/dt_f   0.714867/0.456912n  0.512304/0.674819n  0.855963/0.321077n
R_load = 50
[Rising Waveform]
R_fixture = 50
V_fixture = 0
V_fixture_min = 0
V_fixture_max = 0
| Time   V(typ)   V(min)   V(max)
0s        14.92nV    1.041uV    5.435nV
670.8ps   -11.85mV   -51.34uV   -2.399mV
922.4ps   34.01mV    -12.4mV    321mV
1.086ns   167.4mV    -2.596mV   949.6mV
1.193ns   290.2mV    6.884mV    1.174V
1.419ns   827.8mV    85.71mV    1.292V
1.628ns   1.056V     177.9mV    1.315V
2.25ns    1.148V     790.9mV    1.32V
3.063ns   1.15V      912.7mV    1.319V
50ns      1.15V      916.1mV    1.319V
[Rising Waveform]
R_fixture = 50
V_fixture = 1.8
V_fixture_min = 1.66
V_fixture_max = 1.89
| Time   V(typ)   V(min)   V(max)
0s        608.6mV    806.2mV    463.4mV
482.3ps   603mV      804mV      498.1mV
519.4ps   602.5mV    802.2mV    654.9mV
579.8ps   620.6mV    800mV      1.343V
629.9ps   723.7mV    798.8mV    1.641V
732.9ps   1.48V      803.5mV    1.841V
853ps     1.745V     969.5mV    1.881V
1.02ns    1.794V     1.572V     1.882V
1.353ns   1.795V     1.657V     1.889V
50ns      1.8V       1.66V      1.89V
[Falling Waveform]
R_fixture = 50
V_fixture = 0
V_fixture_min = 0
V_fixture_max = 0
| Time   V(typ)   V(min)   V(max)
0s        1.15V      916.1mV    1.319V
438.6ps   1.152V     916.2mV    1.269V
518.1ps   1.13V      918.1mV    1.055V
568.1ps   1.085V     918.8mV    673.9mV
673.7ps   778.6mV    906.7mV    125.6mV
777.6ps   200.4mV    843.5mV    20.74mV
913.1ps   25.24mV    554.4mV    2.234mV
1.073ns   2.462mV    76.21mV    3.325mV
1.381ns   2.893mV    1.649mV    850.9uV
50ns      14.88nV    1.047uV    5.437nV
[Falling Waveform]
R_fixture = 50
V_fixture = 1.8
V_fixture_min = 1.66
V_fixture_max = 1.89
| Time   V(typ)   V(min)   V(max)
0s        1.8V       1.66V      1.89V
595.2ps   1.807V     1.66V      1.918V
965.7ps   1.774V     1.676V     1.72V
1.262ns   1.669V     1.653V     940.2mV
1.531ns   1.243V     1.614V     566.2mV
1.849ns   820.2mV    1.546V     485.2mV
2.187ns   671.7mV    1.254V     467.3mV
2.785ns   615.5mV    916.4mV    463.2mV
4.166ns   608.1mV    805.7mV    463.4mV
50ns      608.6mV    806.2mV    463.4mV
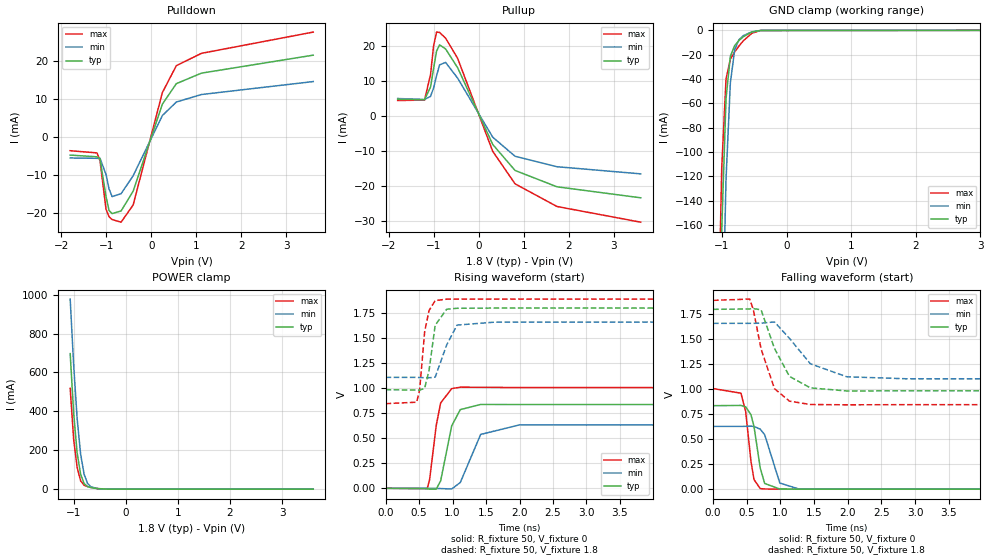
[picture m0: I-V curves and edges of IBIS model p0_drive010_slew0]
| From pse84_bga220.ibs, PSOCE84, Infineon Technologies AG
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[Model] p0_drive010_slew0
Model_type I/O
Polarity  Inverting
Enable   Active-High
Vinl  =  0.54
Vinh  =  1.26
Vmeas =  0.9
Cref  =  15pF
| Capacitance   typ   min   max
C_comp   1.253838e-12   1.215159e-12   1.300411e-12
| Variables   typ   min   max
[GND Clamp Reference]   0   0   0
[POWER Clamp Reference]   1.8   1.66   1.89
[Pulldown Reference]   0   0   0
[Pullup Reference]   1.8   1.66   1.89
[Temperature Range]   25   125   -40
[Voltage Range]   1.8   1.66   1.89
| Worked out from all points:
|   slope of the pulldown table from 0 to 0.27 V, typ, clamps not added: 29.8 ohm
|   slope of the pullup table from 0 to 0.27 V, typ, clamps not added: 38.1 ohm
|   GND clamp passes 1 mA (typ) near -0.51 V on its own axis
|   POWER clamp passes 1 mA (typ) near -0.47 V on its own axis
|   rising waveform, R_fixture 50, V_fixture 0: 20-80 % time 158ps typ, 223ps min, 123ps max; typ from 0 V to 0.836 V
|   rising waveform, R_fixture 50, V_fixture 1.8: 20-80 % time 101ps typ, 118ps min, 93.8ps max; typ from 0.985 V to 1.8 V
|   falling waveform, R_fixture 50, V_fixture 0: 20-80 % time 119ps typ, 150ps min, 101ps max; typ from 0.836 V to 0 V
|   falling waveform, R_fixture 50, V_fixture 1.8: 20-80 % time 309ps typ, 425ps min, 241ps max; typ from 1.8 V to 0.985 V
[GND Clamp]
| Voltage   I(typ)   I(min)   I(max)
-1.137V   -619.5mA   -754.2mA   -533mA
-1.07V    -361.2mA   -498.1mA   -281.3mA
-1.003V   -163.8mA   -277.7mA   -113mA
-936.6mV  -56.22mA   -122.3mA   -40.06mA
-869.7mV  -21.33mA   -43.3mA    -23.67mA
-802.8mV  -12.5mA    -15.96mA   -17.71mA
-735.9mV  -8.346mA   -7.675mA   -12.88mA
-669mV    -5.267mA   -4.349mA   -8.575mA
-535.2mV  -1.314mA   -1.207mA   -2.328mA
-401.4mV  -73.55uA   -132.2uA   -119.3uA
3.6V      0A         0A         0A
[POWER Clamp]
| Voltage   I(typ)   I(min)   I(max)
-1.07V    696.7mA    977.2mA    518.8mA
-1.003V   390.1mA    637.2mA    255.1mA
-936.6mV  187.1mA    363.9mA    112.4mA
-869.7mV  77.2mA     180.7mA    42.71mA
-802.8mV  28.89mA    77.43mA    19.98mA
-735.9mV  13.12mA    29.18mA    13.35mA
-669mV    7.754mA    11.55mA    8.954mA
-535.2mV  2.356mA    2.862mA    2.667mA
-334.5mV  34.33uA    127.4uA    15.58uA
3.6V      0A         0A         0A
[Pullup]
| Voltage   I(typ)   I(min)   I(max)
-1.8V     4.854mA    5.09mA     4.523mA
-1.204V   4.729mA    4.833mA    4.644mA
-1.07V    8.387mA    5.719mA    11.96mA
-1.003V   13.66mA    8.075mA    20.1mA
-936.6mV  18.65mA    11.61mA    24.05mA
-869.7mV  20.4mA     14.69mA    23.95mA
-735.9mV  19.24mA    15.4mA     22.32mA
-468.3mV  13.88mA    10.9mA     16.56mA
310.3mV   -7.999mA   -5.93mA    -9.954mA
806.9mV   -15.43mA   -11.38mA   -19.25mA
1.738V    -20.1mA    -14.37mA   -25.72mA
3.6V      -23.24mA   -16.41mA   -30.2mA
[Pulldown]
| Voltage   I(typ)   I(min)   I(max)
-1.8V     -4.892mA   -5.644mA   -3.736mA
-1.204V   -5.339mA   -5.743mA   -4.316mA
-1.137V   -5.907mA   -5.743mA   -6.406mA
-1.003V   -15.83mA   -10.03mA   -19.17mA
-936.6mV  -19.47mA   -13.77mA   -21.1mA
-869.7mV  -20.29mA   -15.81mA   -21.85mA
-669mV    -19.59mA   -15.05mA   -22.55mA
-401.4mV  -14.4mA    -10.33mA   -18.03mA
248.3mV   8.524mA    5.521mA    11.56mA
558.6mV   13.91mA    9.079mA    18.65mA
1.117V    16.68mA    11.05mA    21.89mA
3.6V      21.41mA    14.46mA    27.48mA
[Ramp]
dV/dt_r   0.501498/0.157788n  0.376807/0.222841n  0.603996/0.123374n
dV/dt_f   0.489167/0.308725n  0.330919/0.425131n  0.626636/0.241186n
R_load = 50
[Rising Waveform]
R_fixture = 50
V_fixture = 0
V_fixture_min = 0
V_fixture_max = 0
| Time   V(typ)   V(min)   V(max)
0s        21.31nV    1.424uV    7.952nV
621.7ps   -4.038mV   -8.703uV   -3.095mV
657.9ps   -8.584mV   -26.6uV    86.14mV
757.1ps   -8.054mV   -688.9uV   629.5mV
822.8ps   74.71mV    -2.692mV   851.8mV
986.9ps   622.5mV    -6.697mV   995.4mV
1.116ns   785.9mV    58.1mV     1.01V
1.42ns    837.4mV    538mV      1.009V
1.996ns   836.6mV    632.7mV    1.006V
50ns      835.8mV    628mV      1.007V
[Rising Waveform]
R_fixture = 50
V_fixture = 1.8
V_fixture_min = 1.66
V_fixture_max = 1.89
| Time   V(typ)   V(min)   V(max)
0s        984.7mV    1.108V     845.6mV
463.7ps   980.6mV    1.108V     859.8mV
508.9ps   980.1mV    1.106V     982.3mV
583.8ps   999mV      1.105V     1.563V
649ps     1.175V     1.104V     1.775V
740.9ps   1.628V     1.11V      1.875V
912.1ps   1.788V     1.431V     1.889V
1.067ns   1.798V     1.63V      1.89V
1.637ns   1.8V       1.66V      1.89V
50ns      1.8V       1.66V      1.89V
[Falling Waveform]
R_fixture = 50
V_fixture = 0
V_fixture_min = 0
V_fixture_max = 0
| Time   V(typ)   V(min)   V(max)
0s        835.8mV    628mV      1.007V
413.8ps   838.2mV    628mV      960.7mV
484ps     824.3mV    629.3mV    777.8mV
562.4ps   745.5mV    630.4mV    280.8mV
607.8ps   627.8mV    628mV      95.92mV
700.5ps   211mV      600.9mV    5.656mV
766.3ps   57.1mV     545.1mV    1.952mV
991.2ps   1.349mV    61.4mV     481.2uV
1.273ns   376.3uV    1.616mV    215.2uV
50ns      21.24nV    1.499uV    7.977nV
[Falling Waveform]
R_fixture = 50
V_fixture = 1.8
V_fixture_min = 1.66
V_fixture_max = 1.89
| Time   V(typ)   V(min)   V(max)
0s        1.8V       1.66V      1.89V
544.1ps   1.804V     1.66V      1.903V
596.8ps   1.808V     1.66V      1.799V
713ps     1.795V     1.662V     1.403V
911.5ps   1.409V     1.674V     1.006V
1.134ns   1.129V     1.51V      881.2mV
1.445ns   1.014V     1.255V     847.5mV
1.985ns   983mV      1.125V     844.4mV
2.871ns   984.5mV    1.105V     845.9mV
50ns      984.7mV    1.108V     845.6mV
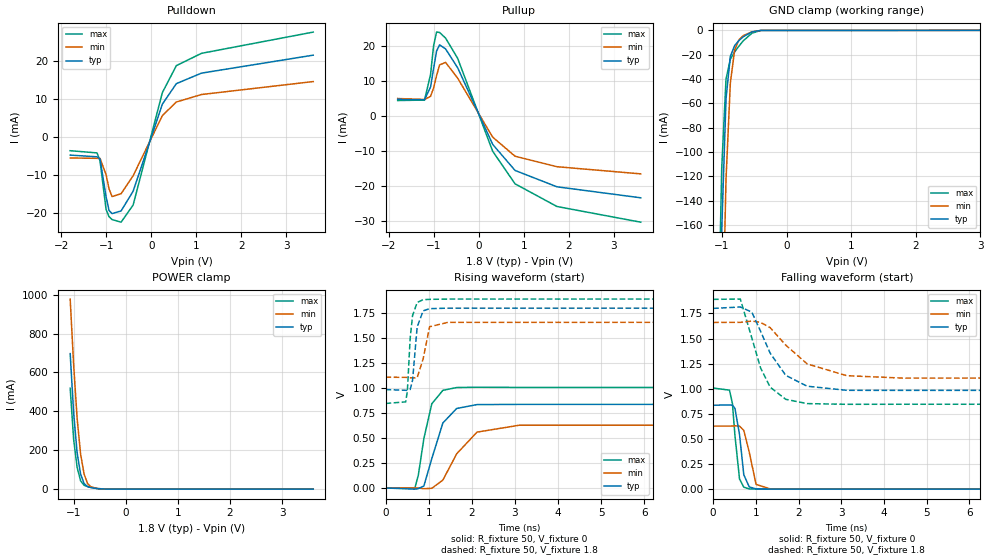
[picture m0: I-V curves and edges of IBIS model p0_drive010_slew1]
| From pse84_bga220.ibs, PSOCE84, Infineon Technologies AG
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[Model] p0_drive010_slew1
Model_type I/O
Polarity  Inverting
Enable   Active-High
Vinl  =  0.54
Vinh  =  1.26
Vmeas =  0.9
Cref  =  15pF
| Capacitance   typ   min   max
C_comp   1.253838e-12   1.215159e-12   1.300411e-12
| Variables   typ   min   max
[GND Clamp Reference]   0   0   0
[POWER Clamp Reference]   1.8   1.66   1.89
[Pulldown Reference]   0   0   0
[Pullup Reference]   1.8   1.66   1.89
[Temperature Range]   25   125   -40
[Voltage Range]   1.8   1.66   1.89
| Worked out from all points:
|   slope of the pulldown table from 0 to 0.27 V, typ, clamps not added: 29.8 ohm
|   slope of the pullup table from 0 to 0.27 V, typ, clamps not added: 38.1 ohm
|   GND clamp passes 1 mA (typ) near -0.51 V on its own axis
|   POWER clamp passes 1 mA (typ) near -0.47 V on its own axis
|   rising waveform, R_fixture 50, V_fixture 0: 20-80 % time 353ps typ, 552ps min, 254ps max; typ from 0 V to 0.836 V
|   rising waveform, R_fixture 50, V_fixture 1.8: 20-80 % time 99.8ps typ, 116ps min, 92.5ps max; typ from 0.985 V to 1.8 V
|   falling waveform, R_fixture 50, V_fixture 0: 20-80 % time 124ps typ, 153ps min, 111ps max; typ from 0.836 V to 0 V
|   falling waveform, R_fixture 50, V_fixture 1.8: 20-80 % time 616ps typ, 858ps min, 471ps max; typ from 1.8 V to 0.985 V
[GND Clamp]
| Voltage   I(typ)   I(min)   I(max)
-1.137V   -619.5mA   -754.2mA   -533mA
-1.07V    -361.2mA   -498.1mA   -281.3mA
-1.003V   -163.8mA   -277.7mA   -113mA
-936.6mV  -56.22mA   -122.3mA   -40.06mA
-869.7mV  -21.33mA   -43.3mA    -23.67mA
-802.8mV  -12.5mA    -15.96mA   -17.71mA
-735.9mV  -8.346mA   -7.675mA   -12.88mA
-669mV    -5.267mA   -4.349mA   -8.575mA
-535.2mV  -1.314mA   -1.207mA   -2.328mA
-401.4mV  -73.55uA   -132.2uA   -119.3uA
3.6V      0A         0A         0A
[POWER Clamp]
| Voltage   I(typ)   I(min)   I(max)
-1.07V    696.7mA    977.2mA    518.8mA
-1.003V   390.1mA    637.2mA    255.1mA
-936.6mV  187.1mA    363.9mA    112.4mA
-869.7mV  77.2mA     180.7mA    42.71mA
-802.8mV  28.89mA    77.43mA    19.98mA
-735.9mV  13.12mA    29.18mA    13.35mA
-669mV    7.754mA    11.55mA    8.954mA
-535.2mV  2.356mA    2.862mA    2.667mA
-334.5mV  34.33uA    127.4uA    15.58uA
3.6V      0A         0A         0A
[Pullup]
| Voltage   I(typ)   I(min)   I(max)
-1.8V     4.854mA    5.09mA     4.523mA
-1.204V   4.729mA    4.833mA    4.644mA
-1.07V    8.387mA    5.719mA    11.96mA
-1.003V   13.66mA    8.075mA    20.1mA
-936.6mV  18.65mA    11.61mA    24.05mA
-869.7mV  20.4mA     14.69mA    23.95mA
-735.9mV  19.24mA    15.4mA     22.32mA
-468.3mV  13.88mA    10.9mA     16.56mA
310.3mV   -7.999mA   -5.93mA    -9.954mA
806.9mV   -15.43mA   -11.38mA   -19.25mA
1.738V    -20.1mA    -14.37mA   -25.72mA
3.6V      -23.24mA   -16.41mA   -30.2mA
[Pulldown]
| Voltage   I(typ)   I(min)   I(max)
-1.8V     -4.892mA   -5.644mA   -3.736mA
-1.204V   -5.339mA   -5.743mA   -4.316mA
-1.137V   -5.907mA   -5.743mA   -6.406mA
-1.003V   -15.83mA   -10.03mA   -19.17mA
-936.6mV  -19.47mA   -13.77mA   -21.1mA
-869.7mV  -20.29mA   -15.81mA   -21.85mA
-669mV    -19.59mA   -15.05mA   -22.55mA
-401.4mV  -14.4mA    -10.33mA   -18.03mA
248.3mV   8.524mA    5.521mA    11.56mA
558.6mV   13.91mA    9.079mA    18.65mA
1.117V    16.68mA    11.05mA    21.89mA
3.6V      21.41mA    14.46mA    27.48mA
[Ramp]
dV/dt_r   0.501498/0.353315n  0.376804/0.552395n  0.603996/0.254198n
dV/dt_f   0.489167/0.616334n  0.330918/0.85814n  0.626636/0.470986n
R_load = 50
[Rising Waveform]
R_fixture = 50
V_fixture = 0
V_fixture_min = 0
V_fixture_max = 0
| Time   V(typ)   V(min)   V(max)
0s        21.31nV    1.424uV    7.952nV
682.4ps   -11.86mV   -46.34uV   2.256mV
760.9ps   -6.33mV    -762.4uV   128.7mV
889.1ps   19.92mV    -7.249mV   494.1mV
1.073ns   293.6mV    -2.968mV   842.3mV
1.33ns    650.3mV    79.26mV    976.8mV
1.651ns   795.7mV    342.1mV    1.005V
2.122ns   834.1mV    558.8mV    1.008V
3.102ns   836.4mV    627.9mV    1.006V
50ns      835.8mV    628mV      1.007V
[Rising Waveform]
R_fixture = 50
V_fixture = 1.8
V_fixture_min = 1.66
V_fixture_max = 1.89
| Time   V(typ)   V(min)   V(max)
0s        984.7mV    1.108V     845.6mV
468.3ps   977.5mV    1.107V     861.4mV
506.7ps   976.2mV    1.105V     972.4mV
570.8ps   985.6mV    1.103V     1.496V
626.7ps   1.077V     1.101V     1.724V
733.4ps   1.611V     1.103V     1.856V
872.8ps   1.772V     1.293V     1.884V
1.023ns   1.794V     1.613V     1.887V
1.446ns   1.799V     1.657V     1.89V
50ns      1.8V       1.66V      1.89V
[Falling Waveform]
R_fixture = 50
V_fixture = 0
V_fixture_min = 0
V_fixture_max = 0
| Time   V(typ)   V(min)   V(max)
0s        835.8mV    628mV      1.007V
384.1ps   839mV      628mV      986mV
452.9ps   836.3mV    628.6mV    852.3mV
512.1ps   804mV      630.8mV    533.5mV
619.4ps   542.3mV    628.6mV    100.6mV
719.1ps   143.1mV    585.1mV    19.95mV
847.1ps   21.71mV    368mV      2.208mV
1.006ns   3.052mV    47.75mV    1.18mV
1.342ns   827.1uV    1.938mV    476uV
50ns      21.29nV    1.427uV    7.985nV
[Falling Waveform]
R_fixture = 50
V_fixture = 1.8
V_fixture_min = 1.66
V_fixture_max = 1.89
| Time   V(typ)   V(min)   V(max)
0s        1.8V       1.66V      1.89V
637.9ps   1.814V     1.661V     1.893V
906.9ps   1.763V     1.674V     1.506V
1.109ns   1.575V     1.661V     1.21V
1.335ns   1.355V     1.609V     1.016V
1.701ns   1.133V     1.434V     894.6mV
2.203ns   1.025V     1.247V     852mV
3.128ns   984.3mV    1.13V      845mV
4.428ns   983.9mV    1.106V     845.6mV
50ns      984.7mV    1.108V     845.6mV
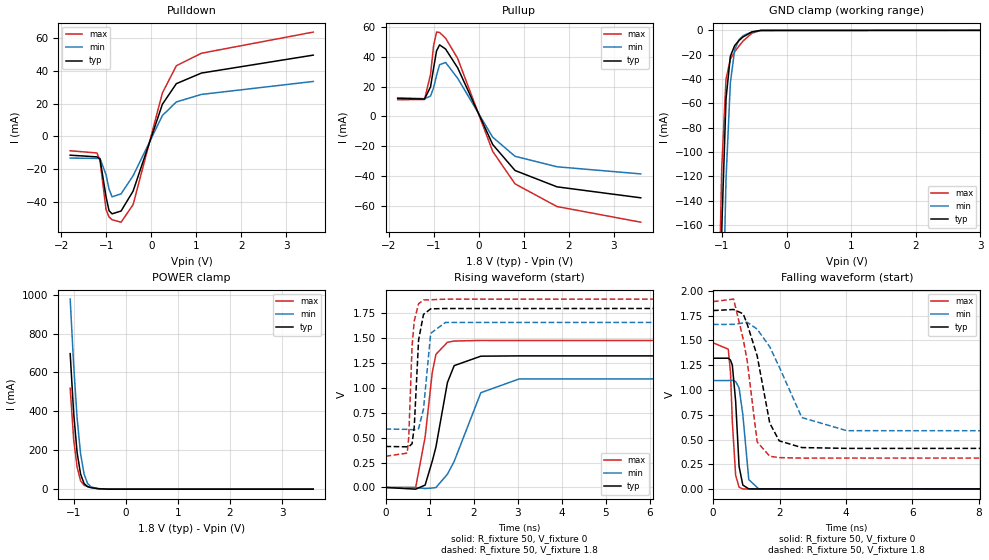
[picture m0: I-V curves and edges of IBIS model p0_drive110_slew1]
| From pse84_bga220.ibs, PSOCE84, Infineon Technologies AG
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[Model] p0_drive110_slew1
Model_type I/O
Polarity  Inverting
Enable   Active-High
Vinl  =  0.54
Vinh  =  1.26
Vmeas =  0.9
Cref  =  15pF
| Capacitance   typ   min   max
C_comp   1.253838e-12   1.215159e-12   1.300411e-12
| Variables   typ   min   max
[GND Clamp Reference]   0   0   0
[POWER Clamp Reference]   1.8   1.66   1.89
[Pulldown Reference]   0   0   0
[Pullup Reference]   1.8   1.66   1.89
[Temperature Range]   25   125   -40
[Voltage Range]   1.8   1.66   1.89
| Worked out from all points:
|   slope of the pulldown table from 0 to 0.27 V, typ, clamps not added: 12.9 ohm
|   slope of the pullup table from 0 to 0.27 V, typ, clamps not added: 16.3 ohm
|   GND clamp passes 1 mA (typ) near -0.51 V on its own axis
|   POWER clamp passes 1 mA (typ) near -0.47 V on its own axis
|   rising waveform, R_fixture 50, V_fixture 0: 20-80 % time 345ps typ, 550ps min, 246ps max; typ from 0 V to 1.32 V
|   rising waveform, R_fixture 50, V_fixture 1.8: 20-80 % time 97.6ps typ, 116ps min, 90ps max; typ from 0.411 V to 1.8 V
|   falling waveform, R_fixture 50, V_fixture 0: 20-80 % time 126ps typ, 160ps min, 108ps max; typ from 1.32 V to 0 V
|   falling waveform, R_fixture 50, V_fixture 1.8: 20-80 % time 525ps typ, 809ps min, 373ps max; typ from 1.8 V to 0.411 V
[GND Clamp]
| Voltage   I(typ)   I(min)   I(max)
-1.137V   -619.5mA   -754.2mA   -533mA
-1.07V    -361.2mA   -498.1mA   -281.3mA
-1.003V   -163.8mA   -277.7mA   -113mA
-936.6mV  -56.22mA   -122.3mA   -40.06mA
-869.7mV  -21.33mA   -43.3mA    -23.67mA
-802.8mV  -12.5mA    -15.96mA   -17.71mA
-735.9mV  -8.346mA   -7.675mA   -12.88mA
-669mV    -5.267mA   -4.349mA   -8.575mA
-535.2mV  -1.314mA   -1.207mA   -2.328mA
-401.4mV  -73.55uA   -132.2uA   -119.3uA
3.6V      0A         0A         0A
[POWER Clamp]
| Voltage   I(typ)   I(min)   I(max)
-1.07V    696.7mA    977.2mA    518.8mA
-1.003V   390.1mA    637.2mA    255.1mA
-936.6mV  187.1mA    363.9mA    112.4mA
-869.7mV  77.2mA     180.7mA    42.71mA
-802.8mV  28.89mA    77.43mA    19.98mA
-735.9mV  13.12mA    29.18mA    13.35mA
-669mV    7.754mA    11.55mA    8.954mA
-535.2mV  2.356mA    2.862mA    2.667mA
-334.5mV  34.33uA    127.4uA    15.58uA
3.6V      0A         0A         0A
[Pullup]
| Voltage   I(typ)   I(min)   I(max)
-1.8V     11.96mA    12.52mA    11.17mA
-1.204V   11.63mA    11.87mA    11.36mA
-1.07V    19.81mA    13.65mA    28.15mA
-1.003V   32.26mA    19.14mA    47.26mA
-936.6mV  43.85mA    27.48mA    56.38mA
-869.7mV  47.83mA    34.58mA    56.11mA
-735.9mV  45.06mA    36.08mA    52.29mA
-468.3mV  32.52mA    25.53mA    38.8mA
310.3mV   -18.74mA   -13.88mA   -23.33mA
806.9mV   -36.11mA   -26.63mA   -45.05mA
1.738V    -47.03mA   -33.62mA   -60.19mA
3.6V      -54.37mA   -38.39mA   -70.66mA
[Pulldown]
| Voltage   I(typ)   I(min)   I(max)
-1.8V     -11.4mA    -13.16mA   -8.708mA
-1.204V   -12.44mA   -13.38mA   -10.06mA
-1.137V   -13.75mA   -13.38mA   -14.91mA
-1.003V   -36.83mA   -23.35mA   -44.61mA
-936.6mV  -45.27mA   -32.05mA   -49.07mA
-869.7mV  -47.17mA   -36.79mA   -50.78mA
-669mV    -45.46mA   -34.98mA   -52.27mA
-401.4mV  -33.27mA   -23.95mA   -41.53mA
248.3mV   19.64mA    12.78mA    26.51mA
558.6mV   32.22mA    21.07mA    43.15mA
1.117V    38.69mA    25.66mA    50.78mA
3.6V      49.62mA    33.56mA    63.67mA
[Ramp]
dV/dt_r   0.791903/0.344893n  0.65696/0.550092n  0.884729/0.245866n
dV/dt_f   0.83321/0.525249n  0.644571/0.809315n  0.946064/0.372984n
R_load = 50
[Rising Waveform]
R_fixture = 50
V_fixture = 0
V_fixture_min = 0
V_fixture_max = 0
| Time   V(typ)   V(min)   V(max)
0s        11.48nV    820.1nV    4.127nV
682.9ps   -17.09mV   -78.35uV   -586.5uV
897.6ps   23.67mV    -11.09mV   505.3mV
1.061ns   265.2mV    -5.248mV   1.157V
1.143ns   406.1mV    -1.182mV   1.336V
1.404ns   1.053V     133.3mV    1.456V
1.557ns   1.222V     261.7mV    1.469V
2.162ns   1.317V     950.6mV    1.475V
3.033ns   1.32V      1.089V     1.474V
50ns      1.32V      1.095V     1.475V
[Rising Waveform]
R_fixture = 50
V_fixture = 1.8
V_fixture_min = 1.66
V_fixture_max = 1.89
| Time   V(typ)   V(min)   V(max)
0s        411.3mV    585.7mV    313.2mV
491.9ps   407.9mV    583.2mV    344.8mV
527ps     408mV      581.9mV    506.9mV
601.6ps   438.7mV    580mV      1.417V
651.2ps   607.2mV    579.2mV    1.67V
749.4ps   1.479V     589mV      1.843V
861.2ps   1.736V     787.8mV    1.881V
1.024ns   1.792V     1.546V     1.883V
1.357ns   1.795V     1.655V     1.889V
50ns      1.8V       1.66V      1.89V
[Falling Waveform]
R_fixture = 50
V_fixture = 0
V_fixture_min = 0
V_fixture_max = 0
| Time   V(typ)   V(min)   V(max)
0s        1.32V      1.095V     1.475V
457.4ps   1.32V      1.095V     1.411V
525.3ps   1.3V       1.097V     1.172V
579.6ps   1.25V      1.097V     680.2mV
679.7ps   884.7mV    1.085V     138.5mV
782.8ps   229mV      1.021V     19.76mV
895.9ps   40.9mV     750.4mV    2.166mV
1.075ns   2.843mV    96.18mV    2.592mV
1.376ns   2.39mV     2.571mV    802uV
50ns      11.46nV    826.7nV    4.139nV
[Falling Waveform]
R_fixture = 50
V_fixture = 1.8
V_fixture_min = 1.66
V_fixture_max = 1.89
| Time   V(typ)   V(min)   V(max)
0s        1.8V       1.66V      1.89V
618.3ps   1.811V     1.661V     1.916V
906.8ps   1.767V     1.675V     1.512V
1.026ns   1.665V     1.682V     1.297V
1.327ns   1.344V     1.613V     475.6mV
1.706ns   665.6mV    1.435V     331.6mV
1.991ns   486.6mV    1.232V     318.3mV
2.67ns    419.4mV    721.8mV    313.2mV
4.023ns   411mV      589.4mV    313.3mV
50ns      411.3mV    585.7mV    313.2mV
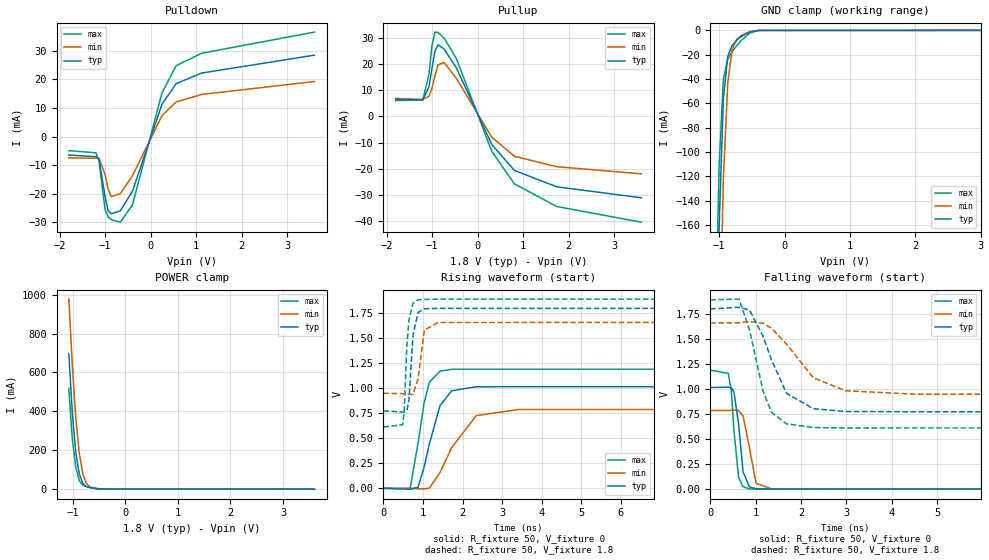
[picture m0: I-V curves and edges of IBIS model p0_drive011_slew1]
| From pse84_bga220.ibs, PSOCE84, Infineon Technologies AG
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[Model] p0_drive011_slew1
Model_type I/O
Polarity  Inverting
Enable   Active-High
Vinl  =  0.54
Vinh  =  1.26
Vmeas =  0.9
Cref  =  15pF
| Capacitance   typ   min   max
C_comp   1.253838e-12   1.215159e-12   1.300411e-12
| Variables   typ   min   max
[GND Clamp Reference]   0   0   0
[POWER Clamp Reference]   1.8   1.66   1.89
[Pulldown Reference]   0   0   0
[Pullup Reference]   1.8   1.66   1.89
[Temperature Range]   25   125   -40
[Voltage Range]   1.8   1.66   1.89
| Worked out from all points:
|   slope of the pulldown table from 0 to 0.27 V, typ, clamps not added: 22.5 ohm
|   slope of the pullup table from 0 to 0.27 V, typ, clamps not added: 28.6 ohm
|   GND clamp passes 1 mA (typ) near -0.51 V on its own axis
|   POWER clamp passes 1 mA (typ) near -0.47 V on its own axis
|   rising waveform, R_fixture 50, V_fixture 0: 20-80 % time 393ps typ, 627ps min, 277ps max; typ from 0 V to 1.01 V
|   rising waveform, R_fixture 50, V_fixture 1.8: 20-80 % time 101ps typ, 118ps min, 93.1ps max; typ from 0.773 V to 1.8 V
|   falling waveform, R_fixture 50, V_fixture 0: 20-80 % time 122ps typ, 151ps min, 109ps max; typ from 1.01 V to 0 V
|   falling waveform, R_fixture 50, V_fixture 1.8: 20-80 % time 548ps typ, 794ps min, 402ps max; typ from 1.8 V to 0.773 V
[GND Clamp]
| Voltage   I(typ)   I(min)   I(max)
-1.137V   -619.5mA   -754.2mA   -533mA
-1.07V    -361.2mA   -498.1mA   -281.3mA
-1.003V   -163.8mA   -277.7mA   -113mA
-936.6mV  -56.22mA   -122.3mA   -40.06mA
-869.7mV  -21.33mA   -43.3mA    -23.67mA
-802.8mV  -12.5mA    -15.96mA   -17.71mA
-735.9mV  -8.346mA   -7.675mA   -12.88mA
-669mV    -5.267mA   -4.349mA   -8.575mA
-535.2mV  -1.314mA   -1.207mA   -2.328mA
-401.4mV  -73.55uA   -132.2uA   -119.3uA
3.6V      0A         0A         0A
[POWER Clamp]
| Voltage   I(typ)   I(min)   I(max)
-1.07V    696.7mA    977.2mA    518.8mA
-1.003V   390.1mA    637.2mA    255.1mA
-936.6mV  187.1mA    363.9mA    112.4mA
-869.7mV  77.2mA     180.7mA    42.71mA
-802.8mV  28.89mA    77.43mA    19.98mA
-735.9mV  13.12mA    29.18mA    13.35mA
-669mV    7.754mA    11.55mA    8.954mA
-535.2mV  2.356mA    2.862mA    2.667mA
-334.5mV  34.33uA    127.4uA    15.58uA
3.6V      0A         0A         0A
[Pullup]
| Voltage   I(typ)   I(min)   I(max)
-1.8V     6.481mA    6.795mA    6.041mA
-1.204V   6.313mA    6.452mA    6.201mA
-1.07V    11.2mA     7.632mA    15.98mA
-1.003V   18.25mA    10.78mA    26.84mA
-936.6mV  24.89mA    15.49mA    32.08mA
-869.7mV  27.21mA    19.59mA    31.94mA
-735.9mV  25.65mA    20.53mA    29.76mA
-468.3mV  18.5mA     14.53mA    22.07mA
310.3mV   -10.66mA   -7.903mA   -13.27mA
806.9mV   -20.57mA   -15.17mA   -25.67mA
1.738V    -26.81mA   -19.16mA   -34.31mA
3.6V      -30.99mA   -21.88mA   -40.28mA
[Pulldown]
| Voltage   I(typ)   I(min)   I(max)
-1.8V     -6.48mA    -7.478mA   -4.95mA
-1.204V   -7.066mA   -7.605mA   -5.711mA
-1.137V   -7.866mA   -7.604mA   -8.539mA
-1.003V   -21.07mA   -13.35mA   -25.53mA
-936.6mV  -25.91mA   -18.32mA   -28.09mA
-869.7mV  -27.01mA   -21.05mA   -29.08mA
-669mV    -26.06mA   -20.03mA   -29.98mA
-401.4mV  -19.12mA   -13.74mA   -23.9mA
248.3mV   11.3mA     7.336mA    15.3mA
558.6mV   18.49mA    12.08mA    24.78mA
1.117V    22.19mA    14.7mA     29.12mA
3.6V      28.47mA    19.24mA    36.53mA
[Ramp]
dV/dt_r   0.608795/0.393214n  0.471539/0.626913n  0.713578/0.277348n
dV/dt_f   0.61646/0.547909n  0.426861/0.793631n  0.767104/0.402341n
R_load = 50
[Rising Waveform]
R_fixture = 50
V_fixture = 0
V_fixture_min = 0
V_fixture_max = 0
| Time   V(typ)   V(min)   V(max)
0s        17.55nV    1.202uV    6.456nV
674.1ps   -8.627mV   -10.11uV   -3.533mV
874ps     9.101mV    -4.632mV   448.6mV
1.029ns   212.5mV    -6.136mV   852.9mV
1.161ns   441.2mV    1.452mV    1.06V
1.43ns    825.6mV    158mV      1.17V
1.726ns   974.2mV    406.5mV    1.189V
2.345ns   1.014V     725.5mV    1.189V
3.415ns   1.015V     786.9mV    1.189V
50ns      1.015V     785.9mV    1.189V
[Rising Waveform]
R_fixture = 50
V_fixture = 1.8
V_fixture_min = 1.66
V_fixture_max = 1.89
| Time   V(typ)   V(min)   V(max)
0s        772.6mV    948.6mV    611.5mV
486.6ps   762.3mV    945.4mV    635.1mV
526.9ps   760.7mV    942.6mV    778.6mV
592.9ps   776.4mV    939mV      1.426V
644.3ps   876mV      937mV      1.68V
747.8ps   1.529V     938.2mV    1.848V
875.3ps   1.756V     1.091V     1.883V
1.035ns   1.793V     1.581V     1.886V
1.389ns   1.797V     1.656V     1.889V
50ns      1.8V       1.66V      1.89V
[Falling Waveform]
R_fixture = 50
V_fixture = 0
V_fixture_min = 0
V_fixture_max = 0
| Time   V(typ)   V(min)   V(max)
0s        1.015V     785.9mV    1.189V
396.7ps   1.018V     785.8mV    1.156V
463.5ps   1.012V     786.9mV    984.8mV
521.3ps   969.8mV    789.3mV    584.8mV
623.9ps   652.8mV    785.1mV    117.2mV
722.1ps   173.5mV    732.6mV    24.43mV
862.8ps   21.77mV    411.5mV    2.181mV
1.009ns   3.498mV    58.51mV    2.217mV
1.355ns   1.543mV    1.997mV    540uV
50ns      17.51nV    1.213uV    6.484nV
[Falling Waveform]
R_fixture = 50
V_fixture = 1.8
V_fixture_min = 1.66
V_fixture_max = 1.89
| Time   V(typ)   V(min)   V(max)
0s        1.8V       1.66V      1.89V
633.8ps   1.816V     1.661V     1.898V
865ps     1.789V     1.673V     1.59V
1.163ns   1.526V     1.657V     978.2mV
1.351ns   1.289V     1.606V     767mV
1.679ns   957.2mV    1.449V     652.2mV
2.27ns    803.1mV    1.112V     615.2mV
2.978ns   775.6mV    982.5mV    611.3mV
4.557ns   772.3mV    947.4mV    611.5mV
50ns      772.6mV    948.6mV    611.5mV
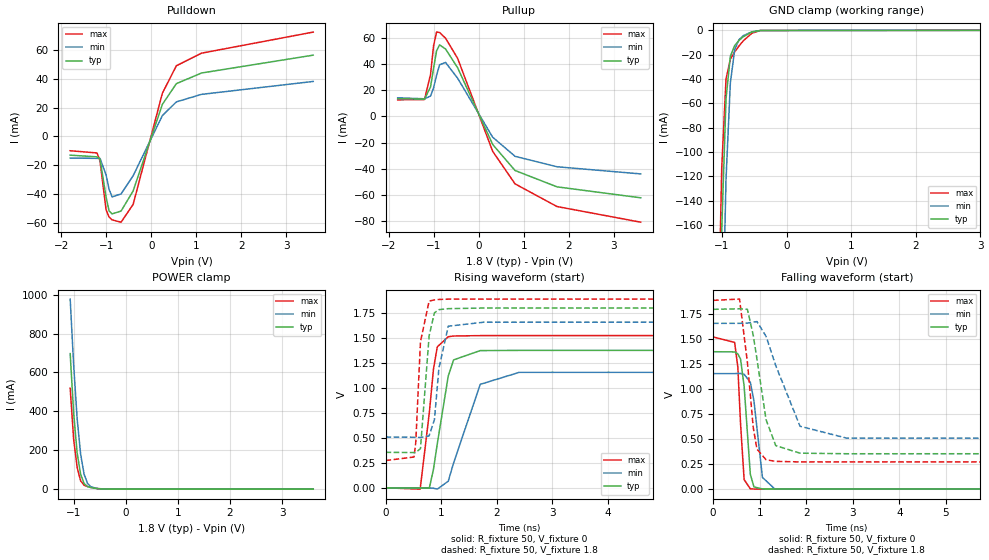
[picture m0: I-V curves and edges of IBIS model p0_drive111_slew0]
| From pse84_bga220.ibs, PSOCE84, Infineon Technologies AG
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[Model] p0_drive111_slew0
Model_type I/O
Polarity  Inverting
Enable   Active-High
Vinl  =  0.54
Vinh  =  1.26
Vmeas =  0.9
Cref  =  15pF
| Capacitance   typ   min   max
C_comp   1.253838e-12   1.215159e-12   1.300411e-12
| Variables   typ   min   max
[GND Clamp Reference]   0   0   0
[POWER Clamp Reference]   1.8   1.66   1.89
[Pulldown Reference]   0   0   0
[Pullup Reference]   1.8   1.66   1.89
[Temperature Range]   25   125   -40
[Voltage Range]   1.8   1.66   1.89
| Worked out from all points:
|   slope of the pulldown table from 0 to 0.27 V, typ, clamps not added: 11.4 ohm
|   slope of the pullup table from 0 to 0.27 V, typ, clamps not added: 14.3 ohm
|   GND clamp passes 1 mA (typ) near -0.51 V on its own axis
|   POWER clamp passes 1 mA (typ) near -0.47 V on its own axis
|   rising waveform, R_fixture 50, V_fixture 0: 20-80 % time 236ps typ, 384ps min, 165ps max; typ from 0 V to 1.38 V
|   rising waveform, R_fixture 50, V_fixture 1.8: 20-80 % time 98.2ps typ, 117ps min, 89.3ps max; typ from 0.355 V to 1.8 V
|   falling waveform, R_fixture 50, V_fixture 0: 20-80 % time 117ps typ, 156ps min, 94ps max; typ from 1.38 V to 0 V
|   falling waveform, R_fixture 50, V_fixture 1.8: 20-80 % time 287ps typ, 483ps min, 189ps max; typ from 1.8 V to 0.355 V
[GND Clamp]
| Voltage   I(typ)   I(min)   I(max)
-1.137V   -619.5mA   -754.2mA   -533mA
-1.07V    -361.2mA   -498.1mA   -281.3mA
-1.003V   -163.8mA   -277.7mA   -113mA
-936.6mV  -56.22mA   -122.3mA   -40.06mA
-869.7mV  -21.33mA   -43.3mA    -23.67mA
-802.8mV  -12.5mA    -15.96mA   -17.71mA
-735.9mV  -8.346mA   -7.675mA   -12.88mA
-669mV    -5.267mA   -4.349mA   -8.575mA
-535.2mV  -1.314mA   -1.207mA   -2.328mA
-401.4mV  -73.55uA   -132.2uA   -119.3uA
3.6V      0A         0A         0A
[POWER Clamp]
| Voltage   I(typ)   I(min)   I(max)
-1.07V    696.7mA    977.2mA    518.8mA
-1.003V   390.1mA    637.2mA    255.1mA
-936.6mV  187.1mA    363.9mA    112.4mA
-869.7mV  77.2mA     180.7mA    42.71mA
-802.8mV  28.89mA    77.43mA    19.98mA
-735.9mV  13.12mA    29.18mA    13.35mA
-669mV    7.754mA    11.55mA    8.954mA
-535.2mV  2.356mA    2.862mA    2.667mA
-334.5mV  34.33uA    127.4uA    15.58uA
3.6V      0A         0A         0A
[Pullup]
| Voltage   I(typ)   I(min)   I(max)
-1.8V     13.58mA    14.22mA    12.68mA
-1.204V   13.21mA    13.48mA    12.91mA
-1.07V    22.6mA     15.55mA    32.14mA
-1.003V   36.82mA    21.83mA    53.96mA
-936.6mV  50.06mA    31.34mA    64.36mA
-869.7mV  54.6mA     39.46mA    64.05mA
-735.9mV  51.43mA    41.18mA    59.68mA
-468.3mV  37.11mA    29.14mA    44.28mA
310.3mV   -21.38mA   -15.85mA   -26.61mA
806.9mV   -41.22mA   -30.4mA    -51.42mA
1.738V    -53.69mA   -38.38mA   -68.71mA
3.6V      -62.06mA   -43.83mA   -80.66mA
[Pulldown]
| Voltage   I(typ)   I(min)   I(max)
-1.8V     -12.98mA   -14.98mA   -9.917mA
-1.204V   -14.15mA   -15.23mA   -11.44mA
-1.137V   -15.69mA   -15.23mA   -17.03mA
-1.003V   -42.02mA   -26.63mA   -50.92mA
-936.6mV  -51.65mA   -36.56mA   -55.99mA
-869.7mV  -53.8mA    -41.97mA   -57.94mA
-669mV    -51.82mA   -39.89mA   -59.56mA
-401.4mV  -37.85mA   -27.29mA   -47.2mA
248.3mV   22.31mA    14.55mA    30.07mA
558.6mV   36.69mA    24.02mA    49.11mA
1.117V    44.09mA    29.25mA    57.87mA
3.6V      56.51mA    38.24mA    72.53mA
[Ramp]
dV/dt_r   0.825312/0.236326n  0.694078/0.384104n  0.914489/0.16543n
dV/dt_f   0.866985/0.28739n  0.690861/0.483223n  0.97033/0.18938n
R_load = 50
[Rising Waveform]
R_fixture = 50
V_fixture = 0
V_fixture_min = 0
V_fixture_max = 0
| Time   V(typ)   V(min)   V(max)
0s        10.34nV    743.5nV    3.708nV
622.9ps   -3.394mV   -57.34nV   -13.76mV
788.4ps   -1.551mV   -1.249mV   755.1mV
862.7ps   185.9mV    -4.572mV   1.189V
931ps     439.6mV    -13.13mV   1.411V
1.128ns   1.118V     65.74mV    1.513V
1.225ns   1.281V     248.6mV    1.52V
1.704ns   1.374V     1.036V     1.524V
2.406ns   1.376V     1.156V     1.524V
50ns      1.376V     1.157V     1.524V
[Rising Waveform]
R_fixture = 50
V_fixture = 1.8
V_fixture_min = 1.66
V_fixture_max = 1.89
| Time   V(typ)   V(min)   V(max)
0s        355mV      508.6mV    272.8mV
512.1ps   352.9mV    505.8mV    308.1mV
544ps     353.4mV    505.2mV    454.4mV
628.5ps   392.4mV    504.2mV    1.463V
784.3ps   1.521V     519.5mV    1.87V
879.8ps   1.753V     682.9mV    1.882V
961.1ps   1.784V     1.2V       1.886V
1.129ns   1.794V     1.618V     1.889V
1.763ns   1.8V       1.658V     1.89V
50ns      1.8V       1.66V      1.89V
[Falling Waveform]
R_fixture = 50
V_fixture = 0
V_fixture_min = 0
V_fixture_max = 0
| Time   V(typ)   V(min)   V(max)
0s        1.376V     1.157V     1.524V
462.7ps   1.374V     1.157V     1.469V
531.2ps   1.355V     1.158V     1.224V
590.1ps   1.302V     1.158V     654.2mV
666.7ps   1.032V     1.15V      95.72mV
799.6ps   149.2mV    1.07V      2.887mV
877.2ps   22.79mV    885.5mV    1.704mV
1.06ns    2.066mV    117.6mV    674.8uV
1.321ns   657.4uV    3.707mV    251.9uV
50ns      10.33nV    823.2nV    3.711nV
[Falling Waveform]
R_fixture = 50
V_fixture = 1.8
V_fixture_min = 1.66
V_fixture_max = 1.89
| Time   V(typ)   V(min)   V(max)
0s        1.8V       1.66V      1.89V
568ps     1.806V     1.66V      1.903V
737.5ps   1.8V       1.663V     1.27V
862.2ps   1.542V     1.672V     618.8mV
941.9ps   1.303V     1.678V     400.7mV
1.137ns   696.3mV    1.53V      294.8mV
1.346ns   435.7mV    1.236V     278.2mV
1.867ns   360.3mV    629.7mV    272.9mV
2.87ns    354.6mV    510.6mV    272.8mV
50ns      355mV      508.6mV    272.8mV
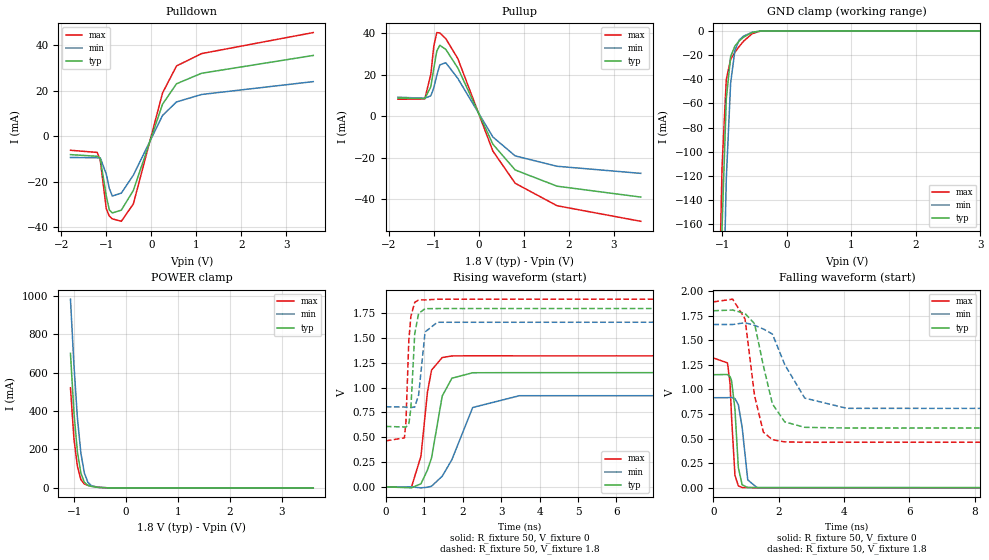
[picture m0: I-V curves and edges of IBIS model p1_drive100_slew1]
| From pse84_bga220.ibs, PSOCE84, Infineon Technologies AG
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[Model] p1_drive100_slew1
Model_type I/O
Polarity  Non-Inverting
Enable   Active-High
Vinl  =  0.54
Vinh  =  1.26
Vmeas =  0.9
Cref  =  15pF
| Capacitance   typ   min   max
C_comp   1.187163e-12   1.148471e-12   1.233738e-12
| Variables   typ   min   max
[GND Clamp Reference]   0   0   0
[POWER Clamp Reference]   1.8   1.66   1.89
[Pulldown Reference]   0   0   0
[Pullup Reference]   1.8   1.66   1.89
[Temperature Range]   25   125   -40
[Voltage Range]   1.8   1.66   1.89
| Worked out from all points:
|   slope of the pulldown table from 0 to 0.27 V, typ, clamps not added: 18 ohm
|   slope of the pullup table from 0 to 0.27 V, typ, clamps not added: 22.7 ohm
|   GND clamp passes 1 mA (typ) near -0.51 V on its own axis
|   POWER clamp passes 1 mA (typ) near -0.47 V on its own axis
|   rising waveform, R_fixture 50, V_fixture 0: 20-80 % time 319ps typ, 513ps min, 228ps max; typ from 0 V to 1.15 V
|   rising waveform, R_fixture 50, V_fixture 1.8: 20-80 % time 96.7ps typ, 116ps min, 88ps max; typ from 0.609 V to 1.8 V
|   falling waveform, R_fixture 50, V_fixture 0: 20-80 % time 127ps typ, 165ps min, 106ps max; typ from 1.15 V to 0 V
|   falling waveform, R_fixture 50, V_fixture 1.8: 20-80 % time 454ps typ, 673ps min, 319ps max; typ from 1.8 V to 0.609 V
[GND Clamp]
| Voltage   I(typ)   I(min)   I(max)
-1.137V   -618.8mA   -753.3mA   -532.4mA
-1.07V    -360.9mA   -497.6mA   -281.1mA
-1.003V   -163.7mA   -277.5mA   -113mA
-936.6mV  -56.21mA   -122.2mA   -40.06mA
-869.7mV  -21.33mA   -43.29mA   -23.66mA
-802.8mV  -12.5mA    -15.96mA   -17.71mA
-735.9mV  -8.345mA   -7.674mA   -12.88mA
-669mV    -5.267mA   -4.349mA   -8.574mA
-535.2mV  -1.314mA   -1.207mA   -2.328mA
-401.4mV  -73.55uA   -132.2uA   -119.3uA
3.6V      0A         0A         0A
[POWER Clamp]
| Voltage   I(typ)   I(min)   I(max)
-1.07V    700.8mA    983.4mA    521.5mA
-1.003V   391.6mA    640.4mA    255.8mA
-936.6mV  187.6mA    365.2mA    112.5mA
-869.7mV  77.29mA    181mA      42.73mA
-802.8mV  28.91mA    77.52mA    19.98mA
-735.9mV  13.13mA    29.19mA    13.35mA
-669mV    7.755mA    11.55mA    8.955mA
-535.2mV  2.356mA    2.862mA    2.667mA
-334.5mV  34.33uA    127.4uA    15.58uA
3.6V      0A         0A         0A
[Pullup]
| Voltage   I(typ)   I(min)   I(max)
-1.8V     8.819mA    9.225mA    8.256mA
-1.204V   8.594mA    8.734mA    8.362mA
-1.07V    14.25mA    9.887mA    20.21mA
-1.003V   23.19mA    13.79mA    33.91mA
-936.6mV  31.46mA    19.78mA    40.38mA
-869.7mV  34.26mA    24.82mA    40.18mA
-735.9mV  32.26mA    25.83mA    37.45mA
-468.3mV  23.29mA    18.27mA    27.8mA
310.3mV   -13.41mA   -9.935mA   -16.71mA
806.9mV   -25.84mA   -19.05mA   -32.25mA
1.738V    -33.65mA   -24.05mA   -43.07mA
3.6V      -38.9mA    -27.47mA   -50.57mA
[Pulldown]
| Voltage   I(typ)   I(min)   I(max)
-1.8V     -8.09mA    -9.336mA   -6.18mA
-1.204V   -8.819mA   -9.493mA   -7.128mA
-1.137V   -9.825mA   -9.491mA   -10.67mA
-1.003V   -26.32mA   -16.67mA   -31.9mA
-936.6mV  -32.37mA   -22.89mA   -35.09mA
-869.7mV  -33.73mA   -26.29mA   -36.32mA
-669mV    -32.52mA   -25.02mA   -37.41mA
-401.4mV  -23.83mA   -17.14mA   -29.77mA
248.3mV   14.08mA    9.149mA    19.02mA
558.6mV   23.07mA    15.08mA    30.9mA
1.117V    27.69mA    18.36mA    36.34mA
3.6V      35.52mA    24.01mA    45.58mA
[Ramp]
dV/dt_r   0.690092/0.319427n  0.549749/0.512845n  0.791747/0.228068n
dV/dt_f   0.714838/0.45378n  0.512301/0.673147n  0.855898/0.318905n
R_load = 50
[Rising Waveform]
R_fixture = 50
V_fixture = 0
V_fixture_min = 0
V_fixture_max = 0
| Time   V(typ)   V(min)   V(max)
0s        14.93nV    1.041uV    5.447nV
665.2ps   -8.95mV    -13.1uV    -3.477mV
913.9ps   31.43mV    -9.526mV   309.5mV
1.082ns   169.2mV    -3.113mV   952.7mV
1.19ns    293.3mV    7.294mV    1.176V
1.467ns   915mV      107.7mV    1.302V
1.719ns   1.094V     274.3mV    1.318V
2.26ns    1.149V     799.2mV    1.32V
3.475ns   1.15V      917.9mV    1.319V
50ns      1.15V      916.2mV    1.32V
[Rising Waveform]
R_fixture = 50
V_fixture = 1.8
V_fixture_min = 1.66
V_fixture_max = 1.89
| Time   V(typ)   V(min)   V(max)
0s        608.6mV    806.2mV    463.5mV
483.4ps   603.2mV    804.3mV    494.2mV
523.1ps   602.6mV    802.4mV    657.1mV
597.8ps   630.3mV    800mV      1.472V
651.6ps   792.8mV    798.7mV    1.717V
751.8ps   1.543V     804.4mV    1.858V
853.7ps   1.746V     927mV      1.882V
1.021ns   1.794V     1.56V      1.882V
1.341ns   1.795V     1.657V     1.889V
50ns      1.8V       1.66V      1.89V
[Falling Waveform]
R_fixture = 50
V_fixture = 0
V_fixture_min = 0
V_fixture_max = 0
| Time   V(typ)   V(min)   V(max)
0s        1.15V      916.2mV    1.32V
432.4ps   1.152V     916.4mV    1.27V
510.5ps   1.13V      918.3mV    1.062V
557.6ps   1.089V     919mV      714.9mV
660.8ps   798.2mV    907.5mV    128.1mV
764.4ps   205.6mV    845.1mV    20.56mV
881ps     31.51mV    615mV      2.654mV
1.053ns   2.562mV    80.27mV    3.695mV
1.342ns   3.157mV    1.904mV    1.034mV
50ns      14.9nV     1.047uV    5.432nV
[Falling Waveform]
R_fixture = 50
V_fixture = 1.8
V_fixture_min = 1.66
V_fixture_max = 1.89
| Time   V(typ)   V(min)   V(max)
0s        1.8V       1.66V      1.89V
590.9ps   1.807V     1.66V      1.918V
970ps     1.772V     1.678V     1.716V
1.262ns   1.668V     1.652V     934.9mV
1.532ns   1.239V     1.614V     565.2mV
1.808ns   853.1mV    1.563V     489.4mV
2.184ns   670.5mV    1.253V     467.5mV
2.796ns   615.1mV    912.3mV    463.3mV
4.088ns   608.1mV    808.1mV    463.5mV
50ns      608.6mV    806.2mV    463.5mV
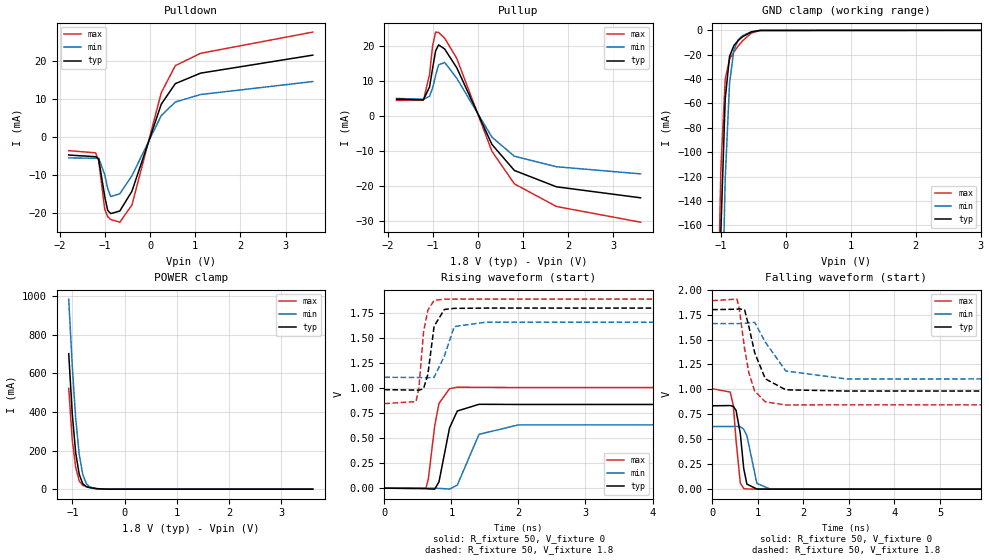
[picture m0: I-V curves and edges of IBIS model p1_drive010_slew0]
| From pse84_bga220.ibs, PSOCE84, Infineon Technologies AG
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[Model] p1_drive010_slew0
Model_type I/O
Polarity  Non-Inverting
Enable   Active-High
Vinl  =  0.54
Vinh  =  1.26
Vmeas =  0.9
Cref  =  15pF
| Capacitance   typ   min   max
C_comp   1.187163e-12   1.148471e-12   1.233738e-12
| Variables   typ   min   max
[GND Clamp Reference]   0   0   0
[POWER Clamp Reference]   1.8   1.66   1.89
[Pulldown Reference]   0   0   0
[Pullup Reference]   1.8   1.66   1.89
[Temperature Range]   25   125   -40
[Voltage Range]   1.8   1.66   1.89
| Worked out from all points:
|   slope of the pulldown table from 0 to 0.27 V, typ, clamps not added: 29.8 ohm
|   slope of the pullup table from 0 to 0.27 V, typ, clamps not added: 38.1 ohm
|   GND clamp passes 1 mA (typ) near -0.51 V on its own axis
|   POWER clamp passes 1 mA (typ) near -0.47 V on its own axis
|   rising waveform, R_fixture 50, V_fixture 0: 20-80 % time 155ps typ, 221ps min, 121ps max; typ from 0 V to 0.836 V
|   rising waveform, R_fixture 50, V_fixture 1.8: 20-80 % time 97.8ps typ, 115ps min, 90ps max; typ from 0.985 V to 1.8 V
|   falling waveform, R_fixture 50, V_fixture 0: 20-80 % time 117ps typ, 148ps min, 100ps max; typ from 0.836 V to 0 V
|   falling waveform, R_fixture 50, V_fixture 1.8: 20-80 % time 307ps typ, 422ps min, 240ps max; typ from 1.8 V to 0.985 V
[GND Clamp]
| Voltage   I(typ)   I(min)   I(max)
-1.137V   -618.8mA   -753.3mA   -532.4mA
-1.07V    -360.9mA   -497.6mA   -281.1mA
-1.003V   -163.7mA   -277.5mA   -113mA
-936.6mV  -56.21mA   -122.2mA   -40.06mA
-869.7mV  -21.33mA   -43.29mA   -23.66mA
-802.8mV  -12.5mA    -15.96mA   -17.71mA
-735.9mV  -8.345mA   -7.674mA   -12.88mA
-669mV    -5.267mA   -4.349mA   -8.574mA
-535.2mV  -1.314mA   -1.207mA   -2.328mA
-401.4mV  -73.55uA   -132.2uA   -119.3uA
3.6V      0A         0A         0A
[POWER Clamp]
| Voltage   I(typ)   I(min)   I(max)
-1.07V    700.8mA    983.4mA    521.5mA
-1.003V   391.6mA    640.4mA    255.8mA
-936.6mV  187.6mA    365.2mA    112.5mA
-869.7mV  77.29mA    181mA      42.73mA
-802.8mV  28.91mA    77.52mA    19.98mA
-735.9mV  13.13mA    29.19mA    13.35mA
-669mV    7.755mA    11.55mA    8.955mA
-535.2mV  2.356mA    2.862mA    2.667mA
-334.5mV  34.33uA    127.4uA    15.58uA
3.6V      0A         0A         0A
[Pullup]
| Voltage   I(typ)   I(min)   I(max)
-1.8V     4.891mA    5.128mA    4.561mA
-1.204V   4.768mA    4.867mA    4.68mA
-1.07V    8.4mA      5.737mA    11.97mA
-1.003V   13.68mA    8.09mA     20.12mA
-936.6mV  18.66mA    11.63mA    24.06mA
-869.7mV  20.41mA    14.7mA     23.96mA
-735.9mV  19.24mA    15.4mA     22.32mA
-468.3mV  13.88mA    10.9mA     16.56mA
310.3mV   -7.998mA   -5.929mA   -9.953mA
806.9mV   -15.43mA   -11.38mA   -19.25mA
1.738V    -20.1mA    -14.37mA   -25.72mA
3.6V      -23.24mA   -16.41mA   -30.2mA
[Pulldown]
| Voltage   I(typ)   I(min)   I(max)
-1.8V     -4.873mA   -5.622mA   -3.722mA
-1.204V   -5.316mA   -5.72mA    -4.296mA
-1.137V   -5.907mA   -5.72mA    -6.41mA
-1.003V   -15.83mA   -10.02mA   -19.18mA
-936.6mV  -19.47mA   -13.76mA   -21.1mA
-869.7mV  -20.29mA   -15.81mA   -21.85mA
-669mV    -19.6mA    -15.06mA   -22.55mA
-401.4mV  -14.4mA    -10.33mA   -18.03mA
248.3mV   8.526mA    5.522mA    11.56mA
558.6mV   13.92mA    9.081mA    18.66mA
1.117V    16.68mA    11.05mA    21.9mA
3.6V      21.42mA    14.47mA    27.49mA
[Ramp]
dV/dt_r   0.501484/0.155457n  0.376798/0.220732n  0.603978/0.121035n
dV/dt_f   0.489298/0.307347n  0.331003/0.422303n  0.626792/0.239685n
R_load = 50
[Rising Waveform]
R_fixture = 50
V_fixture = 0
V_fixture_min = 0
V_fixture_max = 0
| Time   V(typ)   V(min)   V(max)
0s        21.31nV    1.424uV    7.959nV
618.3ps   -3.083mV   -2.451uV   -4.274mV
656.3ps   -7.097mV   -13.45uV   92.88mV
750.4ps   -9.765mV   -391.7uV   621.8mV
814.7ps   63.57mV    -1.778mV   847.6mV
972.5ps   603.2mV    -8.705mV   994.4mV
1.088ns   771.4mV    30.92mV    1.009V
1.412ns   838.3mV    538.1mV    1.008V
2.002ns   836.7mV    632.9mV    1.006V
50ns      835.8mV    628mV      1.007V
[Rising Waveform]
R_fixture = 50
V_fixture = 1.8
V_fixture_min = 1.66
V_fixture_max = 1.89
| Time   V(typ)   V(min)   V(max)
0s        984.5mV    1.108V     845.3mV
472.2ps   980.4mV    1.107V     865.4mV
515.5ps   979.9mV    1.106V     1.002V
583.6ps   993.3mV    1.105V     1.556V
648.7ps   1.136V     1.104V     1.779V
742.2ps   1.619V     1.107V     1.877V
895.1ps   1.786V     1.32V      1.889V
1.042ns   1.797V     1.615V     1.89V
1.514ns   1.8V       1.659V     1.89V
50ns      1.8V       1.66V      1.89V
[Falling Waveform]
R_fixture = 50
V_fixture = 0
V_fixture_min = 0
V_fixture_max = 0
| Time   V(typ)   V(min)   V(max)
0s        835.8mV    628mV      1.007V
396.5ps   838.3mV    628mV      973.7mV
463.6ps   829.6mV    628.9mV    837.3mV
523.3ps   790.2mV    630.4mV    489.4mV
616.8ps   558.2mV    625.4mV    60.85mV
691.3ps   208.4mV    599.9mV    6.076mV
761.9ps   50.34mV    535.7mV    1.998mV
980.1ps   1.449mV    57.79mV    520.8uV
1.27ns    378.2uV    1.599mV    217.5uV
50ns      21.26nV    1.512uV    7.935nV
[Falling Waveform]
R_fixture = 50
V_fixture = 1.8
V_fixture_min = 1.66
V_fixture_max = 1.89
| Time   V(typ)   V(min)   V(max)
0s        1.8V       1.66V      1.89V
543ps     1.804V     1.66V      1.906V
594.1ps   1.809V     1.66V      1.81V
712.3ps   1.796V     1.662V     1.404V
805.2ps   1.63V      1.666V     1.165V
932.5ps   1.368V     1.673V     983.1mV
1.166ns   1.106V     1.474V     875.4mV
1.615ns   996.2mV    1.185V     844.1mV
2.946ns   983.8mV    1.105V     845.6mV
50ns      984.5mV    1.108V     845.3mV
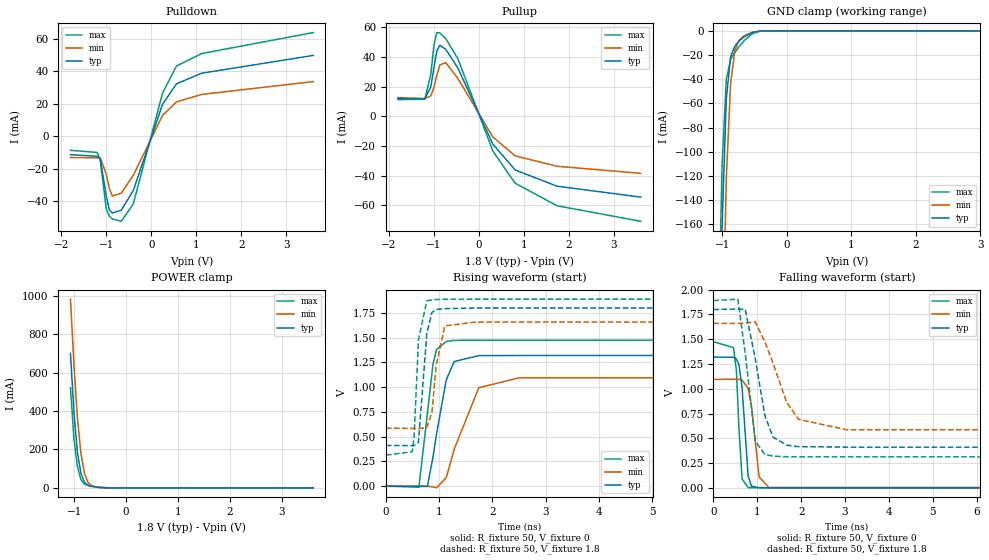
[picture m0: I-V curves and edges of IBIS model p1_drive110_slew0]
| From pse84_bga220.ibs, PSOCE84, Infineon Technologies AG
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[Model] p1_drive110_slew0
Model_type I/O
Polarity  Non-Inverting
Enable   Active-High
Vinl  =  0.54
Vinh  =  1.26
Vmeas =  0.9
Cref  =  15pF
| Capacitance   typ   min   max
C_comp   1.187163e-12   1.148471e-12   1.233738e-12
| Variables   typ   min   max
[GND Clamp Reference]   0   0   0
[POWER Clamp Reference]   1.8   1.66   1.89
[Pulldown Reference]   0   0   0
[Pullup Reference]   1.8   1.66   1.89
[Temperature Range]   25   125   -40
[Voltage Range]   1.8   1.66   1.89
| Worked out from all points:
|   slope of the pulldown table from 0 to 0.27 V, typ, clamps not added: 12.9 ohm
|   slope of the pullup table from 0 to 0.27 V, typ, clamps not added: 16.3 ohm
|   GND clamp passes 1 mA (typ) near -0.51 V on its own axis
|   POWER clamp passes 1 mA (typ) near -0.47 V on its own axis
|   rising waveform, R_fixture 50, V_fixture 0: 20-80 % time 249ps typ, 406ps min, 174ps max; typ from 0 V to 1.32 V
|   rising waveform, R_fixture 50, V_fixture 1.8: 20-80 % time 94.9ps typ, 114ps min, 86.5ps max; typ from 0.411 V to 1.8 V
|   falling waveform, R_fixture 50, V_fixture 0: 20-80 % time 112ps typ, 151ps min, 89ps max; typ from 1.32 V to 0 V
|   falling waveform, R_fixture 50, V_fixture 1.8: 20-80 % time 337ps typ, 544ps min, 224ps max; typ from 1.8 V to 0.411 V
[GND Clamp]
| Voltage   I(typ)   I(min)   I(max)
-1.137V   -618.8mA   -753.3mA   -532.4mA
-1.07V    -360.9mA   -497.6mA   -281.1mA
-1.003V   -163.7mA   -277.5mA   -113mA
-936.6mV  -56.21mA   -122.2mA   -40.06mA
-869.7mV  -21.33mA   -43.29mA   -23.66mA
-802.8mV  -12.5mA    -15.96mA   -17.71mA
-735.9mV  -8.345mA   -7.674mA   -12.88mA
-669mV    -5.267mA   -4.349mA   -8.574mA
-535.2mV  -1.314mA   -1.207mA   -2.328mA
-401.4mV  -73.55uA   -132.2uA   -119.3uA
3.6V      0A         0A         0A
[POWER Clamp]
| Voltage   I(typ)   I(min)   I(max)
-1.07V    700.8mA    983.4mA    521.5mA
-1.003V   391.6mA    640.4mA    255.8mA
-936.6mV  187.6mA    365.2mA    112.5mA
-869.7mV  77.29mA    181mA      42.73mA
-802.8mV  28.91mA    77.52mA    19.98mA
-735.9mV  13.13mA    29.19mA    13.35mA
-669mV    7.755mA    11.55mA    8.955mA
-535.2mV  2.356mA    2.862mA    2.667mA
-334.5mV  34.33uA    127.4uA    15.58uA
3.6V      0A         0A         0A
[Pullup]
| Voltage   I(typ)   I(min)   I(max)
-1.8V     12.09mA    12.65mA    11.3mA
-1.204V   11.78mA    11.99mA    11.48mA
-1.07V    19.86mA    13.72mA    28.2mA
-1.003V   32.33mA    19.19mA    47.33mA
-936.6mV  43.91mA    27.54mA    56.42mA
-869.7mV  47.86mA    34.63mA    56.15mA
-735.9mV  45.08mA    36.1mA     52.32mA
-468.3mV  32.54mA    25.54mA    38.83mA
310.3mV   -18.74mA   -13.89mA   -23.34mA
806.9mV   -36.12mA   -26.64mA   -45.07mA
1.738V    -47.05mA   -33.63mA   -60.21mA
3.6V      -54.39mA   -38.4mA    -70.69mA
[Pulldown]
| Voltage   I(typ)   I(min)   I(max)
-1.8V     -11.32mA   -13.07mA   -8.649mA
-1.204V   -12.34mA   -13.28mA   -9.975mA
-1.137V   -13.74mA   -13.28mA   -14.92mA
-1.003V   -36.81mA   -23.32mA   -44.61mA
-936.6mV  -45.26mA   -32.01mA   -49.07mA
-869.7mV  -47.16mA   -36.77mA   -50.78mA
-669mV    -45.45mA   -34.98mA   -52.27mA
-401.4mV  -33.26mA   -23.95mA   -41.52mA
248.3mV   19.63mA    12.78mA    26.5mA
558.6mV   32.22mA    21.08mA    43.15mA
1.117V    38.7mA     25.67mA    50.79mA
3.6V      49.63mA    33.56mA    63.68mA
[Ramp]
dV/dt_r   0.792037/0.249317n  0.65707/0.405629n  0.88488/0.173951n
dV/dt_f   0.833231/0.336504n  0.644608/0.54373n  0.946072/0.223595n
R_load = 50
[Rising Waveform]
R_fixture = 50
V_fixture = 0
V_fixture_min = 0
V_fixture_max = 0
| Time   V(typ)   V(min)   V(max)
0s        11.49nV    820.1nV    4.137nV
620ps     -3.795mV   405.6nV    -10.37mV
779.9ps   -3.381mV   -1.123mV   736mV
885.2ps   296mV      -7.401mV   1.235V
951ps     527.1mV    -17.57mV   1.38V
1.134ns   1.075V     87.25mV    1.462V
1.282ns   1.259V     371.9mV    1.473V
1.743ns   1.319V     994.6mV    1.475V
2.505ns   1.32V      1.095V     1.475V
50ns      1.32V      1.095V     1.475V
[Rising Waveform]
R_fixture = 50
V_fixture = 1.8
V_fixture_min = 1.66
V_fixture_max = 1.89
| Time   V(typ)   V(min)   V(max)
0s        411.3mV    585.7mV    313.2mV
497.1ps   409.1mV    583.7mV    347.8mV
531.1ps   409.2mV    582.8mV    507.8mV
611.3ps   442.4mV    581.7mV    1.476V
768.1ps   1.539V     592.9mV    1.872V
863.9ps   1.755V     740.9mV    1.883V
944.1ps   1.786V     1.219V     1.886V
1.108ns   1.794V     1.62V      1.889V
1.682ns   1.8V       1.658V     1.89V
50ns      1.8V       1.66V      1.89V
[Falling Waveform]
R_fixture = 50
V_fixture = 0
V_fixture_min = 0
V_fixture_max = 0
| Time   V(typ)   V(min)   V(max)
0s        1.32V      1.095V     1.475V
458.6ps   1.318V     1.096V     1.416V
524.2ps   1.299V     1.097V     1.187V
583ps     1.244V     1.096V     599.6mV
654.5ps   1.008V     1.088V     89.24mV
791.9ps   120mV      1.004V     2.87mV
868ps     17.14mV    827.3mV    1.732mV
1.042ns   2.175mV    110.6mV    764.6uV
1.264ns   835.1uV    4.032mV    323uV
50ns      11.46nV    894.7nV    4.128nV
[Falling Waveform]
R_fixture = 50
V_fixture = 1.8
V_fixture_min = 1.66
V_fixture_max = 1.89
| Time   V(typ)   V(min)   V(max)
0s        1.8V       1.66V      1.89V
558.4ps   1.805V     1.66V      1.905V
726ps     1.802V     1.663V     1.355V
953.8ps   1.304V     1.675V     473.5mV
1.175ns   727.1mV    1.472V     336.3mV
1.358ns   512.1mV    1.26V      320.2mV
1.672ns   431.1mV    860.7mV    314mV
1.941ns   416.1mV    691.8mV    313.1mV
3.042ns   411mV      586.1mV    313.3mV
50ns      411.3mV    585.7mV    313.2mV
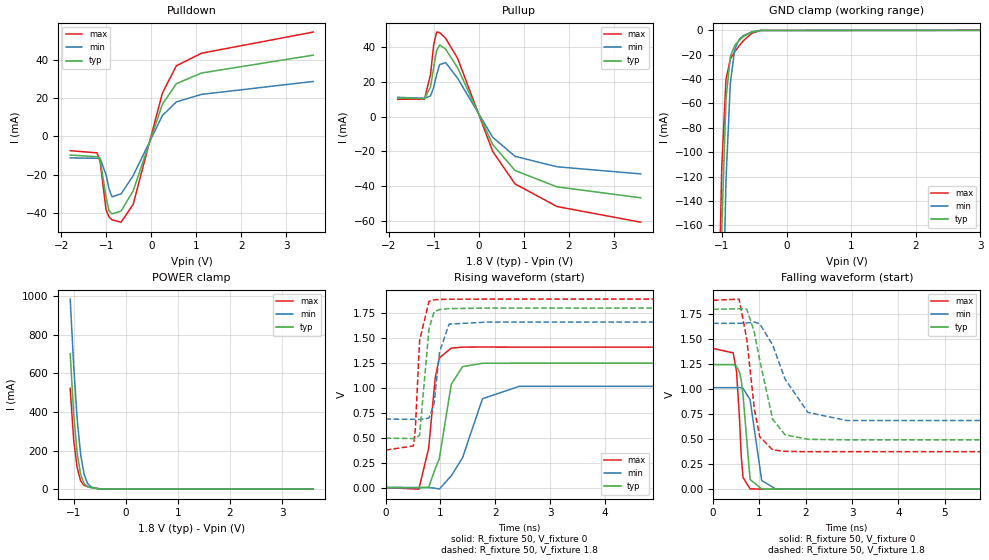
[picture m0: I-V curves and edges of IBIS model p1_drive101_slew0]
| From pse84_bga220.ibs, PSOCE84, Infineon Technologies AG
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[Model] p1_drive101_slew0
Model_type I/O
Polarity  Non-Inverting
Enable   Active-High
Vinl  =  0.54
Vinh  =  1.26
Vmeas =  0.9
Cref  =  15pF
| Capacitance   typ   min   max
C_comp   1.187163e-12   1.148471e-12   1.233738e-12
| Variables   typ   min   max
[GND Clamp Reference]   0   0   0
[POWER Clamp Reference]   1.8   1.66   1.89
[Pulldown Reference]   0   0   0
[Pullup Reference]   1.8   1.66   1.89
[Temperature Range]   25   125   -40
[Voltage Range]   1.8   1.66   1.89
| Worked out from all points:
|   slope of the pulldown table from 0 to 0.27 V, typ, clamps not added: 15.1 ohm
|   slope of the pullup table from 0 to 0.27 V, typ, clamps not added: 19 ohm
|   GND clamp passes 1 mA (typ) near -0.51 V on its own axis
|   POWER clamp passes 1 mA (typ) near -0.47 V on its own axis
|   rising waveform, R_fixture 50, V_fixture 0: 20-80 % time 224ps typ, 355ps min, 160ps max; typ from 0 V to 1.25 V
|   rising waveform, R_fixture 50, V_fixture 1.8: 20-80 % time 96.6ps typ, 117ps min, 86.3ps max; typ from 0.495 V to 1.8 V
|   falling waveform, R_fixture 50, V_fixture 0: 20-80 % time 123ps typ, 165ps min, 98.3ps max; typ from 1.25 V to 0 V
|   falling waveform, R_fixture 50, V_fixture 1.8: 20-80 % time 340ps typ, 531ps min, 227ps max; typ from 1.8 V to 0.495 V
[GND Clamp]
| Voltage   I(typ)   I(min)   I(max)
-1.137V   -618.8mA   -753.3mA   -532.4mA
-1.07V    -360.9mA   -497.6mA   -281.1mA
-1.003V   -163.7mA   -277.5mA   -113mA
-936.6mV  -56.21mA   -122.2mA   -40.06mA
-869.7mV  -21.33mA   -43.29mA   -23.66mA
-802.8mV  -12.5mA    -15.96mA   -17.71mA
-735.9mV  -8.345mA   -7.674mA   -12.88mA
-669mV    -5.267mA   -4.349mA   -8.574mA
-535.2mV  -1.314mA   -1.207mA   -2.328mA
-401.4mV  -73.55uA   -132.2uA   -119.3uA
3.6V      0A         0A         0A
[POWER Clamp]
| Voltage   I(typ)   I(min)   I(max)
-1.07V    700.8mA    983.4mA    521.5mA
-1.003V   391.6mA    640.4mA    255.8mA
-936.6mV  187.6mA    365.2mA    112.5mA
-869.7mV  77.29mA    181mA      42.73mA
-802.8mV  28.91mA    77.52mA    19.98mA
-735.9mV  13.13mA    29.19mA    13.35mA
-669mV    7.755mA    11.55mA    8.955mA
-535.2mV  2.356mA    2.862mA    2.667mA
-334.5mV  34.33uA    127.4uA    15.58uA
3.6V      0A         0A         0A
[Pullup]
| Voltage   I(typ)   I(min)   I(max)
-1.8V     10.52mA    11.01mA    9.844mA
-1.204V   10.25mA    10.42mA    9.975mA
-1.07V    17.07mA    11.83mA    24.22mA
-1.003V   27.79mA    16.51mA    40.63mA
-936.6mV  37.69mA    23.69mA    48.38mA
-869.7mV  41.04mA    29.73mA    48.13mA
-735.9mV  38.64mA    30.94mA    44.85mA
-468.3mV  27.88mA    21.89mA    33.28mA
310.3mV   -16.06mA   -11.9mA    -20mA
806.9mV   -30.95mA   -22.82mA   -38.62mA
1.738V    -40.31mA   -28.81mA   -51.59mA
3.6V      -46.6mA    -32.9mA    -60.57mA
[Pulldown]
| Voltage   I(typ)   I(min)   I(max)
-1.8V     -9.699mA   -11.19mA   -7.41mA
-1.204V   -10.57mA   -11.38mA   -8.544mA
-1.137V   -11.77mA   -11.37mA   -12.78mA
-1.003V   -31.52mA   -19.96mA   -38.21mA
-936.6mV  -38.75mA   -27.41mA   -42.02mA
-869.7mV  -40.37mA   -31.48mA   -43.48mA
-669mV    -38.89mA   -29.93mA   -44.71mA
-401.4mV  -28.41mA   -20.48mA   -35.45mA
248.3mV   16.76mA    10.92mA    22.59mA
558.6mV   27.54mA    18.02mA    36.87mA
1.117V    33.09mA    21.95mA    43.43mA
3.6V      42.42mA    28.69mA    54.44mA
[Ramp]
dV/dt_r   0.74802/0.224318n  0.609574/0.354545n  0.845146/0.159817n
dV/dt_f   0.783247/0.340059n  0.583984/0.530953n  0.90876/0.226859n
R_load = 50
[Rising Waveform]
R_fixture = 50
V_fixture = 0
V_fixture_min = 0
V_fixture_max = 0
| Time   V(typ)   V(min)   V(max)
0s        13.06nV    920.5nV    4.741nV
606.9ps   -1.88mV    7.342uV    -16.61mV
786.6ps   2.126mV    -837.3uV   394.3mV
906.7ps   190.8mV    -6.578mV   1.104V
980.6ps   290.2mV    -15.61mV   1.3V
1.199ns   1.036V     117.5mV    1.398V
1.404ns   1.212V     298.8mV    1.408V
1.768ns   1.246V     890.2mV    1.409V
2.438ns   1.247V     1.015V     1.408V
50ns      1.247V     1.016V     1.409V
[Rising Waveform]
R_fixture = 50
V_fixture = 1.8
V_fixture_min = 1.66
V_fixture_max = 1.89
| Time   V(typ)   V(min)   V(max)
0s        494.6mV    686.7mV    375.4mV
507.4ps   491mV      683.8mV    416.9mV
543ps     491.2mV    682.6mV    581.7mV
620.4ps   524.4mV    681.2mV    1.472V
792.2ps   1.592V     696mV      1.867V
886.3ps   1.763V     844.2mV    1.882V
984.5ps   1.784V     1.359V     1.886V
1.159ns   1.794V     1.639V     1.889V
1.867ns   1.8V       1.659V     1.89V
50ns      1.8V       1.66V      1.89V
[Falling Waveform]
R_fixture = 50
V_fixture = 0
V_fixture_min = 0
V_fixture_max = 0
| Time   V(typ)   V(min)   V(max)
0s        1.247V     1.016V     1.409V
434.6ps   1.247V     1.016V     1.364V
507.4ps   1.229V     1.017V     1.174V
571ps     1.171V     1.017V     702.9mV
607.9ps   1.091V     1.015V     333.2mV
648ps     936mV      1.009V     116.2mV
799.2ps   97.01mV    896.9mV    3.087mV
1.05ns    2.231mV    87.02mV    733uV
1.347ns   616.7uV    3.171mV    259.7uV
50ns      13.04nV    990.5nV    4.731nV
[Falling Waveform]
R_fixture = 50
V_fixture = 1.8
V_fixture_min = 1.66
V_fixture_max = 1.89
| Time   V(typ)   V(min)   V(max)
0s        1.8V       1.66V      1.89V
561.7ps   1.806V     1.66V      1.903V
728.8ps   1.802V     1.663V     1.501V
889.2ps   1.574V     1.673V     809.5mV
1.008ns   1.289V     1.656V     523.9mV
1.289ns   698.1mV    1.441V     393.1mV
1.555ns   544mV      1.101V     378.4mV
2.05ns    499.1mV    767.9mV    375.1mV
2.887ns   494mV      687.3mV    375.4mV
50ns      494.6mV    686.7mV    375.4mV
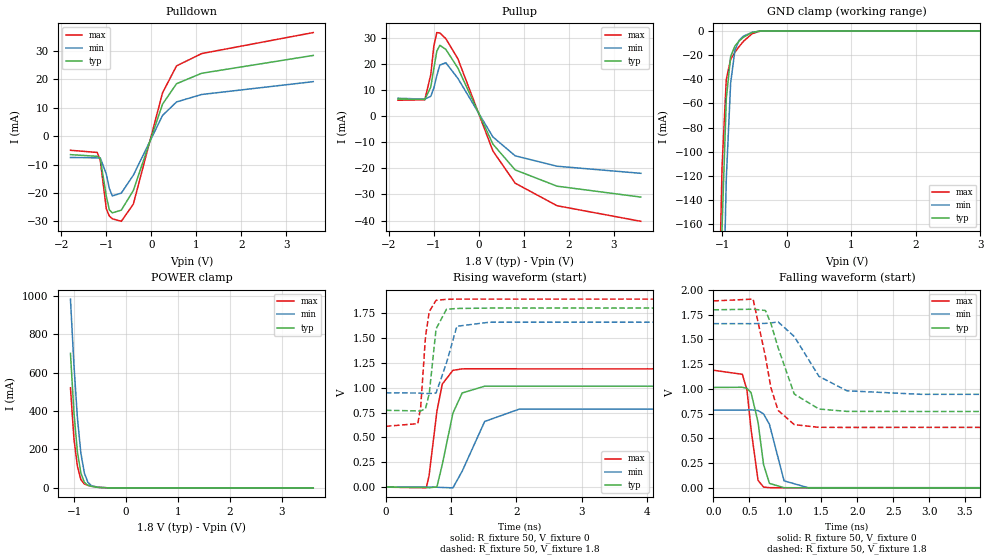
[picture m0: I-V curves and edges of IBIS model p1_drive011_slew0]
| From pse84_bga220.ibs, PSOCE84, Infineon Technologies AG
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[Model] p1_drive011_slew0
Model_type I/O
Polarity  Non-Inverting
Enable   Active-High
Vinl  =  0.54
Vinh  =  1.26
Vmeas =  0.9
Cref  =  15pF
| Capacitance   typ   min   max
C_comp   1.187163e-12   1.148471e-12   1.233738e-12
| Variables   typ   min   max
[GND Clamp Reference]   0   0   0
[POWER Clamp Reference]   1.8   1.66   1.89
[Pulldown Reference]   0   0   0
[Pullup Reference]   1.8   1.66   1.89
[Temperature Range]   25   125   -40
[Voltage Range]   1.8   1.66   1.89
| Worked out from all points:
|   slope of the pulldown table from 0 to 0.27 V, typ, clamps not added: 22.5 ohm
|   slope of the pullup table from 0 to 0.27 V, typ, clamps not added: 28.6 ohm
|   GND clamp passes 1 mA (typ) near -0.51 V on its own axis
|   POWER clamp passes 1 mA (typ) near -0.47 V on its own axis
|   rising waveform, R_fixture 50, V_fixture 0: 20-80 % time 203ps typ, 310ps min, 148ps max; typ from 0 V to 1.01 V
|   rising waveform, R_fixture 50, V_fixture 1.8: 20-80 % time 98.8ps typ, 117ps min, 89.5ps max; typ from 0.772 V to 1.8 V
|   falling waveform, R_fixture 50, V_fixture 0: 20-80 % time 117ps typ, 147ps min, 101ps max; typ from 1.01 V to 0 V
|   falling waveform, R_fixture 50, V_fixture 1.8: 20-80 % time 270ps typ, 387ps min, 199ps max; typ from 1.8 V to 0.772 V
[GND Clamp]
| Voltage   I(typ)   I(min)   I(max)
-1.137V   -618.8mA   -753.3mA   -532.4mA
-1.07V    -360.9mA   -497.6mA   -281.1mA
-1.003V   -163.7mA   -277.5mA   -113mA
-936.6mV  -56.21mA   -122.2mA   -40.06mA
-869.7mV  -21.33mA   -43.29mA   -23.66mA
-802.8mV  -12.5mA    -15.96mA   -17.71mA
-735.9mV  -8.345mA   -7.674mA   -12.88mA
-669mV    -5.267mA   -4.349mA   -8.574mA
-535.2mV  -1.314mA   -1.207mA   -2.328mA
-401.4mV  -73.55uA   -132.2uA   -119.3uA
3.6V      0A         0A         0A
[POWER Clamp]
| Voltage   I(typ)   I(min)   I(max)
-1.07V    700.8mA    983.4mA    521.5mA
-1.003V   391.6mA    640.4mA    255.8mA
-936.6mV  187.6mA    365.2mA    112.5mA
-869.7mV  77.29mA    181mA      42.73mA
-802.8mV  28.91mA    77.52mA    19.98mA
-735.9mV  13.13mA    29.19mA    13.35mA
-669mV    7.755mA    11.55mA    8.955mA
-535.2mV  2.356mA    2.862mA    2.667mA
-334.5mV  34.33uA    127.4uA    15.58uA
3.6V      0A         0A         0A
[Pullup]
| Voltage   I(typ)   I(min)   I(max)
-1.8V     6.598mA    6.914mA    6.156mA
-1.204V   6.428mA    6.559mA    6.301mA
-1.07V    11.23mA    7.685mA    16.01mA
-1.003V   18.3mA     10.82mA    26.88mA
-936.6mV  24.93mA    15.55mA    32.1mA
-869.7mV  27.23mA    19.63mA    31.95mA
-735.9mV  25.66mA    20.54mA    29.78mA
-468.3mV  18.51mA    14.54mA    22.08mA
310.3mV   -10.66mA   -7.904mA   -13.27mA
806.9mV   -20.57mA   -15.17mA   -25.67mA
1.738V    -26.81mA   -19.16mA   -34.31mA
3.6V      -30.99mA   -21.88mA   -40.28mA
[Pulldown]
| Voltage   I(typ)   I(min)   I(max)
-1.8V     -6.491mA   -7.49mA    -4.957mA
-1.204V   -7.079mA   -7.618mA   -5.722mA
-1.137V   -7.867mA   -7.617mA   -8.539mA
-1.003V   -21.08mA   -13.35mA   -25.54mA
-936.6mV  -25.92mA   -18.33mA   -28.1mA
-869.7mV  -27.01mA   -21.06mA   -29.09mA
-669mV    -26.07mA   -20.04mA   -29.99mA
-401.4mV  -19.12mA   -13.74mA   -23.92mA
248.3mV   11.31mA    7.339mA    15.31mA
558.6mV   18.5mA     12.08mA    24.79mA
1.117V    22.19mA    14.71mA    29.13mA
3.6V      28.48mA    19.24mA    36.54mA
[Ramp]
dV/dt_r   0.608838/0.202795n  0.471563/0.310377n  0.713647/0.14801n
dV/dt_f   0.616578/0.270219n  0.426943/0.38688n  0.767235/0.198544n
R_load = 50
[Rising Waveform]
R_fixture = 50
V_fixture = 0
V_fixture_min = 0
V_fixture_max = 0
| Time   V(typ)   V(min)   V(max)
0s        17.55nV    1.202uV    6.463nV
620.4ps   -2.444mV   865.6nV    -6.463mV
662.9ps   -6.105mV   -10.65uV   116.6mV
782.9ps   2.875mV    -680.8uV   763.7mV
865.2ps   227.9mV    -3.292mV   1.036V
1.028ns   743.4mV    -7.084mV   1.174V
1.17ns    946.6mV    160.2mV    1.189V
1.515ns   1.015V     660.3mV    1.19V
2.047ns   1.015V     784.9mV    1.189V
50ns      1.015V     785.9mV    1.189V
[Rising Waveform]
R_fixture = 50
V_fixture = 1.8
V_fixture_min = 1.66
V_fixture_max = 1.89
| Time   V(typ)   V(min)   V(max)
0s        772.4mV    948.4mV    611.3mV
490.1ps   766.4mV    946.1mV    638.6mV
534ps     765.8mV    944.1mV    803.3mV
607.9ps   789.3mV    942.2mV    1.514V
665.5ps   940.8mV    941.4mV    1.764V
769.8ps   1.591V     946.3mV    1.878V
929.5ps   1.788V     1.249V     1.888V
1.089ns   1.796V     1.617V     1.89V
1.59ns    1.8V       1.658V     1.89V
50ns      1.8V       1.66V      1.89V
[Falling Waveform]
R_fixture = 50
V_fixture = 0
V_fixture_min = 0
V_fixture_max = 0
| Time   V(typ)   V(min)   V(max)
0s        1.015V     785.9mV    1.189V
403ps     1.017V     785.9mV    1.148V
467.4ps   1.006V     787.1mV    988.7mV
523.9ps   963.4mV    788.5mV    593.1mV
621.5ps   662.7mV    781.7mV    75.72mV
697.8ps   236.5mV    747.9mV    8.158mV
779.8ps   45.15mV    641.5mV    2.149mV
983.2ps   1.938mV    70.9mV     509uV
1.314ns   338.3uV    1.979mV    176.3uV
50ns      17.52nV    1.263uV    6.475nV
[Falling Waveform]
R_fixture = 50
V_fixture = 1.8
V_fixture_min = 1.66
V_fixture_max = 1.89
| Time   V(typ)   V(min)   V(max)
0s        1.8V       1.66V      1.89V
552.9ps   1.806V     1.66V      1.908V
724.6ps   1.793V     1.663V     1.324V
801ps     1.66V      1.667V     1.01V
899.9ps   1.418V     1.678V     783.6mV
1.125ns   948.4mV    1.53V      639.3mV
1.469ns   796.7mV    1.127V     611.8mV
1.857ns   773mV      981.3mV    610.9mV
2.884ns   772.3mV    945.7mV    611.5mV
50ns      772.4mV    948.4mV    611.3mV
